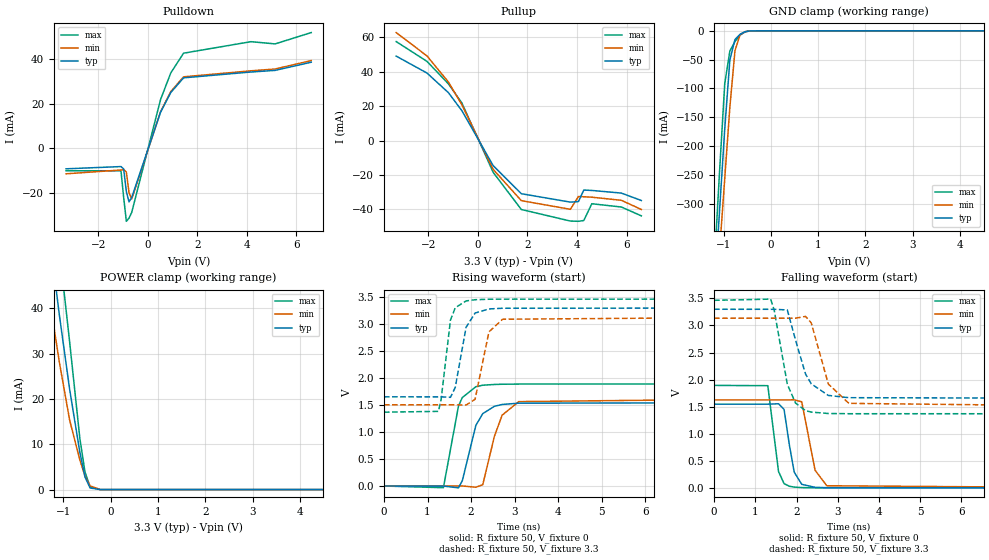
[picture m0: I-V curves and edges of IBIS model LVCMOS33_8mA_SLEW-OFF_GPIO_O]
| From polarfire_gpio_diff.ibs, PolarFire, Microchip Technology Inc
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|   Model LVCMOS33_8mA_SLEW-OFF_GPIO_O
[Model]   LVCMOS33_8mA_SLEW-OFF_GPIO_O
Model_type   Output
Polarity   Non-Inverting
Enable   Active-High
Vmeas =   1.65
Cref =   5p
Rref =   1M
|   typ   min   max
C_comp_pullup   2.605e-12   2.605e-12   2.76e-12
C_comp_pulldown  2.605e-12   2.605e-12   2.76e-12
[Temperature Range]  25C   100C   -40C
[Voltage Range]  3.3   3.135   3.465
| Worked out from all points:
|   slope of the pulldown table from 0 to 0.495 V, typ, clamps not added: 31.7 ohm
|   slope of the pullup table from 0 to 0.495 V, typ, clamps not added: 41.2 ohm
|   GND clamp passes 1 mA (typ) near -0.51 V on its own axis
|   POWER clamp passes 1 mA (typ) near -0.46 V on its own axis
|   rising waveform, R_fixture 50, V_fixture 0: 20-80 % time 318ps typ, 336ps min, 264ps max; typ from 0 V to 1.55 V
|   rising waveform, R_fixture 50, V_fixture 3.3: 20-80 % time 225ps typ, 241ps min, 178ps max; typ from 1.65 V to 3.3 V
|   falling waveform, R_fixture 50, V_fixture 0: 20-80 % time 188ps typ, 224ps min, 151ps max; typ from 1.55 V to 0 V
|   falling waveform, R_fixture 50, V_fixture 3.3: 20-80 % time 392ps typ, 398ps min, 326ps max; typ from 3.3 V to 1.65 V
[GND Clamp]
| Voltage   I(typ)   I(min)   I(max)
-3.3V     -3.213A    -2.957A    -3.541A
-1.191V   -450mA     -505.3mA   -401.1mA
-1.083V   -310.2mA   -380.8mA   -242.7mA
-974.5mV  -170.4mA   -256.4mA   -91.54mA
-866.2mV  -50.48mA   -132.2mA   -34.88mA
-758mV    -15.08mA   -34.24mA   -18.56mA
-649.7mV  -5.883mA   -6.714mA   -7.365mA
-541.4mV  -1.389mA   -1.466mA   -1.709mA
-433.1mV  -123uA     -170uA     -145.5uA
-108.3mV  -6.015nA   -17.98nA   -17.62nA
6.6V      0A         0A         0A
[POWER Clamp]
| Voltage   I(typ)   I(min)   I(max)
-3.3V     320.3mA    266.4mA    379mA
-1.624V   89.11mA    69.3mA     113.8mA
-1.408V   67.23mA    51.37mA    87.82mA
-1.299V   57.08mA    43.14mA    75.67mA
-1.191V   47.51mA    35.38mA    63.94mA
-1.083V   38.51mA    28.09mA    52.96mA
-866.2mV  22.14mA    15.36mA    32.61mA
-649.7mV  8.213mA    6.528mA    11.28mA
-541.4mV  2.791mA    3.019mA    3.88mA
-433.1mV  359.8uA    815.7uA    615.5uA
-216.6mV  159.8nA    4.578uA    2.748uA
6.6V      0A         0A         0A
[Pullup]
| Voltage   I(typ)   I(min)   I(max)
-3.3V     49.01mA    62.7mA     57.45mA
-2.057V   39.19mA    49.12mA    45.97mA
-1.191V   27.78mA    33.97mA    32.88mA
-649.7mV  17.35mA    20.76mA    21.84mA
618.8mV   -14.64mA   -16.83mA   -18.56mA
1.753V    -30.9mA    -34.93mA   -40.07mA
3.733V    -35.78mA   -39.96mA   -46.78mA
4.058V    -35.49mA   -32.52mA   -46.92mA
4.275V    -28.78mA   -32.67mA   -46.46mA
4.599V    -29mA      -32.92mA   -36.72mA
5.79V     -30.53mA   -34.72mA   -38.62mA
6.6V      -34.85mA   -40.05mA   -43.75mA
[Pulldown]
| Voltage   I(typ)   I(min)   I(max)
-3.3V     -9.313mA   -11.56mA   -10.19mA
-1.083V   -8.301mA   -9.851mA   -10.22mA
-974.5mV  -9.371mA   -9.648mA   -22.21mA
-866.2mV  -19.57mA   -10.76mA   -32.96mA
-758mV    -24.21mA   -20.14mA   -31.53mA
-649.7mV  -22.21mA   -22.9mA    -28.95mA
515.6mV   16.17mA    16.44mA    21.91mA
928.1mV   25.06mA    25.48mA    33.89mA
1.444V    31.67mA    32.13mA    42.78mA
4.166V    34.3mA     34.84mA    47.97mA
5.141V    35.03mA    35.65mA    46.96mA
6.6V      38.71mA    39.46mA    52.07mA
[Ramp]
dV/dt_r   0.927342/0.318482n  0.974961/0.335979n  1.13571/0.263616n
dV/dt_f   0.987634/0.391609n  0.977512/0.39781n  1.25749/0.32575n
R_load = 50
[Rising Waveform]
R_fixture = 50
V_fixture = 0
V_fixture_min = 0
V_fixture_max = 0
| Time   V(typ)   V(min)   V(max)
0s        62.35nV    45.17nV    177.2nV
1.365ns   -738.3uV   514.1uV    -30.87mV
1.71ns    -34.06mV   644.1uV    1.48V
1.799ns   99.14mV    677.6uV    1.641V
2.109ns   1.123V     -22.12mV   1.841V
2.268ns   1.342V     23.47mV    1.869V
2.535ns   1.478V     920.8mV    1.883V
2.713ns   1.512V     1.314V     1.887V
3.095ns   1.536V     1.565V     1.89V
10ns      1.546V     1.625V     1.893V
[Rising Waveform]
R_fixture = 50
V_fixture = 3.3
V_fixture_min = 3.135
V_fixture_max = 3.465
| Time   V(typ)   V(min)   V(max)
0s        1.654V     1.506V     1.369V
1.251ns   1.653V     1.505V     1.384V
1.313ns   1.653V     1.505V     1.609V
1.527ns   1.644V     1.505V     3.079V
1.637ns   1.829V     1.505V     3.305V
1.885ns   2.943V     1.501V     3.432V
2.092ns   3.207V     1.608V     3.454V
2.409ns   3.283V     2.857V     3.463V
2.723ns   3.296V     3.092V     3.465V
10ns      3.3V       3.135V     3.465V
[Falling Waveform]
R_fixture = 50
V_fixture = 0
V_fixture_min = 0
V_fixture_max = 0
| Time   V(typ)   V(min)   V(max)
0s        1.546V     1.625V     1.893V
1.304ns   1.546V     1.625V     1.888V
1.563ns   1.554V     1.625V     303.2mV
1.698ns   1.449V     1.625V     78.18mV
1.828ns   786.8mV    1.625V     29.12mV
1.944ns   290.4mV    1.627V     14.71mV
2.127ns   65.05mV    1.59V      5.222mV
2.45ns    10.28mV    325.8mV    1.131mV
2.733ns   2.955mV    38.94mV    638.9uV
10ns      656.8nV    2.264uV    590nV
[Falling Waveform]
R_fixture = 50
V_fixture = 3.3
V_fixture_min = 3.135
V_fixture_max = 3.465
| Time   V(typ)   V(min)   V(max)
0s        3.3V       3.135V     3.465V
1.373ns   3.299V     3.135V     3.487V
1.459ns   3.299V     3.135V     3.281V
1.777ns   3.287V     3.134V     1.914V
1.976ns   2.73V      3.134V     1.567V
2.218ns   2.105V     3.168V     1.427V
2.357ns   1.922V     3.049V     1.4V
2.772ns   1.708V     1.918V     1.374V
3.271ns   1.666V     1.561V     1.37V
10ns      1.654V     1.506V     1.369V
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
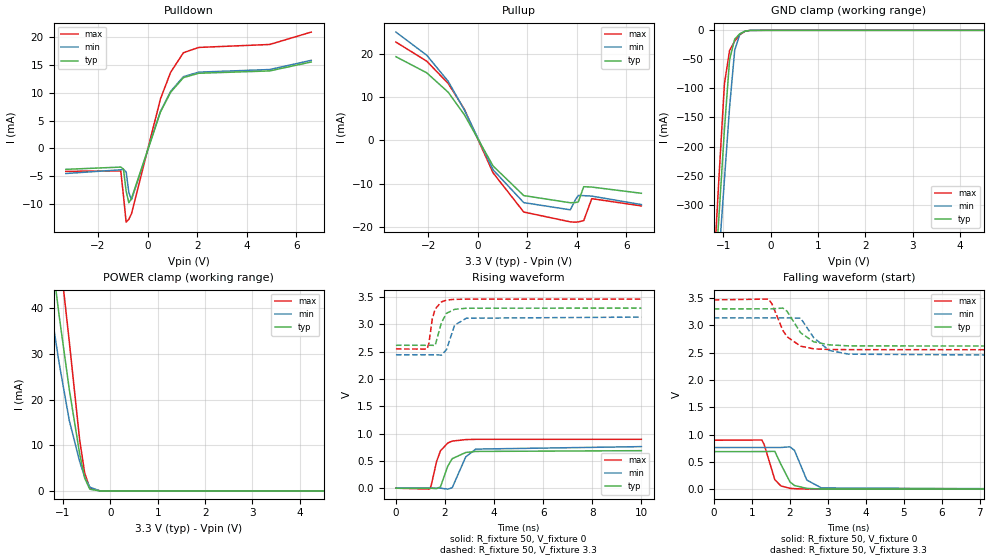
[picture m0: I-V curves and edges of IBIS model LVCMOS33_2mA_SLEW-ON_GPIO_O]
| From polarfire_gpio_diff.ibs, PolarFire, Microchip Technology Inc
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|   Model LVCMOS33_2mA_SLEW-ON_GPIO_O
[Model]   LVCMOS33_2mA_SLEW-ON_GPIO_O
Model_type   Output
Polarity   Non-Inverting
Enable   Active-High
Vmeas =   1.65
Cref =   5p
Rref =   1M
|   typ   min   max
C_comp_pullup   2.605e-12   2.605e-12   2.76e-12
C_comp_pulldown  2.605e-12   2.605e-12   2.76e-12
[Temperature Range]  25C   100C   -40C
[Voltage Range]  3.3   3.135   3.465
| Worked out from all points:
|   slope of the pulldown table from 0 to 0.495 V, typ, clamps not added: 78.7 ohm
|   slope of the pullup table from 0 to 0.495 V, typ, clamps not added: 102 ohm
|   GND clamp passes 1 mA (typ) near -0.51 V on its own axis
|   POWER clamp passes 1 mA (typ) near -0.46 V on its own axis
|   rising waveform, R_fixture 50, V_fixture 0: 20-80 % time 399ps typ, 473ps min, 360ps max; typ from 0 V to 0.688 V
|   rising waveform, R_fixture 50, V_fixture 3.3: 20-80 % time 273ps typ, 326ps min, 232ps max; typ from 2.62 V to 3.3 V
|   falling waveform, R_fixture 50, V_fixture 0: 20-80 % time 283ps typ, 280ps min, 236ps max; typ from 0.688 V to 0 V
|   falling waveform, R_fixture 50, V_fixture 3.3: 20-80 % time 463ps typ, 500ps min, 410ps max; typ from 3.3 V to 2.62 V
[GND Clamp]
| Voltage   I(typ)   I(min)   I(max)
-3.3V     -3.213A    -2.957A    -3.542A
-1.191V   -450mA     -505.3mA   -401.1mA
-1.083V   -310.2mA   -380.8mA   -242.7mA
-974.5mV  -170.4mA   -256.4mA   -91.54mA
-866.2mV  -50.48mA   -132.2mA   -34.88mA
-758mV    -15.08mA   -34.24mA   -18.56mA
-649.7mV  -5.883mA   -6.714mA   -7.365mA
-541.4mV  -1.389mA   -1.466mA   -1.709mA
-433.1mV  -123uA     -170uA     -145.5uA
-108.3mV  -6.015nA   -17.98nA   -17.62nA
6.6V      0A         0A         0A
[POWER Clamp]
| Voltage   I(typ)   I(min)   I(max)
-3.3V     320.3mA    266.4mA    379mA
-1.624V   89.11mA    69.3mA     113.8mA
-1.408V   67.23mA    51.37mA    87.82mA
-1.299V   57.08mA    43.14mA    75.67mA
-1.191V   47.51mA    35.38mA    63.94mA
-1.083V   38.51mA    28.09mA    52.96mA
-866.2mV  22.14mA    15.36mA    32.61mA
-649.7mV  8.213mA    6.528mA    11.28mA
-541.4mV  2.791mA    3.019mA    3.88mA
-433.1mV  359.8uA    815.7uA    615.5uA
-216.6mV  159.8nA    4.578uA    2.748uA
6.6V      0A         0A         0A
[Pullup]
| Voltage   I(typ)   I(min)   I(max)
-3.3V     19.29mA    24.96mA    22.66mA
-2.057V   15.58mA    19.63mA    18.26mA
-1.191V   11.1mA     13.61mA    13.12mA
-541.4mV  5.944mA    7.057mA    7.214mA
618.8mV   -5.885mA   -6.76mA    -7.46mA
1.856V    -12.7mA    -14.32mA   -16.49mA
3.733V    -14.35mA   -15.98mA   -18.75mA
3.95V     -14.29mA   -13.56mA   -18.83mA
4.058V    -14.15mA   -12.66mA   -18.76mA
4.275V    -10.66mA   -12.72mA   -18.48mA
4.599V    -10.74mA   -12.82mA   -13.41mA
6.6V      -12.17mA   -14.77mA   -15.08mA
[Pulldown]
| Voltage   I(typ)   I(min)   I(max)
-3.3V     -3.739mA   -4.486mA   -4.094mA
-1.083V   -3.336mA   -3.821mA   -4.025mA
-974.5mV  -3.682mA   -3.744mA   -8.434mA
-866.2mV  -7.63mA    -4.182mA   -13.21mA
-758mV    -9.724mA   -7.867mA   -12.69mA
-649.7mV  -8.948mA   -9.182mA   -11.69mA
515.6mV   6.515mA    6.609mA    8.847mA
928.1mV   10.07mA    10.23mA    13.65mA
1.444V    12.7mA     12.87mA    17.16mA
2.062V    13.48mA    13.68mA    18.11mA
4.924V    13.9mA     14.15mA    18.64mA
6.6V      15.5mA     15.8mA     20.86mA
[Ramp]
dV/dt_r   0.412647/0.399265n  0.457276/0.472954n  0.537476/0.359539n
dV/dt_f   0.408761/0.462875n  0.413817/0.500078n  0.548246/0.410181n
R_load = 50
[Rising Waveform]
R_fixture = 50
V_fixture = 0
V_fixture_min = 0
V_fixture_max = 0
| Time   V(typ)   V(min)   V(max)
0s        102.4nV    74.63nV    311nV
1.371ns   -716.5uV   730.6uV    -15.41mV
1.436ns   -750.4uV   765.2uV    49.03mV
1.657ns   -7.52mV    883uV      490.1mV
1.816ns   26.15mV    967.7uV    685mV
2.111ns   403.4mV    -17.5mV    827.4mV
2.293ns   541.3mV    8.39mV     863.3mV
2.844ns   654.5mV    573.6mV    890.4mV
3.25ns    673.6mV    716.4mV    895.2mV
10ns      687.7mV    762.1mV    895.8mV
[Rising Waveform]
R_fixture = 50
V_fixture = 3.3
V_fixture_min = 3.135
V_fixture_max = 3.465
| Time   V(typ)   V(min)   V(max)
0s        2.619V     2.445V     2.551V
1.271ns   2.618V     2.445V     2.549V
1.342ns   2.618V     2.445V     2.654V
1.484ns   2.618V     2.445V     3.106V
1.598ns   2.614V     2.445V     3.282V
1.853ns   3.032V     2.438V     3.413V
2.059ns   3.204V     2.537V     3.447V
2.391ns   3.277V     2.987V     3.46V
2.869ns   3.297V     3.114V     3.463V
10ns      3.3V       3.135V     3.465V
[Falling Waveform]
R_fixture = 50
V_fixture = 0
V_fixture_min = 0
V_fixture_max = 0
| Time   V(typ)   V(min)   V(max)
0s        687.8mV    762.1mV    895.8mV
1.265ns   688.1mV    762.7mV    900.6mV
1.326ns   688.1mV    762.7mV    820mV
1.607ns   692.3mV    762.9mV    174.7mV
1.767ns   456mV      762.9mV    59.67mV
2.007ns   133mV      775.3mV    15.15mV
2.126ns   66.81mV    708.9mV    9.027mV
2.45ns    13.8mV     166.7mV    2.02mV
2.835ns   2.742mV    22.68mV    640.7uV
10ns      1.07uV     1.767uV    371nV
[Falling Waveform]
R_fixture = 50
V_fixture = 3.3
V_fixture_min = 3.135
V_fixture_max = 3.465
| Time   V(typ)   V(min)   V(max)
0s        3.3V       3.135V     3.465V
1.446ns   3.301V     3.134V     3.48V
1.537ns   3.301V     3.134V     3.385V
1.819ns   3.315V     3.134V     2.907V
1.929ns   3.258V     3.134V     2.79V
2.287ns   2.863V     3.131V     2.618V
2.629ns   2.698V     2.776V     2.569V
3.034ns   2.642V     2.541V     2.557V
3.555ns   2.623V     2.471V     2.554V
10ns      2.619V     2.445V     2.551V
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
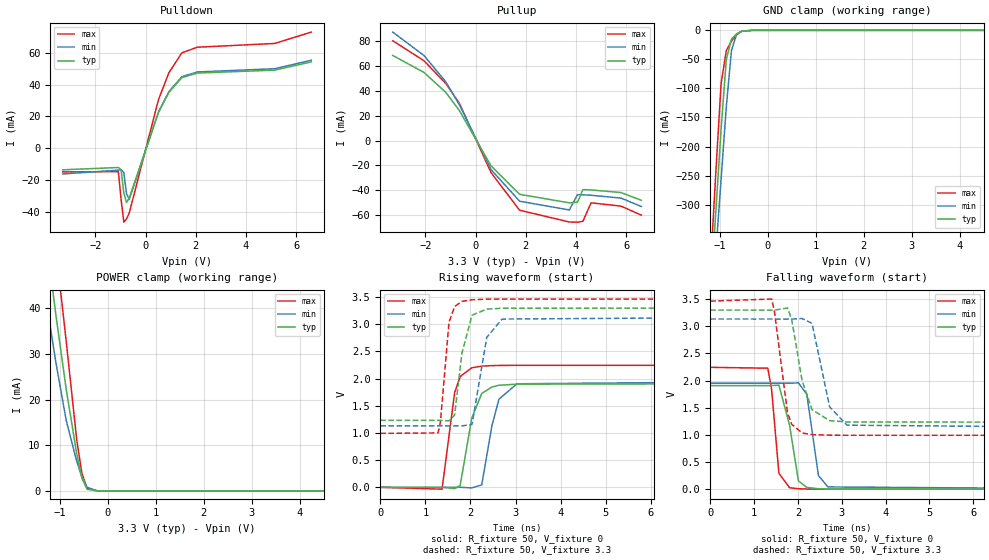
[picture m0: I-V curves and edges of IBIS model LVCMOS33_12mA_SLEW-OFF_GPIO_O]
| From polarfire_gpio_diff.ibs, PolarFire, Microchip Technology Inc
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|   Model LVCMOS33_12mA_SLEW-OFF_GPIO_O
[Model]   LVCMOS33_12mA_SLEW-OFF_GPIO_O
Model_type   Output
Polarity   Non-Inverting
Enable   Active-High
Vmeas =   1.65
Cref =   5p
Rref =   1M
|   typ   min   max
C_comp_pullup   2.605e-12   2.605e-12   2.76e-12
C_comp_pulldown  2.605e-12   2.605e-12   2.76e-12
[Temperature Range]  25C   100C   -40C
[Voltage Range]  3.3   3.135   3.465
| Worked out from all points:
|   slope of the pulldown table from 0 to 0.495 V, typ, clamps not added: 22.7 ohm
|   slope of the pullup table from 0 to 0.495 V, typ, clamps not added: 29.5 ohm
|   GND clamp passes 1 mA (typ) near -0.51 V on its own axis
|   POWER clamp passes 1 mA (typ) near -0.46 V on its own axis
|   rising waveform, R_fixture 50, V_fixture 0: 20-80 % time 270ps typ, 276ps min, 209ps max; typ from 0 V to 1.91 V
|   rising waveform, R_fixture 50, V_fixture 3.3: 20-80 % time 189ps typ, 218ps min, 148ps max; typ from 1.23 V to 3.3 V
|   falling waveform, R_fixture 50, V_fixture 0: 20-80 % time 173ps typ, 186ps min, 132ps max; typ from 1.91 V to 0 V
|   falling waveform, R_fixture 50, V_fixture 3.3: 20-80 % time 308ps typ, 314ps min, 235ps max; typ from 3.3 V to 1.23 V
[GND Clamp]
| Voltage   I(typ)   I(min)   I(max)
-3.3V     -3.213A    -2.957A    -3.541A
-1.191V   -450mA     -505.3mA   -401.1mA
-1.083V   -310.2mA   -380.8mA   -242.7mA
-974.5mV  -170.4mA   -256.4mA   -91.54mA
-866.2mV  -50.48mA   -132.2mA   -34.88mA
-758mV    -15.08mA   -34.24mA   -18.56mA
-649.7mV  -5.883mA   -6.714mA   -7.365mA
-541.4mV  -1.389mA   -1.466mA   -1.709mA
-324.8mV  -3.553uA   -9.504uA   -2.339uA
6.6V      0A         0A         0A
[POWER Clamp]
| Voltage   I(typ)   I(min)   I(max)
-3.3V     320.3mA    266.4mA    379mA
-1.624V   89.11mA    69.3mA     113.8mA
-1.408V   67.23mA    51.37mA    87.82mA
-1.299V   57.08mA    43.14mA    75.67mA
-1.191V   47.51mA    35.38mA    63.94mA
-1.083V   38.51mA    28.09mA    52.96mA
-866.2mV  22.14mA    15.36mA    32.61mA
-649.7mV  8.213mA    6.528mA    11.28mA
-541.4mV  2.791mA    3.019mA    3.88mA
-433.1mV  359.8uA    815.7uA    615.5uA
-216.6mV  159.8nA    4.578uA    2.748uA
6.6V      0A         0A         0A
[Pullup]
| Voltage   I(typ)   I(min)   I(max)
-3.3V     68.42mA    87.18mA    80.23mA
-2.057V   54.76mA    68.39mA    64.18mA
-1.191V   38.81mA    47.31mA    45.9mA
-649.7mV  24.23mA    28.92mA    30.11mA
618.8mV   -20.47mA   -23.48mA   -25.92mA
1.753V    -43.26mA   -48.82mA   -56.06mA
3.733V    -50.12mA   -55.85mA   -65.53mA
4.058V    -49.66mA   -43.55mA   -65.69mA
4.275V    -39.44mA   -43.7mA    -64.96mA
4.599V    -39.74mA   -44.03mA   -50.13mA
5.79V     -41.86mA   -46.3mA    -52.75mA
6.6V      -48.08mA   -53.08mA   -60.03mA
[Pulldown]
| Voltage   I(typ)   I(min)   I(max)
-3.3V     -13.44mA   -16.05mA   -14.79mA
-1.083V   -11.99mA   -13.66mA   -14.59mA
-974.5mV  -13.34mA   -13.38mA   -32.1mA
-866.2mV  -27.94mA   -15.21mA   -46.26mA
-758mV    -33.94mA   -28.44mA   -44.16mA
-649.7mV  -31.06mA   -31.93mA   -40.49mA
515.6mV   22.6mA     22.9mA     30.59mA
928.1mV   35.04mA    35.56mA    47.37mA
1.444V    44.32mA    44.91mA    59.85mA
2.062V    47.18mA    47.87mA    63.37mA
5.141V    49.02mA    49.9mA     65.72mA
6.6V      54.17mA    55.21mA    72.85mA
[Ramp]
dV/dt_r   1.14514/0.269635n  1.17099/0.275885n  1.34717/0.208871n
dV/dt_f   1.2401/0.307596n  1.20209/0.314226n  1.4832/0.235259n
R_load = 50
[Rising Waveform]
R_fixture = 50
V_fixture = 0
V_fixture_min = 0
V_fixture_max = 0
| Time   V(typ)   V(min)   V(max)
0s        49.37nV    35.83nV    137.3nV
1.37ns    745.1uV    596.8uV    -34.01mV
1.65ns    -24.49mV   718.8uV    1.745V
1.772ns   33.39mV    771.9uV    2.037V
2.028ns   1.269V     -10.58mV   2.2V
2.25ns    1.727V     44.1mV     2.231V
2.476ns   1.847V     1.132V     2.24V
2.633ns   1.878V     1.623V     2.243V
3.033ns   1.899V     1.906V     2.245V
10ns      1.909V     1.952V     2.245V
[Rising Waveform]
R_fixture = 50
V_fixture = 3.3
V_fixture_min = 3.135
V_fixture_max = 3.465
| Time   V(typ)   V(min)   V(max)
0s        1.233V     1.132V     993mV
1.281ns   1.233V     1.131V     1.001V
1.334ns   1.233V     1.131V     1.202V
1.524ns   1.223V     1.131V     3.036V
1.649ns   1.33V      1.131V     3.328V
1.811ns   2.47V      1.131V     3.422V
2.035ns   3.168V     1.157V     3.453V
2.363ns   3.28V      2.762V     3.463V
2.703ns   3.296V     3.097V     3.465V
10ns      3.3V       3.135V     3.465V
[Falling Waveform]
R_fixture = 50
V_fixture = 0
V_fixture_min = 0
V_fixture_max = 0
| Time   V(typ)   V(min)   V(max)
0s        1.909V     1.952V     2.245V
1.312ns   1.909V     1.952V     2.229V
1.399ns   1.909V     1.952V     1.841V
1.566ns   1.916V     1.952V     292.3mV
1.809ns   1.18V      1.952V     26.61mV
2.011ns   153.1mV    1.959V     8.174mV
2.202ns   32.84mV    1.749V     2.932mV
2.469ns   7.596mV    249.5mV    774.9uV
2.684ns   2.543mV    41.37mV    448.3uV
10ns      103.8nV    2.746uV    311.7nV
[Falling Waveform]
R_fixture = 50
V_fixture = 3.3
V_fixture_min = 3.135
V_fixture_max = 3.465
| Time   V(typ)   V(min)   V(max)
0s        3.3V       3.135V     3.465V
1.399ns   3.299V     3.135V     3.503V
1.462ns   3.299V     3.135V     3.286V
1.762ns   3.339V     3.134V     1.407V
1.857ns   3.13V      3.134V     1.197V
2.095ns   2V         3.144V     1.035V
2.321ns   1.465V     3.056V     1.005V
2.724ns   1.263V     1.517V     994.6mV
3.12ns    1.238V     1.179V     993.4mV
10ns      1.233V     1.132V     993mV
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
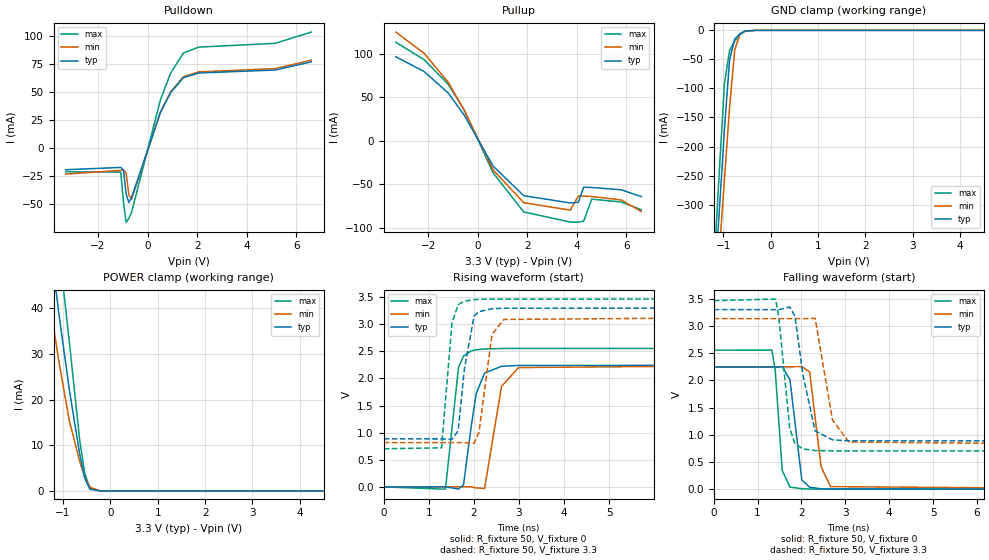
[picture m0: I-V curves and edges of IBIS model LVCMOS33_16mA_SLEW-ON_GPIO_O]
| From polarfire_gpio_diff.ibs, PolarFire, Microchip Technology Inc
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|   Model LVCMOS33_16mA_SLEW-ON_GPIO_O
[Model]   LVCMOS33_16mA_SLEW-ON_GPIO_O
Model_type   Output
Polarity   Non-Inverting
Enable   Active-High
Vmeas =   1.65
Cref =   5p
Rref =   1M
|   typ   min   max
C_comp_pullup   2.605e-12   2.605e-12   2.76e-12
C_comp_pulldown  2.605e-12   2.605e-12   2.76e-12
[Temperature Range]  25C   100C   -40C
[Voltage Range]  3.3   3.135   3.465
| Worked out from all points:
|   slope of the pulldown table from 0 to 0.495 V, typ, clamps not added: 16 ohm
|   slope of the pullup table from 0 to 0.495 V, typ, clamps not added: 20.7 ohm
|   GND clamp passes 1 mA (typ) near -0.51 V on its own axis
|   POWER clamp passes 1 mA (typ) near -0.46 V on its own axis
|   rising waveform, R_fixture 50, V_fixture 0: 20-80 % time 230ps typ, 244ps min, 173ps max; typ from 0 V to 2.25 V
|   rising waveform, R_fixture 50, V_fixture 3.3: 20-80 % time 178ps typ, 209ps min, 135ps max; typ from 0.886 V to 3.3 V
|   falling waveform, R_fixture 50, V_fixture 0: 20-80 % time 161ps typ, 179ps min, 123ps max; typ from 2.25 V to 0 V
|   falling waveform, R_fixture 50, V_fixture 3.3: 20-80 % time 266ps typ, 274ps min, 196ps max; typ from 3.3 V to 0.886 V
[GND Clamp]
| Voltage   I(typ)   I(min)   I(max)
-3.3V     -3.213A    -2.957A    -3.541A
-1.191V   -450mA     -505.3mA   -401.1mA
-1.083V   -310.2mA   -380.8mA   -242.7mA
-974.5mV  -170.4mA   -256.4mA   -91.54mA
-866.2mV  -50.48mA   -132.2mA   -34.88mA
-758mV    -15.08mA   -34.24mA   -18.56mA
-649.7mV  -5.883mA   -6.714mA   -7.365mA
-541.4mV  -1.389mA   -1.466mA   -1.709mA
-324.8mV  -3.553uA   -9.504uA   -2.339uA
6.6V      0A         0A         0A
[POWER Clamp]
| Voltage   I(typ)   I(min)   I(max)
-3.3V     320.3mA    266.4mA    379mA
-1.624V   89.11mA    69.3mA     113.8mA
-1.408V   67.23mA    51.37mA    87.82mA
-1.299V   57.08mA    43.14mA    75.67mA
-1.191V   47.51mA    35.38mA    63.94mA
-1.083V   38.51mA    28.09mA    52.96mA
-866.2mV  22.14mA    15.36mA    32.61mA
-649.7mV  8.213mA    6.528mA    11.28mA
-541.4mV  2.791mA    3.019mA    3.88mA
-433.1mV  359.8uA    815.7uA    615.5uA
-216.6mV  159.8nA    4.578uA    2.748uA
6.6V      0A         0A         0A
[Pullup]
| Voltage   I(typ)   I(min)   I(max)
-3.3V     96.7mA     125.2mA    113.4mA
-2.166V   79.86mA    100.8mA    93.52mA
-1.191V   55.09mA    67.49mA    65.08mA
-541.4mV  29.35mA    34.82mA    35.58mA
618.8mV   -29.1mA    -33.44mA   -36.81mA
1.856V    -63.18mA   -71.27mA   -81.97mA
3.733V    -71.56mA   -79.83mA   -93.56mA
4.058V    -70.72mA   -63.48mA   -93.7mA
4.275V    -53.34mA   -63.65mA   -92.41mA
4.599V    -53.73mA   -64.14mA   -67.18mA
5.79V     -56.41mA   -68.09mA   -70.43mA
6.6V      -64.26mA   -81.41mA   -79.35mA
[Pulldown]
| Voltage   I(typ)   I(min)   I(max)
-3.3V     -18.99mA   -22.92mA   -20.85mA
-1.083V   -16.93mA   -19.5mA    -21.14mA
-974.5mV  -19.39mA   -19.1mA    -48.03mA
-866.2mV  -40.74mA   -22.19mA   -65.83mA
-758mV    -48.24mA   -41.22mA   -62.64mA
-649.7mV  -44.03mA   -45.38mA   -57.29mA
515.6mV   32.05mA    32.51mA    43.27mA
928.1mV   49.81mA    50.58mA    67.21mA
1.444V    63.16mA    64.03mA    85.24mA
2.062V    67.38mA    68.37mA    90.49mA
5.141V    70mA       71.26mA    93.83mA
6.6V      77.31mA    78.8mA     103.9mA
[Ramp]
dV/dt_r   1.34716/0.230165n  1.34924/0.244377n  1.53255/0.172818n
dV/dt_f   1.44849/0.266104n  1.39083/0.274235n  1.6572/0.196047n
R_load = 50
[Rising Waveform]
R_fixture = 50
V_fixture = 0
V_fixture_min = 0
V_fixture_max = 0
| Time   V(typ)   V(min)   V(max)
0s        37.81nV    27.39nV    103.5nV
1.37ns    944.4uV    579.7uV    -42.35mV
1.66ns    -40.3mV    702.3uV    2.201V
1.771ns   37.72mV    749.3uV    2.412V
1.94ns    1.105V     461.7uV    2.508V
2.053ns   1.722V     -18.75mV   2.53V
2.238ns   2.099V     -30.37mV   2.545V
2.615ns   2.224V     1.857V     2.553V
2.994ns   2.24V      2.201V     2.554V
10ns      2.245V     2.249V     2.554V
[Rising Waveform]
R_fixture = 50
V_fixture = 3.3
V_fixture_min = 3.135
V_fixture_max = 3.465
| Time   V(typ)   V(min)   V(max)
0s        885.8mV    817mV      703mV
1.284ns   885.1mV    816.7mV    719.8mV
1.516ns   876.8mV    816.7mV    3.028V
1.653ns   1.035V     816.6mV    3.361V
1.79ns    2.172V     816.6mV    3.427V
2.006ns   3.155V     805.9mV    3.454V
2.113ns   3.232V     1.002V     3.459V
2.403ns   3.287V     2.811V     3.464V
2.666ns   3.296V     3.089V     3.464V
10ns      3.3V       3.135V     3.465V
[Falling Waveform]
R_fixture = 50
V_fixture = 0
V_fixture_min = 0
V_fixture_max = 0
| Time   V(typ)   V(min)   V(max)
0s        2.245V     2.249V     2.554V
1.325ns   2.246V     2.249V     2.556V
1.4ns     2.246V     2.249V     2.196V
1.561ns   2.249V     2.249V     341.9mV
1.737ns   2.011V     2.249V     39.05mV
2.007ns   170.1mV    2.254V     7.105mV
2.186ns   34.86mV    2.154V     2.705mV
2.447ns   7.891mV    411.7mV    568.6uV
2.663ns   2.915mV    47.49mV    552.4uV
10ns      495.6nV    3.025uV    478.9nV
[Falling Waveform]
R_fixture = 50
V_fixture = 3.3
V_fixture_min = 3.135
V_fixture_max = 3.465
| Time   V(typ)   V(min)   V(max)
0s        3.3V       3.135V     3.465V
1.408ns   3.299V     3.134V     3.494V
1.484ns   3.299V     3.134V     3.149V
1.731ns   3.349V     3.134V     1.124V
1.849ns   3.182V     3.134V     836.7mV
2.036ns   2.087V     3.133V     737.9mV
2.311ns   1.072V     3.141V     710.6mV
2.707ns   906.1mV    1.272V     703.9mV
3.078ns   889.6mV    866.7mV    703.1mV
10ns      885.8mV    817mV      703mV
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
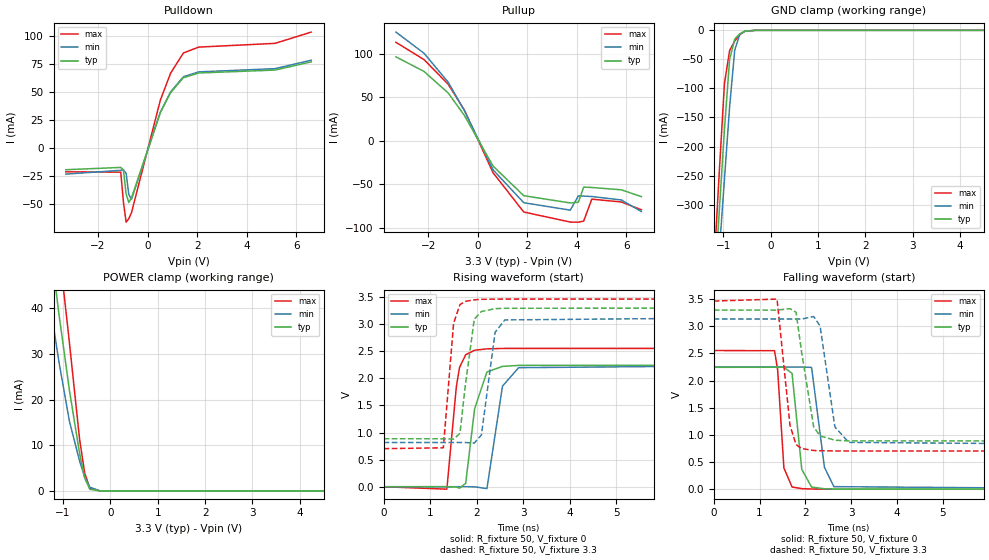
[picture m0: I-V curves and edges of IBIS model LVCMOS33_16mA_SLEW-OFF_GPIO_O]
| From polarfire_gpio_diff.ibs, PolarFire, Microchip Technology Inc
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|   Model LVCMOS33_16mA_SLEW-OFF_GPIO_O
[Model]   LVCMOS33_16mA_SLEW-OFF_GPIO_O
Model_type   Output
Polarity   Non-Inverting
Enable   Active-High
Vmeas =   1.65
Cref =   5p
Rref =   1M
|   typ   min   max
C_comp_pullup   2.605e-12   2.605e-12   2.76e-12
C_comp_pulldown  2.605e-12   2.605e-12   2.76e-12
[Temperature Range]  25C   100C   -40C
[Voltage Range]  3.3   3.135   3.465
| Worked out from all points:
|   slope of the pulldown table from 0 to 0.495 V, typ, clamps not added: 16 ohm
|   slope of the pullup table from 0 to 0.495 V, typ, clamps not added: 20.7 ohm
|   GND clamp passes 1 mA (typ) near -0.51 V on its own axis
|   POWER clamp passes 1 mA (typ) near -0.46 V on its own axis
|   rising waveform, R_fixture 50, V_fixture 0: 20-80 % time 208ps typ, 216ps min, 158ps max; typ from 0 V to 2.25 V
|   rising waveform, R_fixture 50, V_fixture 3.3: 20-80 % time 164ps typ, 192ps min, 123ps max; typ from 0.886 V to 3.3 V
|   falling waveform, R_fixture 50, V_fixture 0: 20-80 % time 144ps typ, 154ps min, 109ps max; typ from 2.25 V to 0 V
|   falling waveform, R_fixture 50, V_fixture 3.3: 20-80 % time 230ps typ, 225ps min, 171ps max; typ from 3.3 V to 0.886 V
[GND Clamp]
| Voltage   I(typ)   I(min)   I(max)
-3.3V     -3.213A    -2.957A    -3.541A
-1.191V   -450mA     -505.3mA   -401.1mA
-1.083V   -310.2mA   -380.8mA   -242.7mA
-974.5mV  -170.4mA   -256.4mA   -91.54mA
-866.2mV  -50.48mA   -132.2mA   -34.88mA
-758mV    -15.08mA   -34.24mA   -18.56mA
-649.7mV  -5.883mA   -6.714mA   -7.365mA
-541.4mV  -1.389mA   -1.466mA   -1.709mA
-324.8mV  -3.553uA   -9.504uA   -2.339uA
6.6V      0A         0A         0A
[POWER Clamp]
| Voltage   I(typ)   I(min)   I(max)
-3.3V     320.3mA    266.4mA    379mA
-1.624V   89.11mA    69.3mA     113.8mA
-1.408V   67.23mA    51.37mA    87.82mA
-1.299V   57.08mA    43.14mA    75.67mA
-1.191V   47.51mA    35.38mA    63.94mA
-1.083V   38.51mA    28.09mA    52.96mA
-866.2mV  22.14mA    15.36mA    32.61mA
-649.7mV  8.213mA    6.528mA    11.28mA
-541.4mV  2.791mA    3.019mA    3.88mA
-433.1mV  359.8uA    815.7uA    615.5uA
-216.6mV  159.8nA    4.578uA    2.748uA
6.6V      0A         0A         0A
[Pullup]
| Voltage   I(typ)   I(min)   I(max)
-3.3V     96.7mA     125.2mA    113.4mA
-2.166V   79.86mA    100.8mA    93.52mA
-1.191V   55.09mA    67.49mA    65.08mA
-541.4mV  29.35mA    34.82mA    35.58mA
618.8mV   -29.1mA    -33.44mA   -36.81mA
1.856V    -63.18mA   -71.27mA   -81.97mA
3.733V    -71.56mA   -79.83mA   -93.56mA
4.058V    -70.72mA   -63.48mA   -93.7mA
4.275V    -53.34mA   -63.65mA   -92.41mA
4.599V    -53.73mA   -64.14mA   -67.18mA
5.79V     -56.41mA   -68.09mA   -70.43mA
6.6V      -64.26mA   -81.41mA   -79.35mA
[Pulldown]
| Voltage   I(typ)   I(min)   I(max)
-3.3V     -18.99mA   -22.92mA   -20.85mA
-1.083V   -16.93mA   -19.5mA    -21.14mA
-974.5mV  -19.39mA   -19.1mA    -48.03mA
-866.2mV  -40.74mA   -22.19mA   -65.83mA
-758mV    -48.24mA   -41.22mA   -62.64mA
-649.7mV  -44.03mA   -45.38mA   -57.29mA
515.6mV   32.05mA    32.51mA    43.27mA
928.1mV   49.81mA    50.58mA    67.21mA
1.444V    63.16mA    64.03mA    85.24mA
2.062V    67.38mA    68.37mA    90.49mA
5.141V    70mA       71.26mA    93.83mA
6.6V      77.31mA    78.8mA     103.9mA
[Ramp]
dV/dt_r   1.34716/0.207758n  1.34924/0.216075n  1.53255/0.157665n
dV/dt_f   1.44849/0.23043n  1.39083/0.225333n  1.6572/0.171415n
R_load = 50
[Rising Waveform]
R_fixture = 50
V_fixture = 0
V_fixture_min = 0
V_fixture_max = 0
| Time   V(typ)   V(min)   V(max)
0s        37.81nV    27.38nV    103.5nV
1.357ns   856uV      527.6uV    -45.04mV
1.561ns   -5.681mV   606.9uV    1.845V
1.629ns   -26.34mV   633.4uV    2.201V
1.762ns   64.19mV    685.1uV    2.437V
1.954ns   1.44V      -1.376mV   2.52V
2.218ns   2.119V     -35.53mV   2.546V
2.552ns   2.222V     1.858V     2.553V
2.899ns   2.24V      2.198V     2.554V
10ns      2.245V     2.249V     2.554V
[Rising Waveform]
R_fixture = 50
V_fixture = 3.3
V_fixture_min = 3.135
V_fixture_max = 3.465
| Time   V(typ)   V(min)   V(max)
0s        885.8mV    817mV      703mV
1.282ns   885.2mV    816.8mV    718.4mV
1.502ns   879.6mV    816.7mV    3.019V
1.639ns   985.8mV    816.7mV    3.363V
1.75ns    1.846V     816.7mV    3.421V
1.947ns   3.094V     806.1mV    3.451V
2.099ns   3.235V     955.3mV    3.46V
2.394ns   3.288V     2.853V     3.464V
2.603ns   3.295V     3.08V      3.465V
10ns      3.3V       3.135V     3.465V
[Falling Waveform]
R_fixture = 50
V_fixture = 0
V_fixture_min = 0
V_fixture_max = 0
| Time   V(typ)   V(min)   V(max)
0s        2.245V     2.249V     2.554V
1.327ns   2.246V     2.249V     2.551V
1.395ns   2.246V     2.249V     2.199V
1.532ns   2.246V     2.249V     391.7mV
1.71ns    2.133V     2.249V     39.3mV
1.922ns   366.7mV    2.249V     9.76mV
2.137ns   38.29mV    2.243V     2.945mV
2.417ns   7.519mV    404mV      672.7uV
2.623ns   2.925mV    46.61mV    547uV
10ns      69.69nV    364nV      208.9nV
[Falling Waveform]
R_fixture = 50
V_fixture = 3.3
V_fixture_min = 3.135
V_fixture_max = 3.465
| Time   V(typ)   V(min)   V(max)
0s        3.3V       3.135V     3.465V
1.382ns   3.299V     3.134V     3.502V
1.666ns   3.325V     3.134V     1.17V
1.798ns   3.257V     3.134V     821.8mV
1.919ns   2.523V     3.134V     748.4mV
2.182ns   1.149V     3.18V      712.9mV
2.322ns   981.6mV    3.008V     707.3mV
2.646ns   901.7mV    1.146V     704.1mV
2.949ns   889.4mV    861.3mV    703.2mV
10ns      885.9mV    817mV      703mV
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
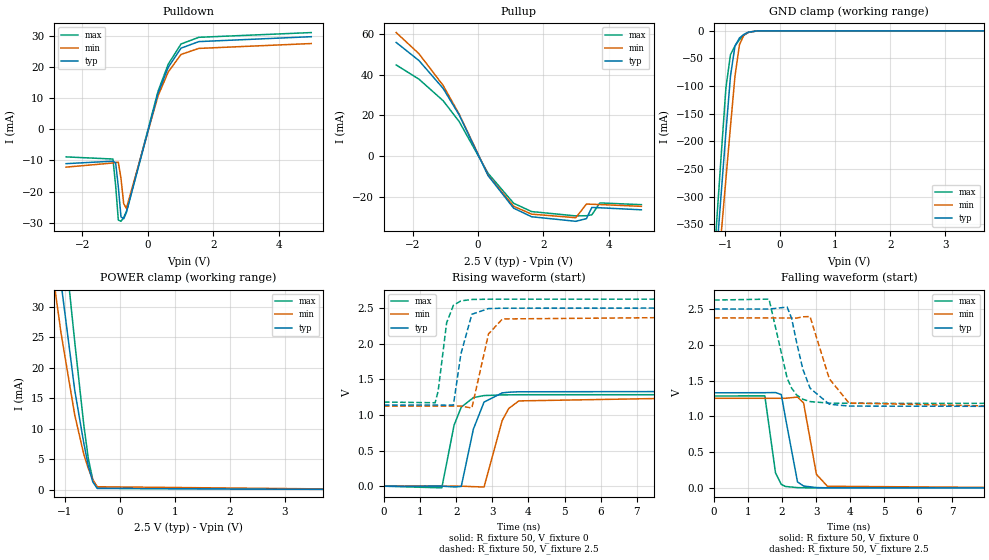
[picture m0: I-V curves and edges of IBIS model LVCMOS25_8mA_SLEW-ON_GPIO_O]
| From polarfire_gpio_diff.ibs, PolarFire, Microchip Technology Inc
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|   Model LVCMOS25_8mA_SLEW-ON_GPIO_O
[Model]   LVCMOS25_8mA_SLEW-ON_GPIO_O
Model_type   Output
Polarity   Non-Inverting
Enable   Active-High
Vmeas =   1.25
Cref =   5p
Rref =   1M
|   typ   min   max
C_comp_pullup   2.605e-12   2.605e-12   2.76e-12
C_comp_pulldown  2.605e-12   2.605e-12   2.76e-12
[Temperature Range]  25C   100C   -40C
[Voltage Range]  2.5   2.375   2.625
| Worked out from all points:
|   slope of the pulldown table from 0 to 0.375 V, typ, clamps not added: 27.6 ohm
|   slope of the pullup table from 0 to 0.375 V, typ, clamps not added: 33.1 ohm
|   GND clamp passes 1 mA (typ) near -0.51 V on its own axis
|   POWER clamp passes 1 mA (typ) near -0.47 V on its own axis
|   rising waveform, R_fixture 50, V_fixture 0: 20-80 % time 368ps typ, 418ps min, 339ps max; typ from 0 V to 1.33 V
|   rising waveform, R_fixture 50, V_fixture 2.5: 20-80 % time 252ps typ, 298ps min, 222ps max; typ from 1.14 V to 2.5 V
|   falling waveform, R_fixture 50, V_fixture 0: 20-80 % time 243ps typ, 266ps min, 193ps max; typ from 1.33 V to 0 V
|   falling waveform, R_fixture 50, V_fixture 2.5: 20-80 % time 455ps typ, 526ps min, 423ps max; typ from 2.5 V to 1.14 V
[GND Clamp]
| Voltage   I(typ)   I(min)   I(max)
-2.5V     -2.154A    -2.019A    -2.334A
-1.23V    -500.9mA   -550.5mA   -458.7mA
-1.148V   -394.9mA   -456.3mA   -338.7mA
-1.066V   -289mA     -362mA     -218.7mA
-984.4mV  -183.1mA   -267.7mA   -102.9mA
-902.3mV  -82.21mA   -173.6mA   -43.25mA
-820.3mV  -27.37mA   -82.26mA   -27.26mA
-738.3mV  -12.87mA   -24.95mA   -16.13mA
-656.2mV  -6.285mA   -7.324mA   -7.886mA
-574.2mV  -2.342mA   -2.429mA   -2.872mA
-410.2mV  -62.85uA   -96.5uA    -70.85uA
5V        0A         0A         0A
[POWER Clamp]
| Voltage   I(typ)   I(min)   I(max)
-2.5V     191.3mA    155.6mA    232.6mA
-1.559V   79.6mA     61.42mA    102.5mA
-1.395V   63.37mA    48.38mA    82.85mA
-1.23V    48.04mA    36.4mA     63.67mA
-1.148V   40.77mA    30.8mA     54.53mA
-1.066V   33.71mA    25.51mA    45.88mA
-820.3mV  16.31mA    12.25mA    24.25mA
-656.2mV  7.665mA    5.818mA    10.67mA
-574.2mV  3.929mA    3.48mA     5.131mA
-492.2mV  1.272mA    1.622mA    1.634mA
-410.2mV  189.8uA    467.6uA    244.4uA
5V        0A         0A         0A
[Pullup]
| Voltage   I(typ)   I(min)   I(max)
-2.5V     55.91mA    60.77mA    44.83mA
-1.805V   47.01mA    50.38mA    37.85mA
-1.066V   33.32mA    34.79mA    27.27mA
-574.2mV  20.24mA    20.66mA    17mA
312.5mV   -9.641mA   -9.429mA   -8.538mA
1.094V    -25.65mA   -24.7mA    -23.22mA
1.641V    -29.85mA   -28.56mA   -27.3mA
2.992V    -32.09mA   -30.33mA   -29.44mA
3.32V     -30.78mA   -23.62mA   -29.34mA
3.484V    -25.28mA   -23.71mA   -28.91mA
3.73V     -25.43mA   -23.85mA   -23.05mA
5V        -26.43mA   -24.73mA   -23.91mA
[Pulldown]
| Voltage   I(typ)   I(min)   I(max)
-2.5V     -11.02mA   -12.14mA   -8.839mA
-1.066V   -10.22mA   -10.81mA   -9.527mA
-984.4mV  -10.71mA   -10.64mA   -18.02mA
-902.3mV  -18.47mA   -10.56mA   -29.2mA
-820.3mV  -28.16mA   -15.77mA   -29.61mA
-738.3mV  -28.81mA   -23.87mA   -28.35mA
-656.2mV  -26.81mA   -25.47mA   -26.55mA
312.5mV   11.69mA    10.82mA    12.3mA
625mV     20.03mA    18.54mA    21.05mA
1.016V    26.23mA    24.21mA    27.58mA
1.562V    28.35mA    26.15mA    29.73mA
5V        29.93mA    27.72mA    31.26mA
[Ramp]
dV/dt_r   0.797444/0.367991n  0.751478/0.418358n  0.77066/0.33857n
dV/dt_f   0.81699/0.454794n  0.750748/0.525515n  0.8661/0.422935n
R_load = 50
[Rising Waveform]
R_fixture = 50
V_fixture = 0
V_fixture_min = 0
V_fixture_max = 0
| Time   V(typ)   V(min)   V(max)
0s        15.23nV    28.08nV    19.41nV
1.602ns   699.1uV    571.7uV    -23.07mV
1.942ns   -10.02mV   693.1uV    855.8mV
2.141ns   -3.195mV   764.1uV    1.11V
2.477ns   801.6mV    -6.38mV    1.243V
2.772ns   1.181V     -10.89mV   1.272V
3.273ns   1.309V     920.4mV    1.281V
3.457ns   1.319V     1.091V     1.282V
3.734ns   1.325V     1.197V     1.284V
10ns      1.329V     1.252V     1.284V
[Rising Waveform]
R_fixture = 50
V_fixture = 2.5
V_fixture_min = 2.375
V_fixture_max = 2.625
| Time   V(typ)   V(min)   V(max)
0s        1.138V     1.124V     1.181V
1.418ns   1.139V     1.124V     1.171V
1.501ns   1.139V     1.124V     1.336V
1.736ns   1.137V     1.125V     2.293V
1.923ns   1.138V     1.125V     2.538V
2.13ns    1.854V     1.125V     2.6V
2.434ns   2.413V     1.097V     2.62V
2.895ns   2.492V     2.136V     2.624V
3.281ns   2.498V     2.347V     2.624V
10ns      2.5V       2.375V     2.625V
[Falling Waveform]
R_fixture = 50
V_fixture = 0
V_fixture_min = 0
V_fixture_max = 0
| Time   V(typ)   V(min)   V(max)
0s        1.329V     1.252V     1.284V
1.493ns   1.33V      1.252V     1.286V
1.807ns   1.332V     1.252V     209.5mV
1.977ns   1.304V     1.252V     48.67mV
2.099ns   981.6mV    1.252V     19.43mV
2.454ns   82.84mV    1.269V     3.208mV
2.633ns   25.59mV    1.186V     1.17mV
3.011ns   4.101mV    189.1mV    455.1uV
3.334ns   995uV      22.19mV    434.1uV
10ns      1.624uV    3.15uV     481.8nV
[Falling Waveform]
R_fixture = 50
V_fixture = 2.5
V_fixture_min = 2.375
V_fixture_max = 2.625
| Time   V(typ)   V(min)   V(max)
0s        2.5V       2.375V     2.625V
1.617ns   2.499V     2.375V     2.638V
2.149ns   2.527V     2.374V     1.533V
2.281ns   2.37V      2.374V     1.394V
2.429ns   2.031V     2.373V     1.298V
2.611ns   1.659V     2.391V     1.239V
2.823ns   1.393V     2.394V     1.206V
3.39ns    1.169V     1.525V     1.184V
3.966ns   1.143V     1.186V     1.182V
10ns      1.138V     1.124V     1.181V
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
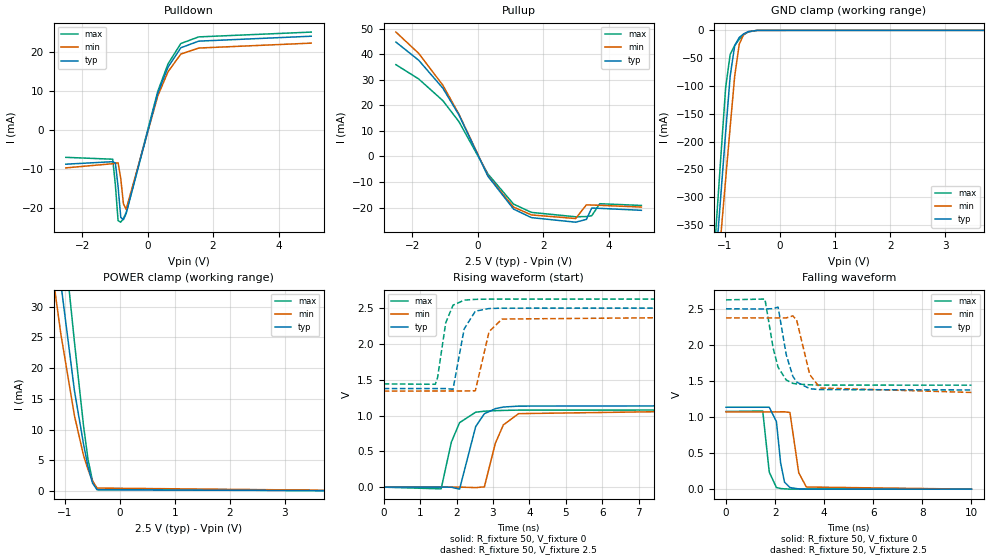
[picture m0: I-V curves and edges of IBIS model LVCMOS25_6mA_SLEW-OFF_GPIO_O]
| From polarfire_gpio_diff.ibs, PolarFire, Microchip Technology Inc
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|   Model LVCMOS25_6mA_SLEW-OFF_GPIO_O
[Model]   LVCMOS25_6mA_SLEW-OFF_GPIO_O
Model_type   Output
Polarity   Non-Inverting
Enable   Active-High
Vmeas =   1.25
Cref =   5p
Rref =   1M
|   typ   min   max
C_comp_pullup   2.605e-12   2.605e-12   2.76e-12
C_comp_pulldown  2.605e-12   2.605e-12   2.76e-12
[Temperature Range]  25C   100C   -40C
[Voltage Range]  2.5   2.375   2.625
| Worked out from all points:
|   slope of the pulldown table from 0 to 0.375 V, typ, clamps not added: 34.4 ohm
|   slope of the pullup table from 0 to 0.375 V, typ, clamps not added: 41.3 ohm
|   GND clamp passes 1 mA (typ) near -0.51 V on its own axis
|   POWER clamp passes 1 mA (typ) near -0.47 V on its own axis
|   rising waveform, R_fixture 50, V_fixture 0: 20-80 % time 362ps typ, 393ps min, 336ps max; typ from 0 V to 1.14 V
|   rising waveform, R_fixture 50, V_fixture 2.5: 20-80 % time 246ps typ, 271ps min, 224ps max; typ from 1.38 V to 2.5 V
|   falling waveform, R_fixture 50, V_fixture 0: 20-80 % time 219ps typ, 261ps min, 181ps max; typ from 1.14 V to 0 V
|   falling waveform, R_fixture 50, V_fixture 2.5: 20-80 % time 404ps typ, 479ps min, 402ps max; typ from 2.5 V to 1.38 V
[GND Clamp]
| Voltage   I(typ)   I(min)   I(max)
-2.5V     -2.154A    -2.019A    -2.334A
-1.23V    -500.9mA   -550.5mA   -458.7mA
-1.148V   -394.9mA   -456.3mA   -338.7mA
-1.066V   -289mA     -362mA     -218.7mA
-984.4mV  -183.1mA   -267.7mA   -102.9mA
-902.3mV  -82.21mA   -173.6mA   -43.25mA
-820.3mV  -27.37mA   -82.26mA   -27.26mA
-738.3mV  -12.87mA   -24.95mA   -16.13mA
-656.2mV  -6.285mA   -7.324mA   -7.886mA
-574.2mV  -2.342mA   -2.429mA   -2.872mA
-410.2mV  -62.85uA   -96.5uA    -70.85uA
5V        0A         0A         0A
[POWER Clamp]
| Voltage   I(typ)   I(min)   I(max)
-2.5V     191.3mA    155.6mA    232.6mA
-1.559V   79.6mA     61.42mA    102.5mA
-1.395V   63.37mA    48.38mA    82.85mA
-1.23V    48.04mA    36.4mA     63.67mA
-1.148V   40.77mA    30.8mA     54.53mA
-1.066V   33.71mA    25.51mA    45.88mA
-820.3mV  16.31mA    12.25mA    24.25mA
-656.2mV  7.665mA    5.818mA    10.67mA
-574.2mV  3.929mA    3.48mA     5.131mA
-492.2mV  1.272mA    1.622mA    1.634mA
-410.2mV  189.8uA    467.6uA    244.4uA
5V        0A         0A         0A
[Pullup]
| Voltage   I(typ)   I(min)   I(max)
-2.5V     44.71mA    48.61mA    35.88mA
-1.805V   37.62mA    40.31mA    30.3mA
-1.066V   26.69mA    27.85mA    21.83mA
-574.2mV  16.22mA    16.54mA    13.61mA
312.5mV   -7.724mA   -7.548mA   -6.839mA
1.094V    -20.54mA   -19.76mA   -18.59mA
1.641V    -23.89mA   -22.83mA   -21.84mA
2.992V    -25.67mA   -24.24mA   -23.56mA
3.32V     -24.58mA   -18.89mA   -23.47mA
3.484V    -20.14mA   -18.97mA   -23.13mA
3.73V     -20.26mA   -19.08mA   -18.45mA
5V        -21.03mA   -19.76mA   -19.13mA
[Pulldown]
| Voltage   I(typ)   I(min)   I(max)
-2.5V     -8.854mA   -9.8mA     -7.096mA
-1.066V   -8.214mA   -8.724mA   -7.575mA
-984.4mV  -8.557mA   -8.59mA    -14.19mA
-902.3mV  -14.63mA   -8.492mA   -23.32mA
-820.3mV  -22.48mA   -12.54mA   -23.72mA
-738.3mV  -23.09mA   -19.05mA   -22.73mA
-656.2mV  -21.5mA    -20.42mA   -21.3mA
312.5mV   9.376mA    8.676mA    9.873mA
625mV     16.05mA    14.86mA    16.88mA
1.016V    21mA       19.38mA    22.09mA
1.562V    22.69mA    20.92mA    23.78mA
5V        23.95mA    22.18mA    25.01mA
[Ramp]
dV/dt_r   0.681422/0.361505n  0.642461/0.392885n  0.646411/0.336262n
dV/dt_f   0.674512/0.404351n  0.620322/0.478582n  0.7101/0.40195n
R_load = 50
[Rising Waveform]
R_fixture = 50
V_fixture = 0
V_fixture_min = 0
V_fixture_max = 0
| Time   V(typ)   V(min)   V(max)
0s        17.65nV    32.42nV    22.54nV
1.577ns   643uV      671uV      -23.86mV
1.858ns   -816.5uV   790.5uV    628.9mV
2.083ns   -28.03mV   886.3uV    900.2mV
2.525ns   845.1mV    -6.49mV    1.046V
2.763ns   1.025V     3.848mV    1.06V
3.065ns   1.096V     612.7mV    1.067V
3.285ns   1.118V     869.5mV    1.071V
3.704ns   1.131V     1.026V     1.075V
10ns      1.136V     1.071V     1.077V
[Rising Waveform]
R_fixture = 50
V_fixture = 2.5
V_fixture_min = 2.375
V_fixture_max = 2.625
| Time   V(typ)   V(min)   V(max)
0s        1.376V     1.341V     1.441V
1.419ns   1.376V     1.342V     1.436V
1.481ns   1.376V     1.342V     1.532V
1.703ns   1.376V     1.342V     2.294V
1.903ns   1.366V     1.342V     2.539V
2.21ns    2.209V     1.342V     2.61V
2.516ns   2.456V     1.345V     2.621V
2.892ns   2.493V     2.17V      2.624V
3.248ns   2.498V     2.346V     2.625V
10ns      2.5V       2.375V     2.625V
[Falling Waveform]
R_fixture = 50
V_fixture = 0
V_fixture_min = 0
V_fixture_max = 0
| Time   V(typ)   V(min)   V(max)
0s        1.136V     1.071V     1.077V
1.495ns   1.136V     1.071V     1.084V
1.761ns   1.136V     1.071V     235.5mV
2.052ns   937.7mV    1.072V     23.51mV
2.225ns   361mV      1.072V     8.759mV
2.382ns   97.14mV    1.073V     4.163mV
2.603ns   22.65mV    1.063V     1.16mV
2.962ns   3.713mV    226.6mV    246.2uV
3.272ns   1.001mV    29.81mV    -27.73uV
10ns      -1.222uV   1.541uV    -154.1nV
[Falling Waveform]
R_fixture = 50
V_fixture = 2.5
V_fixture_min = 2.375
V_fixture_max = 2.625
| Time   V(typ)   V(min)   V(max)
0s        2.5V       2.375V     2.625V
1.584ns   2.499V     2.375V     2.636V
1.92ns    2.503V     2.375V     1.955V
2.12ns    2.524V     2.375V     1.691V
2.453ns   1.864V     2.374V     1.513V
2.722ns   1.565V     2.403V     1.467V
2.877ns   1.485V     2.344V     1.459V
3.411ns   1.393V     1.589V     1.447V
3.831ns   1.38V      1.403V     1.443V
10ns      1.376V     1.341V     1.442V
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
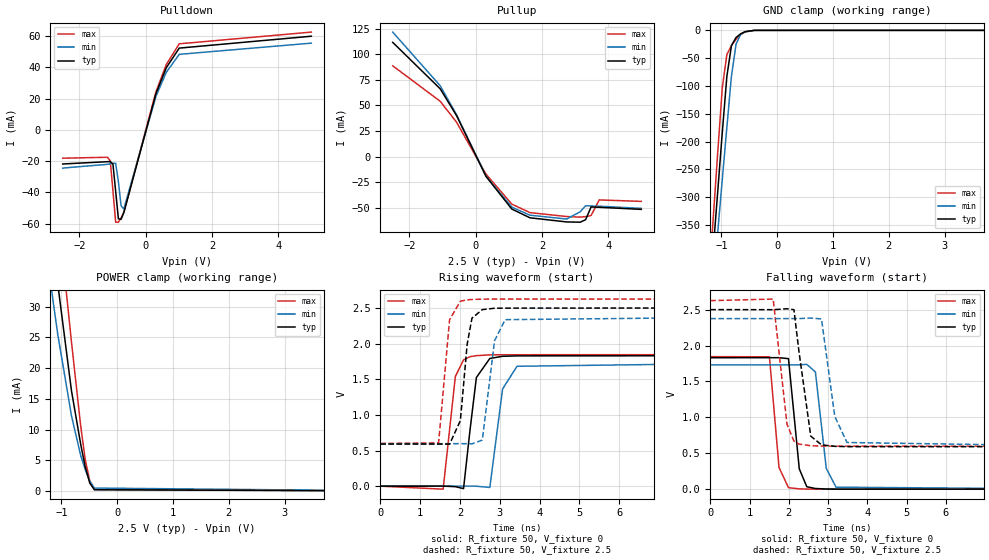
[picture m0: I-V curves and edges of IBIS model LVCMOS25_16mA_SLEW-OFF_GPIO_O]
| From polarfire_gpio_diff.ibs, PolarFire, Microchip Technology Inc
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|   Model LVCMOS25_16mA_SLEW-OFF_GPIO_O
[Model]   LVCMOS25_16mA_SLEW-OFF_GPIO_O
Model_type   Output
Polarity   Non-Inverting
Enable   Active-High
Vmeas =   1.25
Cref =   5p
Rref =   1M
|   typ   min   max
C_comp_pullup   2.605e-12   2.605e-12   2.76e-12
C_comp_pulldown  2.605e-12   2.605e-12   2.76e-12
[Temperature Range]  25C   100C   -40C
[Voltage Range]  2.5   2.375   2.625
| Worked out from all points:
|   slope of the pulldown table from 0 to 0.375 V, typ, clamps not added: 14 ohm
|   slope of the pullup table from 0 to 0.375 V, typ, clamps not added: 16.7 ohm
|   GND clamp passes 1 mA (typ) near -0.51 V on its own axis
|   POWER clamp passes 1 mA (typ) near -0.47 V on its own axis
|   rising waveform, R_fixture 50, V_fixture 0: 20-80 % time 208ps typ, 231ps min, 195ps max; typ from 0 V to 1.83 V
|   rising waveform, R_fixture 50, V_fixture 2.5: 20-80 % time 189ps typ, 222ps min, 152ps max; typ from 0.591 V to 2.5 V
|   falling waveform, R_fixture 50, V_fixture 0: 20-80 % time 151ps typ, 191ps min, 134ps max; typ from 1.83 V to 0 V
|   falling waveform, R_fixture 50, V_fixture 2.5: 20-80 % time 222ps typ, 264ps min, 216ps max; typ from 2.5 V to 0.591 V
[GND Clamp]
| Voltage   I(typ)   I(min)   I(max)
-2.5V     -2.154A    -2.019A    -2.334A
-1.23V    -500.9mA   -550.5mA   -458.7mA
-1.148V   -394.9mA   -456.3mA   -338.7mA
-1.066V   -289mA     -362mA     -218.7mA
-984.4mV  -183.1mA   -267.7mA   -102.9mA
-902.3mV  -82.21mA   -173.6mA   -43.25mA
-820.3mV  -27.37mA   -82.26mA   -27.26mA
-738.3mV  -12.87mA   -24.95mA   -16.13mA
-656.2mV  -6.285mA   -7.324mA   -7.886mA
-574.2mV  -2.342mA   -2.429mA   -2.872mA
-410.2mV  -62.85uA   -96.5uA    -70.85uA
5V        0A         0A         0A
[POWER Clamp]
| Voltage   I(typ)   I(min)   I(max)
-2.5V     191.3mA    155.6mA    232.6mA
-1.559V   79.6mA     61.42mA    102.5mA
-1.395V   63.37mA    48.38mA    82.85mA
-1.23V    48.04mA    36.4mA     63.67mA
-1.148V   40.77mA    30.8mA     54.53mA
-1.066V   33.71mA    25.51mA    45.88mA
-820.3mV  16.31mA    12.25mA    24.25mA
-656.2mV  7.665mA    5.818mA    10.67mA
-574.2mV  3.929mA    3.48mA     5.131mA
-492.2mV  1.272mA    1.622mA    1.634mA
-410.2mV  189.8uA    467.6uA    244.4uA
5V        0A         0A         0A
[Pullup]
| Voltage   I(typ)   I(min)   I(max)
-2.5V     111.6mA    121.6mA    88.7mA
-1.066V   66.19mA    69.19mA    54.05mA
-574.2mV  40.12mA    40.97mA    33.68mA
312.5mV   -19.13mA   -18.73mA   -16.95mA
1.094V    -51.1mA    -49.25mA   -46.28mA
1.641V    -59.61mA   -57.05mA   -54.54mA
2.746V    -63.65mA   -60.83mA   -58.39mA
3.156V    -63.9mA    -53.75mA   -58.96mA
3.32V     -61.47mA   -47.84mA   -58.47mA
3.484V    -49.07mA   -48.02mA   -57.43mA
3.73V     -49.35mA   -48.31mA   -42.17mA
5V        -51.4mA    -50.43mA   -43.6mA
[Pulldown]
| Voltage   I(typ)   I(min)   I(max)
-2.5V     -21.8mA    -24.42mA   -18.1mA
-1.148V   -20.34mA   -22.02mA   -17.51mA
-1.066V   -20.22mA   -21.71mA   -19.77mA
-984.4mV  -21.89mA   -21.38mA   -38.99mA
-902.3mV  -39.28mA   -21.4mA    -58.99mA
-820.3mV  -56.85mA   -33.15mA   -58.99mA
-738.3mV  -57.05mA   -48.61mA   -56.33mA
-656.2mV  -52.91mA   -50.5mA    -52.6mA
312.5mV   23.07mA    21.38mA    24.31mA
625mV     39.7mA     36.79mA    41.76mA
1.016V    52.23mA    48.24mA    54.96mA
5V        59.82mA    55.4mA     62.46mA
[Ramp]
dV/dt_r   1.09823/0.20766n  1.03823/0.23134n  1.10671/0.195016n
dV/dt_f   1.1454/0.222407n  1.06754/0.263716n  1.21584/0.215663n
R_load = 50
[Rising Waveform]
R_fixture = 50
V_fixture = 0
V_fixture_min = 0
V_fixture_max = 0
| Time   V(typ)   V(min)   V(max)
0s        9.068nV    16.86nV    11.45nV
1.578ns   895.9uV    579.7uV    -42.15mV
1.884ns   -7.039mV   692.1uV    1.538V
2.09ns    -34.53mV   767.8uV    1.772V
2.249ns   772.2mV    941.2uV    1.816V
2.412ns   1.524V     -479.7uV   1.831V
2.75ns    1.792V     -17.79mV   1.842V
3.07ns    1.822V     1.364V     1.844V
3.432ns   1.828V     1.682V     1.844V
10ns      1.83V      1.73V      1.845V
[Rising Waveform]
R_fixture = 50
V_fixture = 2.5
V_fixture_min = 2.375
V_fixture_max = 2.625
| Time   V(typ)   V(min)   V(max)
0s        591mV      595.8mV    598.6mV
1.464ns   590.4mV    596.3mV    607.8mV
1.739ns   589.3mV    596.4mV    2.334V
2.01ns    919.2mV    596.5mV    2.595V
2.181ns   1.992V     596.5mV    2.614V
2.301ns   2.357V     593mV      2.619V
2.561ns   2.477V     647.4mV    2.624V
2.869ns   2.496V     2.042V     2.625V
3.135ns   2.498V     2.336V     2.625V
10ns      2.5V       2.375V     2.625V
[Falling Waveform]
R_fixture = 50
V_fixture = 0
V_fixture_min = 0
V_fixture_max = 0
| Time   V(typ)   V(min)   V(max)
0s        1.83V      1.73V      1.845V
1.507ns   1.831V     1.731V     1.843V
1.751ns   1.831V     1.731V     302.8mV
1.992ns   1.817V     1.731V     20.74mV
2.267ns   283.7mV    1.731V     4.118mV
2.459ns   33.44mV    1.738V     1.422mV
2.678ns   9.249mV    1.632V     602.4uV
2.954ns   2.254mV    291.2mV    109.7uV
3.203ns   732.9uV    27.56mV    105.9uV
10ns      1.331uV    4.898uV    640.4nV
[Falling Waveform]
R_fixture = 50
V_fixture = 2.5
V_fixture_min = 2.375
V_fixture_max = 2.625
| Time   V(typ)   V(min)   V(max)
0s        2.5V       2.375V     2.625V
1.602ns   2.499V     2.375V     2.647V
1.954ns   2.512V     2.375V     903.9mV
2.131ns   2.499V     2.375V     669.2mV
2.258ns   1.92V      2.375V     627.9mV
2.56ns    737.9mV    2.383V     604.8mV
2.833ns   617.5mV    2.37V      600.3mV
3.171ns   596mV      1.013V     598.7mV
3.483ns   592.4mV    649.7mV    598.7mV
10ns      591mV      595.8mV    598.6mV
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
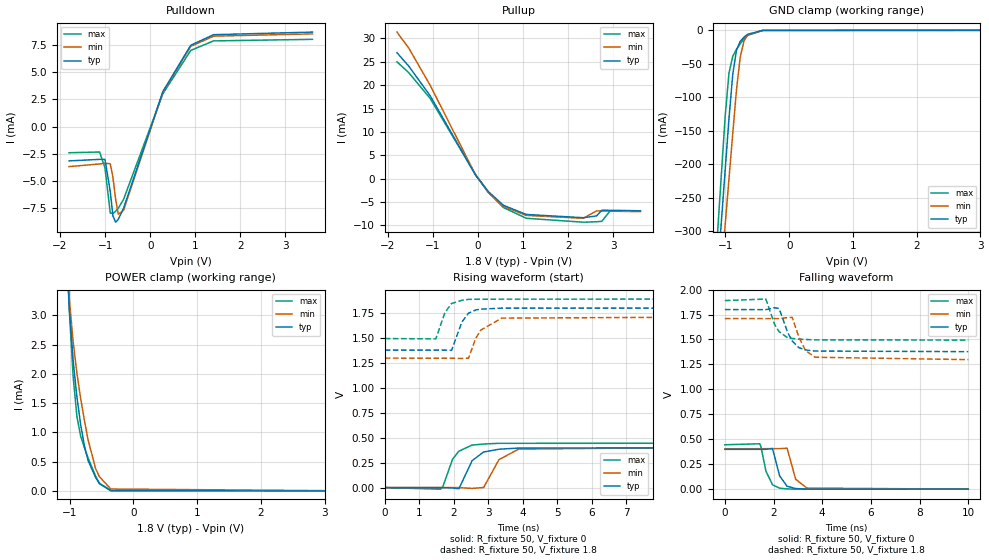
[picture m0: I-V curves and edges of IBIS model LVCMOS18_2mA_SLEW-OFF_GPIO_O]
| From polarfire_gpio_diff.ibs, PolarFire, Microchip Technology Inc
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|   Model LVCMOS18_2mA_SLEW-OFF_GPIO_O
[Model]   LVCMOS18_2mA_SLEW-OFF_GPIO_O
Model_type   Output
Polarity   Non-Inverting
Enable   Active-High
Vmeas =   0.9
Cref =   5p
Rref =   1M
|   typ   min   max
C_comp_pullup   2.605e-12   2.605e-12   2.76e-12
C_comp_pulldown  2.605e-12   2.605e-12   2.76e-12
[Temperature Range]  25C   100C   -40C
[Voltage Range]  1.8   1.71   1.89
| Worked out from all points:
|   slope of the pulldown table from 0 to 0.27 V, typ, clamps not added: 86.6 ohm
|   slope of the pullup table from 0 to 0.27 V, typ, clamps not added: 84.3 ohm
|   GND clamp passes 1 mA (typ) near -0.52 V on its own axis
|   POWER clamp passes 1 mA (typ) near -0.81 V on its own axis
|   rising waveform, R_fixture 50, V_fixture 0: 20-80 % time 398ps typ, 459ps min, 354ps max; typ from 0 V to 0.399 V
|   rising waveform, R_fixture 50, V_fixture 1.8: 20-80 % time 285ps typ, 386ps min, 256ps max; typ from 1.38 V to 1.8 V
|   falling waveform, R_fixture 50, V_fixture 0: 20-80 % time 308ps typ, 289ps min, 293ps max; typ from 0.399 V to 0 V
|   falling waveform, R_fixture 50, V_fixture 1.8: 20-80 % time 445ps typ, 447ps min, 414ps max; typ from 1.8 V to 1.38 V
[GND Clamp]
| Voltage   I(typ)   I(min)   I(max)
-1.8V     -1.238A    -1.206A    -1.294A
-1.122V   -361mA     -426.1mA   -300.3mA
-1.063V   -284.7mA   -358.2mA   -213.9mA
-1.004V   -208.5mA   -290.3mA   -128.4mA
-945mV    -132.4mA   -222.5mA   -64.19mA
-885.9mV  -66.33mA   -154.7mA   -38.94mA
-826.9mV  -29.63mA   -88.81mA   -28.27mA
-767.8mV  -16.36mA   -39.95mA   -19.83mA
-708.7mV  -10.12mA   -15.57mA   -12.8mA
-649.7mV  -5.882mA   -6.713mA   -7.364mA
-413.4mV  -69.42uA   -104.8uA   -78.93uA
3.6V      0A         0A         0A
[POWER Clamp]
| Voltage   I(typ)   I(min)   I(max)
-1.8V     45.61mA    35.66mA    60.31mA
-1.063V   4.301mA    4.234mA    4.672mA
-1.004V   3.099mA    3.258mA    3.078mA
-945mV    2.226mA    2.547mA    1.95mA
-885.9mV  1.604mA    2.011mA    1.273mA
-826.9mV  1.131mA    1.577mA    934uA
-767.8mV  765.5uA    1.2mA      735.6uA
-708.7mV  512.4uA    863.2uA    558uA
-590.6mV  225.1uA    373.6uA    248.4uA
-531.6mV  123.5uA    241.6uA    129.3uA
-354.4mV  2.157uA    32.55uA    10.61uA
3.6V      0A         0A         0A
[Pullup]
| Voltage   I(typ)   I(min)   I(max)
-1.8V     26.94mA    31.34mA    24.99mA
-1.536V   24.03mA    27.88mA    22.64mA
-1.063V   17.72mA    19.96mA    17.15mA
-59.06mV  811.8uA    870.2uA    898.3uA
225mV     -2.733mA   -2.87mA    -2.915mA
562.5mV   -5.692mA   -5.919mA   -6.171mA
1.069V    -7.641mA   -7.848mA   -8.457mA
2.332V    -8.336mA   -8.464mA   -9.295mA
2.627V    -7.955mA   -6.878mA   -9.207mA
2.745V    -6.743mA   -6.899mA   -9.11mA
2.922V    -6.745mA   -6.932mA   -6.955mA
3.6V      -6.855mA   -7.044mA   -6.93mA
[Pulldown]
| Voltage   I(typ)   I(min)   I(max)
-1.8V     -3.136mA   -3.659mA   -2.386mA
-1.122V   -2.994mA   -3.416mA   -2.32mA
-1.004V   -2.993mA   -3.345mA   -3.773mA
-885.9mV  -5.948mA   -3.405mA   -7.916mA
-826.9mV  -8.174mA   -4.653mA   -7.96mA
-767.8mV  -8.76mA    -6.629mA   -7.757mA
-708.7mV  -8.503mA   -8.033mA   -7.473mA
-590.6mV  -7.483mA   -7.679mA   -6.66mA
281.2mV   3.23mA     3.185mA    3.035mA
900mV     7.483mA    7.374mA    7.005mA
1.406V    8.448mA    8.311mA    7.878mA
3.6V      8.686mA    8.523mA    8.021mA
[Ramp]
dV/dt_r   0.239231/0.397911n  0.243089/0.458526n  0.26686/0.35441n
dV/dt_f   0.252982/0.445005n  0.247277/0.446546n  0.237303/0.41355n
R_load = 50
[Rising Waveform]
R_fixture = 50
V_fixture = 0
V_fixture_min = 0
V_fixture_max = 0
| Time   V(typ)   V(min)   V(max)
0s        25.24nV    34.73nV    34.35nV
1.622ns   -350.8uV   -88.94uV   -15.87mV
1.688ns   -365uV     -92.56uV   13.18mV
1.966ns   -3.836mV   -107.8uV   284.7mV
2.149ns   -11.92mV   -117.8uV   365mV
2.533ns   270mV      -8.234mV   426.4mV
2.867ns   356.9mV    879.9uV    436.6mV
3.311ns   384.8mV    280mV      443.9mV
3.883ns   396.1mV    385.9mV    443.9mV
10ns      398.7mV    405.1mV    444.8mV
[Rising Waveform]
R_fixture = 50
V_fixture = 1.8
V_fixture_min = 1.71
V_fixture_max = 1.89
| Time   V(typ)   V(min)   V(max)
0s        1.378V     1.298V     1.494V
1.48ns    1.378V     1.297V     1.491V
1.745ns   1.378V     1.297V     1.756V
1.936ns   1.376V     1.297V     1.845V
2.236ns   1.66V      1.294V     1.878V
2.429ns   1.749V     1.297V     1.887V
2.638ns   1.781V     1.496V     1.888V
2.783ns   1.789V     1.579V     1.888V
3.391ns   1.799V     1.699V     1.889V
10ns      1.8V       1.71V      1.89V
[Falling Waveform]
R_fixture = 50
V_fixture = 0
V_fixture_min = 0
V_fixture_max = 0
| Time   V(typ)   V(min)   V(max)
0s        398.7mV    405.1mV    444.8mV
1.43ns    399mV      405.6mV    454.9mV
1.481ns   399.1mV    405.6mV    426.6mV
1.688ns   399.1mV    405.6mV    180.2mV
1.958ns   407.7mV    405.7mV    43.6mV
2.25ns    132.8mV    405.8mV    9.79mV
2.556ns   29.02mV    410.5mV    2.135mV
2.909ns   5.96mV     98.94mV    742.4uV
3.37ns    987uV      10.82mV    -134.8uV
10ns      1.026uV    3.958uV    788.4nV
[Falling Waveform]
R_fixture = 50
V_fixture = 1.8
V_fixture_min = 1.71
V_fixture_max = 1.89
| Time   V(typ)   V(min)   V(max)
0s        1.8V       1.71V      1.89V
1.683ns   1.799V     1.709V     1.905V
2.05ns    1.818V     1.709V     1.647V
2.229ns   1.81V      1.709V     1.578V
2.589ns   1.566V     1.72V      1.515V
2.768ns   1.484V     1.721V     1.51V
3.044ns   1.418V     1.522V     1.503V
3.314ns   1.395V     1.389V     1.5V
3.708ns   1.384V     1.322V     1.496V
10ns      1.378V     1.298V     1.494V
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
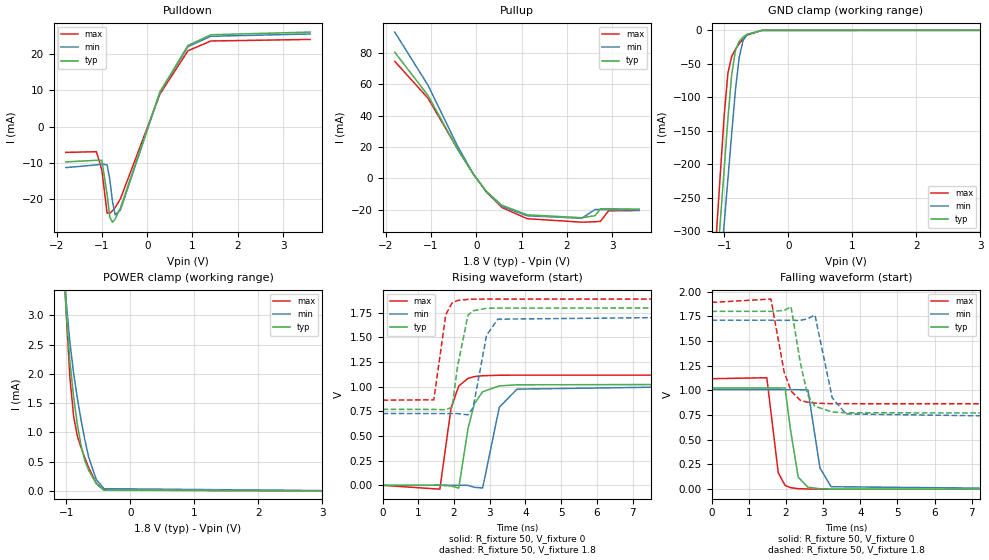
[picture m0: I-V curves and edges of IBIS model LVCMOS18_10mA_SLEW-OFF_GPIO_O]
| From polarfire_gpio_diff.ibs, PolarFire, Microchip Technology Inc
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|   Model LVCMOS18_10mA_SLEW-OFF_GPIO_O
[Model]   LVCMOS18_10mA_SLEW-OFF_GPIO_O
Model_type   Output
Polarity   Non-Inverting
Enable   Active-High
Vmeas =   0.9
Cref =   5p
Rref =   1M
|   typ   min   max
C_comp_pullup   2.605e-12   2.605e-12   2.76e-12
C_comp_pulldown  2.605e-12   2.605e-12   2.76e-12
[Temperature Range]  25C   100C   -40C
[Voltage Range]  1.8   1.71   1.89
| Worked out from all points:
|   slope of the pulldown table from 0 to 0.27 V, typ, clamps not added: 29.1 ohm
|   slope of the pullup table from 0 to 0.27 V, typ, clamps not added: 28.3 ohm
|   GND clamp passes 1 mA (typ) near -0.52 V on its own axis
|   POWER clamp passes 1 mA (typ) near -0.81 V on its own axis
|   rising waveform, R_fixture 50, V_fixture 0: 20-80 % time 323ps typ, 360ps min, 278ps max; typ from 0 V to 1.02 V
|   rising waveform, R_fixture 50, V_fixture 1.8: 20-80 % time 238ps typ, 303ps min, 207ps max; typ from 0.77 V to 1.8 V
|   falling waveform, R_fixture 50, V_fixture 0: 20-80 % time 217ps typ, 242ps min, 189ps max; typ from 1.02 V to 0 V
|   falling waveform, R_fixture 50, V_fixture 1.8: 20-80 % time 304ps typ, 318ps min, 317ps max; typ from 1.8 V to 0.77 V
[GND Clamp]
| Voltage   I(typ)   I(min)   I(max)
-1.8V     -1.238A    -1.206A    -1.294A
-1.122V   -361mA     -426.1mA   -300.3mA
-1.063V   -284.7mA   -358.2mA   -213.9mA
-1.004V   -208.5mA   -290.3mA   -128.4mA
-945mV    -132.4mA   -222.5mA   -64.19mA
-885.9mV  -66.33mA   -154.7mA   -38.94mA
-826.9mV  -29.63mA   -88.81mA   -28.27mA
-767.8mV  -16.36mA   -39.95mA   -19.83mA
-708.7mV  -10.12mA   -15.57mA   -12.8mA
-649.7mV  -5.882mA   -6.713mA   -7.364mA
-413.4mV  -69.42uA   -104.8uA   -78.93uA
3.6V      0A         0A         0A
[POWER Clamp]
| Voltage   I(typ)   I(min)   I(max)
-1.8V     45.61mA    35.66mA    60.31mA
-1.063V   4.301mA    4.234mA    4.672mA
-1.004V   3.099mA    3.258mA    3.078mA
-945mV    2.226mA    2.547mA    1.95mA
-885.9mV  1.604mA    2.011mA    1.273mA
-826.9mV  1.131mA    1.577mA    934uA
-767.8mV  765.5uA    1.2mA      735.6uA
-708.7mV  512.4uA    863.2uA    558uA
-649.7mV  349.8uA    570.8uA    394.2uA
-531.6mV  123.5uA    194.8uA    129.3uA
-413.4mV  12.94uA    38.41uA    15.1uA
3.6V      0A         0A         0A
[Pullup]
| Voltage   I(typ)   I(min)   I(max)
-1.8V     80.37mA    93.19mA    74.58mA
-1.063V   52.72mA    59.19mA    51.01mA
-413.4mV  18.71mA    20.66mA    18.8mA
-59.06mV  2.417mA    2.58mA     2.632mA
225mV     -8.15mA    -8.548mA   -8.672mA
562.5mV   -17.01mA   -17.67mA   -18.4mA
1.125V    -23.14mA   -23.74mA   -25.6mA
2.332V    -24.99mA   -25.33mA   -27.83mA
2.627V    -23.66mA   -19.71mA   -27.55mA
2.745V    -19.31mA   -19.76mA   -27.26mA
2.922V    -19.24mA   -19.86mA   -20.56mA
3.6V      -19.54mA   -20.17mA   -20.4mA
[Pulldown]
| Voltage   I(typ)   I(min)   I(max)
-1.8V     -9.669mA   -11.24mA   -7.052mA
-1.122V   -9.224mA   -10.49mA   -6.857mA
-1.004V   -9.213mA   -10.27mA   -11.82mA
-885.9mV  -18.63mA   -10.47mA   -23.78mA
-826.9mV  -24.92mA   -14.49mA   -23.78mA
-767.8mV  -26.27mA   -20.48mA   -23.14mA
-708.7mV  -25.4mA    -24.27mA   -22.27mA
-590.6mV  -22.29mA   -22.87mA   -19.8mA
281.2mV   9.622mA    9.483mA    9.022mA
900mV     22.39mA    22.06mA    20.94mA
1.406V    25.34mA    24.92mA    23.63mA
3.6V      26.08mA    25.57mA    24.06mA
[Ramp]
dV/dt_r   0.614657/0.323286n  0.604784/0.359864n  0.670884/0.278093n
dV/dt_f   0.617746/0.30398n  0.589098/0.318321n  0.615505/0.316641n
R_load = 50
[Rising Waveform]
R_fixture = 50
V_fixture = 0
V_fixture_min = 0
V_fixture_max = 0
| Time   V(typ)   V(min)   V(max)
0s        14.06nV    19.43nV    19.49nV
1.604ns   784.4uV    680.8uV    -39.18mV
1.92ns    -6.863mV   814.9uV    788.9mV
2.133ns   -28.21mV   905.3uV    1.007V
2.394ns   578.9mV    -684.1uV   1.086V
2.571ns   828.2mV    -20.2mV    1.103V
2.802ns   949.5mV    -27.43mV   1.112V
3.268ns   1.009V     791.8mV    1.117V
3.763ns   1.02V      975.9mV    1.118V
10ns      1.024V     1.008V     1.118V
[Rising Waveform]
R_fixture = 50
V_fixture = 1.8
V_fixture_min = 1.71
V_fixture_max = 1.89
| Time   V(typ)   V(min)   V(max)
0s        770.4mV    728.2mV    864.2mV
1.435ns   770mV      727.7mV    867.3mV
1.771ns   766.8mV    727.6mV    1.733V
1.947ns   793.4mV    727.6mV    1.851V
2.099ns   1.206V     727.5mV    1.876V
2.392ns   1.728V     715.2mV    1.887V
2.537ns   1.771V     788.6mV    1.889V
2.911ns   1.796V     1.523V     1.89V
3.226ns   1.798V     1.686V     1.89V
10ns      1.8V       1.71V      1.89V
[Falling Waveform]
R_fixture = 50
V_fixture = 0
V_fixture_min = 0
V_fixture_max = 0
| Time   V(typ)   V(min)   V(max)
0s        1.024V     1.008V     1.118V
1.486ns   1.024V     1.007V     1.128V
1.793ns   1.024V     1.007V     167.6mV
1.976ns   1.025V     1.007V     38.66mV
2.123ns   601.2mV    1.007V     15.27mV
2.33ns    122mV      1.007V     5.089mV
2.592ns   19.3mV     1.005V     1.676mV
2.916ns   4.136mV    213.9mV    647uV
3.216ns   1.354mV    25.07mV    619.7uV
10ns      755.1nV    2.321uV    642.4nV
[Falling Waveform]
R_fixture = 50
V_fixture = 1.8
V_fixture_min = 1.71
V_fixture_max = 1.89
| Time   V(typ)   V(min)   V(max)
0s        1.8V       1.71V      1.89V
1.596ns   1.8V       1.71V      1.924V
1.954ns   1.809V     1.709V     1.183V
2.138ns   1.847V     1.709V     993.8mV
2.386ns   1.281V     1.708V     899.5mV
2.579ns   959.8mV    1.724V     879.9mV
2.78ns    839.2mV    1.763V     870.7mV
3.245ns   780.4mV    925.3mV    864.9mV
3.616ns   773.2mV    761.3mV    864.8mV
10ns      770.4mV    728.2mV    864.2mV
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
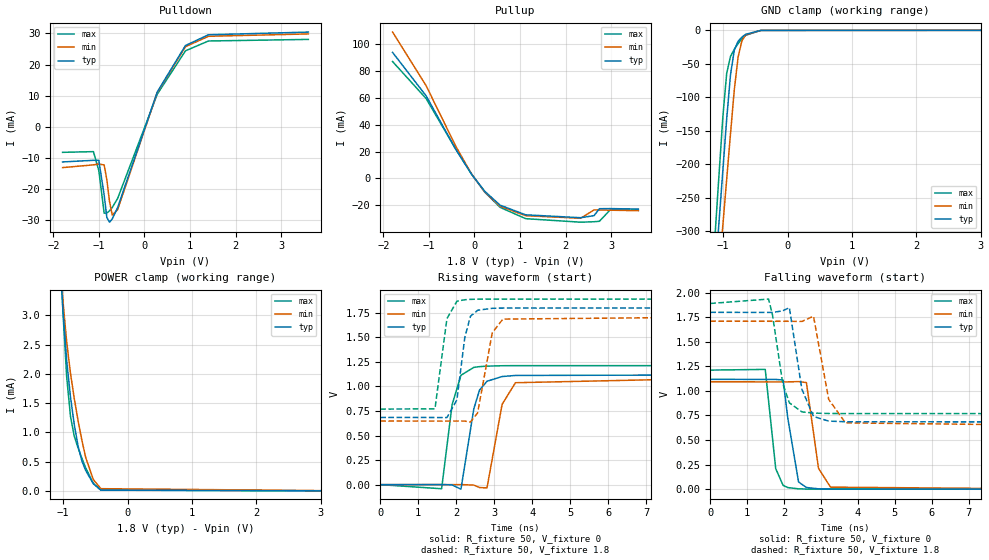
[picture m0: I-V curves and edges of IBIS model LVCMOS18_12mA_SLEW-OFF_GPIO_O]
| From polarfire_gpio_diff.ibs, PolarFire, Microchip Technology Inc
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|   Model LVCMOS18_12mA_SLEW-OFF_GPIO_O
[Model]   LVCMOS18_12mA_SLEW-OFF_GPIO_O
Model_type   Output
Polarity   Non-Inverting
Enable   Active-High
Vmeas =   0.9
Cref =   5p
Rref =   1M
|   typ   min   max
C_comp_pullup   2.605e-12   2.605e-12   2.76e-12
C_comp_pulldown  2.605e-12   2.605e-12   2.76e-12
[Temperature Range]  25C   100C   -40C
[Voltage Range]  1.8   1.71   1.89
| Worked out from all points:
|   slope of the pulldown table from 0 to 0.27 V, typ, clamps not added: 25 ohm
|   slope of the pullup table from 0 to 0.27 V, typ, clamps not added: 24.2 ohm
|   GND clamp passes 1 mA (typ) near -0.52 V on its own axis
|   POWER clamp passes 1 mA (typ) near -0.81 V on its own axis
|   rising waveform, R_fixture 50, V_fixture 0: 20-80 % time 301ps typ, 324ps min, 256ps max; typ from 0 V to 1.12 V
|   rising waveform, R_fixture 50, V_fixture 1.8: 20-80 % time 230ps typ, 292ps min, 197ps max; typ from 0.684 V to 1.8 V
|   falling waveform, R_fixture 50, V_fixture 0: 20-80 % time 217ps typ, 237ps min, 184ps max; typ from 1.12 V to 0 V
|   falling waveform, R_fixture 50, V_fixture 1.8: 20-80 % time 283ps typ, 317ps min, 292ps max; typ from 1.8 V to 0.684 V
[GND Clamp]
| Voltage   I(typ)   I(min)   I(max)
-1.8V     -1.238A    -1.206A    -1.294A
-1.122V   -361mA     -426.1mA   -300.3mA
-1.063V   -284.7mA   -358.2mA   -213.9mA
-1.004V   -208.5mA   -290.3mA   -128.4mA
-945mV    -132.4mA   -222.5mA   -64.19mA
-885.9mV  -66.33mA   -154.7mA   -38.94mA
-826.9mV  -29.63mA   -88.81mA   -28.27mA
-767.8mV  -16.36mA   -39.95mA   -19.83mA
-708.7mV  -10.12mA   -15.57mA   -12.8mA
-649.7mV  -5.882mA   -6.713mA   -7.364mA
-413.4mV  -69.42uA   -104.8uA   -78.93uA
3.6V      0A         0A         0A
[POWER Clamp]
| Voltage   I(typ)   I(min)   I(max)
-1.8V     45.61mA    35.66mA    60.31mA
-1.063V   4.301mA    4.234mA    4.672mA
-1.004V   3.099mA    3.258mA    3.078mA
-945mV    2.226mA    2.547mA    1.95mA
-885.9mV  1.604mA    2.011mA    1.273mA
-826.9mV  1.131mA    1.577mA    934uA
-767.8mV  765.5uA    1.2mA      735.6uA
-708.7mV  512.4uA    863.2uA    558uA
-649.7mV  349.8uA    570.8uA    394.2uA
-531.6mV  123.5uA    194.8uA    129.3uA
-413.4mV  12.94uA    38.41uA    15.1uA
3.6V      0A         0A         0A
[Pullup]
| Voltage   I(typ)   I(min)   I(max)
-1.8V     93.7mA     108.8mA    86.91mA
-1.063V   61.42mA    68.99mA    59.41mA
-413.4mV  21.79mA    24.07mA    21.89mA
-59.06mV  2.816mA    3.011mA    3.066mA
225mV     -9.5mA     -9.956mA   -10.11mA
562.5mV   -19.84mA   -20.6mA    -21.46mA
1.125V    -27.01mA   -27.68mA   -29.88mA
2.332V    -29.17mA   -29.56mA   -32.49mA
2.627V    -27.62mA   -23.36mA   -32.15mA
2.745V    -22.47mA   -23.43mA   -31.81mA
2.981V    -22.39mA   -23.58mA   -23.36mA
3.6V      -22.71mA   -23.92mA   -23.66mA
[Pulldown]
| Voltage   I(typ)   I(min)   I(max)
-1.8V     -11.28mA   -13.1mA    -8.197mA
-1.122V   -10.76mA   -12.22mA   -7.971mA
-1.004V   -10.76mA   -11.96mA   -14mA
-885.9mV  -21.9mA    -12.25mA   -27.74mA
-826.9mV  -29.15mA   -17.03mA   -27.7mA
-767.8mV  -30.63mA   -24.02mA   -26.95mA
-708.7mV  -29.59mA   -28.34mA   -25.92mA
-590.6mV  -25.96mA   -26.62mA   -23.03mA
281.2mV   11.21mA    11.05mA    10.49mA
900mV     26.1mA     25.72mA    24.4mA
1.406V    29.56mA    29.07mA    27.56mA
3.6V      30.42mA    29.83mA    28.07mA
[Ramp]
dV/dt_r   0.670621/0.301311n  0.655496/0.324349n  0.72747/0.256402n
dV/dt_f   0.669523/0.283156n  0.637305/0.317407n  0.67245/0.292142n
R_load = 50
[Rising Waveform]
R_fixture = 50
V_fixture = 0
V_fixture_min = 0
V_fixture_max = 0
| Time   V(typ)   V(min)   V(max)
0s        12.66nV    17.51nV    17.62nV
1.614ns   886.7uV    523.4uV    -41.74mV
1.89ns    -2.642mV   612.9uV    814.6mV
2.123ns   -46.08mV   688.5uV    1.114V
2.461ns   772.1mV    -4.615mV   1.194V
2.611ns   962.9mV    -29.09mV   1.202V
2.808ns   1.053V     -33.73mV   1.207V
3.206ns   1.101V     818mV      1.211V
3.557ns   1.112V     1.038V     1.212V
10ns      1.118V     1.092V     1.212V
[Rising Waveform]
R_fixture = 50
V_fixture = 1.8
V_fixture_min = 1.71
V_fixture_max = 1.89
| Time   V(typ)   V(min)   V(max)
0s        684.1mV    647.8mV    769.2mV
1.439ns   683.9mV    647.6mV    772.4mV
1.754ns   682.8mV    647.6mV    1.691V
2.017ns   864.2mV    647.6mV    1.868V
2.224ns   1.499V     647.5mV    1.883V
2.373ns   1.715V     637.5mV    1.887V
2.563ns   1.776V     732.5mV    1.889V
2.946ns   1.796V     1.546V     1.89V
3.226ns   1.798V     1.686V     1.89V
10ns      1.8V       1.71V      1.89V
[Falling Waveform]
R_fixture = 50
V_fixture = 0
V_fixture_min = 0
V_fixture_max = 0
| Time   V(typ)   V(min)   V(max)
0s        1.118V     1.093V     1.212V
1.49ns    1.117V     1.092V     1.219V
1.774ns   1.117V     1.092V     208.8mV
1.974ns   1.111V     1.092V     38.44mV
2.102ns   721.8mV    1.092V     16.08mV
2.393ns   73.27mV    1.095V     3.302mV
2.606ns   17.11mV    1.085V     1.319mV
2.934ns   3.268mV    211.4mV    758.8uV
3.26ns    935.9uV    20.53mV    723.8uV
10ns      899.5nV    3.405uV    203.5nV
[Falling Waveform]
R_fixture = 50
V_fixture = 1.8
V_fixture_min = 1.71
V_fixture_max = 1.89
| Time   V(typ)   V(min)   V(max)
0s        1.8V       1.71V      1.89V
1.581ns   1.799V     1.709V     1.935V
1.688ns   1.799V     1.709V     1.77V
1.963ns   1.815V     1.709V     1.077V
2.144ns   1.848V     1.709V     878.7mV
2.482ns   1.018V     1.707V     786.7mV
2.798ns   740mV      1.76V      774.4mV
3.21ns    692.8mV    913.5mV    770.4mV
3.664ns   686.1mV    674.7mV    769.3mV
10ns      684.1mV    647.8mV    769.2mV
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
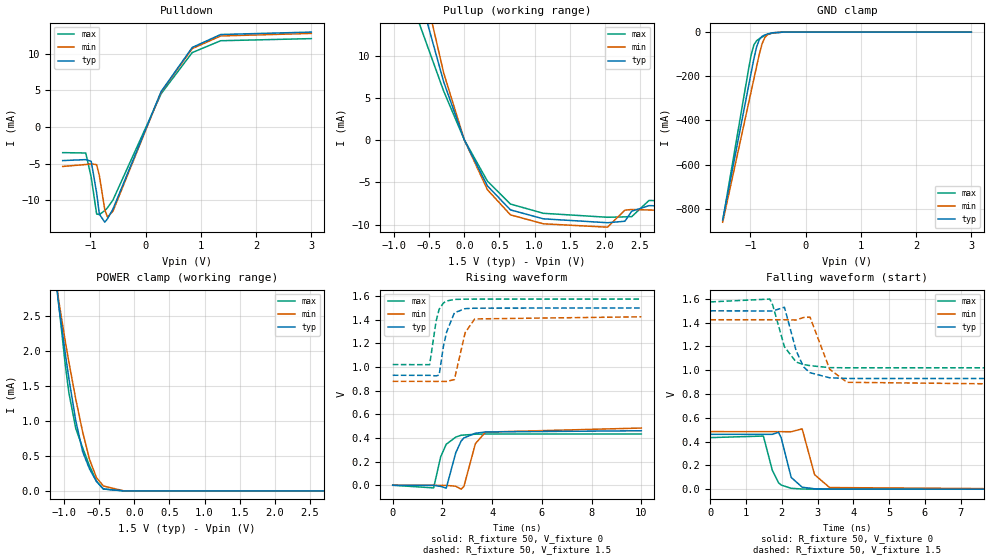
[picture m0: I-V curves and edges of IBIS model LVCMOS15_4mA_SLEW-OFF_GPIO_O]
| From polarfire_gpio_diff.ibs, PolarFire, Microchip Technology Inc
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|   Model LVCMOS15_4mA_SLEW-OFF_GPIO_O
[Model]   LVCMOS15_4mA_SLEW-OFF_GPIO_O
Model_type   Output
Polarity   Non-Inverting
Enable   Active-High
Vmeas =   0.75
Cref =   5p
Rref =   1M
|   typ   min   max
C_comp_pullup   2.605e-12   2.605e-12   2.76e-12
C_comp_pulldown  2.605e-12   2.605e-12   2.76e-12
[Temperature Range]  25C   100C   -40C
[Voltage Range]  1.5   1.425   1.575
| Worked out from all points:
|   slope of the pulldown table from 0 to 0.225 V, typ, clamps not added: 56.6 ohm
|   slope of the pullup table from 0 to 0.225 V, typ, clamps not added: 56.5 ohm
|   GND clamp passes 1 mA (typ) near -0.52 V on its own axis
|   POWER clamp passes 1 mA (typ) near -0.84 V on its own axis
|   rising waveform, R_fixture 50, V_fixture 0: 20-80 % time 409ps typ, 439ps min, 380ps max; typ from 0 V to 0.461 V
|   rising waveform, R_fixture 50, V_fixture 1.5: 20-80 % time 336ps typ, 373ps min, 249ps max; typ from 0.93 V to 1.5 V
|   falling waveform, R_fixture 50, V_fixture 0: 20-80 % time 246ps typ, 293ps min, 262ps max; typ from 0.461 V to 0 V
|   falling waveform, R_fixture 50, V_fixture 1.5: 20-80 % time 356ps typ, 435ps min, 369ps max; typ from 1.5 V to 0.93 V
[GND Clamp]
| Voltage   I(typ)   I(min)   I(max)
-1.5V     -849.7mA   -860.2mA   -853.5mA
-1.034V   -246.6mA   -324.3mA   -170.7mA
-984.4mV  -183.1mA   -267.7mA   -102.9mA
-935.2mV  -119.9mA   -211.2mA   -57.59mA
-885.9mV  -66.33mA   -154.7mA   -38.94mA
-836.7mV  -33.59mA   -99.09mA   -29.82mA
-787.5mV  -19.44mA   -53.53mA   -22.49mA
-738.3mV  -12.87mA   -24.95mA   -16.13mA
-689.1mV  -8.545mA   -11.57mA   -10.81mA
-590.6mV  -2.947mA   -3.067mA   -3.621mA
-393.7mV  -37.64uA   -63.17uA   -40.12uA
3V        0A         0A         0A
[POWER Clamp]
| Voltage   I(typ)   I(min)   I(max)
-1.5V     10.9mA     9.757mA    12.4mA
-1.181V   3.55mA     3.502mA    3.75mA
-1.083V   2.694mA    2.748mA    2.703mA
-984.4mV  1.956mA    2.133mA    1.792mA
-935.2mV  1.615mA    1.848mA    1.408mA
-836.7mV  1.007mA    1.316mA    894.8uA
-738.3mV  562.1uA    843.7uA    616.9uA
-639.8mV  314.2uA    451.1uA    357.6uA
-541.4mV  134.7uA    190.1uA    142.2uA
-443mV    26.83uA    70.8uA     28.29uA
-147.7mV  138.9nA    173.9nA    970.8pA
3V        0A         0A         0A
[Pullup]
| Voltage   I(typ)   I(min)   I(max)
-1.5V     42.22mA    51.21mA    32.39mA
-1.181V   33.46mA    39.82mA    26.19mA
-295.3mV  6.892mA    7.949mA    5.801mA
0V        -138.7nA   7.485uA    12.52uA
328.1mV   -5.411mA   -5.868mA   -4.85mA
656.2mV   -8.252mA   -8.841mA   -7.561mA
1.125V    -9.311mA   -9.9mA     -8.657mA
2.041V    -9.772mA   -10.3mA    -9.128mA
2.288V    -9.598mA   -8.284mA   -9.079mA
2.386V    -8.408mA   -8.207mA   -9.049mA
2.632V    -7.749mA   -8.264mA   -7.141mA
3V        -7.819mA   -8.339mA   -7.203mA
[Pulldown]
| Voltage   I(typ)   I(min)   I(max)
-1.5V     -4.58mA    -5.381mA   -3.494mA
-1.083V   -4.447mA   -5.116mA   -3.544mA
-984.4mV  -4.677mA   -5.024mA   -6.85mA
-885.9mV  -8.978mA   -5.141mA   -11.87mA
-836.7mV  -11.89mA   -6.614mA   -11.95mA
-738.3mV  -12.99mA   -11.3mA    -11.41mA
-689.1mV  -12.52mA   -12.29mA   -11.02mA
-590.6mV  -11.2mA    -11.49mA   -9.963mA
281.2mV   4.836mA    4.767mA    4.54mA
843.8mV   10.86mA    10.7mA     10.16mA
1.359V    12.63mA    12.43mA    11.78mA
3V        12.96mA    12.78mA    12.07mA
[Ramp]
dV/dt_r   0.276675/0.408785n  0.29041/0.439479n  0.260191/0.379542n
dV/dt_f   0.341778/0.356073n  0.327653/0.435111n  0.332561/0.368687n
R_load = 50
[Rising Waveform]
R_fixture = 50
V_fixture = 0
V_fixture_min = 0
V_fixture_max = 0
| Time   V(typ)   V(min)   V(max)
0s        19.64nV    27.39nV    27.05nV
1.646ns   -776.9uV   -507.6uV   -22.29mV
1.93ns    -9.736mV   -595.2uV   240.7mV
2.153ns   -24.43mV   -664uV     346.9mV
2.537ns   275.3mV    -8.392mV   407.4mV
2.752ns   373.7mV    -33.03mV   423.1mV
2.863ns   400.2mV    -10.54mV   424.8mV
3.325ns   440mV      351.7mV    431.9mV
3.733ns   451.1mV    449.7mV    433.4mV
10ns      461.1mV    484mV      433.7mV
[Rising Waveform]
R_fixture = 50
V_fixture = 1.5
V_fixture_min = 1.425
V_fixture_max = 1.575
| Time   V(typ)   V(min)   V(max)
0s        930.4mV    878.9mV    1.021V
1.486ns   929.7mV    878.6mV    1.02V
1.744ns   925.1mV    878.5mV    1.387V
1.868ns   932.1mV    878.5mV    1.489V
2.041ns   1.177V     878.4mV    1.542V
2.17ns    1.297V     878.4mV    1.559V
2.481ns   1.459V     893.8mV    1.572V
2.914ns   1.494V     1.291V     1.574V
3.299ns   1.498V     1.407V     1.575V
10ns      1.5V       1.425V     1.575V
[Falling Waveform]
R_fixture = 50
V_fixture = 0
V_fixture_min = 0
V_fixture_max = 0
| Time   V(typ)   V(min)   V(max)
0s        461.1mV    484.1mV    433.6mV
1.485ns   461.2mV    483.7mV    446.7mV
1.733ns   461.2mV    483.6mV    160.1mV
1.908ns   478.5mV    483.5mV    53.57mV
1.981ns   434mV      483.5mV    34.59mV
2.262ns   98.67mV    483.1mV    7.214mV
2.569ns   16.53mV    507mV      1.349mV
2.916ns   3.159mV    122.1mV    513.9uV
3.336ns   371.2uV    13.53mV    -48.05uV
10ns      219.7nV    3.755uV    773.8nV
[Falling Waveform]
R_fixture = 50
V_fixture = 1.5
V_fixture_min = 1.425
V_fixture_max = 1.575
| Time   V(typ)   V(min)   V(max)
0s        1.5V       1.425V     1.575V
1.663ns   1.499V     1.425V     1.599V
1.745ns   1.499V     1.425V     1.55V
2.074ns   1.53V      1.425V     1.197V
2.402ns   1.163V     1.423V     1.069V
2.609ns   1.028V     1.444V     1.048V
2.789ns   979.6mV    1.447V     1.039V
3.339ns   936.6mV    1.008V     1.022V
3.823ns   931.1mV    898.8mV    1.021V
10ns      930.4mV    878.9mV    1.021V
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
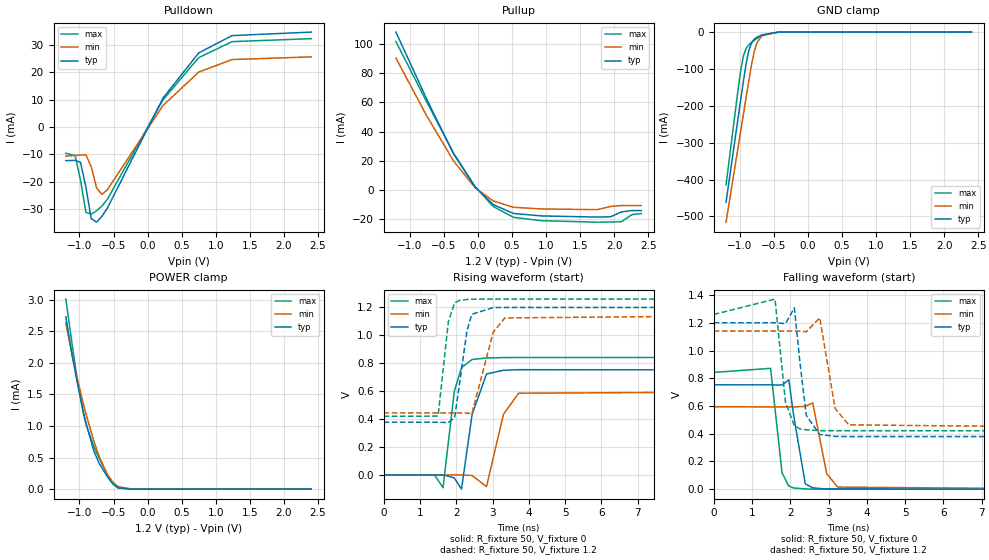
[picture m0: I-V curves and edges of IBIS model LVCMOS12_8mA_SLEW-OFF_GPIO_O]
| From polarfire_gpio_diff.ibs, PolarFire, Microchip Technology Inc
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|   Model LVCMOS12_8mA_SLEW-OFF_GPIO_O
[Model]   LVCMOS12_8mA_SLEW-OFF_GPIO_O
Model_type   Output
Polarity   Non-Inverting
Enable   Active-High
Vmeas =   0.6
Cref =   5p
Rref =   1M
|   typ   min   max
C_comp_pullup   2.605e-12   2.605e-12   2.76e-12
C_comp_pulldown  2.605e-12   2.605e-12   2.76e-12
[Temperature Range]  25C   100C   -40C
[Voltage Range]  1.2   1.14   1.26
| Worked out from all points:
|   slope of the pulldown table from 0 to 0.18 V, typ, clamps not added: 21 ohm
|   slope of the pullup table from 0 to 0.18 V, typ, clamps not added: 21.8 ohm
|   GND clamp passes 1 mA (typ) near -0.52 V on its own axis
|   POWER clamp passes 1 mA (typ) near -0.89 V on its own axis
|   rising waveform, R_fixture 50, V_fixture 0: 20-80 % time 274ps typ, 339ps min, 245ps max; typ from 0 V to 0.753 V
|   rising waveform, R_fixture 50, V_fixture 1.2: 20-80 % time 267ps typ, 366ps min, 190ps max; typ from 0.379 V to 1.2 V
|   falling waveform, R_fixture 50, V_fixture 0: 20-80 % time 198ps typ, 264ps min, 180ps max; typ from 0.753 V to 0 V
|   falling waveform, R_fixture 50, V_fixture 1.2: 20-80 % time 193ps typ, 251ps min, 186ps max; typ from 1.2 V to 0.379 V
[GND Clamp]
| Voltage   I(typ)   I(min)   I(max)
-1.2V     -461.6mA   -515.5mA   -414.1mA
-1.024V   -233.9mA   -313mA     -156.3mA
-984.4mV  -183.1mA   -267.7mA   -102.9mA
-945mV    -132.4mA   -222.5mA   -64.19mA
-905.6mV  -85.65mA   -177.3mA   -44.28mA
-866.2mV  -50.48mA   -132.2mA   -34.88mA
-826.9mV  -29.63mA   -88.81mA   -28.27mA
-787.5mV  -19.44mA   -53.53mA   -22.49mA
-748.1mV  -13.93mA   -29.25mA   -17.33mA
-669.4mV  -7.138mA   -8.749mA   -8.991mA
-433.1mV  -123uA     -169.9uA   -145.4uA
2.4V      0A         0A         0A
[POWER Clamp]
| Voltage   I(typ)   I(min)   I(max)
-1.2V     2.73mA     2.632mA    3.012mA
-1.103V   2.096mA    2.102mA    2.264mA
-1.024V   1.644mA    1.716mA    1.68mA
-945mV    1.238mA    1.362mA    1.214mA
-905.6mV  1.055mA    1.197mA    1.032mA
-787.5mV  602.8uA    757.6uA    672.6uA
-708.7mV  403.3uA    513.5uA    485.6uA
-590.6mV  198.3uA    234.5uA    226.1uA
-511.9mV  86.82uA    113.1uA    88.71uA
-433.1mV  20.57uA    39.13uA    19.31uA
-236.2mV  31.12nA    3.332uA    713.5nA
2.4V      0A         0A         0A
[Pullup]
| Voltage   I(typ)   I(min)   I(max)
-1.2V     108.1mA    90.31mA    101.6mA
-748.1mV  62.2mA     50.8mA     60.3mA
-354.4mV  24.78mA    19.93mA    25.32mA
-39.38mV  2.212mA    1.697mA    2.43mA
225mV     -9.85mA    -7.349mA   -11.11mA
525mV     -15.97mA   -11.75mA   -18.61mA
937.5mV   -17.64mA   -12.88mA   -20.9mA
1.751V    -18.42mA   -13.35mA   -21.93mA
1.948V    -18.26mA   -11.21mA   -21.79mA
2.106V    -14.9mA    -10.52mA   -21.59mA
2.263V    -13.97mA   -10.56mA   -16.74mA
2.4V      -14.02mA   -10.61mA   -16.03mA
[Pulldown]
| Voltage   I(typ)   I(min)   I(max)
-1.2V     -12.28mA   -10.61mA   -9.558mA
-1.063V   -12.15mA   -10.38mA   -10.43mA
-984.4mV  -12.87mA   -10.23mA   -19.4mA
-905.6mV  -21.86mA   -10.11mA   -31.12mA
-826.9mV  -33.38mA   -14.49mA   -31.77mA
-748.1mV  -34.68mA   -22.2mA    -30.53mA
-669.4mV  -32.52mA   -24.6mA    -28.75mA
-590.6mV  -29.58mA   -22.87mA   -26.38mA
225mV     10.49mA    7.79mA     9.87mA
750mV     26.97mA    19.99mA    25.26mA
1.239V    33.27mA    24.55mA    31.07mA
2.4V      34.55mA    25.52mA    32.16mA
[Ramp]
dV/dt_r   0.451605/0.273754n  0.356672/0.3393n  0.505323/0.245337n
dV/dt_f   0.492719/0.192735n  0.416689/0.25098n  0.503492/0.186441n
R_load = 50
[Rising Waveform]
R_fixture = 50
V_fixture = 0
V_fixture_min = 0
V_fixture_max = 0
| Time   V(typ)   V(min)   V(max)
0s        9.965nV    17.25nV    13.86nV
1.406ns   810.7uV    607.9uV    122.7uV
1.636ns   943.3uV    707.4uV    -91.21mV
1.947ns   -19.89mV   841.8uV    599.8mV
2.145ns   -100.9mV   927.4uV    768.9mV
2.437ns   433.1mV    -3.123mV   827.3mV
2.834ns   723.6mV    -82.39mV   838.2mV
3.302ns   750.4mV    435.1mV    841mV
3.72ns    754.5mV    586.1mV    841.6mV
10ns      752.7mV    594.5mV    842.2mV
[Rising Waveform]
R_fixture = 50
V_fixture = 1.2
V_fixture_min = 1.14
V_fixture_max = 1.26
| Time   V(typ)   V(min)   V(max)
0s        378.8mV    445.5mV    420.8mV
1.5ns     378.5mV    445.1mV    422mV
1.784ns   375.4mV    445.1mV    1.1V
1.956ns   412mV      445mV      1.232V
2.088ns   649mV      445mV      1.251V
2.295ns   1.032V     443.4mV    1.257V
2.431ns   1.151V     439.4mV    1.259V
3.018ns   1.199V     1.022V     1.26V
3.338ns   1.2V       1.125V     1.26V
10ns      1.2V       1.14V      1.26V
[Falling Waveform]
R_fixture = 50
V_fixture = 0
V_fixture_min = 0
V_fixture_max = 0
| Time   V(typ)   V(min)   V(max)
0s        752.7mV    594mV      842.2mV
1.484ns   752mV      593.4mV    871.4mV
1.783ns   751.6mV    593.2mV    118mV
1.96ns    788.3mV    593.2mV    22.71mV
2.089ns   527.5mV    593.1mV    8.498mV
2.39ns    38.54mV    597.2mV    1.72mV
2.584ns   9.643mV    622.4mV    611.6uV
2.949ns   781.8uV    112.4mV    581.5uV
3.238ns   749.7uV    14.9mV     557.6uV
10ns      -1.393uV   -24.42uV   16.38nV
[Falling Waveform]
R_fixture = 50
V_fixture = 1.2
V_fixture_min = 1.14
V_fixture_max = 1.26
| Time   V(typ)   V(min)   V(max)
0s        1.2V       1.14V      1.26V
1.599ns   1.2V       1.14V      1.371V
1.873ns   1.194V     1.14V      628.5mV
2.105ns   1.307V     1.14V      456.9mV
2.254ns   906.1mV    1.14V      434.1mV
2.417ns   531.4mV    1.135V     427.9mV
2.768ns   393.8mV    1.236V     421.8mV
3.17ns    380.7mV    582mV      421.7mV
3.526ns   379.5mV    464.1mV    421.7mV
10ns      378.8mV    445.5mV    420.8mV
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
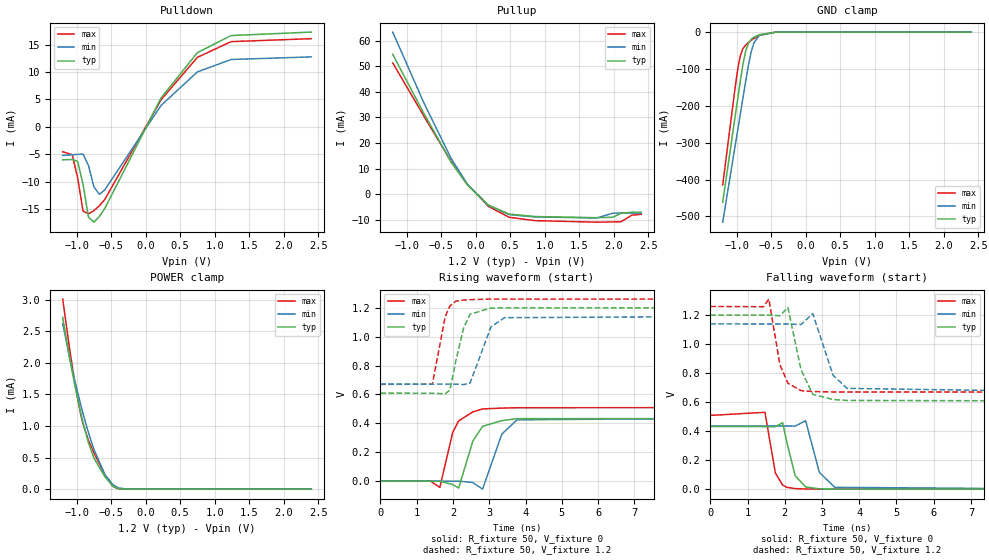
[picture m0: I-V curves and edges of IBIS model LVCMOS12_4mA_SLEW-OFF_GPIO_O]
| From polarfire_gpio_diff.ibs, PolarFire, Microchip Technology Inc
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|   Model LVCMOS12_4mA_SLEW-OFF_GPIO_O
[Model]   LVCMOS12_4mA_SLEW-OFF_GPIO_O
Model_type   Output
Polarity   Non-Inverting
Enable   Active-High
Vmeas =   0.6
Cref =   5p
Rref =   1M
|   typ   min   max
C_comp_pullup   2.605e-12   2.605e-12   2.76e-12
C_comp_pulldown  2.605e-12   2.605e-12   2.76e-12
[Temperature Range]  25C   100C   -40C
[Voltage Range]  1.2   1.14   1.26
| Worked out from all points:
|   slope of the pulldown table from 0 to 0.18 V, typ, clamps not added: 41.7 ohm
|   slope of the pullup table from 0 to 0.18 V, typ, clamps not added: 43.4 ohm
|   GND clamp passes 1 mA (typ) near -0.52 V on its own axis
|   POWER clamp passes 1 mA (typ) near -0.89 V on its own axis
|   rising waveform, R_fixture 50, V_fixture 0: 20-80 % time 364ps typ, 390ps min, 344ps max; typ from 0 V to 0.432 V
|   rising waveform, R_fixture 50, V_fixture 1.2: 20-80 % time 323ps typ, 412ps min, 271ps max; typ from 0.609 V to 1.2 V
|   falling waveform, R_fixture 50, V_fixture 0: 20-80 % time 255ps typ, 314ps min, 204ps max; typ from 0.432 V to 0 V
|   falling waveform, R_fixture 50, V_fixture 1.2: 20-80 % time 311ps typ, 384ps min, 266ps max; typ from 1.2 V to 0.608 V
[GND Clamp]
| Voltage   I(typ)   I(min)   I(max)
-1.2V     -461.6mA   -515.5mA   -414.1mA
-1.024V   -233.9mA   -313mA     -156.3mA
-984.4mV  -183.1mA   -267.7mA   -102.9mA
-945mV    -132.4mA   -222.5mA   -64.19mA
-905.6mV  -85.65mA   -177.3mA   -44.28mA
-866.2mV  -50.48mA   -132.2mA   -34.88mA
-826.9mV  -29.63mA   -88.81mA   -28.27mA
-787.5mV  -19.44mA   -53.53mA   -22.49mA
-748.1mV  -13.93mA   -29.25mA   -17.33mA
-669.4mV  -7.138mA   -8.749mA   -8.991mA
-433.1mV  -123uA     -169.9uA   -145.4uA
2.4V      0A         0A         0A
[POWER Clamp]
| Voltage   I(typ)   I(min)   I(max)
-1.2V     2.722mA    2.621mA    3.012mA
-1.103V   2.096mA    2.102mA    2.245mA
-1.024V   1.644mA    1.716mA    1.68mA
-945mV    1.238mA    1.362mA    1.214mA
-905.6mV  1.055mA    1.197mA    1.032mA
-826.9mV  734.5uA    894.9uA    775uA
-748.1mV  493.1uA    630.3uA    576.4uA
-590.6mV  198.3uA    234.5uA    226.1uA
-472.5mV  46.9uA     69.92uA    43.42uA
-393.7mV  7.199uA    19.02uA    5.897uA
-275.6mV  135.1nA    3.464uA    713.5nA
2.4V      0A         0A         0A
[Pullup]
| Voltage   I(typ)   I(min)   I(max)
-1.2V     54.7mA     63.4mA     51.36mA
-748.1mV  31.55mA    35.69mA    30.51mA
-354.4mV  12.54mA    14mA       12.79mA
-118.1mV  3.568mA    3.867mA    3.838mA
187.5mV   -4.291mA   -4.466mA   -4.821mA
487.5mV   -7.803mA   -8.02mA    -9.064mA
862.5mV   -8.754mA   -8.929mA   -10.36mA
1.751V    -9.215mA   -9.325mA   -10.97mA
1.988V    -9.031mA   -7.462mA   -10.86mA
2.106V    -7.499mA   -7.349mA   -10.78mA
2.263V    -7.07mA    -7.382mA   -8.224mA
2.4V      -7.096mA   -7.411mA   -7.879mA
[Pulldown]
| Voltage   I(typ)   I(min)   I(max)
-1.2V     -6.012mA   -5.211mA   -4.554mA
-1.063V   -5.953mA   -5.099mA   -5.064mA
-984.4mV  -6.289mA   -5.024mA   -9.229mA
-905.6mV  -10.49mA   -4.968mA   -15.37mA
-826.9mV  -16.46mA   -7.052mA   -15.87mA
-748.1mV  -17.39mA   -10.93mA   -15.28mA
-669.4mV  -16.35mA   -12.31mA   -14.41mA
-590.6mV  -14.89mA   -11.49mA   -13.25mA
225mV     5.282mA    3.915mA    4.964mA
750mV     13.53mA    10.02mA    12.67mA
1.239V    16.65mA    12.28mA    15.54mA
2.4V      17.28mA    12.76mA    16.08mA
[Ramp]
dV/dt_r   0.259234/0.364259n  0.262031/0.390294n  0.305105/0.343964n
dV/dt_f   0.354905/0.310705n  0.280895/0.383872n  0.35419/0.266375n
R_load = 50
[Rising Waveform]
R_fixture = 50
V_fixture = 0
V_fixture_min = 0
V_fixture_max = 0
| Time   V(typ)   V(min)   V(max)
0s        15.63nV    25.77nV    21.55nV
1.386ns   -727.4uV   -316.1uV   -865.9uV
1.641ns   -861.2uV   -374.3uV   -43.49mV
1.993ns   -23.38mV   -454.6uV   334.7mV
2.159ns   -48.23mV   -492.5uV   416.7mV
2.548ns   276.5mV    -9.33mV    479mV
2.817ns   378.9mV    -55.87mV   499.5mV
3.348ns   418.5mV    325.6mV    505.3mV
3.766ns   432.3mV    423.7mV    507.9mV
10ns      432.1mV    436.7mV    508.5mV
[Rising Waveform]
R_fixture = 50
V_fixture = 1.2
V_fixture_min = 1.14
V_fixture_max = 1.26
| Time   V(typ)   V(min)   V(max)
0s        608.5mV    671.8mV    669.7mV
1.434ns   607.9mV    671.3mV    670.9mV
1.789ns   604mV      671.2mV    1.139V
1.917ns   629.5mV    671.1mV    1.212V
2.085ns   837mV      671mV      1.246V
2.296ns   1.061V     668.2mV    1.253V
2.472ns   1.155V     677.9mV    1.256V
3.048ns   1.198V     1.067V     1.26V
3.419ns   1.199V     1.131V     1.26V
10ns      1.2V       1.14V      1.26V
[Falling Waveform]
R_fixture = 50
V_fixture = 0
V_fixture_min = 0
V_fixture_max = 0
| Time   V(typ)   V(min)   V(max)
0s        432mV      436.3mV    508.5mV
1.468ns   431.4mV    435.6mV    530mV
1.748ns   431.1mV    435.5mV    111mV
1.942ns   458.4mV    435.4mV    28.51mV
2.058ns   320.5mV    435.4mV    12.75mV
2.281ns   92.29mV    435mV      3.792mV
2.56ns    15.18mV    471.8mV    1.114mV
2.929ns   2.071mV    116.3mV    -139.1uV
3.339ns   11.71uV    12.73mV    -131uV
10ns      -2.69uV    -4.18uV    535.4nV
[Falling Waveform]
R_fixture = 50
V_fixture = 1.2
V_fixture_min = 1.14
V_fixture_max = 1.26
| Time   V(typ)   V(min)   V(max)
0s        1.2V       1.14V      1.26V
1.43ns    1.2V       1.139V     1.258V
1.573ns   1.2V       1.139V     1.311V
1.871ns   1.196V     1.139V     857mV
2.084ns   1.253V     1.139V     730.7mV
2.437ns   823.3mV    1.135V     679.3mV
2.752ns   654mV      1.211V     673mV
3.298ns   618.2mV    785.2mV    670.1mV
3.672ns   611.7mV    694.9mV    670.1mV
10ns      608.5mV    671.8mV    669.7mV
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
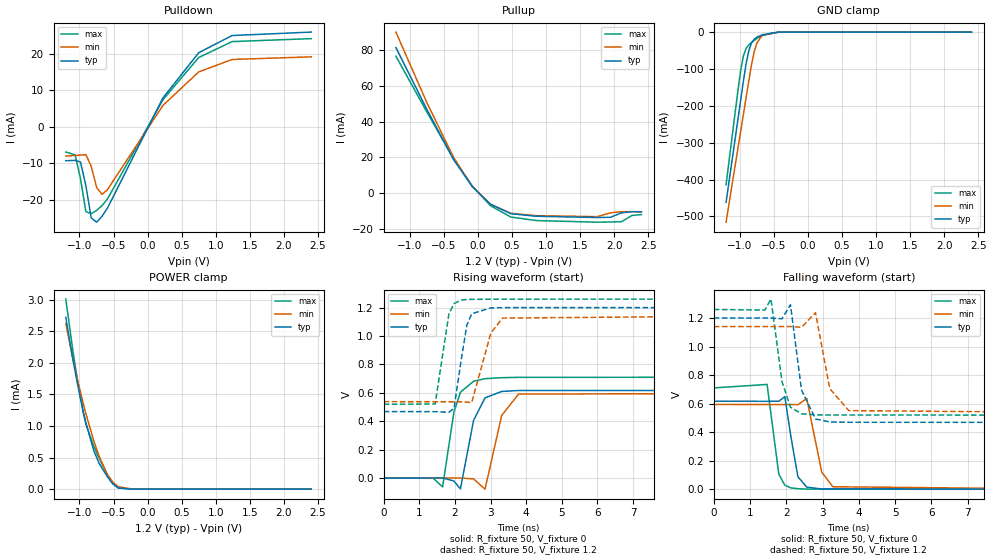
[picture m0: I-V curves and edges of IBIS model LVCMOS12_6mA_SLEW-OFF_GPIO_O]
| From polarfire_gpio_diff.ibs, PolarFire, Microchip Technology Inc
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|   Model LVCMOS12_6mA_SLEW-OFF_GPIO_O
[Model]   LVCMOS12_6mA_SLEW-OFF_GPIO_O
Model_type   Output
Polarity   Non-Inverting
Enable   Active-High
Vmeas =   0.6
Cref =   5p
Rref =   1M
|   typ   min   max
C_comp_pullup   2.605e-12   2.605e-12   2.76e-12
C_comp_pulldown  2.605e-12   2.605e-12   2.76e-12
[Temperature Range]  25C   100C   -40C
[Voltage Range]  1.2   1.14   1.26
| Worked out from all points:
|   slope of the pulldown table from 0 to 0.18 V, typ, clamps not added: 27.9 ohm
|   slope of the pullup table from 0 to 0.18 V, typ, clamps not added: 29 ohm
|   GND clamp passes 1 mA (typ) near -0.52 V on its own axis
|   POWER clamp passes 1 mA (typ) near -0.89 V on its own axis
|   rising waveform, R_fixture 50, V_fixture 0: 20-80 % time 325ps typ, 342ps min, 306ps max; typ from 0 V to 0.617 V
|   rising waveform, R_fixture 50, V_fixture 1.2: 20-80 % time 268ps typ, 354ps min, 235ps max; typ from 0.468 V to 1.2 V
|   falling waveform, R_fixture 50, V_fixture 0: 20-80 % time 234ps typ, 297ps min, 198ps max; typ from 0.617 V to 0 V
|   falling waveform, R_fixture 50, V_fixture 1.2: 20-80 % time 239ps typ, 301ps min, 242ps max; typ from 1.2 V to 0.468 V
[GND Clamp]
| Voltage   I(typ)   I(min)   I(max)
-1.2V     -461.6mA   -515.5mA   -414.1mA
-1.024V   -233.9mA   -313mA     -156.3mA
-984.4mV  -183.1mA   -267.7mA   -102.9mA
-945mV    -132.4mA   -222.5mA   -64.19mA
-905.6mV  -85.65mA   -177.3mA   -44.28mA
-866.2mV  -50.48mA   -132.2mA   -34.88mA
-826.9mV  -29.63mA   -88.81mA   -28.27mA
-787.5mV  -19.44mA   -53.53mA   -22.49mA
-748.1mV  -13.93mA   -29.25mA   -17.33mA
-669.4mV  -7.138mA   -8.749mA   -8.991mA
-433.1mV  -123uA     -169.9uA   -145.4uA
2.4V      0A         0A         0A
[POWER Clamp]
| Voltage   I(typ)   I(min)   I(max)
-1.2V     2.722mA    2.621mA    3.012mA
-1.103V   2.096mA    2.102mA    2.245mA
-1.024V   1.644mA    1.716mA    1.68mA
-945mV    1.238mA    1.362mA    1.214mA
-905.6mV  1.055mA    1.197mA    1.032mA
-787.5mV  602.8uA    757.6uA    672.6uA
-708.7mV  403.3uA    513.5uA    485.6uA
-590.6mV  198.3uA    234.5uA    226.1uA
-511.9mV  86.82uA    113.1uA    88.71uA
-433.1mV  20.57uA    39.13uA    19.31uA
-236.2mV  31.12nA    3.332uA    713.5nA
2.4V      0A         0A         0A
[Pullup]
| Voltage   I(typ)   I(min)   I(max)
-1.2V     81.54mA    90.27mA    76.72mA
-748.1mV  46.99mA    50.8mA     45.55mA
-354.4mV  18.7mA     19.93mA    19.11mA
-78.75mV  3.443mA    3.523mA    3.755mA
187.5mV   -6.419mA   -6.379mA   -7.214mA
487.5mV   -11.69mA   -11.47mA   -13.58mA
862.5mV   -13.13mA   -12.78mA   -15.53mA
1.751V    -13.82mA   -13.35mA   -16.45mA
1.948V    -13.7mA    -11.21mA   -16.35mA
2.106V    -11.22mA   -10.52mA   -16.21mA
2.263V    -10.55mA   -10.56mA   -12.67mA
2.4V      -10.59mA   -10.61mA   -12.18mA
[Pulldown]
| Voltage   I(typ)   I(min)   I(max)
-1.2V     -9.275mA   -8.007mA   -6.881mA
-1.063V   -9.183mA   -7.837mA   -7.688mA
-984.4mV  -9.613mA   -7.721mA   -14.19mA
-905.6mV  -16.11mA   -7.615mA   -23.18mA
-826.9mV  -24.92mA   -10.77mA   -23.78mA
-748.1mV  -26.09mA   -16.57mA   -22.87mA
-669.4mV  -24.49mA   -18.49mA   -21.56mA
-590.6mV  -22.29mA   -17.22mA   -19.8mA
225mV     7.904mA    5.862mA    7.414mA
750mV     20.27mA    15.02mA    18.96mA
1.239V    24.97mA    18.42mA    23.31mA
2.4V      25.91mA    19.14mA    24.12mA
[Ramp]
dV/dt_r   0.370082/0.324914n  0.356597/0.341859n  0.425937/0.306171n
dV/dt_f   0.439032/0.238746n  0.361265/0.300944n  0.444266/0.241538n
R_load = 50
[Rising Waveform]
R_fixture = 50
V_fixture = 0
V_fixture_min = 0
V_fixture_max = 0
| Time   V(typ)   V(min)   V(max)
0s        12.16nV    20.64nV    16.89nV
1.392ns   753.4uV    596.2uV    -929.7uV
1.654ns   895.2uV    708.4uV    -61.81mV
1.971ns   -20.08mV   844.2uV    463.9mV
2.154ns   -75.73mV   922.6uV    604.4mV
2.524ns   406.7mV    -5.528mV   681.6mV
2.845ns   564.7mV    -77.65mV   699.9mV
3.313ns   609.8mV    441.3mV    706.8mV
3.788ns   616.6mV    591.7mV    709.1mV
10ns      616.8mV    594.3mV    709.9mV
[Rising Waveform]
R_fixture = 50
V_fixture = 1.2
V_fixture_min = 1.14
V_fixture_max = 1.26
| Time   V(typ)   V(min)   V(max)
0s        468.3mV    537.9mV    519.6mV
1.445ns   467.9mV    537.7mV    521.6mV
1.83ns    462.9mV    537.7mV    1.154V
1.975ns   490.9mV    537.7mV    1.228V
2.173ns   827.2mV    537.6mV    1.253V
2.332ns   1.074V     535.3mV    1.257V
2.471ns   1.157V     531.5mV    1.258V
3.009ns   1.198V     1.022V     1.259V
3.337ns   1.2V       1.126V     1.259V
10ns      1.2V       1.14V      1.26V
[Falling Waveform]
R_fixture = 50
V_fixture = 0
V_fixture_min = 0
V_fixture_max = 0
| Time   V(typ)   V(min)   V(max)
0s        616.8mV    594mV      709.9mV
1.47ns    616.1mV    593.5mV    734.3mV
1.793ns   616.7mV    593.3mV    104.5mV
1.958ns   648.9mV    593.3mV    27.94mV
2.126ns   368.2mV    593.2mV    8.881mV
2.319ns   86.93mV    592.3mV    3.07mV
2.563ns   14.04mV    635.3mV    717.9uV
2.977ns   1.116mV    118.8mV    677.9uV
3.281ns   180.3uV    17.11mV    648.6uV
10ns      88.96nV    -30.66uV   472.5nV
[Falling Waveform]
R_fixture = 50
V_fixture = 1.2
V_fixture_min = 1.14
V_fixture_max = 1.26
| Time   V(typ)   V(min)   V(max)
0s        1.2V       1.14V      1.26V
1.409ns   1.2V       1.14V      1.256V
1.576ns   1.2V       1.14V      1.333V
1.88ns    1.195V     1.14V      755.3mV
2.114ns   1.293V     1.14V      574.7mV
2.418ns   695.9mV    1.135V     528.6mV
2.804ns   492.1mV    1.238V     520.7mV
3.196ns   471.4mV    705.2mV    520mV
3.721ns   469mV      550.8mV    519.7mV
10ns      468.3mV    537.9mV    519.6mV
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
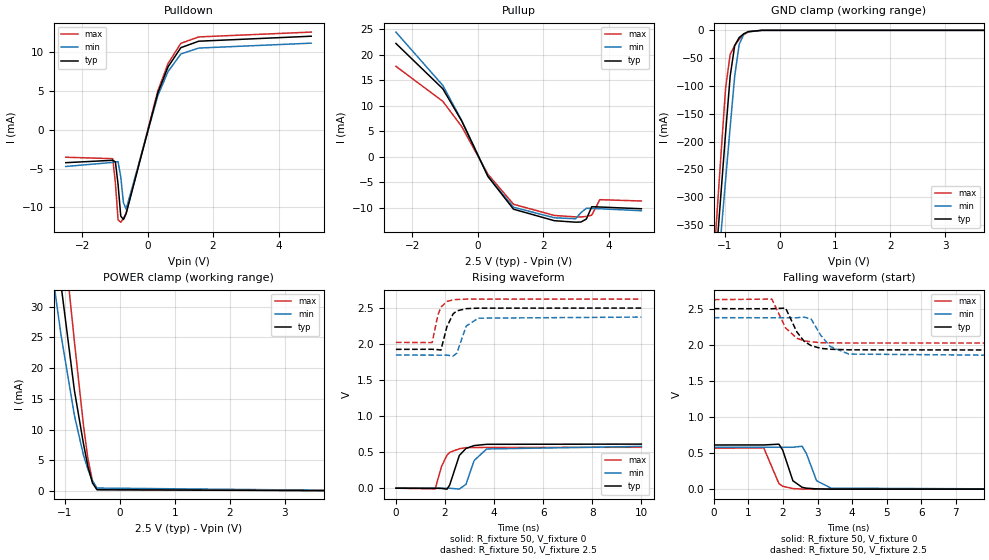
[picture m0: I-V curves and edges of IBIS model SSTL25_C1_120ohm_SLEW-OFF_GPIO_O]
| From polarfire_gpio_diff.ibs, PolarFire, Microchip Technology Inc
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|   Model SSTL25_C1_120ohm_SLEW-OFF_GPIO_O
[Model]   SSTL25_C1_120ohm_SLEW-OFF_GPIO_O
Model_type   Output
Polarity   Non-Inverting
Enable   Active-High
Vmeas =   1.25
Cref =   5p
Rref =   50
Vref =   1.25
|   typ   min   max
C_comp_pullup   2.605e-12   2.605e-12   2.76e-12
C_comp_pulldown  2.605e-12   2.605e-12   2.76e-12
[Temperature Range]  25C   100C   -40C
[Voltage Range]  2.5   2.375   2.625
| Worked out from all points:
|   slope of the pulldown table from 0 to 0.375 V, typ, clamps not added: 68.5 ohm
|   slope of the pullup table from 0 to 0.375 V, typ, clamps not added: 82.3 ohm
|   GND clamp passes 1 mA (typ) near -0.51 V on its own axis
|   POWER clamp passes 1 mA (typ) near -0.47 V on its own axis
|   rising waveform, R_fixture 50, V_fixture 0: 20-80 % time 401ps typ, 433ps min, 353ps max; typ from 0 V to 0.612 V
|   rising waveform, R_fixture 50, V_fixture 2.5: 20-80 % time 314ps typ, 353ps min, 249ps max; typ from 1.93 V to 2.5 V
|   falling waveform, R_fixture 50, V_fixture 0: 20-80 % time 250ps typ, 272ps min, 265ps max; typ from 0.612 V to 0 V
|   falling waveform, R_fixture 50, V_fixture 2.5: 20-80 % time 413ps typ, 505ps min, 413ps max; typ from 2.5 V to 1.93 V
[GND Clamp]
| Voltage   I(typ)   I(min)   I(max)
-2.5V     -2.154A    -2.019A    -2.334A
-1.23V    -500.9mA   -550.5mA   -458.7mA
-1.148V   -394.9mA   -456.3mA   -338.7mA
-1.066V   -289mA     -362mA     -218.7mA
-984.4mV  -183.1mA   -267.7mA   -102.9mA
-902.3mV  -82.21mA   -173.6mA   -43.25mA
-820.3mV  -27.37mA   -82.26mA   -27.26mA
-738.3mV  -12.87mA   -24.95mA   -16.13mA
-656.2mV  -6.285mA   -7.324mA   -7.886mA
-574.2mV  -2.342mA   -2.429mA   -2.872mA
-328.1mV  -3.985uA   -10.42uA   -2.675uA
5V        0A         0A         0A
[POWER Clamp]
| Voltage   I(typ)   I(min)   I(max)
-2.5V     191.3mA    155.6mA    232.6mA
-1.559V   79.6mA     61.42mA    102.5mA
-1.395V   63.37mA    48.38mA    82.85mA
-1.23V    48.04mA    36.4mA     63.67mA
-1.148V   40.77mA    30.8mA     54.53mA
-1.066V   33.71mA    25.51mA    45.88mA
-820.3mV  16.31mA    12.25mA    24.25mA
-656.2mV  7.665mA    5.818mA    10.67mA
-574.2mV  3.929mA    3.48mA     5.131mA
-492.2mV  1.272mA    1.622mA    1.634mA
-410.2mV  189.8uA    467.6uA    244.4uA
5V        0A         0A         0A
[Pullup]
| Voltage   I(typ)   I(min)   I(max)
-2.5V     22.26mA    24.49mA    17.77mA
-1.066V   13.35mA    14.01mA    10.89mA
-492.2mV  7.057mA    7.171mA    5.969mA
312.5mV   -3.874mA   -3.789mA   -3.432mA
1.094V    -10.29mA   -9.9mA     -9.323mA
2.344V    -12.55mA   -11.98mA   -11.52mA
2.992V    -12.84mA   -12.16mA   -11.8mA
3.156V    -12.8mA    -10.96mA   -11.81mA
3.32V     -12.22mA   -10.1mA    -11.71mA
3.484V    -9.804mA   -10.14mA   -11.46mA
3.73V     -9.86mA    -10.2mA    -8.423mA
5V        -10.2mA    -10.59mA   -8.676mA
[Pulldown]
| Voltage   I(typ)   I(min)   I(max)
-2.5V     -4.252mA   -4.738mA   -3.553mA
-1.066V   -3.946mA   -4.218mA   -3.737mA
-984.4mV  -4.157mA   -4.155mA   -6.85mA
-902.3mV  -7.055mA   -4.125mA   -11.6mA
-820.3mV  -11.11mA   -6.095mA   -11.89mA
-738.3mV  -11.55mA   -9.39mA    -11.41mA
-656.2mV  -10.78mA   -10.21mA   -10.71mA
312.5mV   4.706mA    4.352mA    4.968mA
625mV     8.048mA    7.446mA    8.475mA
1.016V    10.51mA    9.701mA    11.07mA
1.562V    11.34mA    10.46mA    11.89mA
5V        11.98mA    11.09mA    12.51mA
[Ramp]
dV/dt_r   0.367183/0.40108n  0.348103/0.432947n  0.340476/0.35283n
dV/dt_f   0.343509/0.412673n  0.316352/0.505492n  0.360571/0.413383n
R_load = 50
[Rising Waveform]
R_fixture = 50
V_fixture = 0
V_fixture_min = 0
V_fixture_max = 0
| Time   V(typ)   V(min)   V(max)
0s        25.93nV    47.05nV    33.34nV
1.599ns   -583.2uV   -477.2uV   -9.837mV
1.857ns   -2.984mV   -554.2uV   301.3mV
2.082ns   -13.39mV   -621.4uV   458.8mV
2.191ns   44.79mV    -653.9uV   497.5mV
2.583ns   454mV      -12.29mV   547.3mV
2.853ns   551.7mV    53.31mV    563.3mV
3.186ns   591.8mV    383.1mV    564.5mV
3.696ns   609.2mV    544.6mV    566.3mV
10ns      612mV      580.2mV    567.5mV
[Rising Waveform]
R_fixture = 50
V_fixture = 2.5
V_fixture_min = 2.375
V_fixture_max = 2.625
| Time   V(typ)   V(min)   V(max)
0s        1.927V     1.848V     2.024V
1.476ns   1.928V     1.847V     2.021V
1.707ns   1.923V     1.847V     2.399V
1.833ns   1.917V     1.847V     2.513V
2.078ns   2.242V     1.847V     2.591V
2.33ns    2.419V     1.834V     2.615V
2.481ns   2.461V     1.874V     2.619V
2.864ns   2.492V     2.25V      2.624V
3.355ns   2.499V     2.36V      2.624V
10ns      2.5V       2.375V     2.625V
[Falling Waveform]
R_fixture = 50
V_fixture = 0
V_fixture_min = 0
V_fixture_max = 0
| Time   V(typ)   V(min)   V(max)
0s        611.9mV    580.2mV    567.5mV
1.445ns   612.1mV    580.1mV    572.1mV
1.884ns   622.8mV    580.1mV    76.98mV
1.994ns   540.5mV    580.1mV    39.46mV
2.288ns   116.3mV    580.1mV    8.28mV
2.554ns   25.82mV    594.4mV    1.795mV
2.683ns   13.36mV    489.4mV    1.333mV
2.972ns   4.09mV     116.9mV    297.1uV
3.396ns   771.6uV    13.71mV    -120.2uV
10ns      78.72nV    3.254uV    -218.6nV
[Falling Waveform]
R_fixture = 50
V_fixture = 2.5
V_fixture_min = 2.375
V_fixture_max = 2.625
| Time   V(typ)   V(min)   V(max)
0s        2.5V       2.375V     2.625V
1.679ns   2.499V     2.374V     2.633V
2.077ns   2.508V     2.374V     2.233V
2.402ns   2.178V     2.374V     2.091V
2.616ns   2.046V     2.383V     2.053V
2.819ns   1.987V     2.354V     2.041V
3.097ns   1.95V      2.129V     2.029V
3.365ns   1.938V     1.977V     2.027V
3.904ns   1.93V      1.871V     2.024V
10ns      1.927V     1.848V     2.024V
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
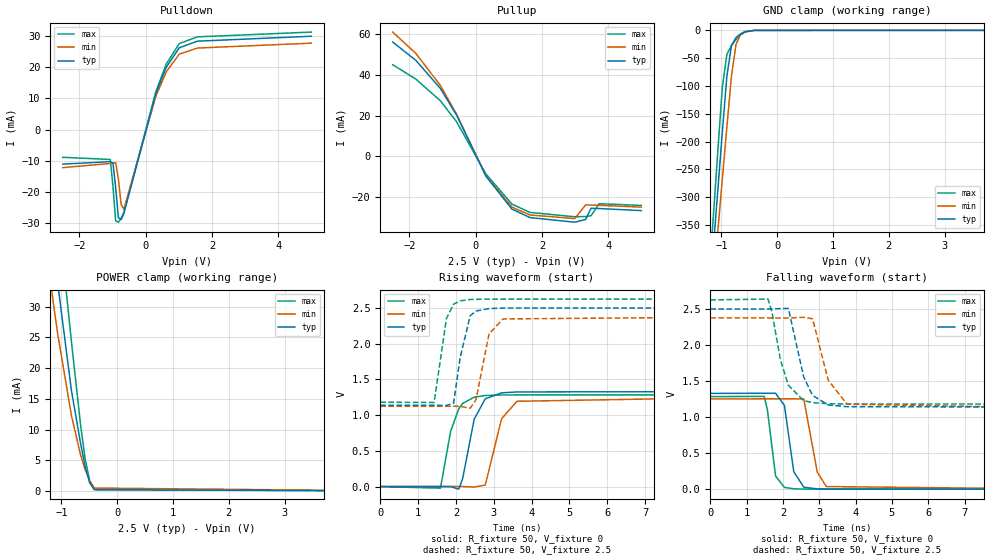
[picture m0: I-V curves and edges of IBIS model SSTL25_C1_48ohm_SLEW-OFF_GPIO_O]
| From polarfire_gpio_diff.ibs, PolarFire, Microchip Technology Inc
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|   Model SSTL25_C1_48ohm_SLEW-OFF_GPIO_O
[Model]   SSTL25_C1_48ohm_SLEW-OFF_GPIO_O
Model_type   Output
Polarity   Non-Inverting
Enable   Active-High
Vmeas =   1.25
Cref =   5p
Rref =   50
Vref =   1.25
|   typ   min   max
C_comp_pullup   2.605e-12   2.605e-12   2.76e-12
C_comp_pulldown  2.605e-12   2.605e-12   2.76e-12
[Temperature Range]  25C   100C   -40C
[Voltage Range]  2.5   2.375   2.625
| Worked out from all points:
|   slope of the pulldown table from 0 to 0.375 V, typ, clamps not added: 27.6 ohm
|   slope of the pullup table from 0 to 0.375 V, typ, clamps not added: 33.1 ohm
|   GND clamp passes 1 mA (typ) near -0.51 V on its own axis
|   POWER clamp passes 1 mA (typ) near -0.47 V on its own axis
|   rising waveform, R_fixture 50, V_fixture 0: 20-80 % time 334ps typ, 374ps min, 311ps max; typ from 0 V to 1.33 V
|   rising waveform, R_fixture 50, V_fixture 2.5: 20-80 % time 235ps typ, 282ps min, 209ps max; typ from 1.14 V to 2.5 V
|   falling waveform, R_fixture 50, V_fixture 0: 20-80 % time 217ps typ, 235ps min, 176ps max; typ from 1.33 V to 0 V
|   falling waveform, R_fixture 50, V_fixture 2.5: 20-80 % time 398ps typ, 430ps min, 387ps max; typ from 2.5 V to 1.14 V
[GND Clamp]
| Voltage   I(typ)   I(min)   I(max)
-2.5V     -2.154A    -2.019A    -2.334A
-1.23V    -500.9mA   -550.5mA   -458.7mA
-1.148V   -394.9mA   -456.3mA   -338.7mA
-1.066V   -289mA     -362mA     -218.7mA
-984.4mV  -183.1mA   -267.7mA   -102.9mA
-902.3mV  -82.21mA   -173.6mA   -43.25mA
-820.3mV  -27.37mA   -82.26mA   -27.26mA
-738.3mV  -12.87mA   -24.95mA   -16.13mA
-656.2mV  -6.285mA   -7.324mA   -7.886mA
-574.2mV  -2.342mA   -2.429mA   -2.872mA
-410.2mV  -62.85uA   -96.5uA    -70.85uA
5V        0A         0A         0A
[POWER Clamp]
| Voltage   I(typ)   I(min)   I(max)
-2.5V     191.3mA    155.6mA    232.6mA
-1.559V   79.6mA     61.42mA    102.5mA
-1.395V   63.37mA    48.38mA    82.85mA
-1.23V    48.04mA    36.4mA     63.67mA
-1.148V   40.77mA    30.8mA     54.53mA
-1.066V   33.71mA    25.51mA    45.88mA
-820.3mV  16.31mA    12.25mA    24.25mA
-656.2mV  7.665mA    5.818mA    10.67mA
-574.2mV  3.929mA    3.48mA     5.131mA
-492.2mV  1.272mA    1.622mA    1.634mA
-410.2mV  189.8uA    467.6uA    244.4uA
5V        0A         0A         0A
[Pullup]
| Voltage   I(typ)   I(min)   I(max)
-2.5V     55.91mA    60.77mA    44.83mA
-1.805V   47.01mA    50.38mA    37.85mA
-1.066V   33.32mA    34.79mA    27.27mA
-574.2mV  20.24mA    20.66mA    17mA
312.5mV   -9.641mA   -9.429mA   -8.538mA
1.094V    -25.65mA   -24.7mA    -23.22mA
1.641V    -29.85mA   -28.56mA   -27.3mA
2.992V    -32.09mA   -30.33mA   -29.44mA
3.32V     -30.78mA   -23.62mA   -29.34mA
3.484V    -25.28mA   -23.71mA   -28.91mA
3.73V     -25.43mA   -23.85mA   -23.05mA
5V        -26.43mA   -24.73mA   -23.91mA
[Pulldown]
| Voltage   I(typ)   I(min)   I(max)
-2.5V     -11.02mA   -12.14mA   -8.839mA
-1.066V   -10.22mA   -10.81mA   -9.527mA
-984.4mV  -10.71mA   -10.64mA   -18.02mA
-902.3mV  -18.47mA   -10.56mA   -29.2mA
-820.3mV  -28.16mA   -15.77mA   -29.61mA
-738.3mV  -28.81mA   -23.87mA   -28.35mA
-656.2mV  -26.81mA   -25.47mA   -26.55mA
312.5mV   11.69mA    10.82mA    12.3mA
625mV     20.03mA    18.54mA    21.05mA
1.016V    26.23mA    24.21mA    27.58mA
1.562V    28.35mA    26.15mA    29.73mA
5V        29.93mA    27.72mA    31.26mA
[Ramp]
dV/dt_r   0.797442/0.33366n  0.751453/0.374095n  0.770655/0.310867n
dV/dt_f   0.816986/0.397806n  0.75075/0.429938n  0.866099/0.386811n
R_load = 50
[Rising Waveform]
R_fixture = 50
V_fixture = 0
V_fixture_min = 0
V_fixture_max = 0
| Time   V(typ)   V(min)   V(max)
0s        15.23nV    28.08nV    19.41nV
1.591ns   843uV      568.1uV    -22.05mV
1.859ns   -798.2uV   663.8uV    770.8mV
2.076ns   -36.27mV   741.3uV    1.091V
2.18ns    116.3mV    778.4uV    1.164V
2.483ns   944.5mV    -6.98mV    1.252V
2.776ns   1.229V     21.26mV    1.275V
3.207ns   1.312V     950.3mV    1.282V
3.615ns   1.325V     1.194V     1.283V
10ns      1.329V     1.252V     1.284V
[Rising Waveform]
R_fixture = 50
V_fixture = 2.5
V_fixture_min = 2.375
V_fixture_max = 2.625
| Time   V(typ)   V(min)   V(max)
0s        1.138V     1.124V     1.181V
1.423ns   1.139V     1.124V     1.177V
1.749ns   1.135V     1.124V     2.353V
1.938ns   1.167V     1.124V     2.553V
2.112ns   1.807V     1.124V     2.6V
2.378ns   2.394V     1.097V     2.619V
2.529ns   2.457V     1.215V     2.621V
2.875ns   2.492V     2.137V     2.624V
3.246ns   2.499V     2.347V     2.624V
10ns      2.5V       2.375V     2.625V
[Falling Waveform]
R_fixture = 50
V_fixture = 0
V_fixture_min = 0
V_fixture_max = 0
| Time   V(typ)   V(min)   V(max)
0s        1.329V     1.252V     1.284V
1.485ns   1.33V      1.253V     1.287V
1.572ns   1.33V      1.253V     1.104V
1.798ns   1.331V     1.253V     183mV
2.041ns   1.161V     1.253V     23.76mV
2.299ns   242.9mV    1.253V     5.108mV
2.574ns   27.27mV    1.252V     1.494mV
2.946ns   4.303mV    235.7mV    621.1uV
3.196ns   1.421mV    36.33mV    599.1uV
10ns      1.654uV    6.44uV     442.9nV
[Falling Waveform]
R_fixture = 50
V_fixture = 2.5
V_fixture_min = 2.375
V_fixture_max = 2.625
| Time   V(typ)   V(min)   V(max)
0s        2.5V       2.375V     2.625V
1.59ns    2.499V     2.375V     2.637V
1.696ns   2.499V     2.374V     2.461V
1.933ns   2.505V     2.374V     1.79V
2.15ns    2.508V     2.374V     1.442V
2.571ns   1.558V     2.384V     1.228V
2.817ns   1.3V       2.363V     1.201V
3.246ns   1.169V     1.513V     1.185V
3.765ns   1.144V     1.179V     1.181V
10ns      1.138V     1.124V     1.181V
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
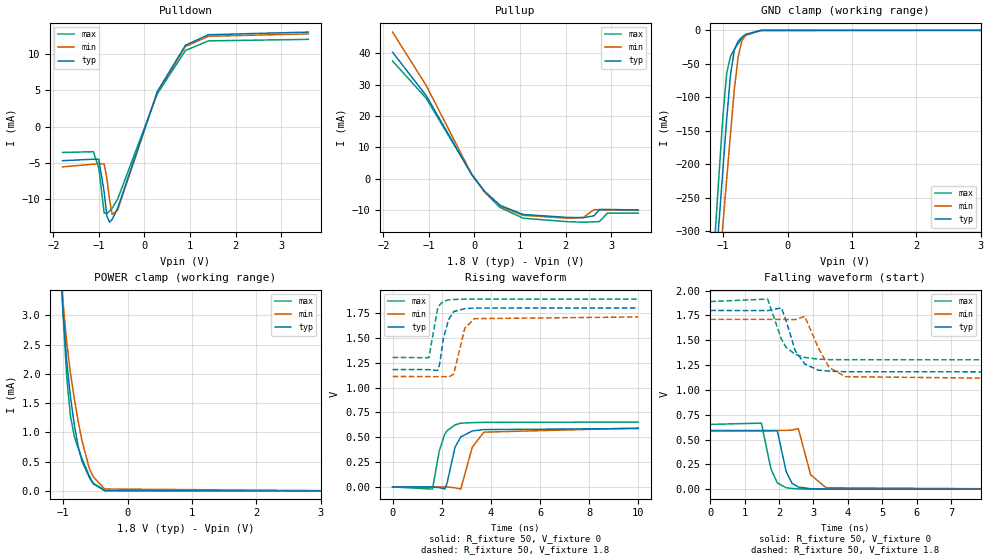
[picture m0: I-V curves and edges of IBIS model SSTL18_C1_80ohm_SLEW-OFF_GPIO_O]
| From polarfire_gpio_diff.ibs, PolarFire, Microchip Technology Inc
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|   Model SSTL18_C1_80ohm_SLEW-OFF_GPIO_O
[Model]   SSTL18_C1_80ohm_SLEW-OFF_GPIO_O
Model_type   Output
Polarity   Non-Inverting
Enable   Active-High
Vmeas =   0.9
Cref =   5p
Rref =   50
Vref =   0.9
|   typ   min   max
C_comp_pullup   2.605e-12   2.605e-12   2.76e-12
C_comp_pulldown  2.605e-12   2.605e-12   2.76e-12
[Temperature Range]  25C   100C   -40C
[Voltage Range]  1.8   1.71   1.89
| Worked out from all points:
|   slope of the pulldown table from 0 to 0.27 V, typ, clamps not added: 57.9 ohm
|   slope of the pullup table from 0 to 0.27 V, typ, clamps not added: 56.2 ohm
|   GND clamp passes 1 mA (typ) near -0.52 V on its own axis
|   POWER clamp passes 1 mA (typ) near -0.81 V on its own axis
|   rising waveform, R_fixture 50, V_fixture 0: 20-80 % time 391ps typ, 451ps min, 356ps max; typ from 0 V to 0.587 V
|   rising waveform, R_fixture 50, V_fixture 1.8: 20-80 % time 314ps typ, 356ps min, 230ps max; typ from 1.18 V to 1.8 V
|   falling waveform, R_fixture 50, V_fixture 0: 20-80 % time 237ps typ, 282ps min, 259ps max; typ from 0.587 V to 0 V
|   falling waveform, R_fixture 50, V_fixture 1.8: 20-80 % time 400ps typ, 485ps min, 397ps max; typ from 1.8 V to 1.18 V
[GND Clamp]
| Voltage   I(typ)   I(min)   I(max)
-1.8V     -1.238A    -1.206A    -1.294A
-1.122V   -361mA     -426.1mA   -300.3mA
-1.063V   -284.7mA   -358.2mA   -213.9mA
-1.004V   -208.5mA   -290.3mA   -128.4mA
-945mV    -132.4mA   -222.5mA   -64.19mA
-885.9mV  -66.33mA   -154.7mA   -38.94mA
-826.9mV  -29.63mA   -88.81mA   -28.27mA
-767.8mV  -16.36mA   -39.95mA   -19.83mA
-708.7mV  -10.12mA   -15.57mA   -12.8mA
-649.7mV  -5.882mA   -6.713mA   -7.364mA
-413.4mV  -69.42uA   -104.8uA   -78.93uA
3.6V      0A         0A         0A
[POWER Clamp]
| Voltage   I(typ)   I(min)   I(max)
-1.8V     45.61mA    35.65mA    60.31mA
-1.063V   4.301mA    4.234mA    4.672mA
-1.004V   3.099mA    3.258mA    3.078mA
-945mV    2.226mA    2.547mA    1.95mA
-885.9mV  1.604mA    2.011mA    1.273mA
-826.9mV  1.131mA    1.577mA    934uA
-767.8mV  765.5uA    1.2mA      735.6uA
-708.7mV  512.4uA    863.2uA    558uA
-590.6mV  225.1uA    373.6uA    248.4uA
-531.6mV  123.5uA    241.6uA    129.3uA
-354.4mV  2.157uA    32.9uA     10.61uA
3.6V      0A         0A         0A
[Pullup]
| Voltage   I(typ)   I(min)   I(max)
-1.8V     40.36mA    46.8mA     37.56mA
-1.063V   26.55mA    29.8mA     25.7mA
-59.06mV  1.217mA    1.299mA    1.345mA
225mV     -4.098mA   -4.29mA    -4.362mA
562.5mV   -8.54mA    -8.853mA   -9.24mA
1.069V    -11.47mA   -11.75mA   -12.67mA
2.036V    -12.41mA   -12.66mA   -13.77mA
2.391V    -12.5mA    -12.42mA   -13.94mA
2.627V    -11.88mA   -9.931mA   -13.84mA
2.745V    -9.879mA   -9.96mA    -13.73mA
2.922V    -9.869mA   -10.01mA   -11.04mA
3.6V      -10.03mA   -10.16mA   -11.05mA
[Pulldown]
| Voltage   I(typ)   I(min)   I(max)
-1.8V     -4.669mA   -5.518mA   -3.532mA
-1.122V   -4.459mA   -5.15mA    -3.434mA
-1.004V   -4.469mA   -5.044mA   -5.71mA
-885.9mV  -8.978mA   -5.141mA   -11.87mA
-826.9mV  -12.29mA   -7.052mA   -11.92mA
-767.8mV  -13.13mA   -10.02mA   -11.61mA
-708.7mV  -12.73mA   -12.07mA   -11.18mA
-590.6mV  -11.2mA    -11.49mA   -9.963mA
281.2mV   4.836mA    4.766mA    4.54mA
900mV     11.22mA    11.05mA    10.5mA
1.406V    12.67mA    12.46mA    11.82mA
3.6V      13.03mA    12.78mA    12.03mA
[Ramp]
dV/dt_r   0.352358/0.39114n  0.35551/0.45111n  0.391339/0.356384n
dV/dt_f   0.371254/0.399559n  0.359538/0.48506n  0.352052/0.397279n
R_load = 50
[Rising Waveform]
R_fixture = 50
V_fixture = 0
V_fixture_min = 0
V_fixture_max = 0
| Time   V(typ)   V(min)   V(max)
0s        21.05nV    29.03nV    28.84nV
1.622ns   -527.3uV   -496.9uV   -22.11mV
1.9ns     -6.75mV    -582.1uV   361.1mV
2.121ns   -21.4mV    -649.8uV   529mV
2.213ns   33.63mV    -677.9uV   564.8mV
2.541ns   398.4mV    -8.874mV   623.9mV
2.774ns   502.5mV    -22.74mV   641.4mV
3.244ns   563.1mV    399.7mV    646.7mV
3.713ns   576.8mV    550.9mV    649.3mV
10ns      587.3mV    592.5mV    652.2mV
[Rising Waveform]
R_fixture = 50
V_fixture = 1.8
V_fixture_min = 1.71
V_fixture_max = 1.89
| Time   V(typ)   V(min)   V(max)
0s        1.181V     1.111V     1.303V
1.476ns   1.18V      1.11V      1.3V
1.83ns    1.171V     1.11V      1.79V
1.912ns   1.231V     1.11V      1.831V
2.067ns   1.49V      1.11V      1.866V
2.276ns   1.682V     1.105V     1.882V
2.487ns   1.764V     1.135V     1.886V
2.938ns   1.794V     1.596V     1.889V
3.323ns   1.799V     1.693V     1.89V
10ns      1.8V       1.71V      1.89V
[Falling Waveform]
R_fixture = 50
V_fixture = 0
V_fixture_min = 0
V_fixture_max = 0
| Time   V(typ)   V(min)   V(max)
0s        587.2mV    592.6mV    652.3mV
1.486ns   587.3mV    592.1mV    665.4mV
1.763ns   587.4mV    592mV      202.8mV
1.948ns   588.6mV    591.9mV    63.61mV
2.204ns   179.5mV    591.8mV    14.49mV
2.373ns   60.5mV     595.2mV    7.262mV
2.559ns   21.46mV    610.5mV    2.844mV
2.918ns   4.665mV    144.1mV    316.5uV
3.366ns   870.6uV    14.3mV     -60.11uV
10ns      1.496uV    1.98uV     669.7nV
[Falling Waveform]
R_fixture = 50
V_fixture = 1.8
V_fixture_min = 1.71
V_fixture_max = 1.89
| Time   V(typ)   V(min)   V(max)
0s        1.8V       1.71V      1.89V
1.667ns   1.799V     1.71V      1.915V
2.067ns   1.826V     1.71V      1.511V
2.21ns    1.691V     1.709V     1.425V
2.47ns    1.394V     1.708V     1.358V
2.745ns   1.262V     1.741V     1.327V
3.134ns   1.199V     1.428V     1.31V
3.46ns    1.189V     1.223V     1.305V
3.929ns   1.183V     1.133V     1.304V
10ns      1.181V     1.111V     1.303V
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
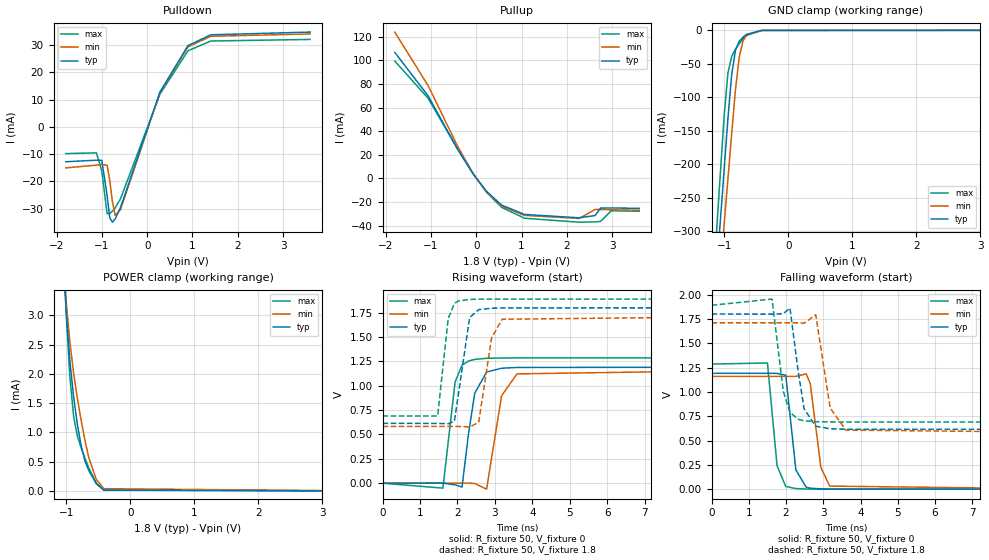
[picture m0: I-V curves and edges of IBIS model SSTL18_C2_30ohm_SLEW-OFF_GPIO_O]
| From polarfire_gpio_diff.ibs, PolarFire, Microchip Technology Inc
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|   Model SSTL18_C2_30ohm_SLEW-OFF_GPIO_O
[Model]   SSTL18_C2_30ohm_SLEW-OFF_GPIO_O
Model_type   Output
Polarity   Non-Inverting
Enable   Active-High
Vmeas =   0.9
Cref =   5p
Rref =   50
Vref =   0.9
|   typ   min   max
C_comp_pullup   2.605e-12   2.605e-12   2.76e-12
C_comp_pulldown  2.605e-12   2.605e-12   2.76e-12
[Temperature Range]  25C   100C   -40C
[Voltage Range]  1.8   1.71   1.89
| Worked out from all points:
|   slope of the pulldown table from 0 to 0.27 V, typ, clamps not added: 21.9 ohm
|   slope of the pullup table from 0 to 0.27 V, typ, clamps not added: 21.3 ohm
|   GND clamp passes 1 mA (typ) near -0.52 V on its own axis
|   POWER clamp passes 1 mA (typ) near -0.81 V on its own axis
|   rising waveform, R_fixture 50, V_fixture 0: 20-80 % time 265ps typ, 290ps min, 225ps max; typ from 0 V to 1.19 V
|   rising waveform, R_fixture 50, V_fixture 1.8: 20-80 % time 228ps typ, 266ps min, 175ps max; typ from 0.614 V to 1.8 V
|   falling waveform, R_fixture 50, V_fixture 0: 20-80 % time 189ps typ, 231ps min, 171ps max; typ from 1.19 V to 0 V
|   falling waveform, R_fixture 50, V_fixture 1.8: 20-80 % time 246ps typ, 269ps min, 246ps max; typ from 1.8 V to 0.614 V
[GND Clamp]
| Voltage   I(typ)   I(min)   I(max)
-1.8V     -1.238A    -1.206A    -1.294A
-1.122V   -361mA     -426.1mA   -300.3mA
-1.063V   -284.7mA   -358.2mA   -213.9mA
-1.004V   -208.5mA   -290.3mA   -128.4mA
-945mV    -132.4mA   -222.5mA   -64.19mA
-885.9mV  -66.33mA   -154.7mA   -38.94mA
-826.9mV  -29.63mA   -88.81mA   -28.27mA
-767.8mV  -16.36mA   -39.95mA   -19.83mA
-708.7mV  -10.12mA   -15.57mA   -12.8mA
-649.7mV  -5.882mA   -6.713mA   -7.364mA
-413.4mV  -69.42uA   -104.8uA   -78.93uA
3.6V      0A         0A         0A
[POWER Clamp]
| Voltage   I(typ)   I(min)   I(max)
-1.8V     45.61mA    35.66mA    60.31mA
-1.063V   4.301mA    4.234mA    4.672mA
-1.004V   3.099mA    3.258mA    3.078mA
-945mV    2.226mA    2.547mA    1.95mA
-885.9mV  1.604mA    2.011mA    1.273mA
-826.9mV  1.131mA    1.577mA    934uA
-767.8mV  765.5uA    1.2mA      735.6uA
-708.7mV  512.4uA    863.2uA    558uA
-649.7mV  349.8uA    570.8uA    394.2uA
-531.6mV  123.5uA    194.8uA    129.3uA
-413.4mV  12.94uA    38.41uA    15.1uA
3.6V      0A         0A         0A
[Pullup]
| Voltage   I(typ)   I(min)   I(max)
-1.8V     106.7mA    123.9mA    99.4mA
-1.063V   69.91mA    78.55mA    67.86mA
-413.4mV  24.8mA     27.4mA     24.98mA
-59.06mV  3.208mA    3.431mA    3.499mA
225mV     -10.83mA   -11.35mA   -11.54mA
562.5mV   -22.63mA   -23.5mA    -24.5mA
1.069V    -30.52mA   -31.3mA    -33.72mA
2.272V    -33.32mA   -33.91mA   -37.05mA
2.627V    -31.44mA   -26.27mA   -36.77mA
2.745V    -25.12mA   -26.35mA   -36.43mA
2.981V    -24.99mA   -26.52mA   -27.42mA
3.6V      -25.33mA   -26.89mA   -27.79mA
[Pulldown]
| Voltage   I(typ)   I(min)   I(max)
-1.8V     -12.79mA   -15.04mA   -9.8mA
-1.122V   -12.21mA   -14.03mA   -9.523mA
-1.004V   -12.25mA   -13.74mA   -16.14mA
-885.9mV  -25.24mA   -14.07mA   -31.84mA
-826.9mV  -33.38mA   -19.64mA   -31.77mA
-767.8mV  -34.95mA   -27.64mA   -30.89mA
-708.7mV  -33.74mA   -32.43mA   -29.71mA
-590.6mV  -29.58mA   -30.37mA   -26.38mA
281.2mV   12.77mA    12.6mA     12.01mA
900mV     29.8mA     29.37mA    27.91mA
1.406V    33.78mA    33.23mA    31.5mA
3.6V      34.77mA    34.09mA    32.08mA
[Ramp]
dV/dt_r   0.714761/0.265307n  0.695664/0.289945n  0.771789/0.224927n
dV/dt_f   0.711324/0.246135n  0.676507/0.268584n  0.719836/0.245677n
R_load = 50
[Rising Waveform]
R_fixture = 50
V_fixture = 0
V_fixture_min = 0
V_fixture_max = 0
| Time   V(typ)   V(min)   V(max)
0s        11.53nV    15.94nV    15.99nV
1.613ns   679.9uV    438.2uV    -50.39mV
1.938ns   -17.02mV   526.5uV    1.038V
2.124ns   -38.77mV   577uV      1.211V
2.296ns   504.9mV    1.069mV    1.254V
2.464ns   924.5mV    -2.947mV   1.271V
2.78ns    1.141V     -61.19mV   1.282V
3.18ns    1.18V      897mV      1.285V
3.592ns   1.188V     1.122V     1.286V
10ns      1.191V     1.159V     1.286V
[Rising Waveform]
R_fixture = 50
V_fixture = 1.8
V_fixture_min = 1.71
V_fixture_max = 1.89
| Time   V(typ)   V(min)   V(max)
0s        614.5mV    582.5mV    690.3mV
1.471ns   613.7mV    582.7mV    689.7mV
1.756ns   610.4mV    582.7mV    1.693V
1.92ns    636.7mV    582.7mV    1.845V
2.017ns   887.9mV    582.7mV    1.869V
2.327ns   1.701V     578.2mV    1.886V
2.568ns   1.782V     623.1mV    1.889V
2.912ns   1.796V     1.49V      1.89V
3.194ns   1.799V     1.683V     1.89V
10ns      1.8V       1.71V      1.89V
[Falling Waveform]
R_fixture = 50
V_fixture = 0
V_fixture_min = 0
V_fixture_max = 0
| Time   V(typ)   V(min)   V(max)
0s        1.191V     1.159V     1.286V
1.501ns   1.191V     1.159V     1.297V
1.759ns   1.19V      1.159V     239.8mV
1.993ns   1.171V     1.159V     28.15mV
2.263ns   198.8mV    1.159V     5.912mV
2.541ns   18.93mV    1.185V     1.724mV
2.65ns    10.88mV    1.085V     1.107mV
2.935ns   2.653mV    223.5mV    203.6uV
3.173ns   1.06mV     31.48mV    196.8uV
10ns      1.149uV    1.845uV    690.2nV
[Falling Waveform]
R_fixture = 50
V_fixture = 1.8
V_fixture_min = 1.71
V_fixture_max = 1.89
| Time   V(typ)   V(min)   V(max)
0s        1.8V       1.71V      1.89V
1.623ns   1.799V     1.71V      1.954V
1.926ns   1.803V     1.71V      1.006V
2.105ns   1.861V     1.71V      790.1mV
2.327ns   1.208V     1.71V      717.8mV
2.486ns   825.9mV    1.706V     702.8mV
2.797ns   647.5mV    1.792V     694mV
3.185ns   620.7mV    834.3mV    691mV
3.61ns    615.9mV    607.1mV    690.4mV
10ns      614.5mV    582.5mV    690.3mV
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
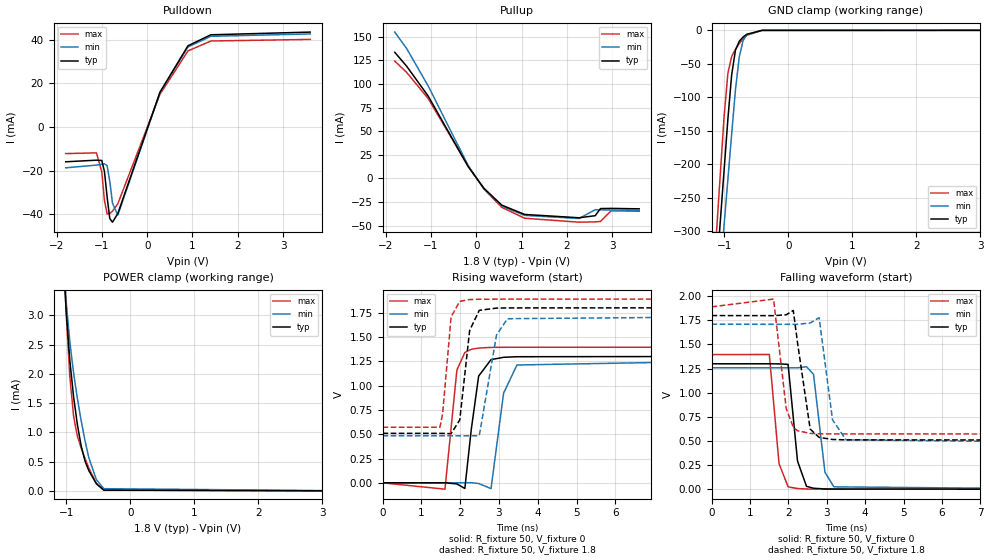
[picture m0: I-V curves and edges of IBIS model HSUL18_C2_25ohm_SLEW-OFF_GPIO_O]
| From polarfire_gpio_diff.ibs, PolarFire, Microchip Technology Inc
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|   Model HSUL18_C2_25ohm_SLEW-OFF_GPIO_O
[Model]   HSUL18_C2_25ohm_SLEW-OFF_GPIO_O
Model_type   Output
Polarity   Non-Inverting
Enable   Active-High
Vmeas =   0.9
Cref =   5p
Rref =   50
Vref =   0.9
|   typ   min   max
C_comp_pullup   2.605e-12   2.605e-12   2.76e-12
C_comp_pulldown  2.605e-12   2.605e-12   2.76e-12
[Temperature Range]  25C   100C   -40C
[Voltage Range]  1.8   1.71   1.89
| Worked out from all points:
|   slope of the pulldown table from 0 to 0.27 V, typ, clamps not added: 17.6 ohm
|   slope of the pullup table from 0 to 0.27 V, typ, clamps not added: 17 ohm
|   GND clamp passes 1 mA (typ) near -0.52 V on its own axis
|   POWER clamp passes 1 mA (typ) near -0.81 V on its own axis
|   rising waveform, R_fixture 50, V_fixture 0: 20-80 % time 225ps typ, 249ps min, 191ps max; typ from 0 V to 1.3 V
|   rising waveform, R_fixture 50, V_fixture 1.8: 20-80 % time 211ps typ, 272ps min, 162ps max; typ from 0.509 V to 1.8 V
|   falling waveform, R_fixture 50, V_fixture 0: 20-80 % time 184ps typ, 207ps min, 168ps max; typ from 1.3 V to 0 V
|   falling waveform, R_fixture 50, V_fixture 1.8: 20-80 % time 229ps typ, 231ps min, 214ps max; typ from 1.8 V to 0.509 V
[GND Clamp]
| Voltage   I(typ)   I(min)   I(max)
-1.8V     -1.238A    -1.206A    -1.294A
-1.122V   -361mA     -426.1mA   -300.3mA
-1.063V   -284.7mA   -358.2mA   -213.9mA
-1.004V   -208.5mA   -290.3mA   -128.4mA
-945mV    -132.4mA   -222.5mA   -64.19mA
-885.9mV  -66.33mA   -154.7mA   -38.94mA
-826.9mV  -29.63mA   -88.81mA   -28.27mA
-767.8mV  -16.36mA   -39.95mA   -19.83mA
-708.7mV  -10.12mA   -15.57mA   -12.8mA
-649.7mV  -5.882mA   -6.713mA   -7.364mA
-413.4mV  -69.42uA   -104.8uA   -78.93uA
3.6V      0A         0A         0A
[POWER Clamp]
| Voltage   I(typ)   I(min)   I(max)
-1.8V     45.61mA    35.66mA    60.31mA
-1.063V   4.301mA    4.234mA    4.672mA
-1.004V   3.099mA    3.258mA    3.078mA
-945mV    2.226mA    2.547mA    1.95mA
-885.9mV  1.604mA    2.011mA    1.273mA
-826.9mV  1.131mA    1.577mA    934uA
-767.8mV  765.5uA    1.2mA      735.6uA
-708.7mV  512.4uA    863.2uA    558uA
-649.7mV  349.8uA    570.8uA    394.2uA
-531.6mV  123.5uA    194.8uA    129.3uA
-413.4mV  12.94uA    38.41uA    15.1uA
3.6V      0A         0A         0A
[Pullup]
| Voltage   I(typ)   I(min)   I(max)
-1.8V     133.4mA    154.8mA    124.1mA
-1.536V   118.6mA    137.3mA    112.1mA
-1.063V   87.19mA    97.9mA     84.56mA
-177.2mV  12.42mA    13.46mA    12.86mA
168.8mV   -10.4mA    -10.92mA   -11.06mA
562.5mV   -28.25mA   -29.34mA   -30.58mA
1.069V    -38.14mA   -39.13mA   -42.14mA
2.272V    -41.65mA   -42.4mA    -46.33mA
2.627V    -39.47mA   -33.15mA   -45.98mA
2.745V    -31.93mA   -33.25mA   -45.56mA
2.981V    -31.74mA   -33.46mA   -34.25mA
3.6V      -32.19mA   -33.94mA   -34.72mA
[Pulldown]
| Voltage   I(typ)   I(min)   I(max)
-1.8V     -15.93mA   -18.7mA    -12.19mA
-1.122V   -15.2mA    -17.44mA   -11.84mA
-1.004V   -15.33mA   -17.07mA   -20.51mA
-945mV    -20.38mA   -16.86mA   -33.69mA
-885.9mV  -32.1mA    -17.67mA   -39.81mA
-826.9mV  -41.9mA    -24.89mA   -39.64mA
-767.8mV  -43.59mA   -34.88mA   -38.53mA
-649.7mV  -39.63mA   -40.33mA   -35.16mA
281.2mV   15.9mA     15.69mA    14.96mA
900mV     37.18mA    36.65mA    34.83mA
1.406V    42.21mA    41.52mA    39.37mA
3.6V      43.45mA    42.61mA    40.1mA
[Ramp]
dV/dt_r   0.780228/0.225338n  0.755215/0.249491n  0.83695/0.191149n
dV/dt_f   0.774419/0.228918n  0.735602/0.231387n  0.790844/0.214246n
R_load = 50
[Rising Waveform]
R_fixture = 50
V_fixture = 0
V_fixture_min = 0
V_fixture_max = 0
| Time   V(typ)   V(min)   V(max)
0s        9.772nV    13.52nV    13.59nV
1.609ns   826.8uV    649.8uV    -65.1mV
1.916ns   -11.23mV   773.8uV    1.159V
2.121ns   -57.87mV   856.6uV    1.341V
2.288ns   551.9mV    1.372mV    1.373V
2.477ns   1.098V     -6.98mV    1.386V
2.796ns   1.267V     -59.84mV   1.393V
3.12ns    1.291V     922.4mV    1.394V
3.465ns   1.297V     1.212V     1.395V
10ns      1.3V       1.259V     1.395V
[Rising Waveform]
R_fixture = 50
V_fixture = 1.8
V_fixture_min = 1.71
V_fixture_max = 1.89
| Time   V(typ)   V(min)   V(max)
0s        509.3mV    484mV      571.9mV
1.479ns   508.8mV    483.7mV    571.7mV
1.548ns   508.8mV    483.7mV    707.9mV
1.767ns   505.7mV    483.7mV    1.706V
1.99ns    646.7mV    483.7mV    1.867V
2.245ns   1.567V     483.6mV    1.885V
2.493ns   1.774V     485.4mV    1.888V
2.938ns   1.797V     1.521V     1.889V
3.219ns   1.799V     1.688V     1.889V
10ns      1.8V       1.71V      1.89V
[Falling Waveform]
R_fixture = 50
V_fixture = 0
V_fixture_min = 0
V_fixture_max = 0
| Time   V(typ)   V(min)   V(max)
0s        1.3V       1.259V     1.395V
1.505ns   1.3V       1.258V     1.396V
1.757ns   1.299V     1.258V     264.7mV
1.993ns   1.294V     1.258V     24.48mV
2.238ns   291.8mV    1.258V     6.17mV
2.472ns   29.36mV    1.27V      2.066mV
2.655ns   9.553mV    1.191V     650.4uV
2.953ns   2.268mV    174.7mV    262.7uV
3.186ns   933.5uV    24.06mV    -11.83uV
10ns      87.07nV    651.1nV    1.004uV
[Falling Waveform]
R_fixture = 50
V_fixture = 1.8
V_fixture_min = 1.71
V_fixture_max = 1.89
| Time   V(typ)   V(min)   V(max)
0s        1.8V       1.71V      1.89V
1.614ns   1.799V     1.709V     1.971V
1.944ns   1.808V     1.709V     837.1mV
2.128ns   1.853V     1.709V     642.5mV
2.241ns   1.511V     1.709V     605.4mV
2.568ns   622.5mV    1.723V     578.4mV
2.801ns   536.9mV    1.778V     574.1mV
3.15ns    515.2mV    719.5mV    572.3mV
3.501ns   511mV      511.5mV    572.1mV
10ns      509.3mV    484mV      571.9mV
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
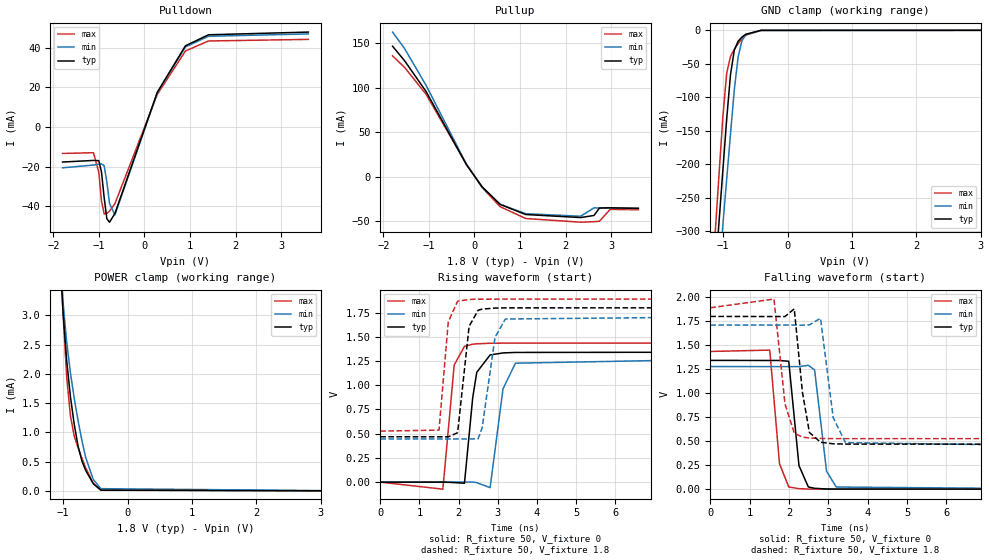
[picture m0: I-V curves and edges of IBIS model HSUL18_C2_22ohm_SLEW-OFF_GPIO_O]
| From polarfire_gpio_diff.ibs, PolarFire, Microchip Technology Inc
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|   Model HSUL18_C2_22ohm_SLEW-OFF_GPIO_O
[Model]   HSUL18_C2_22ohm_SLEW-OFF_GPIO_O
Model_type   Output
Polarity   Non-Inverting
Enable   Active-High
Vmeas =   0.9
Cref =   5p
Rref =   50
Vref =   0.9
|   typ   min   max
C_comp_pullup   2.605e-12   2.605e-12   2.76e-12
C_comp_pulldown  2.605e-12   2.605e-12   2.76e-12
[Temperature Range]  25C   100C   -40C
[Voltage Range]  1.8   1.71   1.89
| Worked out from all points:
|   slope of the pulldown table from 0 to 0.27 V, typ, clamps not added: 16 ohm
|   slope of the pullup table from 0 to 0.27 V, typ, clamps not added: 15.5 ohm
|   GND clamp passes 1 mA (typ) near -0.52 V on its own axis
|   POWER clamp passes 1 mA (typ) near -0.81 V on its own axis
|   rising waveform, R_fixture 50, V_fixture 0: 20-80 % time 211ps typ, 248ps min, 175ps max; typ from 0 V to 1.34 V
|   rising waveform, R_fixture 50, V_fixture 1.8: 20-80 % time 201ps typ, 266ps min, 147ps max; typ from 0.469 V to 1.8 V
|   falling waveform, R_fixture 50, V_fixture 0: 20-80 % time 178ps typ, 202ps min, 161ps max; typ from 1.34 V to 0 V
|   falling waveform, R_fixture 50, V_fixture 1.8: 20-80 % time 199ps typ, 232ps min, 206ps max; typ from 1.8 V to 0.469 V
[GND Clamp]
| Voltage   I(typ)   I(min)   I(max)
-1.8V     -1.238A    -1.206A    -1.294A
-1.122V   -361mA     -426.1mA   -300.3mA
-1.063V   -284.7mA   -358.2mA   -213.9mA
-1.004V   -208.5mA   -290.3mA   -128.4mA
-945mV    -132.4mA   -222.5mA   -64.19mA
-885.9mV  -66.33mA   -154.7mA   -38.94mA
-826.9mV  -29.63mA   -88.81mA   -28.27mA
-767.8mV  -16.36mA   -39.95mA   -19.83mA
-708.7mV  -10.12mA   -15.57mA   -12.8mA
-649.7mV  -5.882mA   -6.713mA   -7.364mA
-413.4mV  -69.42uA   -104.8uA   -78.93uA
3.6V      0A         0A         0A
[POWER Clamp]
| Voltage   I(typ)   I(min)   I(max)
-1.8V     45.61mA    35.66mA    60.31mA
-1.063V   4.301mA    4.234mA    4.672mA
-1.004V   3.099mA    3.258mA    3.078mA
-945mV    2.226mA    2.547mA    1.95mA
-885.9mV  1.604mA    2.011mA    1.273mA
-826.9mV  1.131mA    1.577mA    934uA
-767.8mV  765.5uA    1.2mA      735.6uA
-708.7mV  512.4uA    863.2uA    558uA
-649.7mV  349.8uA    570.8uA    394.2uA
-531.6mV  123.5uA    194.8uA    129.3uA
-413.4mV  12.94uA    38.41uA    15.1uA
3.6V      0A         0A         0A
[Pullup]
| Voltage   I(typ)   I(min)   I(max)
-1.8V     146.7mA    162.6mA    135.9mA
-1.536V   130.4mA    144.1mA    122.9mA
-1.063V   95.74mA    102.7mA    92.62mA
-177.2mV  13.64mA    14.12mA    14.09mA
168.8mV   -11.43mA   -11.45mA   -12.11mA
562.5mV   -31.06mA   -30.8mA    -33.57mA
1.125V    -42.41mA   -41.5mA    -46.89mA
2.332V    -45.83mA   -44.35mA   -51.03mA
2.627V    -43.45mA   -34.9mA    -50.5mA
2.745V    -35.11mA   -35mA      -50mA
2.981V    -34.87mA   -35.22mA   -36.59mA
3.6V      -35.36mA   -35.73mA   -37.07mA
[Pulldown]
| Voltage   I(typ)   I(min)   I(max)
-1.8V     -17.65mA   -20.56mA   -13.33mA
-1.122V   -16.84mA   -19.17mA   -12.96mA
-1.004V   -16.96mA   -18.76mA   -22.77mA
-945mV    -22.61mA   -18.54mA   -37.26mA
-885.9mV  -35.62mA   -19.51mA   -43.78mA
-826.9mV  -46.22mA   -27.6mA    -43.56mA
-767.8mV  -47.94mA   -38.57mA   -42.33mA
-649.7mV  -43.55mA   -44.29mA   -38.61mA
281.2mV   17.46mA    17.22mA    16.42mA
900mV     40.88mA    40.28mA    38.28mA
1.406V    46.43mA    45.67mA    43.3mA
3.6V      47.78mA    46.86mA    44.11mA
[Ramp]
dV/dt_r   0.804991/0.210602n  0.766878/0.247762n  0.861155/0.17514n
dV/dt_f   0.798846/0.199102n  0.758309/0.231748n  0.818102/0.205848n
R_load = 50
[Rising Waveform]
R_fixture = 50
V_fixture = 0
V_fixture_min = 0
V_fixture_max = 0
| Time   V(typ)   V(min)   V(max)
0s        9.077nV    12.57nV    12.65nV
1.598ns   767.8uV    502.5uV    -72.42mV
1.888ns   -4.335mV   593.6uV    1.209V
2.15ns    -11.21mV   676uV      1.402V
2.361ns   873.1mV    927.7uV    1.424V
2.464ns   1.134V     -5.287mV   1.428V
2.805ns   1.313V     -56.25mV   1.434V
3.135ns   1.334V     964.6mV    1.435V
3.452ns   1.339V     1.228V     1.435V
10ns      1.342V     1.278V     1.435V
[Rising Waveform]
R_fixture = 50
V_fixture = 1.8
V_fixture_min = 1.71
V_fixture_max = 1.89
| Time   V(typ)   V(min)   V(max)
0s        468.6mV    446.1mV    526.5mV
1.5ns     467.9mV    445.8mV    537.4mV
1.737ns   467.8mV    445.7mV    1.656V
1.975ns   510.6mV    445.7mV    1.868V
2.269ns   1.609V     445.6mV    1.886V
2.5ns     1.775V     448.1mV    1.889V
2.601ns   1.786V     559.9mV    1.889V
2.93ns    1.797V     1.495V     1.889V
3.195ns   1.799V     1.684V     1.89V
10ns      1.8V       1.71V      1.89V
[Falling Waveform]
R_fixture = 50
V_fixture = 0
V_fixture_min = 0
V_fixture_max = 0
| Time   V(typ)   V(min)   V(max)
0s        1.342V     1.278V     1.435V
1.512ns   1.341V     1.277V     1.449V
1.759ns   1.341V     1.277V     265.7mV
1.994ns   1.333V     1.277V     22.75mV
2.254ns   244.9mV    1.277V     5.028mV
2.492ns   22.9mV     1.291V     1.508mV
2.651ns   8.897mV    1.242V     878.1uV
2.955ns   2.033mV    186.3mV    181.5uV
3.202ns   798.8uV    22.26mV    175.1uV
10ns      115.1nV    3.352uV    74.15nV
[Falling Waveform]
R_fixture = 50
V_fixture = 1.8
V_fixture_min = 1.71
V_fixture_max = 1.89
| Time   V(typ)   V(min)   V(max)
0s        1.8V       1.71V      1.89V
1.619ns   1.799V     1.71V      1.981V
1.899ns   1.799V     1.71V      887.3mV
2.134ns   1.879V     1.71V      584.3mV
2.342ns   1.009V     1.709V     542mV
2.519ns   591.1mV    1.712V     533.4mV
2.801ns   488.9mV    1.781V     528.5mV
3.123ns   472.8mV    746.5mV    526.6mV
3.435ns   469.8mV    484.9mV    526.6mV
10ns      468.6mV    446.2mV    526.5mV
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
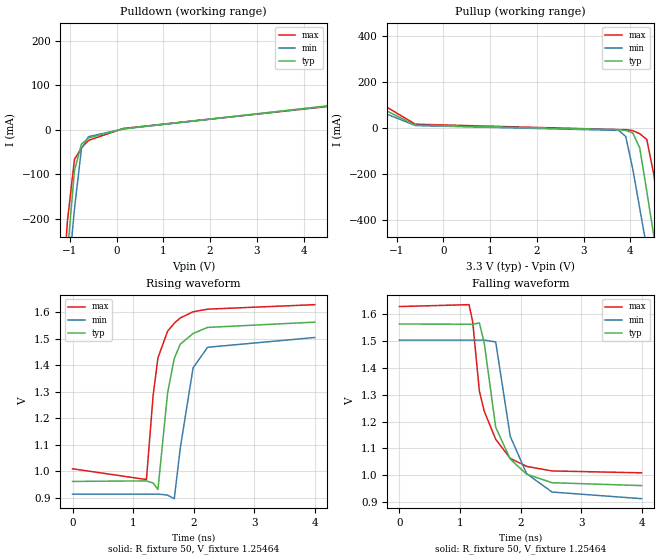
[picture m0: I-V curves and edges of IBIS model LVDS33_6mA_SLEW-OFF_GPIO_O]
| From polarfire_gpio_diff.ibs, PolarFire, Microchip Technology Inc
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|   Model LVDS33_6mA_SLEW-OFF_GPIO_O
[Model]   LVDS33_6mA_SLEW-OFF_GPIO_O
Model_type   Output
Polarity   Non-Inverting
Enable   Active-High
Vmeas =   1.2
Cref =   5p
Rref =   100
|   typ   min   max
C_comp_pullup   2.605e-12   2.605e-12   2.76e-12
C_comp_pulldown  2.605e-12   2.605e-12   2.76e-12
[Temperature Range]  25C   100C   -40C
[Voltage Range]  3.3   3.15   3.45
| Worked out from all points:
|   slope of the pulldown table from 0 to 0.495 V, typ, clamps not added: 91 ohm
|   slope of the pullup table from 0 to 0.495 V, typ, clamps not added: 102 ohm
|   rising waveform, R_fixture 50, V_fixture 1.25464: 20-80 % time 217ps typ, 231ps min, 228ps max; typ from 0.961 V to 1.56 V
|   falling waveform, R_fixture 50, V_fixture 1.25464: 20-80 % time 343ps typ, 340ps min, 357ps max; typ from 1.56 V to 0.961 V
[Pulldown]
|Voltage   I(typ)   I(min)   I(max)
-3.3V     -3.224A    -2.967A    -3.554A
-1.2V     -469.5mA   -522.1mA   -423.7mA
-1.05V    -275.6mA   -349.5mA   -204mA
-900mV    -91.45mA   -177.1mA   -66.2mA
-750mV    -31.79mA   -41.78mA   -40.32mA
-600mV    -18.41mA   -15.35mA   -23.65mA
150mV     2.545mA    2.056mA    3.214mA
4.5V      53.6mA     53.17mA    52.09mA
5.1V      120.5mA    114mA      125mA
5.7V      204.2mA    187.4mA    220.7mA
6V        250.4mA    229.5mA    272.3mA
6.6V      354.3mA    321.2mA    384.9mA
[Pullup]
|Voltage   I(typ)   I(min)   I(max)
-3.3V     376.5mA    318mA      438.5mA
-1.8V     133.6mA    108.6mA    162.5mA
-600mV    13.4mA     11.37mA    17.26mA
3.75V     -6.487mA   -9.789mA   -6.346mA
3.9V      -9.671mA   -36.15mA   -6.599mA
4.05V     -20.47mA   -176.3mA   -10.51mA
4.2V      -85.38mA   -348.5mA   -23.97mA
4.35V     -273.1mA   -520.9mA   -48.78mA
4.5V      -466.9mA   -693.2mA   -199.9mA
4.65V     -660.8mA   -865.6mA   -419.3mA
4.8V      -855mA     -1.038A    -638.8mA
6.6V      -3.219A    -3.139A    -3.32A
[Ramp]
| variable   typ   min   max
dV/dt_r 0.3794/0.2186e-9   0.3687/0.2334e-9   0.3981/0.2254e-9
dV/dt_f 0.3644/0.3414e-9   0.3574/0.3394e-9   0.3767/0.3544e-9
R_load = 50
[Rising waveform]
R_fixture= 50
V_fixture= 1.25464
V_fixture_min= 1.19616
V_fixture_max= 1.31676
|Time   V(typ)   V(min)   V(max)
0s        961.2mV    912.9mV    1.009V
1.22ns    963.2mV    912.9mV    968.3mV
1.33ns    955.4mV    912.8mV    1.285V
1.41ns    930.7mV    913.5mV    1.428V
1.57ns    1.296V     909.4mV    1.529V
1.68ns    1.426V     896mV      1.559V
1.78ns    1.48V      1.089V     1.579V
1.99ns    1.52V      1.39V      1.602V
2.23ns    1.543V     1.468V     1.612V
4ns       1.563V     1.505V     1.629V
[Falling waveform]
R_fixture= 50
V_fixture= 1.25464
V_fixture_min= 1.19616
V_fixture_max= 1.31676
|Time   V(typ)   V(min)   V(max)
0s        1.564V     1.504V     1.629V
1.15ns    1.563V     1.504V     1.636V
1.21ns    1.563V     1.504V     1.572V
1.32ns    1.568V     1.504V     1.314V
1.4ns     1.494V     1.504V     1.239V
1.59ns    1.179V     1.497V     1.134V
1.83ns    1.06V      1.145V     1.063V
2.1ns     1.004V     1.006V     1.033V
2.52ns    972.1mV    937.4mV    1.016V
4ns       961.4mV    912.6mV    1.009V
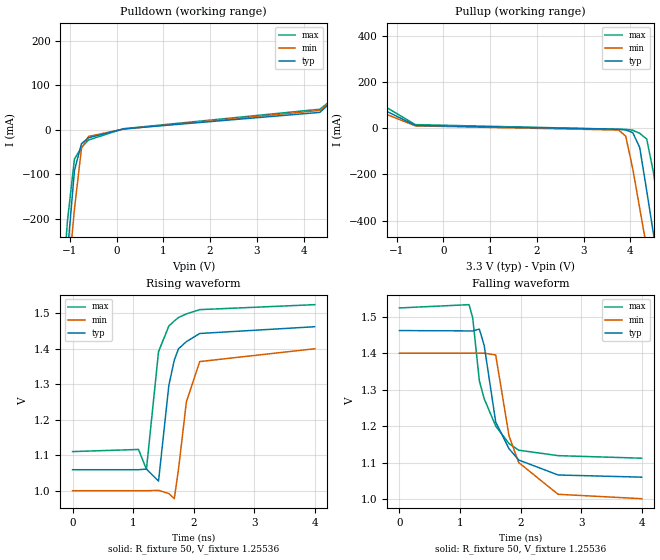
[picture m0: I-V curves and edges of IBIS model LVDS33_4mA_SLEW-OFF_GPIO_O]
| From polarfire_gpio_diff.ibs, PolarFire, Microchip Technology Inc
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|   Model LVDS33_4mA_SLEW-OFF_GPIO_O
[Model]   LVDS33_4mA_SLEW-OFF_GPIO_O
Model_type   Output
Polarity   Non-Inverting
Enable   Active-High
Vmeas =   1.2
Cref =   5p
Rref =   100
|   typ   min   max
C_comp_pullup   2.605e-12   2.605e-12   2.76e-12
C_comp_pulldown  2.605e-12   2.605e-12   2.76e-12
[Temperature Range]  25C   100C   -40C
[Voltage Range]  3.3   3.15   3.45
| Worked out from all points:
|   slope of the pulldown table from 0 to 0.495 V, typ, clamps not added: 137 ohm
|   slope of the pullup table from 0 to 0.495 V, typ, clamps not added: 138 ohm
|   rising waveform, R_fixture 50, V_fixture 1.25536: 20-80 % time 214ps typ, 210ps min, 224ps max; typ from 1.06 V to 1.46 V
|   falling waveform, R_fixture 50, V_fixture 1.25536: 20-80 % time 367ps typ, 351ps min, 375ps max; typ from 1.46 V to 1.06 V
[Pulldown]
|Voltage   I(typ)   I(min)   I(max)
-3.3V     -3.224A    -2.966A    -3.554A
-1.2V     -469.2mA   -521.8mA   -423.3mA
-1.05V    -275.2mA   -349.2mA   -203.6mA
-900mV    -90.84mA   -176.8mA   -65.16mA
-750mV    -30.98mA   -41.22mA   -39.32mA
-600mV    -17.67mA   -14.79mA   -22.72mA
150mV     2.057mA    1.715mA    2.543mA
4.35V     39.09mA    43.53mA    46.18mA
4.8V      82.17mA    80.68mA    82.99mA
5.7V      202mA      185.5mA    218.5mA
6V        248.2mA    227.4mA    270mA
6.6V      351.9mA    318.9mA    382.4mA
[Pullup]
|Voltage   I(typ)   I(min)   I(max)
-3.3V     375.9mA    317.7mA    437.2mA
-1.8V     131.5mA    107.2mA    159.9mA
-600mV    12.28mA    10.48mA    15.87mA
3.75V     -4.424mA   -7.758mA   -4.26mA
3.9V      -7.63mA    -34.22mA   -4.517mA
4.05V     -18.46mA   -174.5mA   -8.457mA
4.2V      -83.59mA   -346.8mA   -21.94mA
4.35V     -271.4mA   -519.1mA   -46.79mA
4.5V      -465.1mA   -691.4mA   -198.2mA
4.65V     -659.1mA   -863.8mA   -417.6mA
4.8V      -853.2mA   -1.036A    -637.1mA
6.6V      -3.217A    -3.137A    -3.318A
[Ramp]
| variable   typ   min   max
dV/dt_r 0.2623/0.2137e-9   0.2555/0.2127e-9   0.2779/0.2117e-9
dV/dt_f 0.2437/0.3650e-9   0.2419/0.3501e-9   0.2528/0.3709e-9
R_load = 50
[Rising waveform]
R_fixture= 50
V_fixture= 1.25536
V_fixture_min= 1.19490
V_fixture_max= 1.31638
|Time   V(typ)   V(min)   V(max)
0s        1.06V      1.001V     1.111V
1.09ns    1.06V      1.001V     1.117V
1.22ns    1.062V     1.001V     1.061V
1.42ns    1.028V     1.002V     1.392V
1.59ns    1.297V     993.1mV    1.464V
1.68ns    1.368V     978.6mV    1.478V
1.75ns    1.4V       1.062V     1.488V
1.88ns    1.42V      1.251V     1.498V
2.1ns     1.443V     1.364V     1.51V
4ns       1.462V     1.4V       1.524V
[Falling waveform]
R_fixture= 50
V_fixture= 1.25536
V_fixture_min= 1.19490
V_fixture_max= 1.31638
|Time   V(typ)   V(min)   V(max)
0s        1.462V     1.4V       1.524V
1.15ns    1.461V     1.4V       1.533V
1.21ns    1.461V     1.4V       1.497V
1.32ns    1.466V     1.4V       1.324V
1.4ns     1.421V     1.4V       1.275V
1.59ns    1.211V     1.395V     1.2V
1.81ns    1.138V     1.173V     1.152V
1.97ns    1.107V     1.1V       1.134V
2.62ns    1.066V     1.013V     1.119V
4ns       1.06V      1.001V     1.112V
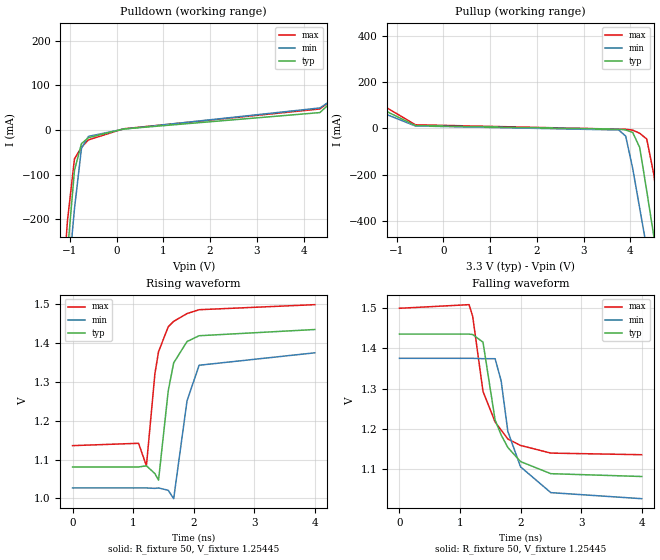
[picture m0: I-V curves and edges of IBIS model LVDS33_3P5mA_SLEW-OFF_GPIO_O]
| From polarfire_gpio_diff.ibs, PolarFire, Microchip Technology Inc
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|   Model LVDS33_3P5mA_SLEW-OFF_GPIO_O
[Model]   LVDS33_3P5mA_SLEW-OFF_GPIO_O
Model_type   Output
Polarity   Non-Inverting
Enable   Active-High
Vmeas =   1.2
Cref =   5p
Rref =   100
|   typ   min   max
C_comp_pullup   2.605e-12   2.605e-12   2.76e-12
C_comp_pulldown  2.605e-12   2.605e-12   2.76e-12
[Temperature Range]  25C   100C   -40C
[Voltage Range]  3.3   3.15   3.45
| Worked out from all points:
|   slope of the pulldown table from 0 to 0.495 V, typ, clamps not added: 154 ohm
|   slope of the pullup table from 0 to 0.495 V, typ, clamps not added: 154 ohm
|   rising waveform, R_fixture 50, V_fixture 1.25445: 20-80 % time 210ps typ, 207ps min, 227ps max; typ from 1.08 V to 1.44 V
|   falling waveform, R_fixture 50, V_fixture 1.25445: 20-80 % time 366ps typ, 358ps min, 381ps max; typ from 1.44 V to 1.08 V
[Pulldown]
|Voltage   I(typ)   I(min)   I(max)
-3.3V     -3.224A    -2.966A    -3.554A
-1.2V     -469.1mA   -521.8mA   -423.2mA
-1.05V    -275.1mA   -349.1mA   -203.5mA
-900mV    -90.69mA   -176.7mA   -64.87mA
-750mV    -30.77mA   -41.04mA   -39.04mA
-600mV    -17.48mA   -14.6mA    -22.46mA
150mV     1.916mA    1.585mA    2.335mA
4.35V     38.64mA    48.99mA    46.67mA
4.8V      81.73mA    80.14mA    82.48mA
5.7V      201.6mA    184.9mA    218mA
6V        247.7mA    226.8mA    269.4mA
6.6V      351.3mA    318.3mA    381.8mA
[Pullup]
|Voltage   I(typ)   I(min)   I(max)
-3.3V     375.8mA    317.6mA    437mA
-1.8V     130.9mA    106.9mA    159.2mA
-600mV    11.9mA     10.17mA    15.4mA
3.75V     -3.915mA   -7.256mA   -3.747mA
3.9V      -7.126mA   -33.75mA   -4.005mA
4.05V     -17.97mA   -174.1mA   -7.952mA
4.2V      -83.15mA   -346.3mA   -21.45mA
4.35V     -271mA     -518.7mA   -46.31mA
4.5V      -464.7mA   -691mA     -197.8mA
4.65V     -658.6mA   -863.4mA   -417.2mA
4.8V      -852.8mA   -1.036A    -636.7mA
6.6V      -3.216A    -3.137A    -3.318A
[Ramp]
| variable   typ   min   max
dV/dt_r 0.2351/0.2070e-9   0.2255/0.2106e-9   0.2486/0.2191e-9
dV/dt_f 0.2152/0.3633e-9   0.2110/0.3565e-9   0.2236/0.3776e-9
R_load = 50
[Rising waveform]
R_fixture= 50
V_fixture= 1.25445
V_fixture_min= 1.19435
V_fixture_max= 1.31632
|Time   V(typ)   V(min)   V(max)
0s        1.081V     1.027V     1.136V
1.09ns    1.081V     1.027V     1.142V
1.22ns    1.084V     1.027V     1.084V
1.36ns    1.064V     1.026V     1.321V
1.42ns    1.047V     1.027V     1.378V
1.58ns    1.277V     1.021V     1.442V
1.67ns    1.349V     999.4mV    1.456V
1.89ns    1.404V     1.251V     1.476V
2.09ns    1.419V     1.343V     1.486V
4ns       1.435V     1.375V     1.499V
[Falling waveform]
R_fixture= 50
V_fixture= 1.25445
V_fixture_min= 1.19435
V_fixture_max= 1.31632
|Time   V(typ)   V(min)   V(max)
0s        1.435V     1.375V     1.499V
1.15ns    1.435V     1.375V     1.508V
1.21ns    1.434V     1.375V     1.479V
1.38ns    1.415V     1.374V     1.293V
1.58ns    1.222V     1.374V     1.217V
1.68ns    1.185V     1.319V     1.197V
1.79ns    1.154V     1.194V     1.175V
2ns       1.119V     1.106V     1.159V
2.5ns     1.089V     1.042V     1.14V
4ns       1.082V     1.027V     1.136V
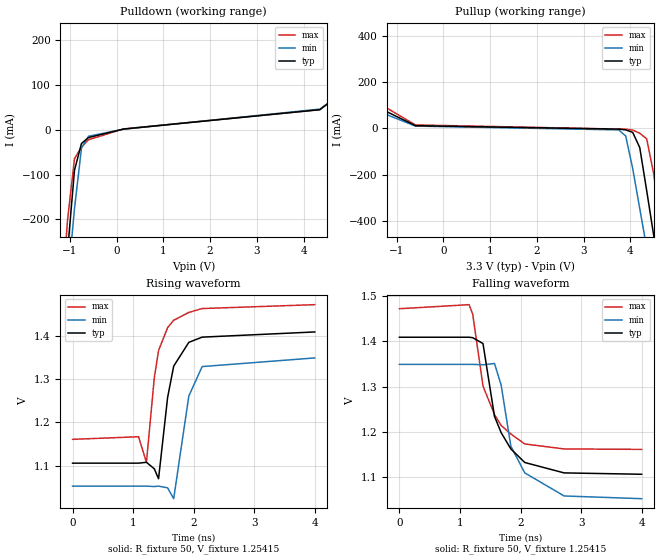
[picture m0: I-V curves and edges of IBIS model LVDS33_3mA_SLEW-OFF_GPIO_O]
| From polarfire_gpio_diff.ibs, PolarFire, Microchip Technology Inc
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|   Model LVDS33_3mA_SLEW-OFF_GPIO_O
[Model]   LVDS33_3mA_SLEW-OFF_GPIO_O
Model_type   Output
Polarity   Non-Inverting
Enable   Active-High
Vmeas =   1.2
Cref =   5p
Rref =   100
|   typ   min   max
C_comp_pullup   2.605e-12   2.605e-12   2.76e-12
C_comp_pulldown  2.605e-12   2.605e-12   2.76e-12
[Temperature Range]  25C   100C   -40C
[Voltage Range]  3.3   3.15   3.45
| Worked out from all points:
|   slope of the pulldown table from 0 to 0.495 V, typ, clamps not added: 181 ohm
|   slope of the pullup table from 0 to 0.495 V, typ, clamps not added: 176 ohm
|   rising waveform, R_fixture 50, V_fixture 1.25415: 20-80 % time 203ps typ, 208ps min, 225ps max; typ from 1.11 V to 1.41 V
|   falling waveform, R_fixture 50, V_fixture 1.25415: 20-80 % time 376ps typ, 359ps min, 393ps max; typ from 1.41 V to 1.11 V
[Pulldown]
|Voltage   I(typ)   I(min)   I(max)
-3.3V     -3.224A    -2.966A    -3.554A
-1.2V     -469mA     -521.6mA   -423.1mA
-1.05V    -275mA     -349mA     -203.4mA
-900mV    -90.51mA   -176.6mA   -64.54mA
-750mV    -30.52mA   -40.85mA   -38.71mA
-600mV    -17.24mA   -14.4mA    -22.16mA
150mV     1.734mA    1.436mA    2.085mA
4.35V     45.13mA    46.45mA    45.13mA
4.8V      81.22mA    79.61mA    81.95mA
5.7V      201mA      184.3mA    217.4mA
6V        247.1mA    226.2mA    268.8mA
6.6V      350.7mA    317.6mA    381.1mA
[Pullup]
|Voltage   I(typ)   I(min)   I(max)
-3.3V     375.6mA    317.5mA    436.8mA
-1.8V     130.3mA    106.7mA    158.5mA
-600mV    11.44mA    9.794mA    14.82mA
3.75V     -3.395mA   -6.745mA   -3.22mA
3.9V      -6.611mA   -33.27mA   -3.479mA
4.05V     -17.46mA   -173.7mA   -7.432mA
4.2V      -82.7mA    -345.9mA   -20.94mA
4.35V     -270.5mA   -518.2mA   -45.81mA
4.5V      -464.3mA   -690.5mA   -197.4mA
4.65V     -658.2mA   -862.9mA   -416.8mA
4.8V      -852.4mA   -1.036A    -636.3mA
6.6V      -3.216A    -3.136A    -3.317A
[Ramp]
| variable   typ   min   max
dV/dt_r 0.2049/0.2069e-9   0.1949/0.2141e-9   0.2188/0.2106e-9
dV/dt_f 0.1847/0.3732e-9   0.1803/0.3589e-9   0.1924/0.3911e-9
R_load = 50
[Rising waveform]
R_fixture= 50
V_fixture= 1.25415
V_fixture_min= 1.19418
V_fixture_max= 1.31585
|Time   V(typ)   V(min)   V(max)
0s        1.106V     1.053V     1.161V
1.09ns    1.106V     1.053V     1.167V
1.22ns    1.108V     1.053V     1.108V
1.35ns    1.093V     1.052V     1.303V
1.42ns    1.07V      1.053V     1.366V
1.57ns    1.258V     1.049V     1.419V
1.67ns    1.33V      1.024V     1.436V
1.92ns    1.385V     1.261V     1.454V
2.14ns    1.397V     1.329V     1.463V
4ns       1.409V     1.349V     1.472V
[Falling waveform]
R_fixture= 50
V_fixture= 1.25415
V_fixture_min= 1.19418
V_fixture_max= 1.31585
|Time   V(typ)   V(min)   V(max)
0s        1.409V     1.349V     1.472V
1.15ns    1.409V     1.349V     1.481V
1.21ns    1.408V     1.349V     1.46V
1.38ns    1.395V     1.348V     1.301V
1.57ns    1.234V     1.351V     1.238V
1.68ns    1.198V     1.303V     1.214V
1.84ns    1.162V     1.168V     1.195V
2.07ns    1.132V     1.109V     1.173V
2.72ns    1.109V     1.058V     1.162V
4ns       1.106V     1.052V     1.161V
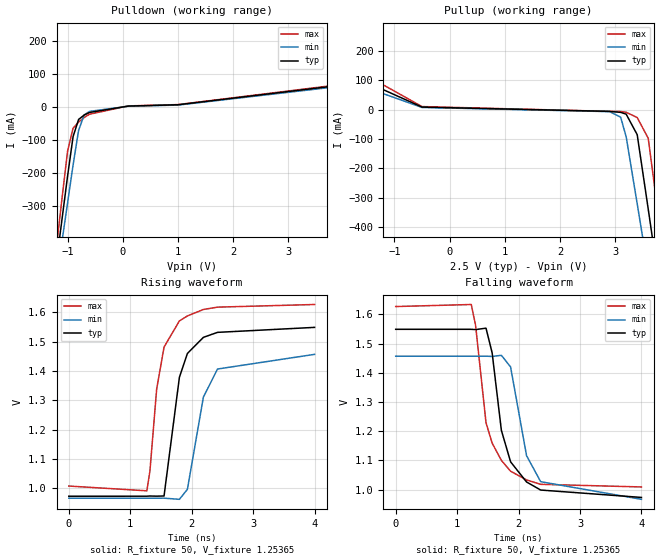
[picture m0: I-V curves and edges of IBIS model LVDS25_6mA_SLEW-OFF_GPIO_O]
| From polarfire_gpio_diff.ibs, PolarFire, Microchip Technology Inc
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|   Model LVDS25_6mA_SLEW-OFF_GPIO_O
[Model]   LVDS25_6mA_SLEW-OFF_GPIO_O
Model_type   Output
Polarity   Non-Inverting
Enable   Active-High
Vmeas =   1.2
Cref =   5p
Rref =   100
|   typ   min   max
C_comp_pullup   2.605e-12   2.605e-12   2.76e-12
C_comp_pulldown  2.605e-12   2.605e-12   2.76e-12
[Temperature Range]  25C   100C   -40C
[Voltage Range]  2.5   2.375   2.625
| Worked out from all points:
|   slope of the pulldown table from 0 to 0.375 V, typ, clamps not added: 79.8 ohm
|   slope of the pullup table from 0 to 0.375 V, typ, clamps not added: 103 ohm
|   rising waveform, R_fixture 50, V_fixture 1.25365: 20-80 % time 246ps typ, 283ps min, 234ps max; typ from 0.973 V to 1.55 V
|   falling waveform, R_fixture 50, V_fixture 1.25365: 20-80 % time 293ps typ, 292ps min, 300ps max; typ from 1.55 V to 0.973 V
[Pulldown]
|Voltage   I(typ)   I(min)   I(max)
-2.5V     -2.164A    -2.027A    -2.345A
-1.2V     -469.1mA   -521.6mA   -423.3mA
-1.1V     -339.8mA   -406.6mA   -276.8mA
-1V       -210.6mA   -291.5mA   -134.8mA
-900mV    -90.76mA   -176.6mA   -65.28mA
-800mV    -38.77mA   -71.91mA   -46.79mA
-700mV    -25.53mA   -25.3mA    -33.01mA
-600mV    -17.63mA   -14.4mA    -22.93mA
100mV     1.625mA    1.197mA    2.165mA
1V        5.624mA    4.616mA    6.177mA
3.8V      61.7mA     58.7mA     63.76mA
5V        215.8mA    192.9mA    239.1mA
[Pullup]
|Voltage   I(typ)   I(min)   I(max)
-2.5V     231mA      189.7mA    278.3mA
-1.5V     92.37mA    73.59mA    114.8mA
-500mV    8.223mA    6.996mA    9.978mA
2.9V      -6.309mA   -7.178mA   -6.34mA
3.1V      -9.649mA   -26.05mA   -6.809mA
3.2V      -15.72mA   -92.26mA   -9.299mA
3.4V      -85.36mA   -319.6mA   -27.17mA
3.6V      -337.7mA   -549.4mA   -97.56mA
3.8V      -596.1mA   -779.2mA   -382.7mA
3.9V      -725.5mA   -894.2mA   -529.1mA
4V        -855mA     -1.009A    -675.4mA
5V        -2.159A    -2.17A     -2.151A
[Ramp]
| variable   typ   min   max
dV/dt_r 0.3510/0.2469e-9   0.2975/0.2823e-9   0.3813/0.2321e-9
dV/dt_f 0.3489/0.2929e-9   0.2970/0.2934e-9   0.3760/0.2986e-9
R_load = 50
[Rising waveform]
R_fixture= 50
V_fixture= 1.25365
V_fixture_min= 1.19649
V_fixture_max= 1.31735
|Time   V(typ)   V(min)   V(max)
0s        973.3mV    966.6mV    1.008V
1.27ns    973.4mV    966.6mV    991.7mV
1.32ns    974mV      966.6mV    1.059V
1.43ns    973.5mV    966.6mV    1.339V
1.55ns    974.1mV    966.7mV    1.482V
1.8ns     1.379V     962.7mV    1.571V
1.93ns    1.46V      996.8mV    1.588V
2.19ns    1.515V     1.311V     1.61V
2.42ns    1.532V     1.407V     1.618V
4ns       1.549V     1.457V     1.627V
[Falling waveform]
R_fixture= 50
V_fixture= 1.25365
V_fixture_min= 1.19649
V_fixture_max= 1.31735
|Time   V(typ)   V(min)   V(max)
0s        1.549V     1.457V     1.627V
1.23ns    1.549V     1.457V     1.634V
1.3ns     1.548V     1.457V     1.563V
1.47ns    1.553V     1.457V     1.229V
1.57ns    1.468V     1.456V     1.159V
1.72ns    1.203V     1.46V      1.1V
1.87ns    1.095V     1.42V      1.063V
2.13ns    1.026V     1.116V     1.033V
2.36ns    998.4mV    1.027V     1.018V
4ns       973.1mV    966.6mV    1.009V
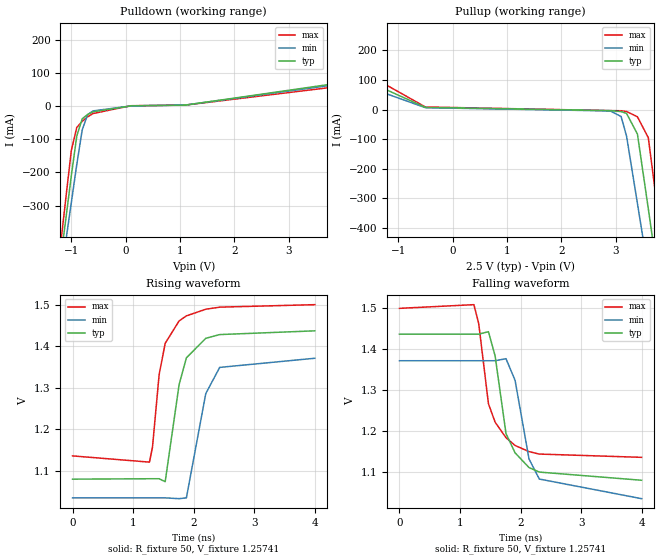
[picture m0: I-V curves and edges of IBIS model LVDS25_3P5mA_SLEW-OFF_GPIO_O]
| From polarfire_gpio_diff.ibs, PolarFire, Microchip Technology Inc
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|   Model LVDS25_3P5mA_SLEW-OFF_GPIO_O
[Model]   LVDS25_3P5mA_SLEW-OFF_GPIO_O
Model_type   Output
Polarity   Non-Inverting
Enable   Active-High
Vmeas =   1.2
Cref =   5p
Rref =   100
|   typ   min   max
C_comp_pullup   2.605e-12   2.605e-12   2.76e-12
C_comp_pulldown  2.605e-12   2.605e-12   2.76e-12
[Temperature Range]  25C   100C   -40C
[Voltage Range]  2.5   2.375   2.625
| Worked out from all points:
|   slope of the pulldown table from 0 to 0.375 V, typ, clamps not added: 119 ohm
|   slope of the pullup table from 0 to 0.375 V, typ, clamps not added: 142 ohm
|   rising waveform, R_fixture 50, V_fixture 1.25741: 20-80 % time 230ps typ, 256ps min, 224ps max; typ from 1.08 V to 1.44 V
|   falling waveform, R_fixture 50, V_fixture 1.25741: 20-80 % time 293ps typ, 286ps min, 292ps max; typ from 1.44 V to 1.08 V
[Pulldown]
|Voltage   I(typ)   I(min)   I(max)
-2.5V     -2.163A    -2.027A    -2.344A
-1.2V     -468.8mA   -521.4mA   -422.8mA
-1.1V     -339.4mA   -406.3mA   -276.4mA
-1V       -210.2mA   -291.3mA   -134mA
-900mV    -90.15mA   -176.4mA   -64.04mA
-800mV    -37.94mA   -71.58mA   -45.57mA
-700mV    -24.73mA   -24.86mA   -31.84mA
-600mV    -16.88mA   -13.98mA   -21.82mA
100mV     1.315mA    1.026mA    1.662mA
1.1V      3.55mA     3.791mA    3.61mA
3.9V      69.59mA    66.12mA    59.49mA
5V        213.5mA    191.4mA    236.2mA
[Pullup]
|Voltage   I(typ)   I(min)   I(max)
-2.5V     229.1mA    189.1mA    275.4mA
-1.5V     90.1mA     71.86mA    112mA
-500mV    7.112mA    6.145mA    8.577mA
2.9V      -3.752mA   -4.836mA   -3.744mA
3.1V      -7.121mA   -23.79mA   -4.222mA
3.2V      -13.22mA   -90.21mA   -6.735mA
3.4V      -83.14mA   -317.6mA   -24.66mA
3.6V      -335.5mA   -547.4mA   -95.33mA
3.8V      -594mA     -777.1mA   -380.6mA
3.9V      -723.3mA   -892.1mA   -526.9mA
4V        -852.8mA   -1.007A    -673.3mA
5V        -2.157A    -2.168A    -2.149A
[Ramp]
| variable   typ   min   max
dV/dt_r 0.2195/0.2297e-9   0.2056/0.2577e-9   0.2280/0.2191e-9
dV/dt_f 0.2180/0.2930e-9   0.2051/0.2880e-9   0.2244/0.2893e-9
R_load = 50
[Rising waveform]
R_fixture= 50
V_fixture= 1.25741
V_fixture_min= 1.19791
V_fixture_max= 1.31823
|Time   V(typ)   V(min)   V(max)
0s        1.08V      1.035V     1.136V
1.27ns    1.081V     1.035V     1.121V
1.32ns    1.081V     1.035V     1.157V
1.43ns    1.081V     1.035V     1.332V
1.53ns    1.074V     1.035V     1.407V
1.76ns    1.308V     1.033V     1.461V
1.88ns    1.372V     1.035V     1.473V
2.2ns     1.419V     1.286V     1.489V
2.43ns    1.428V     1.349V     1.494V
4ns       1.437V     1.371V     1.5V
[Falling waveform]
R_fixture= 50
V_fixture= 1.25741
V_fixture_min= 1.19791
V_fixture_max= 1.31823
|Time   V(typ)   V(min)   V(max)
0s        1.437V     1.372V     1.5V
1.23ns    1.437V     1.372V     1.509V
1.31ns    1.437V     1.372V     1.462V
1.47ns    1.443V     1.372V     1.267V
1.58ns    1.384V     1.372V     1.222V
1.76ns    1.194V     1.377V     1.184V
1.91ns    1.147V     1.324V     1.165V
2.14ns    1.111V     1.132V     1.15V
2.31ns    1.1V       1.083V     1.144V
4ns       1.08V      1.035V     1.136V
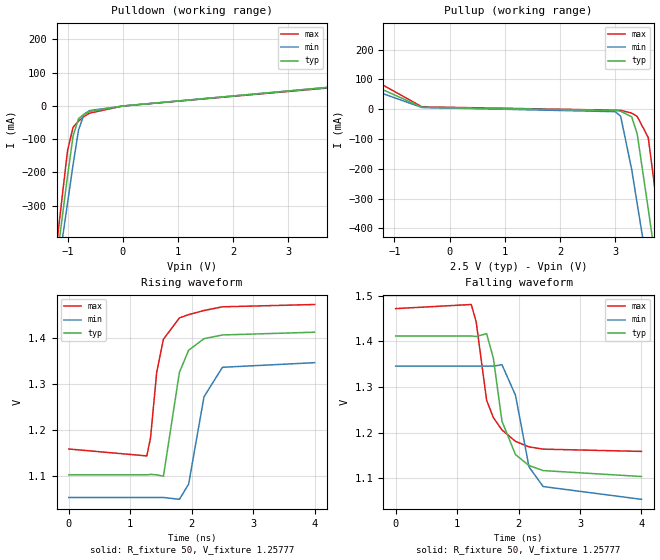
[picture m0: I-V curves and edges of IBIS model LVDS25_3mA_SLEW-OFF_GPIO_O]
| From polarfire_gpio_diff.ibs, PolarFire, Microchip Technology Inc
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|   Model LVDS25_3mA_SLEW-OFF_GPIO_O
[Model]   LVDS25_3mA_SLEW-OFF_GPIO_O
Model_type   Output
Polarity   Non-Inverting
Enable   Active-High
Vmeas =   1.2
Cref =   5p
Rref =   100
|   typ   min   max
C_comp_pullup   2.605e-12   2.605e-12   2.76e-12
C_comp_pulldown  2.605e-12   2.605e-12   2.76e-12
[Temperature Range]  25C   100C   -40C
[Voltage Range]  2.5   2.375   2.625
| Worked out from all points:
|   slope of the pulldown table from 0 to 0.375 V, typ, clamps not added: 136 ohm
|   slope of the pullup table from 0 to 0.375 V, typ, clamps not added: 159 ohm
|   rising waveform, R_fixture 50, V_fixture 1.25777: 20-80 % time 221ps typ, 252ps min, 229ps max; typ from 1.1 V to 1.41 V
|   falling waveform, R_fixture 50, V_fixture 1.25777: 20-80 % time 278ps typ, 272ps min, 297ps max; typ from 1.41 V to 1.1 V
[Pulldown]
|Voltage   I(typ)   I(min)   I(max)
-2.5V     -2.163A    -2.027A    -2.344A
-1.2V     -468.7mA   -521.3mA   -422.7mA
-1.1V     -339.3mA   -406.3mA   -276.2mA
-1V       -210.1mA   -291.2mA   -133.8mA
-900mV    -90mA      -176.3mA   -63.74mA
-800mV    -37.73mA   -71.46mA   -45.27mA
-700mV    -24.52mA   -24.7mA    -31.55mA
-600mV    -16.69mA   -13.83mA   -21.55mA
0V        -62.81uA   -53.56uA   -77.28uA
3.7V      55.7mA     55.68mA    53.84mA
4.3V      115.4mA    105.7mA    123.7mA
5V        213mA      190.9mA    235.7mA
[Pullup]
|Voltage   I(typ)   I(min)   I(max)
-2.5V     228.9mA    189.1mA    274.7mA
-1.5V     89.55mA    71.48mA    111.3mA
-500mV    6.764mA    5.877mA    8.138mA
3V        -3.849mA   -8.116mA   -3.244mA
3.1V      -6.607mA   -23.31mA   -3.697mA
3.3V      -25.21mA   -202.3mA   -12.85mA
3.4V      -82.69mA   -317.2mA   -24.15mA
3.6V      -335.1mA   -546.9mA   -94.88mA
3.8V      -593.5mA   -776.7mA   -380.2mA
3.9V      -722.9mA   -891.7mA   -526.5mA
4V        -852.4mA   -1.007A    -672.9mA
5V        -2.157A    -2.168A    -2.149A
[Ramp]
| variable   typ   min   max
dV/dt_r 0.1904/0.2241e-9   0.1788/0.2545e-9   0.1974/0.2259e-9
dV/dt_f 0.1888/0.2766e-9   0.1782/0.2745e-9   0.1940/0.2925e-9
R_load = 50
[Rising waveform]
R_fixture= 50
V_fixture= 1.25777
V_fixture_min= 1.19496
V_fixture_max= 1.31587
|Time   V(typ)   V(min)   V(max)
0s        1.103V     1.054V     1.159V
1.27ns    1.103V     1.054V     1.144V
1.33ns    1.104V     1.054V     1.183V
1.43ns    1.103V     1.054V     1.325V
1.54ns    1.1V       1.054V     1.397V
1.8ns     1.325V     1.05V      1.443V
1.95ns    1.373V     1.083V     1.45V
2.2ns     1.398V     1.272V     1.459V
2.5ns     1.406V     1.336V     1.467V
4ns       1.412V     1.346V     1.472V
[Falling waveform]
R_fixture= 50
V_fixture= 1.25777
V_fixture_min= 1.19496
V_fixture_max= 1.31587
|Time   V(typ)   V(min)   V(max)
0s        1.412V     1.346V     1.472V
1.23ns    1.412V     1.346V     1.481V
1.31ns    1.411V     1.346V     1.443V
1.48ns    1.417V     1.346V     1.271V
1.59ns    1.363V     1.346V     1.233V
1.73ns    1.225V     1.349V     1.206V
1.95ns    1.152V     1.282V     1.181V
2.17ns    1.128V     1.125V     1.169V
2.4ns     1.117V     1.082V     1.164V
4ns       1.104V     1.054V     1.159V
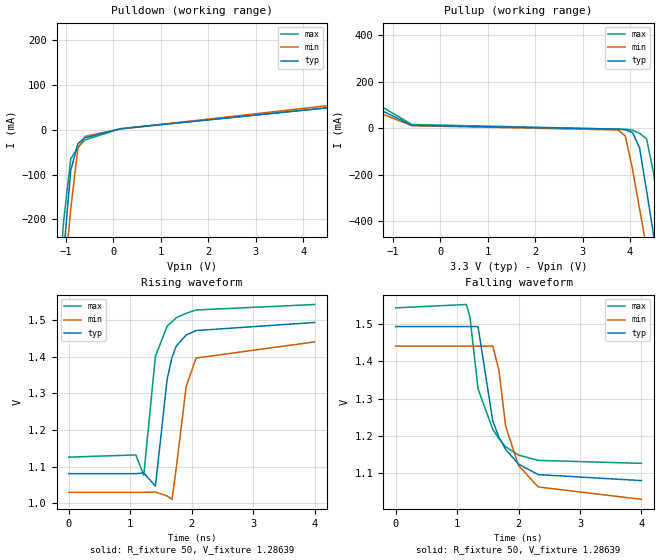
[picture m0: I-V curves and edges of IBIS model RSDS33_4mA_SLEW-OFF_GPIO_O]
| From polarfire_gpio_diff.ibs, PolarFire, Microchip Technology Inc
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|   Model RSDS33_4mA_SLEW-OFF_GPIO_O
[Model]   RSDS33_4mA_SLEW-OFF_GPIO_O
Model_type   Output
Polarity   Non-Inverting
Enable   Active-High
Vmeas =   1.2
Cref =   5p
Rref =   100
|   typ   min   max
C_comp_pullup   2.605e-12   2.605e-12   2.76e-12
C_comp_pulldown  2.605e-12   2.605e-12   2.76e-12
[Temperature Range]  25C   100C   -40C
[Voltage Range]  3.3   3.15   3.45
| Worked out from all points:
|   slope of the pulldown table from 0 to 0.495 V, typ, clamps not added: 131 ohm
|   slope of the pullup table from 0 to 0.495 V, typ, clamps not added: 138 ohm
|   rising waveform, R_fixture 50, V_fixture 1.28639: 20-80 % time 217ps typ, 213ps min, 225ps max; typ from 1.08 V to 1.49 V
|   falling waveform, R_fixture 50, V_fixture 1.28639: 20-80 % time 361ps typ, 345ps min, 363ps max; typ from 1.49 V to 1.08 V
[Pulldown]
|Voltage   I(typ)   I(min)   I(max)
-3.3V     -3.224A    -2.966A    -3.554A
-1.2V     -469.2mA   -521.9mA   -423.3mA
-1.05V    -275.2mA   -349.3mA   -203.6mA
-900mV    -90.9mA    -176.8mA   -65.17mA
-750mV    -31.06mA   -41.29mA   -39.33mA
-600mV    -17.74mA   -14.85mA   -22.73mA
150mV     2.109mA    1.753mA    2.55mA
4.5V      48.75mA    53.5mA     49mA
5.1V      118.6mA    112.3mA    122.9mA
5.7V      202.2mA    185.6mA    218.5mA
6V        248.4mA    227.6mA    270mA
6.6V      352.1mA    319.1mA    382.4mA
[Pullup]
|Voltage   I(typ)   I(min)   I(max)
-3.3V     375.8mA    317.6mA    437.1mA
-1.8V     131.4mA    107.2mA    159.8mA
-600mV    12.28mA    10.47mA    15.87mA
3.75V     -4.425mA   -7.762mA   -4.261mA
3.9V      -7.632mA   -34.23mA   -4.518mA
4.05V     -18.47mA   -174.5mA   -8.46mA
4.2V      -83.6mA    -346.8mA   -21.95mA
4.35V     -271.4mA   -519.1mA   -46.8mA
4.5V      -465.1mA   -691.4mA   -198.2mA
4.65V     -659.1mA   -863.8mA   -417.6mA
4.8V      -853.2mA   -1.036A    -637.1mA
6.6V      -3.217A    -3.137A    -3.318A
[Ramp]
| variable   typ   min   max
dV/dt_r 0.2683/0.2154e-9   0.2608/0.2144e-9   0.2791/0.2129e-9
dV/dt_f 0.2502/0.3593e-9   0.2483/0.3433e-9   0.2545/0.3609e-9
R_load = 50
[Rising waveform]
R_fixture= 50
V_fixture= 1.28639
V_fixture_min= 1.23495
V_fixture_max= 1.33430
|Time   V(typ)   V(min)   V(max)
0s        1.081V     1.03V      1.126V
1.09ns    1.081V     1.03V      1.132V
1.22ns    1.083V     1.03V      1.077V
1.41ns    1.047V     1.031V     1.401V
1.6ns     1.338V     1.02V      1.483V
1.68ns    1.398V     1.011V     1.495V
1.75ns    1.429V     1.098V     1.506V
1.91ns    1.459V     1.318V     1.518V
2.07ns    1.471V     1.396V     1.527V
4ns       1.493V     1.44V      1.542V
[Falling waveform]
R_fixture= 50
V_fixture= 1.28639
V_fixture_min= 1.23495
V_fixture_max= 1.33430
|Time   V(typ)   V(min)   V(max)
0s        1.492V     1.44V      1.542V
1.15ns    1.492V     1.44V      1.551V
1.21ns    1.492V     1.44V      1.516V
1.34ns    1.492V     1.44V      1.326V
1.58ns    1.24V      1.44V      1.218V
1.68ns    1.197V     1.376V     1.193V
1.79ns    1.164V     1.226V     1.171V
2ns       1.125V     1.121V     1.149V
2.32ns    1.097V     1.064V     1.135V
4ns       1.081V     1.031V     1.127V
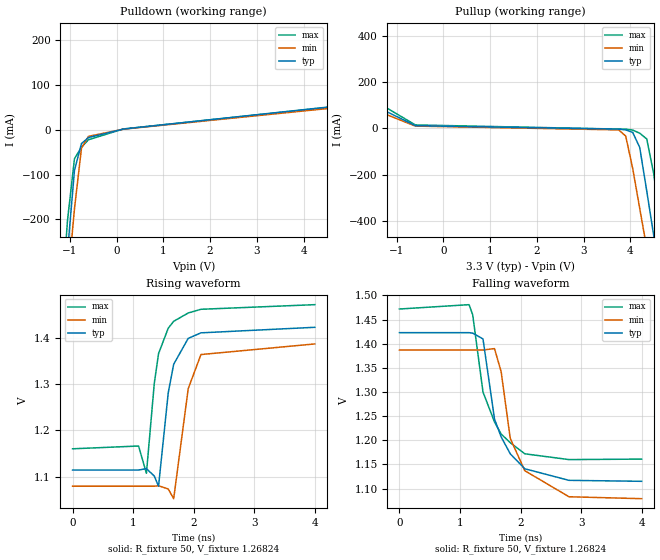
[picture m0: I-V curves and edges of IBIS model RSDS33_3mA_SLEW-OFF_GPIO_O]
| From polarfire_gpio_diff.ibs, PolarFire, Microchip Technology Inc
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|   Model RSDS33_3mA_SLEW-OFF_GPIO_O
[Model]   RSDS33_3mA_SLEW-OFF_GPIO_O
Model_type   Output
Polarity   Non-Inverting
Enable   Active-High
Vmeas =   1.2
Cref =   5p
Rref =   100
|   typ   min   max
C_comp_pullup   2.605e-12   2.605e-12   2.76e-12
C_comp_pulldown  2.605e-12   2.605e-12   2.76e-12
[Temperature Range]  25C   100C   -40C
[Voltage Range]  3.3   3.15   3.45
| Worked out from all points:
|   slope of the pulldown table from 0 to 0.495 V, typ, clamps not added: 175 ohm
|   slope of the pullup table from 0 to 0.495 V, typ, clamps not added: 176 ohm
|   rising waveform, R_fixture 50, V_fixture 1.26824: 20-80 % time 211ps typ, 208ps min, 225ps max; typ from 1.11 V to 1.42 V
|   falling waveform, R_fixture 50, V_fixture 1.26824: 20-80 % time 372ps typ, 355ps min, 393ps max; typ from 1.42 V to 1.11 V
[Pulldown]
|Voltage   I(typ)   I(min)   I(max)
-3.3V     -3.224A    -2.966A    -3.554A
-1.2V     -469mA     -521.7mA   -423.1mA
-1.05V    -275mA     -349.1mA   -203.4mA
-900mV    -90.55mA   -176.6mA   -64.55mA
-750mV    -30.57mA   -40.94mA   -38.72mA
-600mV    -17.3mA    -14.49mA   -22.17mA
150mV     1.774mA    1.499mA    2.091mA
4.5V      50.71mA    47.47mA    49.95mA
5.1V      117.6mA    111.2mA    121.9mA
5.7V      201.1mA    184.5mA    217.4mA
6V        247.2mA    226.4mA    268.8mA
6.6V      350.8mA    317.8mA    381.1mA
[Pullup]
|Voltage   I(typ)   I(min)   I(max)
-3.3V     375.6mA    317.5mA    436.8mA
-1.8V     130.3mA    106.6mA    158.5mA
-600mV    11.44mA    9.793mA    14.82mA
3.75V     -3.395mA   -6.748mA   -3.22mA
3.9V      -6.612mA   -33.27mA   -3.479mA
4.05V     -17.46mA   -173.7mA   -7.432mA
4.2V      -82.7mA    -345.9mA   -20.94mA
4.35V     -270.5mA   -518.2mA   -45.81mA
4.5V      -464.3mA   -690.5mA   -197.4mA
4.65V     -658.2mA   -862.9mA   -416.8mA
4.8V      -852.4mA   -1.036A    -636.3mA
6.6V      -3.216A    -3.136A    -3.317A
[Ramp]
| variable   typ   min   max
dV/dt_r 0.2082/0.2132e-9   0.2015/0.2154e-9   0.2191/0.2107e-9
dV/dt_f 0.1885/0.3697e-9   0.1878/0.3541e-9   0.1928/0.3910e-9
R_load = 50
[Rising waveform]
R_fixture= 50
V_fixture= 1.26824
V_fixture_min= 1.23302
V_fixture_max= 1.31582
|Time   V(typ)   V(min)   V(max)
0s        1.114V     1.079V     1.16V
1.09ns    1.114V     1.079V     1.166V
1.22ns    1.117V     1.079V     1.107V
1.35ns    1.101V     1.079V     1.302V
1.42ns    1.079V     1.08V      1.366V
1.58ns    1.281V     1.073V     1.421V
1.67ns    1.343V     1.052V     1.436V
1.91ns    1.399V     1.29V      1.454V
2.12ns    1.411V     1.364V     1.462V
4ns       1.423V     1.387V     1.472V
[Falling waveform]
R_fixture= 50
V_fixture= 1.26824
V_fixture_min= 1.23302
V_fixture_max= 1.31582
|Time   V(typ)   V(min)   V(max)
0s        1.423V     1.387V     1.472V
1.15ns    1.423V     1.387V     1.481V
1.21ns    1.422V     1.387V     1.46V
1.38ns    1.41V      1.387V     1.3V
1.57ns    1.244V     1.39V      1.238V
1.68ns    1.207V     1.342V     1.213V
1.83ns    1.172V     1.204V     1.195V
2.07ns    1.141V     1.137V     1.172V
2.8ns     1.117V     1.083V     1.16V
4ns       1.115V     1.079V     1.161V
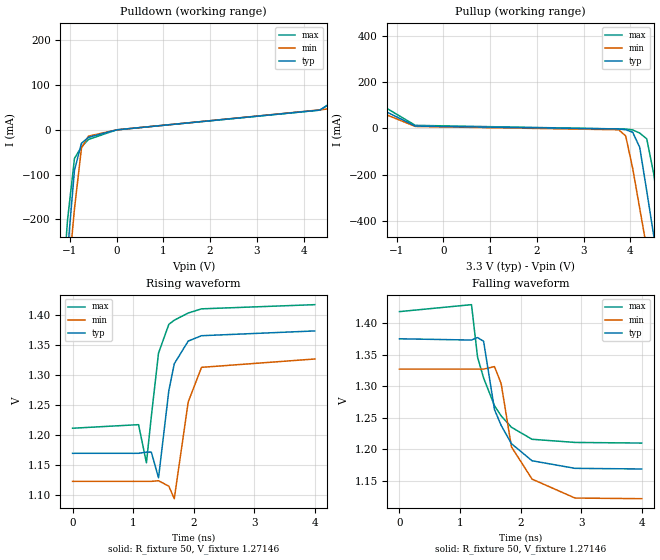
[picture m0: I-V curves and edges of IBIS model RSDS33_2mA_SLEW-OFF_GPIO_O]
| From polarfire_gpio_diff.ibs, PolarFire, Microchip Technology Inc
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|   Model RSDS33_2mA_SLEW-OFF_GPIO_O
[Model]   RSDS33_2mA_SLEW-OFF_GPIO_O
Model_type   Output
Polarity   Non-Inverting
Enable   Active-High
Vmeas =   1.2
Cref =   5p
Rref =   100
|   typ   min   max
C_comp_pullup   2.605e-12   2.605e-12   2.76e-12
C_comp_pulldown  2.605e-12   2.605e-12   2.76e-12
[Temperature Range]  25C   100C   -40C
[Voltage Range]  3.3   3.15   3.45
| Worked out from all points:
|   slope of the pulldown table from 0 to 0.495 V, typ, clamps not added: 267 ohm
|   slope of the pullup table from 0 to 0.495 V, typ, clamps not added: 256 ohm
|   rising waveform, R_fixture 50, V_fixture 1.27146: 20-80 % time 212ps typ, 202ps min, 232ps max; typ from 1.17 V to 1.37 V
|   falling waveform, R_fixture 50, V_fixture 1.27146: 20-80 % time 395ps typ, 378ps min, 430ps max; typ from 1.37 V to 1.17 V
[Pulldown]
|Voltage   I(typ)   I(min)   I(max)
-3.3V     -3.224A    -2.966A    -3.553A
-1.2V     -468.8mA   -521.5mA   -422.8mA
-1.05V    -274.8mA   -348.9mA   -203.1mA
-900mV    -90.14mA   -176.4mA   -63.81mA
-750mV    -30.01mA   -40.53mA   -38mA
-600mV    -16.77mA   -14.07mA   -21.49mA
0V        -62.59uA   -54.79uA   -75.54uA
4.35V     44.18mA    44.63mA    44.07mA
4.65V     64.29mA    48.48mA    64.42mA
5.85V     222.6mA    204mA      241.6mA
6V        246mA      225.2mA    267.6mA
6.6V      349.5mA    316.6mA    379.8mA
[Pullup]
|Voltage   I(typ)   I(min)   I(max)
-3.3V     375.4mA    317.4mA    436.5mA
-1.8V     129.3mA    106.3mA    157.2mA
-600mV    10.23mA    8.544mA    13.33mA
3.75V     -2.36mA    -5.728mA   -2.172mA
3.9V      -5.587mA   -32.3mA    -2.433mA
4.05V     -16.46mA   -172.8mA   -6.399mA
4.2V      -81.81mA   -345mA     -19.92mA
4.35V     -269.7mA   -517.4mA   -44.83mA
4.5V      -463.4mA   -689.6mA   -196.5mA
4.65V     -657.3mA   -862.1mA   -415.9mA
4.8V      -851.5mA   -1.035A    -635.4mA
6.6V      -3.215A    -3.135A    -3.316A
[Ramp]
| variable   typ   min   max
dV/dt_r 0.1484/0.2067e-9   0.1414/0.2136e-9   0.1587/0.2133e-9
dV/dt_f 0.1273/0.3909e-9   0.1264/0.3765e-9   0.1318/0.4234e-9
R_load = 50
[Rising waveform]
R_fixture= 50
V_fixture= 1.27146
V_fixture_min= 1.22475
V_fixture_max= 1.31409
|Time   V(typ)   V(min)   V(max)
0s        1.169V     1.122V     1.211V
1.09ns    1.169V     1.122V     1.217V
1.22ns    1.171V     1.122V     1.153V
1.3ns     1.171V     1.122V     1.23V
1.42ns    1.128V     1.123V     1.337V
1.59ns    1.274V     1.114V     1.385V
1.68ns    1.319V     1.093V     1.392V
1.91ns    1.357V     1.255V     1.404V
2.13ns    1.366V     1.313V     1.411V
4ns       1.374V     1.327V     1.418V
[Falling waveform]
R_fixture= 50
V_fixture= 1.27146
V_fixture_min= 1.22475
V_fixture_max= 1.31409
|Time   V(typ)   V(min)   V(max)
0s        1.375V     1.327V     1.418V
1.19ns    1.373V     1.327V     1.429V
1.29ns    1.377V     1.327V     1.346V
1.39ns    1.371V     1.327V     1.313V
1.57ns    1.263V     1.331V     1.269V
1.68ns    1.238V     1.304V     1.253V
1.85ns    1.209V     1.204V     1.235V
2.19ns    1.182V     1.153V     1.216V
2.9ns     1.17V      1.123V     1.211V
4ns       1.169V     1.122V     1.21V
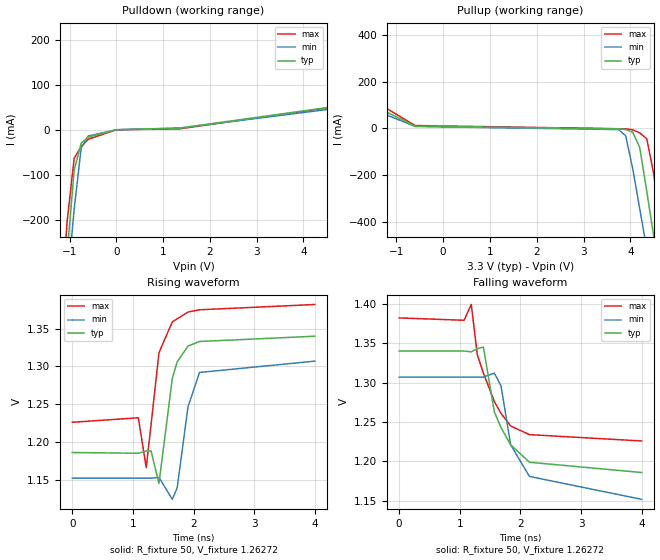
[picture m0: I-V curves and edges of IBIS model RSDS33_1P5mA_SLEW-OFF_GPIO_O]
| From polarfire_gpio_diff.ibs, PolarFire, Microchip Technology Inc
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|   Model RSDS33_1P5mA_SLEW-OFF_GPIO_O
[Model]   RSDS33_1P5mA_SLEW-OFF_GPIO_O
Model_type   Output
Polarity   Non-Inverting
Enable   Active-High
Vmeas =   1.2
Cref =   5p
Rref =   100
|   typ   min   max
C_comp_pullup   2.605e-12   2.605e-12   2.76e-12
C_comp_pulldown  2.605e-12   2.605e-12   2.76e-12
[Temperature Range]  25C   100C   -40C
[Voltage Range]  3.3   3.15   3.45
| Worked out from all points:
|   slope of the pulldown table from 0 to 0.495 V, typ, clamps not added: 360 ohm
|   slope of the pullup table from 0 to 0.495 V, typ, clamps not added: 335 ohm
|   rising waveform, R_fixture 50, V_fixture 1.26272: 20-80 % time 213ps typ, 212ps min, 245ps max; typ from 1.19 V to 1.34 V
|   falling waveform, R_fixture 50, V_fixture 1.26272: 20-80 % time 424ps typ, 401ps min, 460ps max; typ from 1.34 V to 1.19 V
[Pulldown]
|Voltage   I(typ)   I(min)   I(max)
-3.3V     -3.224A    -2.966A    -3.553A
-1.2V     -468.7mA   -521.4mA   -422.6mA
-1.05V    -274.7mA   -348.8mA   -202.9mA
-900mV    -89.9mA    -176.3mA   -63.38mA
-750mV    -29.68mA   -40.3mA    -37.59mA
-600mV    -16.47mA   -13.82mA   -21.1mA
0V        -61.09uA   -54.01uA   -73.68uA
1.35V     3.622mA    3.634mA    2.018mA
4.5V      49.13mA    44.9mA     48.35mA
5.85V     222mA      203.4mA    241mA
6V        245.4mA    224.6mA    267mA
6.6V      348.9mA    315.9mA    379.1mA
[Pullup]
|Voltage   I(typ)   I(min)   I(max)
-3.3V     375.3mA    317.3mA    436.4mA
-1.8V     128.9mA    106.2mA    156.6mA
-600mV    9.431mA    8.212mA    12.32mA
3.75V     -1.849mA   -5.224mA   -1.656mA
3.9V      -5.081mA   -31.83mA   -1.918mA
4.05V     -15.96mA   -172.3mA   -5.89mA
4.2V      -81.37mA   -344.6mA   -19.42mA
4.35V     -269.2mA   -516.9mA   -44.34mA
4.5V      -463mA     -689.2mA   -196.1mA
4.65V     -656.9mA   -861.6mA   -415.5mA
4.8V      -851.1mA   -1.034A    -635mA
6.6V      -3.215A    -3.135A    -3.316A
[Ramp]
| variable   typ   min   max
dV/dt_r 0.1188/0.2116e-9   0.1118/0.2160e-9   0.1294/0.2143e-9
dV/dt_f 97.1275e-3/0.4202e-9   96.1620e-3/0.3977e-9   0.1039/0.4443e-9
R_load = 50
[Rising waveform]
R_fixture= 50
V_fixture= 1.26272
V_fixture_min= 1.23014
V_fixture_max= 1.30355
|Time   V(typ)   V(min)   V(max)
0s        1.186V     1.152V     1.226V
1.09ns    1.185V     1.152V     1.232V
1.22ns    1.188V     1.152V     1.166V
1.3ns     1.188V     1.152V     1.223V
1.43ns    1.145V     1.153V     1.318V
1.65ns    1.284V     1.124V     1.359V
1.73ns    1.306V     1.139V     1.363V
1.91ns    1.327V     1.247V     1.372V
2.1ns     1.333V     1.292V     1.375V
4ns       1.34V      1.307V     1.382V
[Falling waveform]
R_fixture= 50
V_fixture= 1.26272
V_fixture_min= 1.23014
V_fixture_max= 1.30355
|Time   V(typ)   V(min)   V(max)
0s        1.34V      1.307V     1.382V
1.07ns    1.34V      1.307V     1.379V
1.19ns    1.339V     1.307V     1.399V
1.29ns    1.343V     1.307V     1.335V
1.39ns    1.345V     1.307V     1.312V
1.57ns    1.263V     1.312V     1.276V
1.68ns    1.243V     1.296V     1.261V
1.84ns    1.221V     1.221V     1.245V
2.15ns    1.199V     1.181V     1.234V
4ns       1.186V     1.152V     1.226V
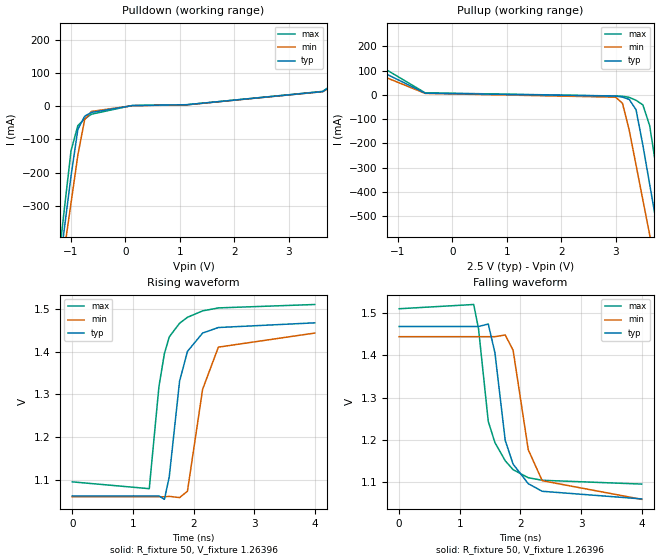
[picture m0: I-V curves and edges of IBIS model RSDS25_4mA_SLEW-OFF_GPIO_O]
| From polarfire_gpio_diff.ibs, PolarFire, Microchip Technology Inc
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|   Model RSDS25_4mA_SLEW-OFF_GPIO_O
[Model]   RSDS25_4mA_SLEW-OFF_GPIO_O
Model_type   Output
Polarity   Non-Inverting
Enable   Active-High
Vmeas =   1.2
Cref =   5p
Rref =   100
|   typ   min   max
C_comp_pullup   2.605e-12   2.605e-12   2.76e-12
C_comp_pulldown  2.605e-12   2.605e-12   2.76e-12
[Temperature Range]  25C   100C   -40C
[Voltage Range]  2.5   2.375   2.625
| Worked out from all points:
|   slope of the pulldown table from 0 to 0.375 V, typ, clamps not added: 104 ohm
|   slope of the pullup table from 0 to 0.375 V, typ, clamps not added: 129 ohm
|   rising waveform, R_fixture 50, V_fixture 1.26396: 20-80 % time 237ps typ, 267ps min, 224ps max; typ from 1.06 V to 1.47 V
|   falling waveform, R_fixture 50, V_fixture 1.26396: 20-80 % time 285ps typ, 277ps min, 301ps max; typ from 1.47 V to 1.06 V
[Pulldown]
|Voltage   I(typ)   I(min)   I(max)
-2.5V     -2.163A    -2.027A    -2.344A
-1.25V    -533.5mA   -579mA     -496.2mA
-1.125V   -371.8mA   -435.2mA   -313.1mA
-1V       -210.3mA   -291.4mA   -134.2mA
-875mV    -69.78mA   -147.7mA   -58.61mA
-750mV    -30.28mA   -40.57mA   -38.56mA
-625mV    -18.76mA   -15.87mA   -24.22mA
125mV     1.72mA     1.354mA    2.168mA
1.125V    4.483mA    4.05mA     4.173mA
3.625V    43.99mA    43.83mA    44.66mA
4.25V     110.1mA    101.4mA    117.8mA
5V        214mA      191.9mA    236.8mA
[Pullup]
|Voltage   I(typ)   I(min)   I(max)
-2.5V     229.4mA    189.2mA    276mA
-500mV    7.398mA    6.363mA    8.937mA
3V        -4.875mA   -9.107mA   -4.283mA
3.125V    -8.809mA   -34.2mA    -5.077mA
3.25V     -18.45mA   -145.9mA   -9.951mA
3.375V    -60.99mA   -289.3mA   -21.93mA
3.5V      -206.9mA   -433mA     -40.86mA
3.625V    -368.2mA   -576.5mA   -126.5mA
3.75V     -529.7mA   -720.1mA   -307.9mA
3.875V    -691.4mA   -863.8mA   -490.8mA
4V        -853.2mA   -1.008A    -673.7mA
5V        -2.158A    -2.169A    -2.15A
[Ramp]
| variable   typ   min   max
dV/dt_r 0.2489/0.2374e-9   0.2334/0.2687e-9   0.2590/0.2213e-9
dV/dt_f 0.2480/0.2848e-9   0.2334/0.2783e-9   0.2544/0.2983e-9
R_load = 50
[Rising waveform]
R_fixture= 50
V_fixture= 1.26396
V_fixture_min= 1.25128
V_fixture_max= 1.30289
|Time   V(typ)   V(min)   V(max)
0s        1.062V     1.06V      1.095V
1.27ns    1.062V     1.06V      1.079V
1.43ns    1.062V     1.06V      1.319V
1.52ns    1.054V     1.06V      1.396V
1.6ns     1.107V     1.061V     1.435V
1.77ns    1.331V     1.058V     1.467V
1.9ns     1.401V     1.073V     1.481V
2.15ns    1.444V     1.312V     1.496V
2.41ns    1.457V     1.411V     1.503V
4ns       1.468V     1.444V     1.511V
[Falling waveform]
R_fixture= 50
V_fixture= 1.26396
V_fixture_min= 1.25128
V_fixture_max= 1.30289
|Time   V(typ)   V(min)   V(max)
0s        1.468V     1.444V     1.51V
1.23ns    1.468V     1.444V     1.52V
1.31ns    1.468V     1.444V     1.462V
1.47ns    1.474V     1.444V     1.244V
1.58ns    1.406V     1.444V     1.194V
1.75ns    1.199V     1.448V     1.151V
1.88ns    1.143V     1.412V     1.13V
2.13ns    1.097V     1.177V     1.111V
2.36ns    1.079V     1.104V     1.105V
4ns       1.061V     1.06V      1.096V
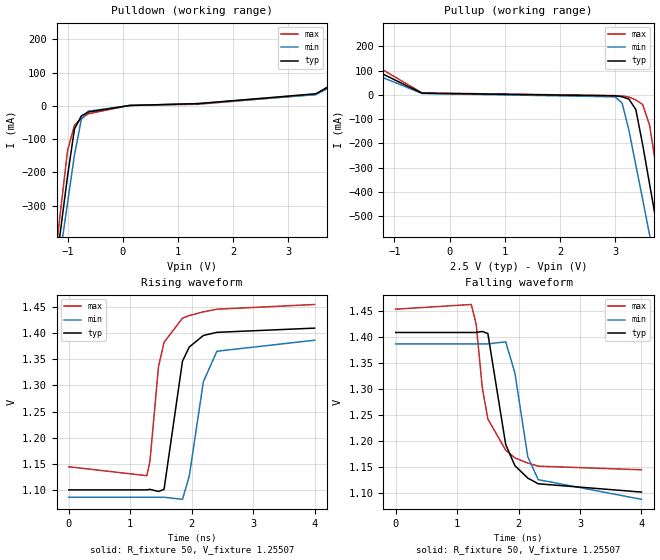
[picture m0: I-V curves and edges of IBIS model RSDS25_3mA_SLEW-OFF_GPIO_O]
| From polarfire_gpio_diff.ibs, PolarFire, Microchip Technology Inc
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|   Model RSDS25_3mA_SLEW-OFF_GPIO_O
[Model]   RSDS25_3mA_SLEW-OFF_GPIO_O
Model_type   Output
Polarity   Non-Inverting
Enable   Active-High
Vmeas =   1.2
Cref =   5p
Rref =   100
|   typ   min   max
C_comp_pullup   2.605e-12   2.605e-12   2.76e-12
C_comp_pulldown  2.605e-12   2.605e-12   2.76e-12
[Temperature Range]  25C   100C   -40C
[Voltage Range]  2.5   2.375   2.625
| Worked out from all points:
|   slope of the pulldown table from 0 to 0.375 V, typ, clamps not added: 136 ohm
|   slope of the pullup table from 0 to 0.375 V, typ, clamps not added: 158 ohm
|   rising waveform, R_fixture 50, V_fixture 1.25507: 20-80 % time 221ps typ, 255ps min, 227ps max; typ from 1.1 V to 1.41 V
|   falling waveform, R_fixture 50, V_fixture 1.25507: 20-80 % time 281ps typ, 264ps min, 298ps max; typ from 1.41 V to 1.1 V
[Pulldown]
|Voltage   I(typ)   I(min)   I(max)
-2.5V     -2.163A    -2.027A    -2.344A
-1.25V    -533.4mA   -578.8mA   -496mA
-1.125V   -371.6mA   -435.1mA   -312.8mA
-1V       -210.1mA   -291.2mA   -133.8mA
-875mV    -69.41mA   -147.6mA   -57.99mA
-750mV    -29.85mA   -40.31mA   -37.97mA
-625mV    -18.35mA   -15.59mA   -23.65mA
125mV     1.485mA    1.198mA    1.806mA
1.375V    7.22mA     7.089mA    5.249mA
3.5V      36.69mA    34mA       35.02mA
4.125V    93.92mA    87.54mA    99.73mA
5V        213mA      191mA      235.6mA
[Pullup]
|Voltage   I(typ)   I(min)   I(max)
-2.5V     228.9mA    189.1mA    274.8mA
-500mV    6.765mA    5.876mA    8.139mA
3V        -3.849mA   -8.119mA   -3.244mA
3.125V    -7.793mA   -33.26mA   -4.043mA
3.25V     -17.45mA   -145mA     -8.93mA
3.375V    -60.07mA   -288.4mA   -20.92mA
3.5V      -206mA     -432.1mA   -39.87mA
3.625V    -367.4mA   -575.7mA   -125.6mA
3.75V     -528.9mA   -719.2mA   -307mA
3.875V    -690.6mA   -862.9mA   -489.9mA
4V        -852.4mA   -1.007A    -672.9mA
5V        -2.157A    -2.168A    -2.149A
[Ramp]
| variable   typ   min   max
dV/dt_r 0.1901/0.2238e-9   0.1829/0.2572e-9   0.1958/0.2237e-9
dV/dt_f 0.1889/0.2803e-9   0.1825/0.2670e-9   0.1922/0.2935e-9
R_load = 50
[Rising waveform]
R_fixture= 50
V_fixture= 1.25507
V_fixture_min= 1.23614
V_fixture_max= 1.29855
|Time   V(typ)   V(min)   V(max)
0s        1.101V     1.087V     1.145V
1.27ns    1.101V     1.087V     1.128V
1.32ns    1.102V     1.087V     1.155V
1.46ns    1.098V     1.087V     1.336V
1.55ns    1.102V     1.087V     1.382V
1.85ns    1.346V     1.083V     1.428V
1.96ns    1.373V     1.127V     1.433V
2.19ns    1.395V     1.307V     1.44V
2.41ns    1.401V     1.365V     1.445V
4ns       1.409V     1.386V     1.454V
[Falling waveform]
R_fixture= 50
V_fixture= 1.25507
V_fixture_min= 1.23614
V_fixture_max= 1.29855
|Time   V(typ)   V(min)   V(max)
0s        1.409V     1.387V     1.454V
1.23ns    1.409V     1.387V     1.463V
1.31ns    1.409V     1.387V     1.425V
1.41ns    1.411V     1.387V     1.302V
1.5ns     1.407V     1.387V     1.242V
1.79ns    1.193V     1.391V     1.182V
1.94ns    1.152V     1.331V     1.167V
2.15ns    1.128V     1.169V     1.157V
2.32ns    1.117V     1.125V     1.151V
4ns       1.101V     1.087V     1.144V
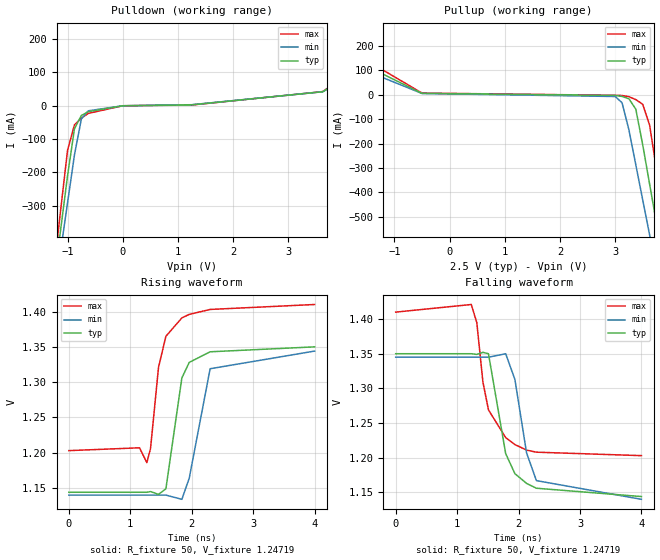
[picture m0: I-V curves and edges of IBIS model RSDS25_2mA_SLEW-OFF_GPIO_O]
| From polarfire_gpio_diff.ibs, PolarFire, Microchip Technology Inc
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|   Model RSDS25_2mA_SLEW-OFF_GPIO_O
[Model]   RSDS25_2mA_SLEW-OFF_GPIO_O
Model_type   Output
Polarity   Non-Inverting
Enable   Active-High
Vmeas =   1.2
Cref =   5p
Rref =   100
|   typ   min   max
C_comp_pullup   2.605e-12   2.605e-12   2.76e-12
C_comp_pulldown  2.605e-12   2.605e-12   2.76e-12
[Temperature Range]  25C   100C   -40C
[Voltage Range]  2.5   2.375   2.625
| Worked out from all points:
|   slope of the pulldown table from 0 to 0.375 V, typ, clamps not added: 205 ohm
|   slope of the pullup table from 0 to 0.375 V, typ, clamps not added: 218 ohm
|   rising waveform, R_fixture 50, V_fixture 1.24719: 20-80 % time 208ps typ, 244ps min, 227ps max; typ from 1.14 V to 1.35 V
|   falling waveform, R_fixture 50, V_fixture 1.24719: 20-80 % time 260ps typ, 253ps min, 298ps max; typ from 1.35 V to 1.14 V
[Pulldown]
|Voltage   I(typ)   I(min)   I(max)
-2.5V     -2.163A    -2.026A    -2.344A
-1.25V    -533.2mA   -578.7mA   -495.7mA
-1.125V   -371.4mA   -434.9mA   -312.6mA
-1V       -209.9mA   -291.1mA   -133.4mA
-875mV    -68.97mA   -147.4mA   -57.3mA
-750mV    -29.33mA   -39.96mA   -37.29mA
-625mV    -17.87mA   -15.22mA   -23.02mA
0V        -60.23uA   -53.52uA   -74.2uA
1.25V     2.709mA    3.086mA    2.084mA
3.625V    41.99mA    42.04mA    42.52mA
4.25V     108mA      99.53mA    115.6mA
5V        211.8mA    189.9mA    234.4mA
[Pullup]
|Voltage   I(typ)   I(min)   I(max)
-2.5V     228.6mA    188.9mA    273.7mA
-500mV    5.853mA    5.168mA    6.994mA
3V        -2.816mA   -7.109mA   -2.197mA
3.125V    -6.77mA    -32.3mA    -3.002mA
3.25V     -16.44mA   -144.1mA   -7.902mA
3.375V    -59.15mA   -287.6mA   -19.91mA
3.5V      -205.2mA   -431.2mA   -38.88mA
3.625V    -366.5mA   -574.8mA   -124.7mA
3.75V     -528mA     -718.4mA   -306.2mA
3.875V    -689.7mA   -862.1mA   -489mA
4V        -851.5mA   -1.006A    -672mA
5V        -2.156A    -2.167A    -2.148A
[Ramp]
| variable   typ   min   max
dV/dt_r 0.1293/0.2102e-9   0.1263/0.2482e-9   0.1350/0.2262e-9
dV/dt_f 0.1277/0.2585e-9   0.1261/0.2574e-9   0.1309/0.2881e-9
R_load = 50
[Rising waveform]
R_fixture= 50
V_fixture= 1.24719
V_fixture_min= 1.24240
V_fixture_max= 1.30595
|Time   V(typ)   V(min)   V(max)
0s        1.144V     1.14V      1.203V
1.15ns    1.144V     1.14V      1.207V
1.27ns    1.144V     1.14V      1.186V
1.33ns    1.145V     1.14V      1.206V
1.46ns    1.141V     1.14V      1.321V
1.58ns    1.149V     1.14V      1.365V
1.84ns    1.306V     1.134V     1.391V
1.96ns    1.328V     1.164V     1.396V
2.3ns     1.343V     1.319V     1.403V
4ns       1.35V      1.344V     1.41V
[Falling waveform]
R_fixture= 50
V_fixture= 1.24719
V_fixture_min= 1.24240
V_fixture_max= 1.30595
|Time   V(typ)   V(min)   V(max)
0s        1.35V      1.345V     1.41V
1.23ns    1.35V      1.345V     1.421V
1.32ns    1.349V     1.345V     1.395V
1.42ns    1.352V     1.345V     1.309V
1.51ns    1.35V      1.345V     1.269V
1.79ns    1.206V     1.35V      1.229V
1.94ns    1.177V     1.313V     1.219V
2.13ns    1.163V     1.207V     1.211V
2.29ns    1.156V     1.167V     1.208V
4ns       1.144V     1.14V      1.203V
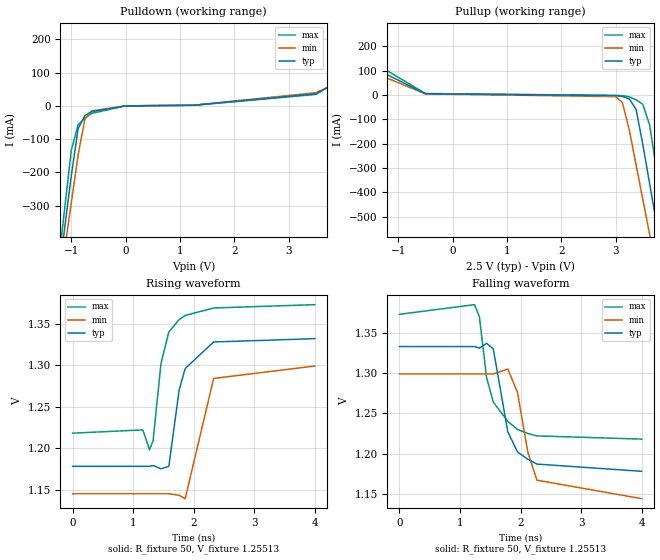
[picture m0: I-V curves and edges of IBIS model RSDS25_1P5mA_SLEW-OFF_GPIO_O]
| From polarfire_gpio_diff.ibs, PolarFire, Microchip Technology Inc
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|   Model RSDS25_1P5mA_SLEW-OFF_GPIO_O
[Model]   RSDS25_1P5mA_SLEW-OFF_GPIO_O
Model_type   Output
Polarity   Non-Inverting
Enable   Active-High
Vmeas =   1.2
Cref =   5p
Rref =   100
|   typ   min   max
C_comp_pullup   2.605e-12   2.605e-12   2.76e-12
C_comp_pulldown  2.605e-12   2.605e-12   2.76e-12
[Temperature Range]  25C   100C   -40C
[Voltage Range]  2.5   2.375   2.625
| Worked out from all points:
|   slope of the pulldown table from 0 to 0.375 V, typ, clamps not added: 278 ohm
|   slope of the pullup table from 0 to 0.375 V, typ, clamps not added: 279 ohm
|   rising waveform, R_fixture 50, V_fixture 1.25513: 20-80 % time 238ps typ, 234ps min, 222ps max; typ from 1.18 V to 1.33 V
|   falling waveform, R_fixture 50, V_fixture 1.25513: 20-80 % time 252ps typ, 247ps min, 308ps max; typ from 1.33 V to 1.18 V
[Pulldown]
|Voltage   I(typ)   I(min)   I(max)
-2.5V     -2.163A    -2.026A    -2.344A
-1.25V    -533mA     -578.6mA   -495.6mA
-1.125V   -371.3mA   -434.8mA   -312.5mA
-1V       -209.8mA   -291mA     -133.2mA
-875mV    -68.71mA   -147.3mA   -56.89mA
-750mV    -29.02mA   -39.75mA   -36.9mA
-625mV    -17.57mA   -15mA      -22.64mA
0V        -59.52uA   -51.88uA   -72.38uA
1.25V     1.721mA    2.083mA    1.547mA
3.5V      36.12mA    39.55mA    34.44mA
4.125V    92.35mA    86.07mA    98.16mA
5V        211.2mA    189.4mA    233.8mA
[Pullup]
|Voltage   I(typ)   I(min)   I(max)
-2.5V     228.5mA    188.9mA    273.4mA
-500mV    5.224mA    4.681mA    6.208mA
3V        -2.308mA   -6.605mA   -1.681mA
3.125V    -6.267mA   -31.82mA   -2.488mA
3.25V     -15.95mA   -143.7mA   -7.394mA
3.375V    -58.69mA   -287.1mA   -19.41mA
3.5V      -204.7mA   -430.8mA   -38.39mA
3.625V    -366.1mA   -574.3mA   -124.3mA
3.75V     -527.6mA   -717.9mA   -305.8mA
3.875V    -689.3mA   -861.6mA   -488.6mA
4V        -851.1mA   -1.005A    -671.6mA
5V        -2.156A    -2.167A    -2.147A
[Ramp]
| variable   typ   min   max
dV/dt_r 98.8284e-3/0.2384e-9   96.7079e-3/0.2408e-9   0.1049/0.2186e-9
dV/dt_f 97.7235e-3/0.2493e-9   96.3260e-3/0.2535e-9   0.1006/0.3004e-9
R_load = 50
[Rising waveform]
R_fixture= 50
V_fixture= 1.25513
V_fixture_min= 1.22206
V_fixture_max= 1.29493
|Time   V(typ)   V(min)   V(max)
0s        1.178V     1.145V     1.218V
1.16ns    1.178V     1.145V     1.222V
1.27ns    1.178V     1.145V     1.198V
1.33ns    1.179V     1.145V     1.209V
1.46ns    1.175V     1.145V     1.302V
1.59ns    1.178V     1.145V     1.34V
1.76ns    1.27V      1.143V     1.355V
1.86ns    1.296V     1.139V     1.36V
2.33ns    1.328V     1.284V     1.369V
4ns       1.332V     1.299V     1.373V
[Falling waveform]
R_fixture= 50
V_fixture= 1.25513
V_fixture_min= 1.22206
V_fixture_max= 1.29493
|Time   V(typ)   V(min)   V(max)
0s        1.333V     1.299V     1.373V
1.24ns    1.333V     1.299V     1.385V
1.32ns    1.331V     1.299V     1.37V
1.44ns    1.337V     1.299V     1.294V
1.55ns    1.33V      1.299V     1.264V
1.79ns    1.227V     1.305V     1.24V
1.95ns    1.202V     1.276V     1.23V
2.12ns    1.193V     1.202V     1.225V
2.27ns    1.187V     1.167V     1.222V
4ns       1.178V     1.144V     1.218V
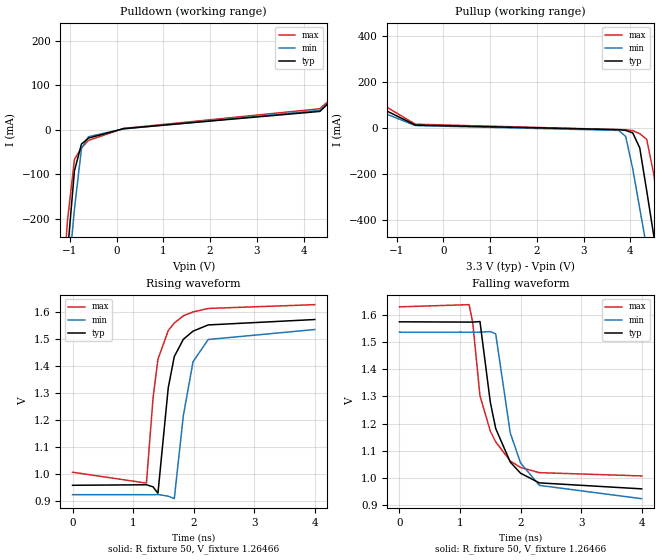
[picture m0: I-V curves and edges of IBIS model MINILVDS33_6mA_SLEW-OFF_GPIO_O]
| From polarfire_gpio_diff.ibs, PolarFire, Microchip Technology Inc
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|   Model MINILVDS33_6mA_SLEW-OFF_GPIO_O
[Model]   MINILVDS33_6mA_SLEW-OFF_GPIO_O
Model_type   Output
Polarity   Non-Inverting
Enable   Active-High
Vmeas =   1.2
Cref =   5p
Rref =   100
|   typ   min   max
C_comp_pullup   2.605e-12   2.605e-12   2.76e-12
C_comp_pulldown  2.605e-12   2.605e-12   2.76e-12
[Temperature Range]  25C   100C   -40C
[Voltage Range]  3.3   3.15   3.45
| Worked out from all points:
|   slope of the pulldown table from 0 to 0.495 V, typ, clamps not added: 87.8 ohm
|   slope of the pullup table from 0 to 0.495 V, typ, clamps not added: 102 ohm
|   rising waveform, R_fixture 50, V_fixture 1.26466: 20-80 % time 221ps typ, 233ps min, 231ps max; typ from 0.96 V to 1.57 V
|   falling waveform, R_fixture 50, V_fixture 1.26466: 20-80 % time 340ps typ, 336ps min, 356ps max; typ from 1.57 V to 0.961 V
[Pulldown]
|Voltage   I(typ)   I(min)   I(max)
-3.3V     -3.224A    -2.967A    -3.554A
-1.2V     -469.6mA   -522.2mA   -423.7mA
-1.05V    -275.6mA   -349.6mA   -204mA
-900mV    -91.51mA   -177.1mA   -66.21mA
-750mV    -31.88mA   -41.88mA   -40.33mA
-600mV    -18.49mA   -15.46mA   -23.65mA
150mV     2.591mA    2.112mA    3.219mA
4.35V     41.37mA    43.76mA    47.32mA
4.95V     101.9mA    98.26mA    104.3mA
5.7V      204.4mA    187.8mA    220.7mA
6V        250.7mA    229.9mA    272.3mA
6.6V      354.6mA    321.6mA    384.9mA
[Pullup]
|Voltage   I(typ)   I(min)   I(max)
-3.3V     376.5mA    318mA      438.5mA
-1.8V     133.6mA    108.6mA    162.5mA
-600mV    13.4mA     11.37mA    17.26mA
3.75V     -6.487mA   -9.79mA    -6.346mA
3.9V      -9.67mA    -36.15mA   -6.599mA
4.05V     -20.47mA   -176.3mA   -10.51mA
4.2V      -85.38mA   -348.5mA   -23.96mA
4.35V     -273.1mA   -520.9mA   -48.78mA
4.5V      -466.9mA   -693.2mA   -199.9mA
4.65V     -660.8mA   -865.6mA   -419.3mA
4.8V      -855mA     -1.038A    -638.8mA
6.6V      -3.219A    -3.139A    -3.32A
[Ramp]
| variable   typ   min   max
dV/dt_r 0.3863/0.2177e-9   0.3800/0.2344e-9   0.3978/0.2264e-9
dV/dt_f 0.3709/0.3390e-9   0.3692/0.3353e-9   0.3772/0.3544e-9
R_load = 50
[Rising waveform]
R_fixture= 50
V_fixture= 1.26466
V_fixture_min= 1.22785
V_fixture_max= 1.31682
|Time   V(typ)   V(min)   V(max)
0s        959.6mV    924.8mV    1.008V
1.22ns    961.5mV    924.8mV    967.6mV
1.33ns    953.7mV    924.7mV    1.284V
1.41ns    930.2mV    925.3mV    1.426V
1.58ns    1.32V      919.3mV    1.532V
1.68ns    1.436V     910mV      1.56V
1.83ns    1.5V       1.218V     1.587V
1.99ns    1.53V      1.417V     1.601V
2.24ns    1.553V     1.499V     1.614V
4ns       1.573V     1.536V     1.628V
[Falling waveform]
R_fixture= 50
V_fixture= 1.26466
V_fixture_min= 1.22785
V_fixture_max= 1.31682
|Time   V(typ)   V(min)   V(max)
0s        1.574V     1.536V     1.629V
1.15ns    1.573V     1.536V     1.637V
1.21ns    1.573V     1.536V     1.572V
1.33ns    1.575V     1.536V     1.302V
1.5ns     1.28V      1.538V     1.173V
1.59ns    1.182V     1.53V      1.133V
1.83ns    1.059V     1.166V     1.063V
2ns       1.018V     1.056V     1.039V
2.31ns    982.5mV    973.3mV    1.02V
4ns       960.5mV    924.4mV    1.008V
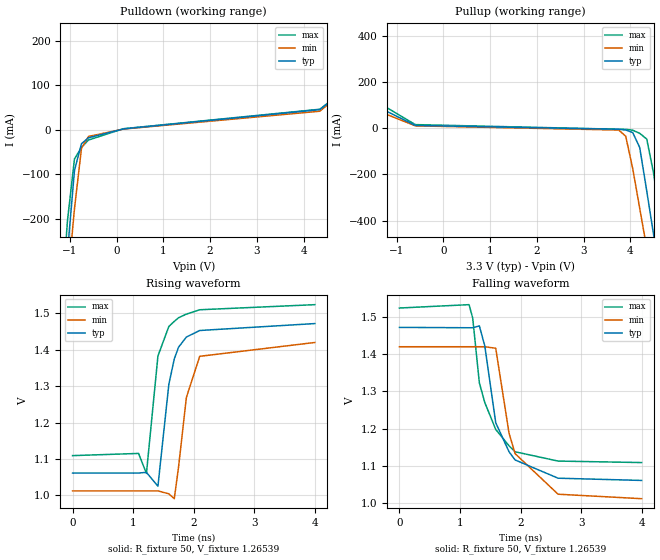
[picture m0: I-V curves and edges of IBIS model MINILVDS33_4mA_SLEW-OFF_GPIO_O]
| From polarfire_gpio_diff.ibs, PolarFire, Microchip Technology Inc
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|   Model MINILVDS33_4mA_SLEW-OFF_GPIO_O
[Model]   MINILVDS33_4mA_SLEW-OFF_GPIO_O
Model_type   Output
Polarity   Non-Inverting
Enable   Active-High
Vmeas =   1.2
Cref =   5p
Rref =   100
|   typ   min   max
C_comp_pullup   2.605e-12   2.605e-12   2.76e-12
C_comp_pulldown  2.605e-12   2.605e-12   2.76e-12
[Temperature Range]  25C   100C   -40C
[Voltage Range]  3.3   3.15   3.45
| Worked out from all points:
|   slope of the pulldown table from 0 to 0.495 V, typ, clamps not added: 131 ohm
|   slope of the pullup table from 0 to 0.495 V, typ, clamps not added: 138 ohm
|   rising waveform, R_fixture 50, V_fixture 1.26539: 20-80 % time 215ps typ, 212ps min, 224ps max; typ from 1.06 V to 1.47 V
|   falling waveform, R_fixture 50, V_fixture 1.26539: 20-80 % time 354ps typ, 348ps min, 370ps max; typ from 1.47 V to 1.06 V
[Pulldown]
|Voltage   I(typ)   I(min)   I(max)
-3.3V     -3.224A    -2.966A    -3.554A
-1.2V     -469.2mA   -521.9mA   -423.3mA
-1.05V    -275.2mA   -349.3mA   -203.6mA
-900mV    -90.9mA    -176.8mA   -65.17mA
-750mV    -31.06mA   -41.28mA   -39.33mA
-600mV    -17.74mA   -14.85mA   -22.73mA
150mV     2.11mA     1.754mA    2.552mA
4.35V     45.28mA    41.71mA    46.2mA
4.8V      82.36mA    80.86mA    83.01mA
5.7V      202.2mA    185.6mA    218.5mA
6V        248.4mA    227.6mA    270mA
6.6V      352.1mA    319.1mA    382.4mA
[Pullup]
|Voltage   I(typ)   I(min)   I(max)
-3.3V     375.9mA    317.7mA    437.2mA
-1.8V     131.5mA    107.2mA    159.9mA
-600mV    12.28mA    10.48mA    15.87mA
3.75V     -4.424mA   -7.759mA   -4.26mA
3.9V      -7.63mA    -34.23mA   -4.517mA
4.05V     -18.46mA   -174.5mA   -8.457mA
4.2V      -83.59mA   -346.8mA   -21.94mA
4.35V     -271.4mA   -519.1mA   -46.79mA
4.5V      -465.1mA   -691.4mA   -198.2mA
4.65V     -659.1mA   -863.8mA   -417.6mA
4.8V      -853.2mA   -1.036A    -637.1mA
6.6V      -3.217A    -3.137A    -3.318A
[Ramp]
| variable   typ   min   max
dV/dt_r 0.2678/0.2157e-9   0.2606/0.2144e-9   0.2785/0.2118e-9
dV/dt_f 0.2493/0.3518e-9   0.2477/0.3464e-9   0.2543/0.3677e-9
R_load = 50
[Rising waveform]
R_fixture= 50
V_fixture= 1.26539
V_fixture_min= 1.21493
V_fixture_max= 1.31643
|Time   V(typ)   V(min)   V(max)
0s        1.061V     1.012V     1.109V
1.09ns    1.061V     1.012V     1.115V
1.22ns    1.063V     1.012V     1.06V
1.41ns    1.025V     1.012V     1.383V
1.59ns    1.305V     1.004V     1.464V
1.68ns    1.375V     990.6mV    1.478V
1.75ns    1.407V     1.077V     1.488V
1.88ns    1.435V     1.269V     1.498V
2.1ns     1.453V     1.382V     1.51V
4ns       1.472V     1.42V      1.524V
[Falling waveform]
R_fixture= 50
V_fixture= 1.26539
V_fixture_min= 1.21493
V_fixture_max= 1.31643
|Time   V(typ)   V(min)   V(max)
0s        1.472V     1.42V      1.524V
1.15ns    1.471V     1.42V      1.533V
1.21ns    1.471V     1.42V      1.497V
1.32ns    1.476V     1.42V      1.323V
1.41ns    1.422V     1.42V      1.27V
1.59ns    1.216V     1.416V     1.198V
1.81ns    1.138V     1.188V     1.154V
1.91ns    1.116V     1.133V     1.138V
2.62ns    1.067V     1.024V     1.113V
4ns       1.061V     1.012V     1.109V
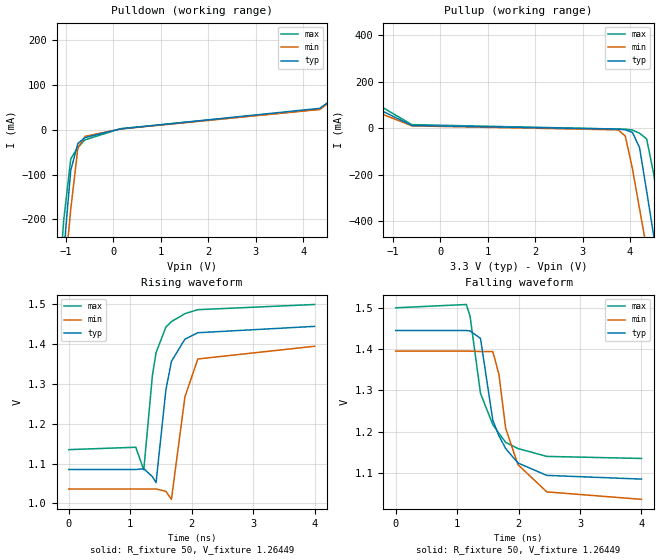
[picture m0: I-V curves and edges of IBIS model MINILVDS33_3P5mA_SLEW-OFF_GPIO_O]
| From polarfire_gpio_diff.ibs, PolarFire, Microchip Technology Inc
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|   Model MINILVDS33_3P5mA_SLEW-OFF_GPIO_O
[Model]   MINILVDS33_3P5mA_SLEW-OFF_GPIO_O
Model_type   Output
Polarity   Non-Inverting
Enable   Active-High
Vmeas =   1.2
Cref =   5p
Rref =   100
|   typ   min   max
C_comp_pullup   2.605e-12   2.605e-12   2.76e-12
C_comp_pulldown  2.605e-12   2.605e-12   2.76e-12
[Temperature Range]  25C   100C   -40C
[Voltage Range]  3.3   3.15   3.45
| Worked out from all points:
|   slope of the pulldown table from 0 to 0.495 V, typ, clamps not added: 149 ohm
|   slope of the pullup table from 0 to 0.495 V, typ, clamps not added: 154 ohm
|   rising waveform, R_fixture 50, V_fixture 1.26449: 20-80 % time 211ps typ, 210ps min, 227ps max; typ from 1.08 V to 1.45 V
|   falling waveform, R_fixture 50, V_fixture 1.26449: 20-80 % time 364ps typ, 352ps min, 380ps max; typ from 1.45 V to 1.08 V
[Pulldown]
|Voltage   I(typ)   I(min)   I(max)
-3.3V     -3.224A    -2.966A    -3.554A
-1.2V     -469.1mA   -521.8mA   -423.2mA
-1.05V    -275.2mA   -349.2mA   -203.5mA
-900mV    -90.73mA   -176.7mA   -64.89mA
-750mV    -30.83mA   -41.12mA   -39.06mA
-600mV    -17.53mA   -14.68mA   -22.48mA
150mV     1.956mA    1.638mA    2.351mA
4.35V     47.77mA    45.2mA     45.71mA
4.8V      81.85mA    80.36mA    82.52mA
5.7V      201.7mA    185.1mA    218mA
6V        247.8mA    227mA      269.5mA
6.6V      351.5mA    318.5mA    381.8mA
[Pullup]
|Voltage   I(typ)   I(min)   I(max)
-3.3V     375.7mA    317.6mA    437mA
-1.8V     130.9mA    106.9mA    159.2mA
-600mV    11.9mA     10.17mA    15.4mA
3.75V     -3.915mA   -7.257mA   -3.747mA
3.9V      -7.126mA   -33.75mA   -4.005mA
4.05V     -17.97mA   -174.1mA   -7.952mA
4.2V      -83.15mA   -346.3mA   -21.45mA
4.35V     -271mA     -518.7mA   -46.31mA
4.5V      -464.7mA   -691mA     -197.8mA
4.65V     -658.7mA   -863.4mA   -417.2mA
4.8V      -852.8mA   -1.036A    -636.7mA
6.6V      -3.216A    -3.137A    -3.318A
[Ramp]
| variable   typ   min   max
dV/dt_r 0.2385/0.2084e-9   0.2316/0.2129e-9   0.2496/0.2194e-9
dV/dt_f 0.2190/0.3612e-9   0.2177/0.3510e-9   0.2246/0.3767e-9
R_load = 50
[Rising waveform]
R_fixture= 50
V_fixture= 1.26449
V_fixture_min= 1.21440
V_fixture_max= 1.31725
|Time   V(typ)   V(min)   V(max)
0s        1.085V     1.036V     1.135V
1.09ns    1.085V     1.036V     1.141V
1.22ns    1.087V     1.036V     1.084V
1.36ns    1.067V     1.036V     1.321V
1.42ns    1.052V     1.036V     1.379V
1.58ns    1.285V     1.03V      1.443V
1.67ns    1.357V     1.01V      1.457V
1.89ns    1.413V     1.268V     1.477V
2.1ns     1.429V     1.363V     1.487V
4ns       1.445V     1.395V     1.5V
[Falling waveform]
R_fixture= 50
V_fixture= 1.26449
V_fixture_min= 1.21440
V_fixture_max= 1.31725
|Time   V(typ)   V(min)   V(max)
0s        1.445V     1.395V     1.5V
1.15ns    1.445V     1.395V     1.508V
1.21ns    1.444V     1.395V     1.48V
1.38ns    1.426V     1.394V     1.293V
1.58ns    1.228V     1.394V     1.217V
1.68ns    1.19V      1.339V     1.196V
1.79ns    1.159V     1.208V     1.174V
1.99ns    1.124V     1.12V      1.159V
2.46ns    1.094V     1.054V     1.14V
4ns       1.085V     1.036V     1.135V
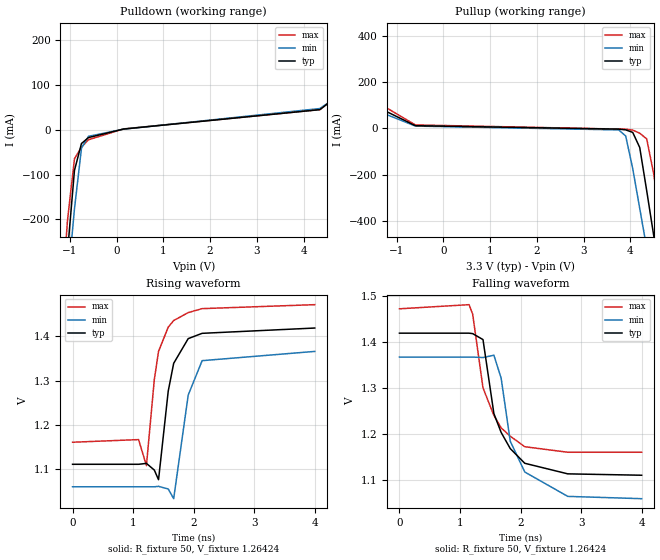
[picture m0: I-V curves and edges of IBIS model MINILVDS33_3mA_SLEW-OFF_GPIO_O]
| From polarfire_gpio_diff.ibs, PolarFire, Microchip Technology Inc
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|   Model MINILVDS33_3mA_SLEW-OFF_GPIO_O
[Model]   MINILVDS33_3mA_SLEW-OFF_GPIO_O
Model_type   Output
Polarity   Non-Inverting
Enable   Active-High
Vmeas =   1.2
Cref =   5p
Rref =   100
|   typ   min   max
C_comp_pullup   2.605e-12   2.605e-12   2.76e-12
C_comp_pulldown  2.605e-12   2.605e-12   2.76e-12
[Temperature Range]  25C   100C   -40C
[Voltage Range]  3.3   3.15   3.45
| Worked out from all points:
|   slope of the pulldown table from 0 to 0.495 V, typ, clamps not added: 175 ohm
|   slope of the pullup table from 0 to 0.495 V, typ, clamps not added: 176 ohm
|   rising waveform, R_fixture 50, V_fixture 1.26424: 20-80 % time 211ps typ, 211ps min, 225ps max; typ from 1.11 V to 1.42 V
|   falling waveform, R_fixture 50, V_fixture 1.26424: 20-80 % time 374ps typ, 357ps min, 393ps max; typ from 1.42 V to 1.11 V
[Pulldown]
|Voltage   I(typ)   I(min)   I(max)
-3.3V     -3.224A    -2.966A    -3.554A
-1.2V     -469mA     -521.7mA   -423.1mA
-1.05V    -275mA     -349.1mA   -203.4mA
-900mV    -90.55mA   -176.6mA   -64.55mA
-750mV    -30.58mA   -40.93mA   -38.72mA
-600mV    -17.3mA    -14.49mA   -22.17mA
150mV     1.777mA    1.5mA      2.093mA
4.35V     45.25mA    47.68mA    45.15mA
4.8V      81.33mA    79.83mA    81.96mA
5.7V      201.1mA    184.5mA    217.4mA
6V        247.2mA    226.5mA    268.8mA
6.6V      350.8mA    317.8mA    381.1mA
[Pullup]
|Voltage   I(typ)   I(min)   I(max)
-3.3V     375.6mA    317.5mA    436.8mA
-1.8V     130.3mA    106.7mA    158.5mA
-600mV    11.44mA    9.794mA    14.82mA
3.75V     -3.395mA   -6.745mA   -3.22mA
3.9V      -6.611mA   -33.27mA   -3.479mA
4.05V     -17.46mA   -173.7mA   -7.432mA
4.2V      -82.7mA    -345.9mA   -20.94mA
4.35V     -270.5mA   -518.2mA   -45.81mA
4.5V      -464.3mA   -690.5mA   -197.4mA
4.65V     -658.2mA   -862.9mA   -416.8mA
4.8V      -852.4mA   -1.036A    -636.3mA
6.6V      -3.216A    -3.136A    -3.317A
[Ramp]
| variable   typ   min   max
dV/dt_r 0.2082/0.2126e-9   0.2008/0.2184e-9   0.2193/0.2108e-9
dV/dt_f 0.1885/0.3706e-9   0.1872/0.3570e-9   0.1929/0.3909e-9
R_load = 50
[Rising waveform]
R_fixture= 50
V_fixture= 1.26424
V_fixture_min= 1.21235
V_fixture_max= 1.31585
|Time   V(typ)   V(min)   V(max)
0s        1.11V      1.059V     1.16V
1.09ns    1.11V      1.059V     1.166V
1.22ns    1.112V     1.059V     1.107V
1.35ns    1.097V     1.059V     1.302V
1.42ns    1.075V     1.06V      1.366V
1.58ns    1.276V     1.054V     1.421V
1.67ns    1.339V     1.032V     1.436V
1.91ns    1.395V     1.267V     1.454V
2.14ns    1.407V     1.345V     1.463V
4ns       1.419V     1.366V     1.472V
[Falling waveform]
R_fixture= 50
V_fixture= 1.26424
V_fixture_min= 1.21235
V_fixture_max= 1.31585
|Time   V(typ)   V(min)   V(max)
0s        1.419V     1.367V     1.472V
1.15ns    1.419V     1.367V     1.481V
1.21ns    1.418V     1.367V     1.46V
1.38ns    1.405V     1.366V     1.3V
1.56ns    1.244V     1.371V     1.24V
1.68ns    1.203V     1.321V     1.213V
1.83ns    1.168V     1.184V     1.195V
2.07ns    1.136V     1.117V     1.172V
2.78ns    1.113V     1.064V     1.16V
4ns       1.11V      1.059V     1.16V
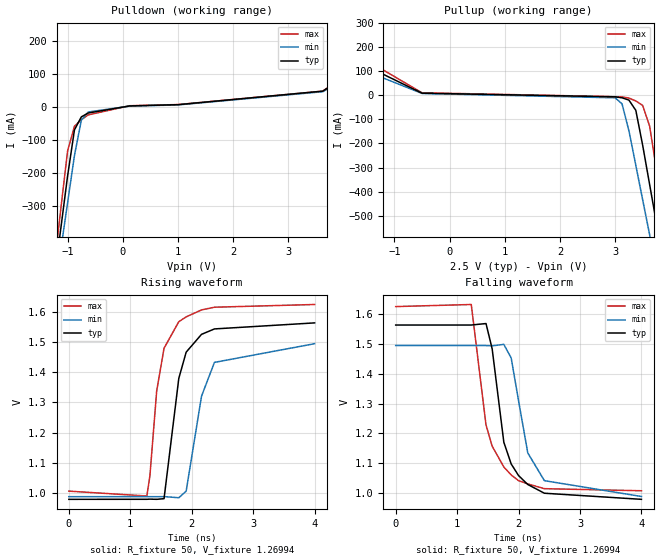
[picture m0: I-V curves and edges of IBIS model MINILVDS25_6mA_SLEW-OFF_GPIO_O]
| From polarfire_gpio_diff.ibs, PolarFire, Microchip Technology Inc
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|   Model MINILVDS25_6mA_SLEW-OFF_GPIO_O
[Model]   MINILVDS25_6mA_SLEW-OFF_GPIO_O
Model_type   Output
Polarity   Non-Inverting
Enable   Active-High
Vmeas =   1.2
Cref =   5p
Rref =   100
|   typ   min   max
C_comp_pullup   2.605e-12   2.605e-12   2.76e-12
C_comp_pulldown  2.605e-12   2.605e-12   2.76e-12
[Temperature Range]  25C   100C   -40C
[Voltage Range]  2.5   2.375   2.625
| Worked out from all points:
|   slope of the pulldown table from 0 to 0.375 V, typ, clamps not added: 77.2 ohm
|   slope of the pullup table from 0 to 0.375 V, typ, clamps not added: 103 ohm
|   rising waveform, R_fixture 50, V_fixture 1.26994: 20-80 % time 246ps typ, 294ps min, 234ps max; typ from 0.979 V to 1.56 V
|   falling waveform, R_fixture 50, V_fixture 1.26994: 20-80 % time 290ps typ, 297ps min, 300ps max; typ from 1.56 V to 0.978 V
[Pulldown]
|Voltage   I(typ)   I(min)   I(max)
-2.5V     -2.164A    -2.027A    -2.345A
-1.25V    -533.8mA   -579.2mA   -496.5mA
-1.125V   -372.1mA   -435.4mA   -313.4mA
-1V       -210.6mA   -291.6mA   -134.8mA
-875mV    -70.37mA   -147.9mA   -59.58mA
-750mV    -30.96mA   -40.93mA   -39.49mA
-625mV    -19.38mA   -16.24mA   -25.09mA
125mV     2.033mA    1.534mA    2.656mA
1V        5.835mA    5.045mA    6.195mA
3.625V    46.81mA    45.09mA    46.75mA
4.25V     111.9mA    102.7mA    119.9mA
5V        216mA      193.3mA    239.1mA
[Pullup]
|Voltage   I(typ)   I(min)   I(max)
-2.5V     231mA      189.7mA    278.3mA
-500mV    8.222mA    6.995mA    9.978mA
3V        -6.915mA   -10.94mA   -6.366mA
3.125V    -10.83mA   -35.95mA   -7.151mA
3.25V     -20.45mA   -147.4mA   -12mA
3.375V    -62.83mA   -290.9mA   -23.95mA
3.5V      -208.6mA   -434.5mA   -42.87mA
3.625V    -370mA     -578.1mA   -128.2mA
3.75V     -531.5mA   -721.7mA   -309.6mA
3.875V    -693.2mA   -865.4mA   -492.5mA
4V        -855mA     -1.009A    -675.4mA
5V        -2.159A    -2.17A     -2.151A
[Ramp]
| variable   typ   min   max
dV/dt_r 0.3562/0.2473e-9   0.3075/0.2941e-9   0.3819/0.2320e-9
dV/dt_f 0.3552/0.2901e-9   0.3071/0.2972e-9   0.3765/0.2987e-9
R_load = 50
[Rising waveform]
R_fixture= 50
V_fixture= 1.26994
V_fixture_min= 1.23959
V_fixture_max= 1.31635
|Time   V(typ)   V(min)   V(max)
0s        978.8mV    987.7mV    1.006V
1.27ns    978.9mV    987.7mV    989.8mV
1.32ns    979.5mV    987.7mV    1.057V
1.43ns    978.8mV    987.7mV    1.338V
1.55ns    981mV      987.8mV    1.48V
1.79ns    1.38V      984.1mV    1.568V
1.91ns    1.467V     1.006V     1.584V
2.16ns    1.526V     1.321V     1.607V
2.37ns    1.544V     1.433V     1.616V
4ns       1.564V     1.495V     1.625V
[Falling waveform]
R_fixture= 50
V_fixture= 1.26994
V_fixture_min= 1.23959
V_fixture_max= 1.31635
|Time   V(typ)   V(min)   V(max)
0s        1.564V     1.495V     1.626V
1.23ns    1.564V     1.495V     1.633V
1.47ns    1.569V     1.495V     1.228V
1.57ns    1.484V     1.494V     1.157V
1.76ns    1.17V      1.499V     1.087V
1.88ns    1.097V     1.453V     1.06V
2ns       1.058V     1.309V     1.041V
2.15ns    1.028V     1.134V     1.03V
2.42ns    998.7mV    1.041V     1.014V
4ns       978.2mV    987.7mV    1.007V
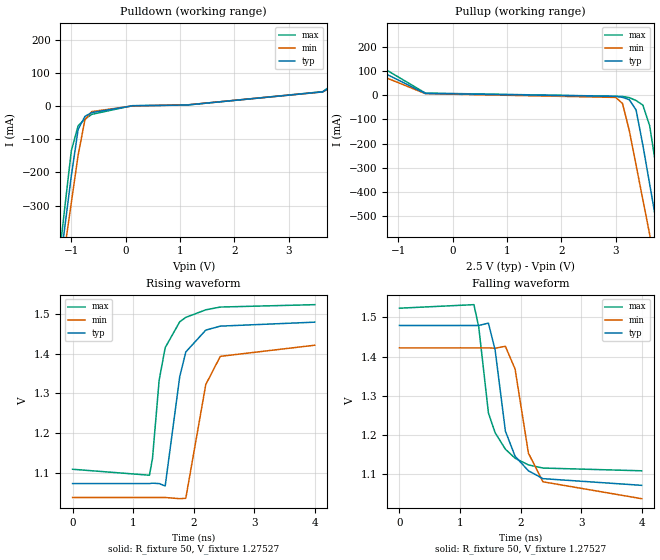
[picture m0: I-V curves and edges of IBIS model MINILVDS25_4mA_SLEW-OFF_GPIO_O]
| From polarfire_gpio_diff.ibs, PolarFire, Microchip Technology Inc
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|   Model MINILVDS25_4mA_SLEW-OFF_GPIO_O
[Model]   MINILVDS25_4mA_SLEW-OFF_GPIO_O
Model_type   Output
Polarity   Non-Inverting
Enable   Active-High
Vmeas =   1.2
Cref =   5p
Rref =   100
|   typ   min   max
C_comp_pullup   2.605e-12   2.605e-12   2.76e-12
C_comp_pulldown  2.605e-12   2.605e-12   2.76e-12
[Temperature Range]  25C   100C   -40C
[Voltage Range]  2.5   2.375   2.625
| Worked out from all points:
|   slope of the pulldown table from 0 to 0.375 V, typ, clamps not added: 104 ohm
|   slope of the pullup table from 0 to 0.375 V, typ, clamps not added: 129 ohm
|   rising waveform, R_fixture 50, V_fixture 1.27527: 20-80 % time 229ps typ, 266ps min, 224ps max; typ from 1.07 V to 1.48 V
|   falling waveform, R_fixture 50, V_fixture 1.27527: 20-80 % time 284ps typ, 278ps min, 298ps max; typ from 1.48 V to 1.07 V
[Pulldown]
|Voltage   I(typ)   I(min)   I(max)
-2.5V     -2.163A    -2.027A    -2.344A
-1.25V    -533.5mA   -579mA     -496.2mA
-1.125V   -371.8mA   -435.2mA   -313.1mA
-1V       -210.3mA   -291.4mA   -134.2mA
-875mV    -69.78mA   -147.7mA   -58.59mA
-750mV    -30.28mA   -40.57mA   -38.54mA
-625mV    -18.75mA   -15.87mA   -24.2mA
125mV     1.717mA    1.355mA    2.156mA
1.125V    4.077mA    4.441mA    4.143mA
3.625V    43.98mA    43.83mA    44.62mA
4.25V     110.1mA    101.4mA    117.7mA
5V        214mA      191.9mA    236.8mA
[Pullup]
|Voltage   I(typ)   I(min)   I(max)
-2.5V     229.4mA    189.2mA    276mA
-500mV    7.397mA    6.365mA    8.936mA
3V        -4.875mA   -9.104mA   -4.284mA
3.125V    -8.81mA    -34.2mA    -5.078mA
3.25V     -18.46mA   -145.9mA   -9.953mA
3.375V    -61mA      -289.3mA   -21.94mA
3.5V      -206.9mA   -432.9mA   -40.87mA
3.625V    -368.2mA   -576.5mA   -126.5mA
3.75V     -529.7mA   -720.1mA   -307.9mA
3.875V    -691.4mA   -863.8mA   -490.8mA
4V        -853.2mA   -1.008A    -673.7mA
5V        -2.158A    -2.169A    -2.15A
[Ramp]
| variable   typ   min   max
dV/dt_r 0.2483/0.2312e-9   0.2337/0.2674e-9   0.2581/0.2222e-9
dV/dt_f 0.2480/0.2833e-9   0.2333/0.2802e-9   0.2544/0.2952e-9
R_load = 50
[Rising waveform]
R_fixture= 50
V_fixture= 1.27527
V_fixture_min= 1.22745
V_fixture_max= 1.31572
|Time   V(typ)   V(min)   V(max)
0s        1.073V     1.038V     1.109V
1.27ns    1.073V     1.038V     1.094V
1.32ns    1.074V     1.038V     1.136V
1.43ns    1.073V     1.038V     1.333V
1.53ns    1.067V     1.038V     1.415V
1.77ns    1.342V     1.035V     1.48V
1.87ns    1.404V     1.036V     1.491V
2.2ns     1.459V     1.322V     1.51V
2.44ns    1.469V     1.393V     1.517V
4ns       1.479V     1.421V     1.523V
[Falling waveform]
R_fixture= 50
V_fixture= 1.27527
V_fixture_min= 1.22745
V_fixture_max= 1.31572
|Time   V(typ)   V(min)   V(max)
0s        1.479V     1.422V     1.523V
1.23ns    1.479V     1.422V     1.532V
1.31ns    1.479V     1.422V     1.475V
1.47ns    1.485V     1.422V     1.256V
1.58ns    1.417V     1.421V     1.206V
1.75ns    1.21V      1.426V     1.164V
1.91ns    1.146V     1.368V     1.141V
2.13ns    1.109V     1.154V     1.124V
2.37ns    1.089V     1.081V     1.116V
4ns       1.072V     1.038V     1.109V
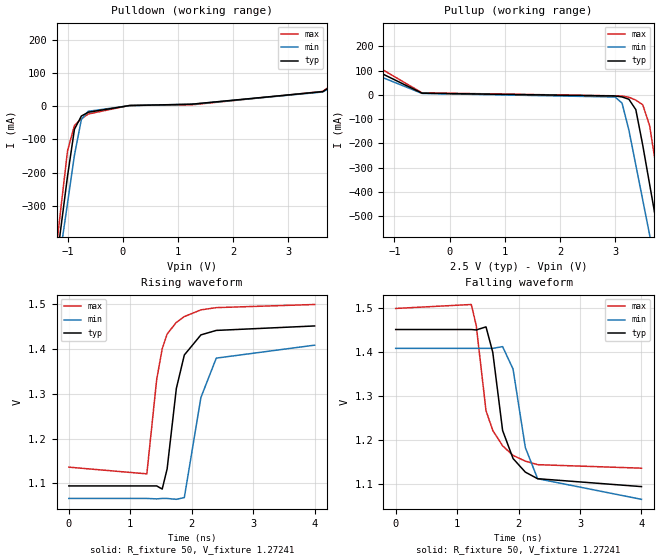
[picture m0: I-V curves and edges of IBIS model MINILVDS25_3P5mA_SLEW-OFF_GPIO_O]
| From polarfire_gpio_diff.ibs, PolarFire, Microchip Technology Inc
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|   Model MINILVDS25_3P5mA_SLEW-OFF_GPIO_O
[Model]   MINILVDS25_3P5mA_SLEW-OFF_GPIO_O
Model_type   Output
Polarity   Non-Inverting
Enable   Active-High
Vmeas =   1.2
Cref =   5p
Rref =   100
|   typ   min   max
C_comp_pullup   2.605e-12   2.605e-12   2.76e-12
C_comp_pulldown  2.605e-12   2.605e-12   2.76e-12
[Temperature Range]  25C   100C   -40C
[Voltage Range]  2.5   2.375   2.625
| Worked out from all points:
|   slope of the pulldown table from 0 to 0.375 V, typ, clamps not added: 117 ohm
|   slope of the pullup table from 0 to 0.375 V, typ, clamps not added: 141 ohm
|   rising waveform, R_fixture 50, V_fixture 1.27241: 20-80 % time 229ps typ, 259ps min, 224ps max; typ from 1.09 V to 1.45 V
|   falling waveform, R_fixture 50, V_fixture 1.27241: 20-80 % time 268ps typ, 270ps min, 292ps max; typ from 1.45 V to 1.09 V
[Pulldown]
|Voltage   I(typ)   I(min)   I(max)
-2.5V     -2.163A    -2.027A    -2.344A
-1.25V    -533.5mA   -578.9mA   -496.1mA
-1.125V   -371.7mA   -435.1mA   -313mA
-1V       -210.2mA   -291.3mA   -134mA
-875mV    -69.6mA    -147.7mA   -58.32mA
-750mV    -30.07mA   -40.45mA   -38.28mA
-625mV    -18.56mA   -15.74mA   -23.95mA
125mV     1.608mA    1.285mA    2.002mA
1.25V     5.661mA    5.496mA    3.741mA
3.625V    43.5mA     42.44mA    44.12mA
4.25V     109.6mA    101mA      117.2mA
5V        213.5mA    191.5mA    236.2mA
[Pullup]
|Voltage   I(typ)   I(min)   I(max)
-2.5V     229.1mA    189.1mA    275.4mA
-500mV    7.111mA    6.144mA    8.577mA
3V        -4.369mA   -8.62mA    -3.771mA
3.125V    -8.308mA   -33.74mA   -4.568mA
3.25V     -17.96mA   -145.4mA   -9.45mA
3.375V    -60.54mA   -288.9mA   -21.44mA
3.5V      -206.5mA   -432.5mA   -40.38mA
3.625V    -367.8mA   -576.1mA   -126mA
3.75V     -529.3mA   -719.7mA   -307.5mA
3.875V    -691mA     -863.4mA   -490.3mA
4V        -852.8mA   -1.007A    -673.3mA
5V        -2.157A    -2.168A    -2.149A
[Ramp]
| variable   typ   min   max
dV/dt_r 0.2200/0.2303e-9   0.2094/0.2605e-9   0.2280/0.2191e-9
dV/dt_f 0.2187/0.2674e-9   0.2092/0.2705e-9   0.2244/0.2893e-9
R_load = 50
[Rising waveform]
R_fixture= 50
V_fixture= 1.27241
V_fixture_min= 1.23619
V_fixture_max= 1.31823
|Time   V(typ)   V(min)   V(max)
0s        1.094V     1.066V     1.136V
1.27ns    1.094V     1.066V     1.121V
1.43ns    1.094V     1.065V     1.332V
1.52ns    1.087V     1.066V     1.401V
1.6ns     1.132V     1.066V     1.434V
1.75ns    1.312V     1.064V     1.46V
1.88ns    1.387V     1.068V     1.473V
2.15ns    1.432V     1.292V     1.488V
2.4ns     1.442V     1.38V      1.493V
4ns       1.452V     1.409V     1.5V
[Falling waveform]
R_fixture= 50
V_fixture= 1.27241
V_fixture_min= 1.23619
V_fixture_max= 1.31823
|Time   V(typ)   V(min)   V(max)
0s        1.452V     1.409V     1.5V
1.23ns    1.452V     1.409V     1.509V
1.31ns    1.451V     1.409V     1.462V
1.47ns    1.458V     1.409V     1.267V
1.58ns    1.4V       1.409V     1.222V
1.74ns    1.222V     1.413V     1.187V
1.91ns    1.158V     1.362V     1.165V
2.11ns    1.127V     1.183V     1.152V
2.31ns    1.112V     1.112V     1.144V
4ns       1.094V     1.065V     1.136V
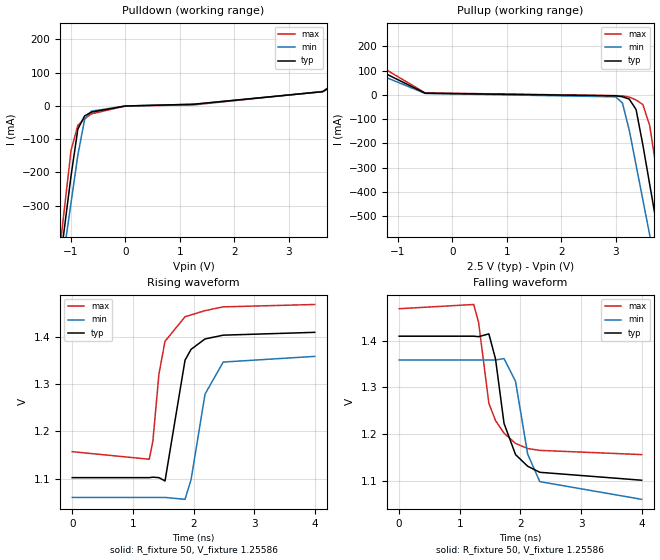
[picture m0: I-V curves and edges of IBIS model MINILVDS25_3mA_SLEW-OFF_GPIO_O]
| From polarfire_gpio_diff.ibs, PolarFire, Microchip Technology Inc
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|   Model MINILVDS25_3mA_SLEW-OFF_GPIO_O
[Model]   MINILVDS25_3mA_SLEW-OFF_GPIO_O
Model_type   Output
Polarity   Non-Inverting
Enable   Active-High
Vmeas =   1.2
Cref =   5p
Rref =   100
|   typ   min   max
C_comp_pullup   2.605e-12   2.605e-12   2.76e-12
C_comp_pulldown  2.605e-12   2.605e-12   2.76e-12
[Temperature Range]  25C   100C   -40C
[Voltage Range]  2.5   2.375   2.625
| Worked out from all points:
|   slope of the pulldown table from 0 to 0.375 V, typ, clamps not added: 135 ohm
|   slope of the pullup table from 0 to 0.375 V, typ, clamps not added: 158 ohm
|   rising waveform, R_fixture 50, V_fixture 1.25586: 20-80 % time 221ps typ, 254ps min, 229ps max; typ from 1.1 V to 1.41 V
|   falling waveform, R_fixture 50, V_fixture 1.25586: 20-80 % time 281ps typ, 266ps min, 296ps max; typ from 1.41 V to 1.1 V
[Pulldown]
|Voltage   I(typ)   I(min)   I(max)
-2.5V     -2.163A    -2.027A    -2.344A
-1.25V    -533.4mA   -578.8mA   -496mA
-1.125V   -371.6mA   -435.1mA   -312.9mA
-1V       -210.1mA   -291.2mA   -133.8mA
-875mV    -69.41mA   -147.6mA   -58.01mA
-750mV    -29.85mA   -40.3mA    -37.98mA
-625mV    -18.36mA   -15.58mA   -23.67mA
0V        -62.73uA   -54.03uA   -77.13uA
1.25V     5.161mA    5.045mA    3.19mA
3.625V    43.02mA    43mA       43.59mA
4.25V     109.1mA    100.5mA    116.7mA
5V        213mA      191mA      235.6mA
[Pullup]
|Voltage   I(typ)   I(min)   I(max)
-2.5V     228.9mA    189.1mA    274.8mA
-500mV    6.765mA    5.877mA    8.138mA
3V        -3.849mA   -8.116mA   -3.244mA
3.125V    -7.793mA   -33.26mA   -4.044mA
3.25V     -17.45mA   -145mA     -8.932mA
3.375V    -60.07mA   -288.4mA   -20.93mA
3.5V      -206mA     -432.1mA   -39.88mA
3.625V    -367.4mA   -575.6mA   -125.6mA
3.75V     -528.9mA   -719.2mA   -307mA
3.875V    -690.6mA   -862.9mA   -489.9mA
4V        -852.4mA   -1.007A    -672.9mA
5V        -2.157A    -2.168A    -2.149A
[Ramp]
| variable   typ   min   max
dV/dt_r 0.1902/0.2239e-9   0.1828/0.2567e-9   0.1970/0.2255e-9
dV/dt_f 0.1890/0.2802e-9   0.1824/0.2696e-9   0.1939/0.2908e-9
R_load = 50
[Rising waveform]
R_fixture= 50
V_fixture= 1.25586
V_fixture_min= 1.20819
V_fixture_max= 1.31287
|Time   V(typ)   V(min)   V(max)
0s        1.102V     1.06V      1.157V
1.27ns    1.102V     1.06V      1.141V
1.33ns    1.103V     1.06V      1.18V
1.43ns    1.102V     1.06V      1.322V
1.53ns    1.095V     1.06V      1.391V
1.86ns    1.351V     1.056V     1.443V
1.96ns    1.374V     1.098V     1.447V
2.19ns    1.396V     1.279V     1.456V
2.49ns    1.404V     1.347V     1.464V
4ns       1.41V      1.359V     1.469V
[Falling waveform]
R_fixture= 50
V_fixture= 1.25586
V_fixture_min= 1.20819
V_fixture_max= 1.31287
|Time   V(typ)   V(min)   V(max)
0s        1.41V      1.359V     1.469V
1.23ns    1.41V      1.359V     1.478V
1.31ns    1.409V     1.359V     1.44V
1.48ns    1.415V     1.359V     1.266V
1.59ns    1.361V     1.359V     1.229V
1.73ns    1.223V     1.362V     1.202V
1.92ns    1.156V     1.313V     1.18V
2.12ns    1.131V     1.157V     1.169V
2.32ns    1.118V     1.098V     1.165V
4ns       1.101V     1.06V      1.156V
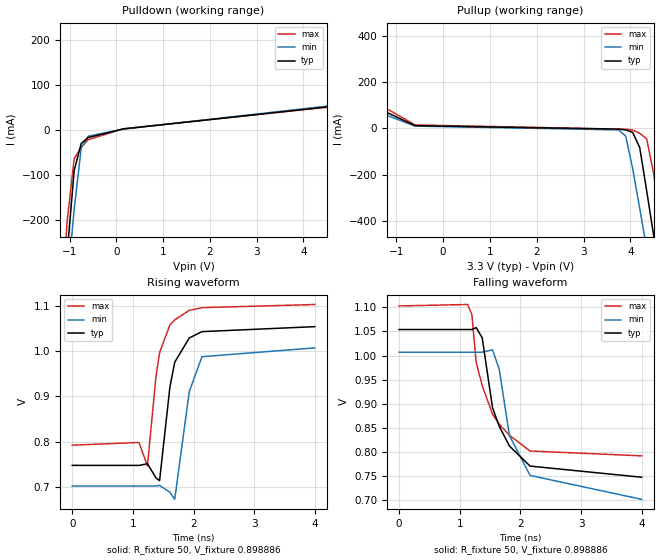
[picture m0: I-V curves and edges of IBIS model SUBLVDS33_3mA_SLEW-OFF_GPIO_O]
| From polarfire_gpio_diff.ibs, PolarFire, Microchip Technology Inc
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|   Model SUBLVDS33_3mA_SLEW-OFF_GPIO_O
[Model]   SUBLVDS33_3mA_SLEW-OFF_GPIO_O
Model_type   Output
Polarity   Non-Inverting
Enable   Active-High
Vmeas =   0.9
Cref =   5p
Rref =   100
|   typ   min   max
C_comp_pullup   2.605e-12   2.605e-12   2.76e-12
C_comp_pulldown  2.605e-12   2.605e-12   2.76e-12
[Temperature Range]  25C   100C   -40C
[Voltage Range]  3.3   3.15   3.45
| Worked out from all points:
|   slope of the pulldown table from 0 to 0.495 V, typ, clamps not added: 171 ohm
|   slope of the pullup table from 0 to 0.495 V, typ, clamps not added: 176 ohm
|   rising waveform, R_fixture 50, V_fixture 0.898886: 20-80 % time 213ps typ, 207ps min, 217ps max; typ from 0.747 V to 1.05 V
|   falling waveform, R_fixture 50, V_fixture 0.898886: 20-80 % time 418ps typ, 409ps min, 442ps max; typ from 1.05 V to 0.747 V
[Pulldown]
|Voltage   I(typ)   I(min)   I(max)
-3.3V     -3.224A    -2.966A    -3.553A
-1.2V     -469mA     -521.7mA   -423mA
-1.05V    -275mA     -349.1mA   -203.3mA
-900mV    -90.53mA   -176.6mA   -64.54mA
-750mV    -30.57mA   -40.94mA   -38.72mA
-600mV    -17.3mA    -14.49mA   -22.18mA
150mV     1.814mA    1.54mA     2.146mA
4.5V      50.8mA     52.59mA    50.08mA
5.1V      117.8mA    111.4mA    122.1mA
5.7V      201.3mA    184.7mA    217.6mA
6V        247.4mA    226.7mA    269mA
6.6V      351.1mA    318.2mA    381.4mA
[Pullup]
|Voltage   I(typ)   I(min)   I(max)
-3.3V     376.6mA    318.2mA    437.8mA
-1.65V    110.7mA    90.17mA    135.4mA
-600mV    11.45mA    9.806mA    14.86mA
3.75V     -3.373mA   -6.697mA   -3.2mA
3.9V      -6.563mA   -33.2mA    -3.454mA
4.05V     -17.37mA   -173.6mA   -7.379mA
4.2V      -82.62mA   -345.9mA   -20.83mA
4.35V     -270.5mA   -518.2mA   -45.68mA
4.5V      -464.2mA   -690.5mA   -197.3mA
4.65V     -658.2mA   -862.9mA   -416.7mA
4.8V      -852.3mA   -1.036A    -636.1mA
6.6V      -3.216A    -3.136A    -3.317A
[Ramp]
| variable   typ   min   max
dV/dt_r 0.2069/0.2152e-9   0.2017/0.2150e-9   0.2154/0.2043e-9
dV/dt_f 0.1869/0.4150e-9   0.1869/0.4076e-9   0.1896/0.4408e-9
R_load = 50
[Rising waveform]
R_fixture= 50
V_fixture= 0.898886
V_fixture_min= 0.853055
V_fixture_max= 0.946985
|Time   V(typ)   V(min)   V(max)
0s        747.2mV    701.5mV    791.9mV
1.1ns     747.1mV    701.5mV    797.8mV
1.24ns    750.8mV    701.5mV    746mV
1.38ns    719.7mV    701.5mV    942.8mV
1.44ns    713.3mV    703mV      996.4mV
1.61ns    919.9mV    687.8mV    1.058V
1.69ns    975.3mV    672.1mV    1.069V
1.93ns    1.029V     910.4mV    1.09V
2.14ns    1.043V     987.6mV    1.096V
4ns       1.054V     1.007V     1.103V
[Falling waveform]
R_fixture= 50
V_fixture= 0.898886
V_fixture_min= 0.853055
V_fixture_max= 0.946985
|Time   V(typ)   V(min)   V(max)
0s        1.054V     1.007V     1.103V
1.13ns    1.054V     1.007V     1.106V
1.2ns     1.054V     1.007V     1.085V
1.27ns    1.058V     1.007V     986.6mV
1.37ns    1.037V     1.007V     937.5mV
1.54ns    891.9mV    1.012V     878.5mV
1.65ns    853.3mV    972mV      857.7mV
1.82ns    812mV      833.5mV    834.2mV
2.16ns    770.4mV    751mV      801.8mV
4ns       747.3mV    701.4mV    791.7mV
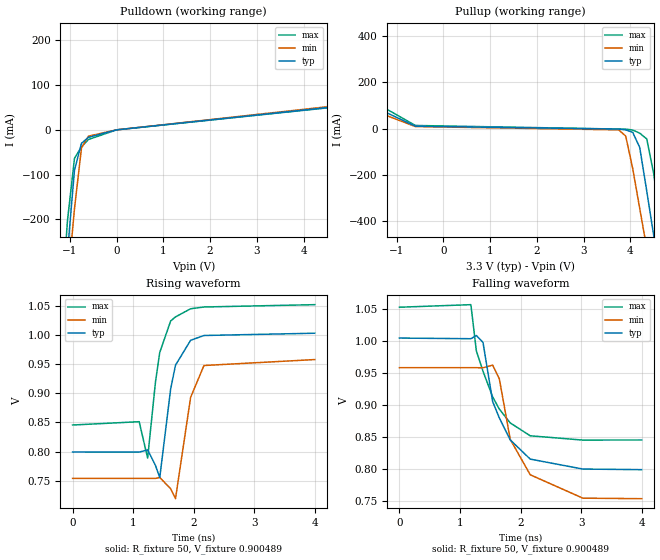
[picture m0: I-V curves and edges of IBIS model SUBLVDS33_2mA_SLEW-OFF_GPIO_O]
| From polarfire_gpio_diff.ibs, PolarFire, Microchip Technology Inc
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|   Model SUBLVDS33_2mA_SLEW-OFF_GPIO_O
[Model]   SUBLVDS33_2mA_SLEW-OFF_GPIO_O
Model_type   Output
Polarity   Non-Inverting
Enable   Active-High
Vmeas =   0.9
Cref =   5p
Rref =   100
|   typ   min   max
C_comp_pullup   2.605e-12   2.605e-12   2.76e-12
C_comp_pulldown  2.605e-12   2.605e-12   2.76e-12
[Temperature Range]  25C   100C   -40C
[Voltage Range]  3.3   3.15   3.45
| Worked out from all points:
|   slope of the pulldown table from 0 to 0.495 V, typ, clamps not added: 259 ohm
|   slope of the pullup table from 0 to 0.495 V, typ, clamps not added: 256 ohm
|   rising waveform, R_fixture 50, V_fixture 0.900489: 20-80 % time 201ps typ, 204ps min, 215ps max; typ from 0.799 V to 1 V
|   falling waveform, R_fixture 50, V_fixture 0.900489: 20-80 % time 442ps typ, 434ps min, 453ps max; typ from 1 V to 0.799 V
[Pulldown]
|Voltage   I(typ)   I(min)   I(max)
-3.3V     -3.224A    -2.966A    -3.553A
-1.2V     -468.8mA   -521.5mA   -422.7mA
-1.05V    -274.8mA   -348.9mA   -203.1mA
-900mV    -90.12mA   -176.4mA   -63.79mA
-750mV    -30mA      -40.53mA   -37.99mA
-600mV    -16.77mA   -14.07mA   -21.49mA
0V        -45.85uA   -39.75uA   -56.18uA
4.5V      49.74mA    51.52mA    48.98mA
5.1V      116.7mA    110.4mA    121mA
5.7V      200.2mA    183.6mA    216.5mA
6V        246.3mA    225.5mA    267.8mA
6.6V      349.8mA    316.9mA    380mA
[Pullup]
|Voltage   I(typ)   I(min)   I(max)
-3.3V     376.3mA    318mA      437.5mA
-1.65V    109.6mA    89.69mA    134mA
-600mV    10.25mA    8.672mA    13.36mA
3.75V     -2.338mA   -5.68mA    -2.152mA
3.9V      -5.54mA    -32.24mA   -2.409mA
4.05V     -16.37mA   -172.7mA   -6.348mA
4.2V      -81.72mA   -345mA     -19.82mA
4.35V     -269.6mA   -517.3mA   -44.67mA
4.5V      -463.3mA   -689.6mA   -196.4mA
4.65V     -657.3mA   -862mA     -415.8mA
4.8V      -851.4mA   -1.035A    -635.2mA
6.6V      -3.215A    -3.135A    -3.316A
[Ramp]
| variable   typ   min   max
dV/dt_r 0.1497/0.4588e-9   0.1444/0.2203e-9   0.1586/0.2138e-9
dV/dt_f 0.1254/0.4377e-9   0.1252/0.4333e-9   0.1268/0.4512e-9
R_load = 50
[Rising waveform]
R_fixture= 50
V_fixture= 0.900489
V_fixture_min= 0.855159
V_fixture_max= 0.948409
|Time   V(typ)   V(min)   V(max)
0s        799.1mV    753.9mV    845.5mV
1.1ns     799mV      753.9mV    851.2mV
1.24ns    802.9mV    753.9mV    788.7mV
1.37ns    775.9mV    753.9mV    920mV
1.44ns    755.2mV    755.5mV    970mV
1.62ns    907.3mV    736.1mV    1.024V
1.7ns     948.2mV    719.1mV    1.031V
1.95ns    990.9mV    893mV      1.045V
2.17ns    999.1mV    947.6mV    1.048V
4ns       1.003V     957.8mV    1.052V
[Falling waveform]
R_fixture= 50
V_fixture= 0.900489
V_fixture_min= 0.855159
V_fixture_max= 0.948409
|Time   V(typ)   V(min)   V(max)
0s        1.004V     957.9mV    1.052V
1.18ns    1.003V     957.9mV    1.056V
1.27ns    1.008V     957.9mV    984.2mV
1.38ns    997.3mV    957.7mV    952.4mV
1.54ns    905mV      961.9mV    912.4mV
1.65ns    879.7mV    940.4mV    893.4mV
1.83ns    845.4mV    846.3mV    871.9mV
2.16ns    815.6mV    791.2mV    851.9mV
3.03ns    800.1mV    754.8mV    845.2mV
4ns       799.2mV    754mV      845.4mV
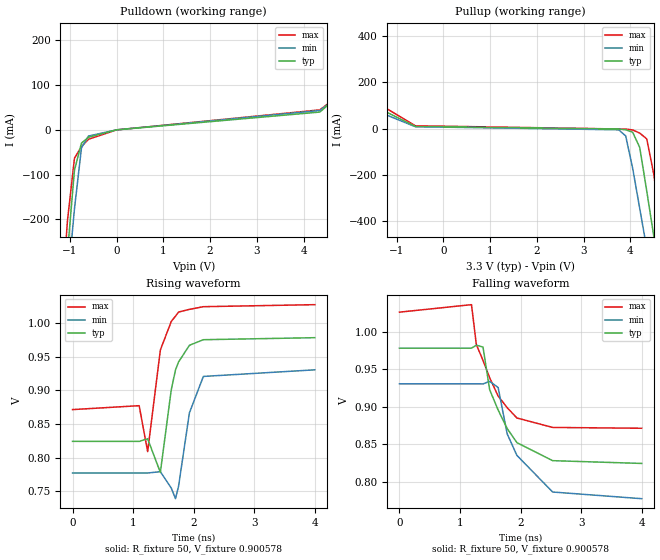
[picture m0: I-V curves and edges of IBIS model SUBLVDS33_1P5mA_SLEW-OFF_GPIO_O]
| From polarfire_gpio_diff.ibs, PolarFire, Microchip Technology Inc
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|   Model SUBLVDS33_1P5mA_SLEW-OFF_GPIO_O
[Model]   SUBLVDS33_1P5mA_SLEW-OFF_GPIO_O
Model_type   Output
Polarity   Non-Inverting
Enable   Active-High
Vmeas =   0.9
Cref =   5p
Rref =   100
|   typ   min   max
C_comp_pullup   2.605e-12   2.605e-12   2.76e-12
C_comp_pulldown  2.605e-12   2.605e-12   2.76e-12
[Temperature Range]  25C   100C   -40C
[Voltage Range]  3.3   3.15   3.45
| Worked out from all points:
|   slope of the pulldown table from 0 to 0.495 V, typ, clamps not added: 347 ohm
|   slope of the pullup table from 0 to 0.495 V, typ, clamps not added: 335 ohm
|   rising waveform, R_fixture 50, V_fixture 0.900578: 20-80 % time 213ps typ, 209ps min, 216ps max; typ from 0.824 V to 0.978 V
|   falling waveform, R_fixture 50, V_fixture 0.900578: 20-80 % time 470ps typ, 466ps min, 488ps max; typ from 0.978 V to 0.824 V
[Pulldown]
|Voltage   I(typ)   I(min)   I(max)
-3.3V     -3.224A    -2.966A    -3.553A
-1.2V     -468.6mA   -521.4mA   -422.6mA
-1.05V    -274.7mA   -348.8mA   -202.9mA
-900mV    -89.88mA   -176.3mA   -63.35mA
-750mV    -29.67mA   -40.29mA   -37.56mA
-600mV    -16.47mA   -13.82mA   -21.09mA
0V        -44.72uA   -38.64uA   -54.85uA
4.35V     39.73mA    43.18mA    44.6mA
4.8V      79.86mA    78.4mA     80.45mA
5.85V     222.2mA    203.6mA    241.2mA
6V        245.7mA    224.9mA    267.2mA
6.6V      349.1mA    316.2mA    379.3mA
[Pullup]
|Voltage   I(typ)   I(min)   I(max)
-3.3V     376.2mA    317.9mA    437.3mA
-1.8V     129.2mA    106.3mA    157mA
-600mV    9.446mA    8.226mA    12.35mA
3.75V     -1.827mA   -5.176mA   -1.637mA
3.9V      -5.035mA   -31.76mA   -1.895mA
4.05V     -15.87mA   -172.3mA   -5.84mA
4.2V      -81.27mA   -344.5mA   -19.32mA
4.35V     -269.2mA   -516.9mA   -44.17mA
4.5V      -462.9mA   -689.1mA   -196mA
4.65V     -656.9mA   -861.6mA   -415.3mA
4.8V      -851mA     -1.034A    -634.7mA
6.6V      -3.215A    -3.135A    -3.316A
[Ramp]
| variable   typ   min   max
dV/dt_r 0.1218/0.2205e-9   0.1162/0.6125e-9   0.1307/0.2161e-9
dV/dt_f 94.9196e-3/0.4670e-9   94.6276e-3/0.4642e-9   99.1896e-3/0.4744e-9
R_load = 50
[Rising waveform]
R_fixture= 50
V_fixture= 0.900578
V_fixture_min= 0.853258
V_fixture_max= 0.948392
|Time   V(typ)   V(min)   V(max)
0s        824.2mV    777.2mV    871.3mV
1.1ns     824.1mV    777.2mV    877.1mV
1.24ns    828mV      777.2mV    808.9mV
1.45ns    778.1mV    779.2mV    959.8mV
1.63ns    900.7mV    754.9mV    1.002V
1.7ns     930.1mV    739.1mV    1.01V
1.75ns    941.9mV    757.2mV    1.016V
1.93ns    966.7mV    866.5mV    1.02V
2.16ns    975mV      920.5mV    1.024V
4ns       978mV      930.3mV    1.027V
[Falling waveform]
R_fixture= 50
V_fixture= 0.900578
V_fixture_min= 0.853258
V_fixture_max= 0.948392
|Time   V(typ)   V(min)   V(max)
0s        978mV      930.5mV    1.026V
1.19ns    978mV      930.5mV    1.036V
1.27ns    981.9mV    930.5mV    982.9mV
1.38ns    979.5mV    930.3mV    961.7mV
1.49ns    922.6mV    933.7mV    938.6mV
1.63ns    895.5mV    925.6mV    914.1mV
1.78ns    870.8mV    863.6mV    898.6mV
1.94ns    852mV      835mV      884.9mV
2.53ns    828mV      786.2mV    872.3mV
4ns       824.3mV    777.3mV    871.2mV
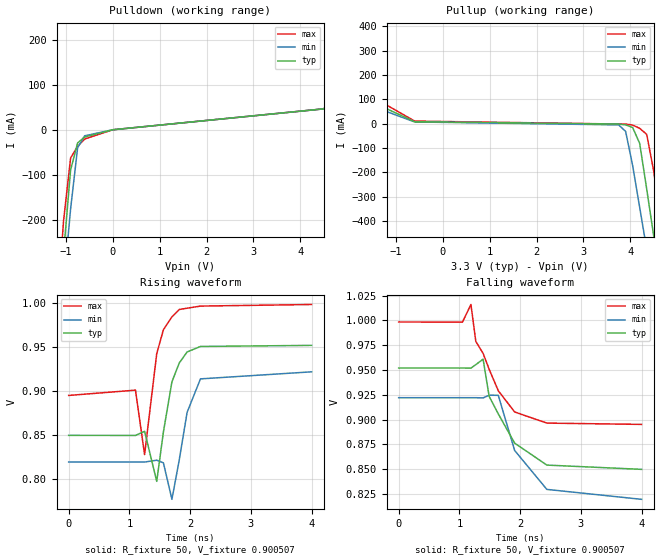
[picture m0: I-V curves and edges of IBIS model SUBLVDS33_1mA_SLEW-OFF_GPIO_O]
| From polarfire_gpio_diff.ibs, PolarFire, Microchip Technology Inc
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|   Model SUBLVDS33_1mA_SLEW-OFF_GPIO_O
[Model]   SUBLVDS33_1mA_SLEW-OFF_GPIO_O
Model_type   Output
Polarity   Non-Inverting
Enable   Active-High
Vmeas =   0.9
Cref =   5p
Rref =   100
|   typ   min   max
C_comp_pullup   2.605e-12   2.605e-12   2.76e-12
C_comp_pulldown  2.605e-12   2.605e-12   2.76e-12
[Temperature Range]  25C   100C   -40C
[Voltage Range]  3.3   3.15   3.45
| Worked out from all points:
|   slope of the pulldown table from 0 to 0.495 V, typ, clamps not added: 533 ohm
|   slope of the pullup table from 0 to 0.495 V, typ, clamps not added: 495 ohm
|   rising waveform, R_fixture 50, V_fixture 0.900507: 20-80 % time 226ps typ, 218ps min, 215ps max; typ from 0.85 V to 0.952 V
|   falling waveform, R_fixture 50, V_fixture 0.900507: 20-80 % time 519ps typ, 534ps min, 530ps max; typ from 0.952 V to 0.85 V
[Pulldown]
|Voltage   I(typ)   I(min)   I(max)
-3.3V     -3.223A    -2.966A    -3.553A
-1.2V     -468.5mA   -521.2mA   -422.4mA
-1.05V    -274.5mA   -348.6mA   -202.7mA
-900mV    -89.6mA    -176.2mA   -62.84mA
-750mV    -29.27mA   -40mA      -37.06mA
-600mV    -16.09mA   -13.52mA   -20.62mA
0V        -43.57uA   -38.31uA   -53.41uA
4.5V      46.42mA    46.42mA    46.51mA
5.1V      107.6mA    98.38mA    114mA
5.85V     201.7mA    177.5mA    224.4mA
6.3V      263.8mA    230mA      295mA
6.6V      307.6mA    265.9mA    344.2mA
[Pullup]
|Voltage   I(typ)   I(min)   I(max)
-3.3V     335.5mA    274mA      398.2mA
-1.65V    102.3mA    82.31mA    126.8mA
-600mV    8.394mA    7.417mA    11.02mA
3.75V     -1.307mA   -4.668mA   -1.11mA
3.9V      -4.521mA   -31.28mA   -1.369mA
4.05V     -15.36mA   -171.9mA   -5.321mA
4.2V      -80.82mA   -344.1mA   -18.81mA
4.35V     -268.7mA   -516.4mA   -43.67mA
4.5V      -462.5mA   -688.7mA   -195.6mA
4.65V     -656.4mA   -861.1mA   -414.9mA
4.8V      -850.6mA   -1.034A    -634.3mA
6.6V      -3.214A    -3.134A    -3.315A
[Ramp]
| variable   typ   min   max
dV/dt_r 93.3555e-3/0.2232e-9   88.2530e-3/0.2366e-9   0.1023/0.2229e-9
dV/dt_f 67.0868e-3/0.5121e-9   63.8189e-3/0.5277e-9   72.4023e-3/0.5166e-9
R_load = 50
[Rising waveform]
R_fixture= 50
V_fixture= 0.900507
V_fixture_min= 0.870719
V_fixture_max= 0.946468
|Time   V(typ)   V(min)   V(max)
0s        849.9mV    819.6mV    895.2mV
1.1ns     849.8mV    819.6mV    901.2mV
1.25ns    854.5mV    819.6mV    828.1mV
1.45ns    797.7mV    821.7mV    942.7mV
1.56ns    853.8mV    818.7mV    969.8mV
1.7ns     910.6mV    777.3mV    984.4mV
1.82ns    931.9mV    821.7mV    992.7mV
1.95ns    944.5mV    876mV      994.2mV
2.17ns    950.8mV    914mV      996.6mV
4ns       952mV      922mV      998.4mV
[Falling waveform]
R_fixture= 50
V_fixture= 0.900507
V_fixture_min= 0.870719
V_fixture_max= 0.946468
|Time   V(typ)   V(min)   V(max)
0s        952mV      922.1mV    998.4mV
1.05ns    952mV      922.1mV    998.2mV
1.19ns    951.9mV    922.1mV    1.016V
1.27ns    955.4mV    922.1mV    978.8mV
1.39ns    960.9mV    921.9mV    966.8mV
1.49ns    923.4mV    924.6mV    950.7mV
1.64ns    905.8mV    924.5mV    929.1mV
1.91ns    876.3mV    868.9mV    907.7mV
2.44ns    854.2mV    829.7mV    896.5mV
4ns       849.9mV    819.7mV    895.2mV
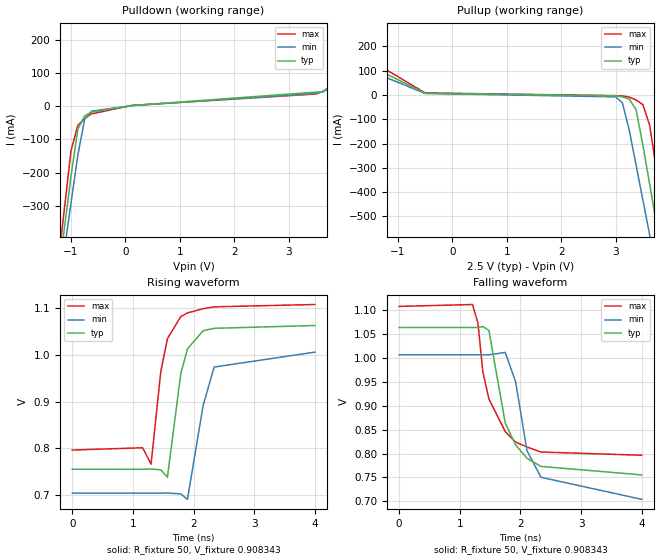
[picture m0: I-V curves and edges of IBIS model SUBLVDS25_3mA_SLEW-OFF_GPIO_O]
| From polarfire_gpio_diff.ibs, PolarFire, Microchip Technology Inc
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|   Model SUBLVDS25_3mA_SLEW-OFF_GPIO_O
[Model]   SUBLVDS25_3mA_SLEW-OFF_GPIO_O
Model_type   Output
Polarity   Non-Inverting
Enable   Active-High
Vmeas =   0.9
Cref =   5p
Rref =   100
|   typ   min   max
C_comp_pullup   2.605e-12   2.605e-12   2.76e-12
C_comp_pulldown  2.605e-12   2.605e-12   2.76e-12
[Temperature Range]  25C   100C   -40C
[Voltage Range]  2.5   2.375   2.625
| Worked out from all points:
|   slope of the pulldown table from 0 to 0.375 V, typ, clamps not added: 133 ohm
|   slope of the pullup table from 0 to 0.375 V, typ, clamps not added: 158 ohm
|   rising waveform, R_fixture 50, V_fixture 0.908343: 20-80 % time 207ps typ, 241ps min, 215ps max; typ from 0.755 V to 1.06 V
|   falling waveform, R_fixture 50, V_fixture 0.908343: 20-80 % time 339ps typ, 328ps min, 356ps max; typ from 1.06 V to 0.755 V
[Pulldown]
|Voltage   I(typ)   I(min)   I(max)
-2.5V     -2.163A    -2.027A    -2.344A
-1.25V    -533.4mA   -578.8mA   -495.9mA
-1.125V   -371.6mA   -435.1mA   -312.8mA
-1V       -210.1mA   -291.2mA   -133.8mA
-875mV    -69.39mA   -147.6mA   -57.98mA
-750mV    -29.84mA   -40.31mA   -37.96mA
-625mV    -18.35mA   -15.59mA   -23.66mA
125mV     1.516mA    1.235mA    1.849mA
3.5V      41.78mA    38.14mA    36.13mA
3.625V    43.11mA    43.14mA    43.68mA
4.125V    94.03mA    87.71mA    99.87mA
5V        213.1mA    191.2mA    235.8mA
[Pullup]
|Voltage   I(typ)   I(min)   I(max)
-2.5V     229mA      189.2mA    274.9mA
-500mV    6.781mA    5.893mA    8.159mA
3V        -3.823mA   -8.066mA   -3.224mA
3.125V    -7.744mA   -33.19mA   -4.014mA
3.25V     -17.37mA   -144.9mA   -8.874mA
3.375V    -59.99mA   -288.4mA   -20.83mA
3.5V      -206mA     -432mA     -39.75mA
3.625V    -367.3mA   -575.6mA   -125.5mA
3.75V     -528.8mA   -719.2mA   -307mA
3.875V    -690.5mA   -862.9mA   -489.8mA
4V        -852.3mA   -1.007A    -672.7mA
5V        -2.157A    -2.168A    -2.149A
[Ramp]
| variable   typ   min   max
dV/dt_r 0.1965/0.2126e-9   0.1898/0.2473e-9   0.2057/0.2158e-9
dV/dt_f 0.1873/0.3380e-9   0.1843/0.3290e-9   0.1894/0.3548e-9
R_load = 50
[Rising waveform]
R_fixture= 50
V_fixture= 0.908343
V_fixture_min= 0.852650
V_fixture_max= 0.951521
|Time   V(typ)   V(min)   V(max)
0s        755.3mV    704.2mV    796.4mV
1.16ns    755.2mV    704.2mV    801.3mV
1.3ns     755.8mV    704.2mV    766.3mV
1.46ns    754mV      704.2mV    964.4mV
1.57ns    738.4mV    704.4mV    1.035V
1.79ns    959.9mV    702.5mV    1.082V
1.9ns     1.013V     690.9mV    1.09V
2.16ns    1.052V     892.3mV    1.099V
2.34ns    1.057V     974.1mV    1.103V
4ns       1.063V     1.006V     1.108V
[Falling waveform]
R_fixture= 50
V_fixture= 0.908343
V_fixture_min= 0.852650
V_fixture_max= 0.951521
|Time   V(typ)   V(min)   V(max)
0s        1.063V     1.006V     1.107V
1.21ns    1.063V     1.006V     1.111V
1.3ns     1.063V     1.006V     1.072V
1.38ns    1.065V     1.006V     971mV
1.48ns    1.057V     1.006V     914mV
1.75ns    863.8mV    1.011V     845.8mV
1.92ns    818.2mV    950.2mV    824mV
2.11ns    789.9mV    805.5mV    813.5mV
2.34ns    773.1mV    750.4mV    803.1mV
4ns       755.4mV    704.4mV    796.4mV
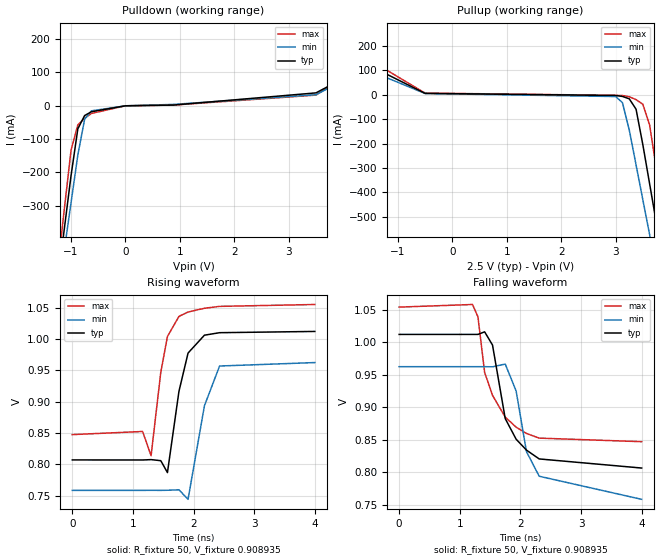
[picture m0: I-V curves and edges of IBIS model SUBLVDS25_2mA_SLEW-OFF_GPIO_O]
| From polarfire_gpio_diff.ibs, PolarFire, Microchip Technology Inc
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|   Model SUBLVDS25_2mA_SLEW-OFF_GPIO_O
[Model]   SUBLVDS25_2mA_SLEW-OFF_GPIO_O
Model_type   Output
Polarity   Non-Inverting
Enable   Active-High
Vmeas =   0.9
Cref =   5p
Rref =   100
|   typ   min   max
C_comp_pullup   2.605e-12   2.605e-12   2.76e-12
C_comp_pulldown  2.605e-12   2.605e-12   2.76e-12
[Temperature Range]  25C   100C   -40C
[Voltage Range]  2.5   2.375   2.625
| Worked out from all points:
|   slope of the pulldown table from 0 to 0.375 V, typ, clamps not added: 201 ohm
|   slope of the pullup table from 0 to 0.375 V, typ, clamps not added: 218 ohm
|   rising waveform, R_fixture 50, V_fixture 0.908935: 20-80 % time 210ps typ, 219ps min, 205ps max; typ from 0.807 V to 1.01 V
|   falling waveform, R_fixture 50, V_fixture 0.908935: 20-80 % time 356ps typ, 330ps min, 391ps max; typ from 1.01 V to 0.807 V
[Pulldown]
|Voltage   I(typ)   I(min)   I(max)
-2.5V     -2.163A    -2.026A    -2.344A
-1.25V    -533.1mA   -578.7mA   -495.6mA
-1.125V   -371.4mA   -434.9mA   -312.5mA
-1V       -209.9mA   -291.1mA   -133.4mA
-875mV    -68.95mA   -147.4mA   -57.28mA
-750mV    -29.31mA   -39.96mA   -37.28mA
-625mV    -17.86mA   -15.22mA   -23.02mA
0V        -45.59uA   -39.04uA   -55.83uA
875mV     2.083mA    4.082mA    2.079mA
3.5V      38.72mA    33.15mA    32.06mA
4.125V    92.98mA    86.71mA    98.81mA
5V        211.9mA    190.1mA    234.6mA
[Pullup]
|Voltage   I(typ)   I(min)   I(max)
-2.5V     228.7mA    189mA      273.9mA
-500mV    5.869mA    5.185mA    7.014mA
3V        -2.791mA   -7.058mA   -2.178mA
3.125V    -6.724mA   -32.24mA   -2.972mA
3.25V     -16.36mA   -144.1mA   -7.846mA
3.375V    -59.06mA   -287.5mA   -19.81mA
3.5V      -205.1mA   -431.2mA   -38.73mA
3.625V    -366.4mA   -574.7mA   -124.7mA
3.75V     -528mA     -718.3mA   -306.1mA
3.875V    -689.6mA   -862mA     -488.9mA
4V        -851.4mA   -1.006A    -671.8mA
5V        -2.156A    -2.167A    -2.148A
[Ramp]
| variable   typ   min   max
dV/dt_r 0.1363/0.2198e-9   0.1341/0.2378e-9   0.1448/0.2048e-9
dV/dt_f 0.1258/0.3544e-9   0.1250/0.3319e-9   0.1271/0.3892e-9
R_load = 50
[Rising waveform]
R_fixture= 50
V_fixture= 0.908935
V_fixture_min= 0.859516
V_fixture_max= 0.950603
|Time   V(typ)   V(min)   V(max)
0s        806.9mV    758.3mV    847.3mV
1.16ns    806.8mV    758.3mV    852.3mV
1.3ns     807.4mV    758.4mV    813.6mV
1.46ns    805.7mV    758.3mV    946.7mV
1.57ns    786.7mV    758.5mV    1.004V
1.76ns    916.5mV    759.2mV    1.036V
1.91ns    977.5mV    744mV      1.043V
2.18ns    1.006V     893.3mV    1.049V
2.43ns    1.01V      956.8mV    1.052V
4ns       1.012V     962.3mV    1.055V
[Falling waveform]
R_fixture= 50
V_fixture= 0.908935
V_fixture_min= 0.859516
V_fixture_max= 0.950603
|Time   V(typ)   V(min)   V(max)
0s        1.012V     962.4mV    1.054V
1.21ns    1.012V     962.4mV    1.058V
1.3ns     1.012V     962.4mV    1.039V
1.41ns    1.016V     962.4mV    953.6mV
1.54ns    995.7mV    962.2mV    918.4mV
1.75ns    882.6mV    966.4mV    884.9mV
1.93ns    850.9mV    925mV      869.4mV
2.1ns     834.2mV    831.9mV    859.8mV
2.31ns    820.6mV    794mV      852.6mV
4ns       806.6mV    758.5mV    847.1mV
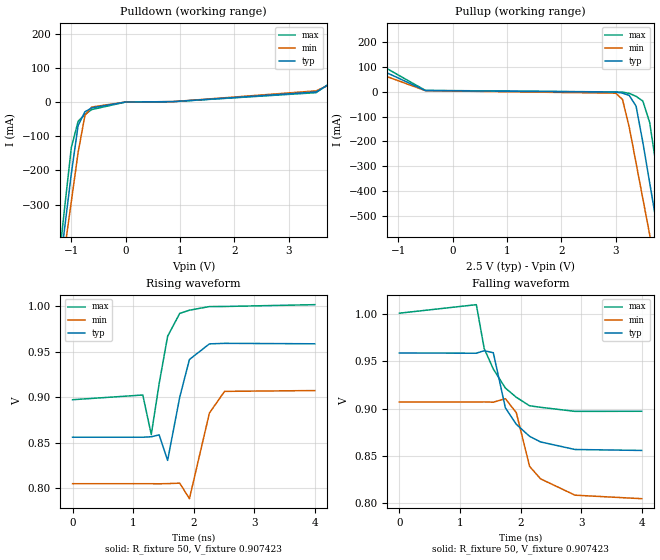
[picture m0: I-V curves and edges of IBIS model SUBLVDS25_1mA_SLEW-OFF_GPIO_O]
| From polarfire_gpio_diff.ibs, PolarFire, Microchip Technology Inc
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|   Model SUBLVDS25_1mA_SLEW-OFF_GPIO_O
[Model]   SUBLVDS25_1mA_SLEW-OFF_GPIO_O
Model_type   Output
Polarity   Non-Inverting
Enable   Active-High
Vmeas =   0.9
Cref =   5p
Rref =   100
|   typ   min   max
C_comp_pullup   2.605e-12   2.605e-12   2.76e-12
C_comp_pulldown  2.605e-12   2.605e-12   2.76e-12
[Temperature Range]  25C   100C   -40C
[Voltage Range]  2.5   2.375   2.625
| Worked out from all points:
|   slope of the pulldown table from 0 to 0.375 V, typ, clamps not added: 414 ohm
|   slope of the pullup table from 0 to 0.375 V, typ, clamps not added: 404 ohm
|   rising waveform, R_fixture 50, V_fixture 0.907423: 20-80 % time 200ps typ, 221ps min, 215ps max; typ from 0.856 V to 0.959 V
|   falling waveform, R_fixture 50, V_fixture 0.907423: 20-80 % time 420ps typ, 376ps min, 443ps max; typ from 0.959 V to 0.856 V
[Pulldown]
|Voltage   I(typ)   I(min)   I(max)
-2.5V     -2.163A    -2.026A    -2.344A
-1.25V    -532.9mA   -578.4mA   -495.3mA
-1.125V   -371.1mA   -434.6mA   -312.2mA
-1V       -209.6mA   -290.8mA   -132.9mA
-875mV    -68.38mA   -147.2mA   -56.4mA
-750mV    -28.63mA   -39.47mA   -36.42mA
-625mV    -17.22mA   -14.7mA    -22.2mA
0V        -43.3uA    -36.9uA    -53.15uA
875mV     1.025mA    1.08mA     1.015mA
3.5V      29.27mA    32.47mA    27.23mA
4.25V     98.24mA    86.75mA    108mA
5V        188.4mA    160.2mA    215.3mA
[Pullup]
|Voltage   I(typ)   I(min)   I(max)
-2.5V     206.3mA    163.9mA    252.8mA
-500mV    4.398mA    4.043mA    5.169mA
3V        -1.763mA   -6.046mA   -1.136mA
3.125V    -5.707mA   -31.28mA   -1.936mA
3.25V     -15.36mA   -143.2mA   -6.823mA
3.375V    -58.14mA   -286.6mA   -18.81mA
3.5V      -204.2mA   -430.3mA   -37.73mA
3.625V    -365.6mA   -573.8mA   -123.8mA
3.75V     -527.1mA   -717.4mA   -305.2mA
3.875V    -688.8mA   -861.1mA   -488mA
4V        -850.6mA   -1.005A    -670.9mA
5V        -2.155A    -2.166A    -2.147A
[Ramp]
| variable   typ   min   max
dV/dt_r 77.6451e-3/0.6484e-9   74.7053e-3/0.2527e-9   85.6853e-3/0.2092e-9
dV/dt_f 64.3223e-3/0.4124e-9   63.5630e-3/0.3695e-9   67.9167e-3/0.4277e-9
R_load = 50
[Rising waveform]
R_fixture= 50
V_fixture= 0.907423
V_fixture_min= 0.855621
V_fixture_max= 0.949514
|Time   V(typ)   V(min)   V(max)
0s        856mV      804.8mV    897.3mV
1.16ns    856mV      804.8mV    902.5mV
1.3ns     856.5mV    804.8mV    858.9mV
1.43ns    858.6mV    804.7mV    915mV
1.57ns    830.5mV    804.9mV    967.2mV
1.77ns    900.1mV    805.4mV    992.4mV
1.93ns    941.6mV    788.3mV    995.9mV
2.26ns    958.8mV    882.6mV    999.9mV
2.51ns    959.4mV    906.5mV    1V
4ns       958.9mV    907.4mV    1.002V
[Falling waveform]
R_fixture= 50
V_fixture= 0.907423
V_fixture_min= 0.855621
V_fixture_max= 0.949514
|Time   V(typ)   V(min)   V(max)
0s        958.9mV    907.1mV    1.001V
1.27ns    958.7mV    907.1mV    1.01V
1.4ns     961.3mV    907.2mV    963.6mV
1.55ns    959.2mV    906.9mV    942mV
1.75ns    900.9mV    910.6mV    921.8mV
1.93ns    883.5mV    895.8mV    912.1mV
2.15ns    870.8mV    839mV      903.1mV
2.33ns    864.9mV    825.9mV    901.5mV
2.9ns     856.9mV    808.6mV    897.2mV
4ns       855.9mV    804.9mV    897.3mV
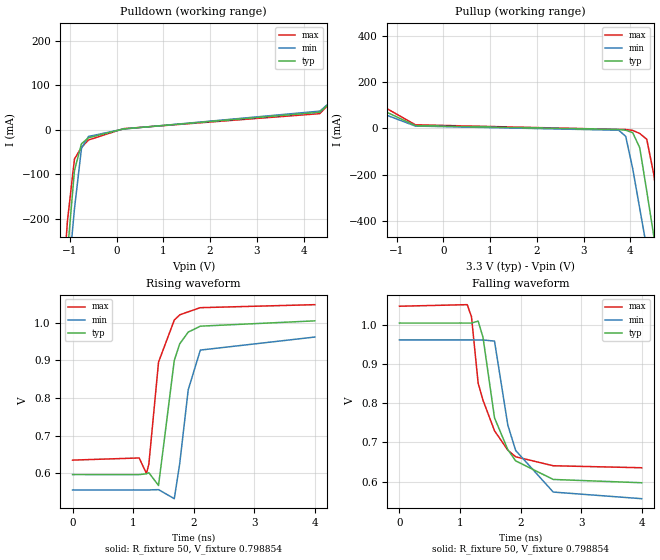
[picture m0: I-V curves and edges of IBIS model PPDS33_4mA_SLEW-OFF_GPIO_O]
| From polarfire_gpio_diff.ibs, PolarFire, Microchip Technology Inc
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|   Model PPDS33_4mA_SLEW-OFF_GPIO_O
[Model]   PPDS33_4mA_SLEW-OFF_GPIO_O
Model_type   Output
Polarity   Non-Inverting
Enable   Active-High
Vmeas =   0.8
Cref =   5p
Rref =   100
|   typ   min   max
C_comp_pullup   2.605e-12   2.605e-12   2.76e-12
C_comp_pulldown  2.605e-12   2.605e-12   2.76e-12
[Temperature Range]  25C   100C   -40C
[Voltage Range]  3.3   3.15   3.45
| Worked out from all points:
|   slope of the pulldown table from 0 to 0.495 V, typ, clamps not added: 125 ohm
|   slope of the pullup table from 0 to 0.495 V, typ, clamps not added: 138 ohm
|   rising waveform, R_fixture 50, V_fixture 0.798854: 20-80 % time 213ps typ, 217ps min, 213ps max; typ from 0.597 V to 1 V
|   falling waveform, R_fixture 50, V_fixture 0.798854: 20-80 % time 388ps typ, 388ps min, 396ps max; typ from 1 V to 0.597 V
[Pulldown]
|Voltage   I(typ)   I(min)   I(max)
-3.3V     -3.224A    -2.966A    -3.554A
-1.2V     -469.2mA   -521.9mA   -423.2mA
-1.05V    -275.2mA   -349.3mA   -203.6mA
-900mV    -90.89mA   -176.8mA   -65.15mA
-750mV    -31.06mA   -41.3mA    -39.32mA
-600mV    -17.76mA   -14.87mA   -22.73mA
150mV     2.168mA    1.81mA     2.613mA
4.35V     39.45mA    41.91mA    36.35mA
4.95V     100mA      96.45mA    102.4mA
5.7V      202.5mA    186mA      218.8mA
6V        248.7mA    228mA      270.2mA
6.6V      352.5mA    319.6mA    382.7mA
[Pullup]
|Voltage   I(typ)   I(min)   I(max)
-3.3V     377.2mA    318.6mA    438.7mA
-1.65V    111.9mA    90.88mA    136.9mA
-600mV    12.3mA     10.49mA    15.93mA
3.75V     -4.395mA   -7.694mA   -4.235mA
3.9V      -7.565mA   -34.14mA   -4.484mA
4.05V     -18.35mA   -174.5mA   -8.385mA
4.2V      -83.5mA    -346.7mA   -21.8mA
4.35V     -271.3mA   -519.1mA   -46.65mA
4.5V      -465.1mA   -691.4mA   -198.1mA
4.65V     -659mA     -863.8mA   -417.5mA
4.8V      -853.2mA   -1.036A    -636.8mA
6.6V      -3.217A    -3.137A    -3.318A
[Ramp]
| variable   typ   min   max
dV/dt_r 0.2629/0.2113e-9   0.2584/0.2166e-9   0.2691/0.2151e-9
dV/dt_f 0.2484/0.3855e-9   0.2471/0.3862e-9   0.2505/0.3934e-9
R_load = 50
[Rising waveform]
R_fixture= 50
V_fixture= 0.798854
V_fixture_min= 0.756448
V_fixture_max= 0.839681
|Time   V(typ)   V(min)   V(max)
0s        596.9mV    556.1mV    635.3mV
1.1ns     596.8mV    556.1mV    641mV
1.22ns    599mV      556.1mV    599.8mV
1.26ns    601.9mV    556.1mV    624.6mV
1.42ns    567.9mV    556.9mV    895.5mV
1.68ns    899.8mV    532.9mV    1.007V
1.77ns    944.1mV    626.3mV    1.021V
1.91ns    975.1mV    821.8mV    1.029V
2.11ns    990.9mV    927.4mV    1.04V
4ns       1.005V     962mV      1.048V
[Falling waveform]
R_fixture= 50
V_fixture= 0.798854
V_fixture_min= 0.756448
V_fixture_max= 0.839681
|Time   V(typ)   V(min)   V(max)
0s        1.005V     962mV      1.048V
1.12ns    1.005V     962mV      1.052V
1.19ns    1.005V     962mV      1.021V
1.3ns     1.01V      961.9mV    851.5mV
1.38ns    968.7mV    961.8mV    807.9mV
1.57ns    763.1mV    959mV      730.1mV
1.79ns    681.6mV    744.4mV    680.3mV
1.92ns    653.1mV    679.5mV    663.5mV
2.54ns    605.6mV    573.4mV    640.6mV
4ns       597.2mV    556.5mV    635.5mV
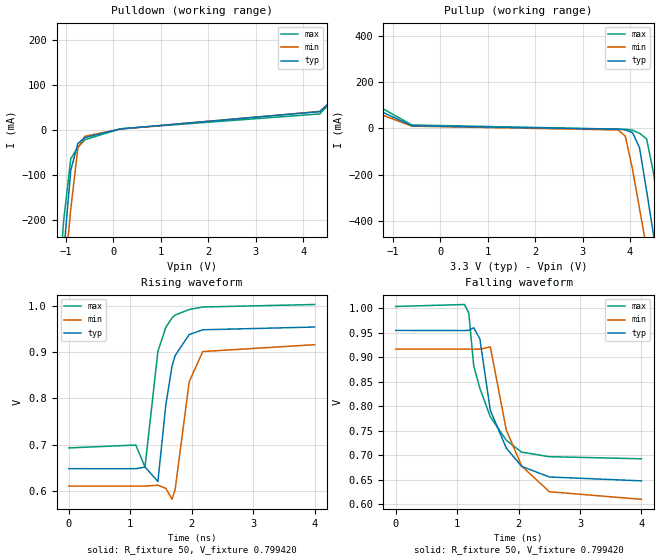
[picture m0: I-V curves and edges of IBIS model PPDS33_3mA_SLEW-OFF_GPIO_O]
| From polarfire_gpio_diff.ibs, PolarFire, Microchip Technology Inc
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|   Model PPDS33_3mA_SLEW-OFF_GPIO_O
[Model]   PPDS33_3mA_SLEW-OFF_GPIO_O
Model_type   Output
Polarity   Non-Inverting
Enable   Active-High
Vmeas =   0.8
Cref =   5p
Rref =   100
|   typ   min   max
C_comp_pullup   2.605e-12   2.605e-12   2.76e-12
C_comp_pulldown  2.605e-12   2.605e-12   2.76e-12
[Temperature Range]  25C   100C   -40C
[Voltage Range]  3.3   3.15   3.45
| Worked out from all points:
|   slope of the pulldown table from 0 to 0.495 V, typ, clamps not added: 168 ohm
|   slope of the pullup table from 0 to 0.495 V, typ, clamps not added: 176 ohm
|   rising waveform, R_fixture 50, V_fixture 0.799420: 20-80 % time 211ps typ, 210ps min, 211ps max; typ from 0.648 V to 0.954 V
|   falling waveform, R_fixture 50, V_fixture 0.799420: 20-80 % time 410ps typ, 411ps min, 416ps max; typ from 0.954 V to 0.648 V
[Pulldown]
|Voltage   I(typ)   I(min)   I(max)
-3.3V     -3.224A    -2.966A    -3.553A
-1.2V     -469mA     -521.7mA   -423mA
-1.05V    -275mA     -349.1mA   -203.3mA
-900mV    -90.52mA   -176.6mA   -64.52mA
-750mV    -30.57mA   -40.94mA   -38.71mA
-600mV    -17.3mA    -14.5mA    -22.17mA
150mV     1.829mA    1.554mA    2.152mA
4.35V     40.36mA    40.83mA    35.27mA
4.95V     98.97mA    95.38mA    101.3mA
5.7V      201.4mA    184.8mA    217.7mA
6V        247.5mA    226.8mA    269.1mA
6.6V      351.2mA    318.3mA    381.4mA
[Pullup]
|Voltage   I(typ)   I(min)   I(max)
-3.3V     376.9mA    318.4mA    438.2mA
-1.65V    110.7mA    90.21mA    135.5mA
-600mV    11.45mA    9.81mA     14.87mA
3.75V     -3.367mA   -6.683mA   -3.195mA
3.9V      -6.549mA   -33.18mA   -3.447mA
4.05V     -17.34mA   -173.6mA   -7.363mA
4.2V      -82.6mA    -345.8mA   -20.8mA
4.35V     -270.5mA   -518.2mA   -45.65mA
4.5V      -464.2mA   -690.5mA   -197.3mA
4.65V     -658.2mA   -862.9mA   -416.6mA
4.8V      -852.3mA   -1.036A    -636mA
6.6V      -3.216A    -3.136A    -3.317A
[Ramp]
| variable   typ   min   max
dV/dt_r 0.2050/0.2111e-9   0.2007/0.2148e-9   0.2119/0.2120e-9
dV/dt_f 0.1872/0.4072e-9   0.1870/0.4086e-9   0.1891/0.4138e-9
R_load = 50
[Rising waveform]
R_fixture= 50
V_fixture= 0.799420
V_fixture_min= 0.761896
V_fixture_max= 0.846877
|Time   V(typ)   V(min)   V(max)
0s        647.9mV    610.3mV    692.8mV
1.09ns    647.8mV    610.3mV    699mV
1.24ns    651.5mV    610.2mV    651.5mV
1.45ns    620.2mV    612.2mV    901.7mV
1.58ns    787.2mV    605.2mV    954mV
1.68ns    869.7mV    581.6mV    973.8mV
1.73ns    892.4mV    602.3mV    980.2mV
1.96ns    938mV      836.3mV    992.2mV
2.18ns    948.3mV    901.2mV    997.6mV
4ns       954.3mV    916.1mV    1.003V
[Falling waveform]
R_fixture= 50
V_fixture= 0.799420
V_fixture_min= 0.761896
V_fixture_max= 0.846877
|Time   V(typ)   V(min)   V(max)
0s        954.2mV    916.2mV    1.003V
1.12ns    954mV      916.2mV    1.007V
1.19ns    954.4mV    916.2mV    989.4mV
1.27ns    959.7mV    916.2mV    882.1mV
1.37ns    937mV      916mV      836.4mV
1.54ns    791.6mV    920.9mV    778.4mV
1.8ns     714.9mV    751.7mV    730.8mV
2.05ns    677.6mV    678.3mV    706.5mV
2.5ns     656mV      626mV      697.3mV
4ns       648.1mV    610.5mV    693mV
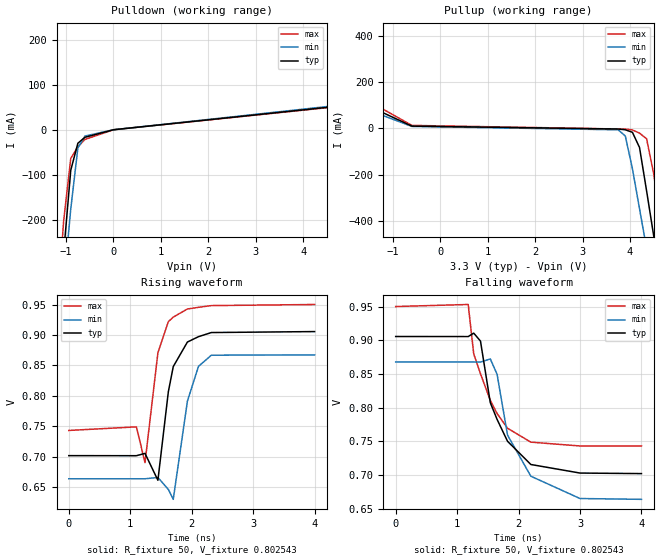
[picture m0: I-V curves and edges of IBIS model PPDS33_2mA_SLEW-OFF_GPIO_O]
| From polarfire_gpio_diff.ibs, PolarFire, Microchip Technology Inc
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|   Model PPDS33_2mA_SLEW-OFF_GPIO_O
[Model]   PPDS33_2mA_SLEW-OFF_GPIO_O
Model_type   Output
Polarity   Non-Inverting
Enable   Active-High
Vmeas =   0.8
Cref =   5p
Rref =   100
|   typ   min   max
C_comp_pullup   2.605e-12   2.605e-12   2.76e-12
C_comp_pulldown  2.605e-12   2.605e-12   2.76e-12
[Temperature Range]  25C   100C   -40C
[Voltage Range]  3.3   3.15   3.45
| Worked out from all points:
|   slope of the pulldown table from 0 to 0.495 V, typ, clamps not added: 256 ohm
|   slope of the pullup table from 0 to 0.495 V, typ, clamps not added: 256 ohm
|   rising waveform, R_fixture 50, V_fixture 0.802543: 20-80 % time 213ps typ, 209ps min, 216ps max; typ from 0.702 V to 0.906 V
|   falling waveform, R_fixture 50, V_fixture 0.802543: 20-80 % time 448ps typ, 444ps min, 459ps max; typ from 0.906 V to 0.702 V
[Pulldown]
|Voltage   I(typ)   I(min)   I(max)
-3.3V     -3.224A    -2.966A    -3.553A
-1.2V     -468.8mA   -521.5mA   -422.7mA
-1.05V    -274.8mA   -348.9mA   -203mA
-900mV    -90.11mA   -176.4mA   -63.78mA
-750mV    -30mA      -40.53mA   -37.99mA
-600mV    -16.77mA   -14.07mA   -21.5mA
0V        -41.41uA   -36.05uA   -50.75uA
4.5V      49.76mA    51.55mA    49.02mA
5.1V      116.8mA    110.4mA    121.1mA
5.7V      200.3mA    183.7mA    216.5mA
6V        246.3mA    225.5mA    267.9mA
6.6V      349.9mA    317mA      380.1mA
[Pullup]
|Voltage   I(typ)   I(min)   I(max)
-3.3V     376.6mA    318.2mA    437.8mA
-1.65V    109.6mA    89.72mA    134.1mA
-600mV    10.25mA    8.851mA    13.37mA
3.75V     -2.332mA   -5.666mA   -2.147mA
3.9V      -5.526mA   -32.22mA   -2.402mA
4.05V     -16.34mA   -172.7mA   -6.332mA
4.2V      -81.69mA   -345mA     -19.79mA
4.35V     -269.6mA   -517.3mA   -44.64mA
4.5V      -463.3mA   -689.6mA   -196.4mA
4.65V     -657.3mA   -862mA     -415.7mA
4.8V      -851.4mA   -1.035A    -635.1mA
6.6V      -3.215A    -3.135A    -3.316A
[Ramp]
| variable   typ   min   max
dV/dt_r 0.1480/0.2178e-9   0.1435/0.2178e-9   0.1563/0.2142e-9
dV/dt_f 0.1254/0.4443e-9   0.1256/0.4425e-9   0.1274/0.4571e-9
R_load = 50
[Rising waveform]
R_fixture= 50
V_fixture= 0.802543
V_fixture_min= 0.765098
V_fixture_max= 0.846243
|Time   V(typ)   V(min)   V(max)
0s        701.8mV    663.8mV    743.2mV
1.1ns     701.7mV    663.8mV    749.1mV
1.24ns    705.5mV    663.8mV    690.4mV
1.45ns    661.3mV    665.9mV    870.8mV
1.62ns    806.9mV    646.2mV    922.1mV
1.7ns     848.2mV    630mV      929.5mV
1.93ns    888.5mV    791.3mV    942.8mV
2.11ns    897.3mV    848.5mV    945.6mV
2.32ns    904.1mV    866.9mV    948.4mV
4ns       905.7mV    867.4mV    950.2mV
[Falling waveform]
R_fixture= 50
V_fixture= 0.802543
V_fixture_min= 0.765098
V_fixture_max= 0.846243
|Time   V(typ)   V(min)   V(max)
0s        905.6mV    867.8mV    950.1mV
1.18ns    905.5mV    867.8mV    953.1mV
1.27ns    910.6mV    867.8mV    879.8mV
1.38ns    898.8mV    867.6mV    850.3mV
1.54ns    807.3mV    872.3mV    810.7mV
1.65ns    782.6mV    849.6mV    791.3mV
1.82ns    750.1mV    759.3mV    769.4mV
2.2ns     715.6mV    698.2mV    748.8mV
3ns       702.9mV    665.1mV    743.1mV
4ns       702.1mV    663.9mV    743.2mV
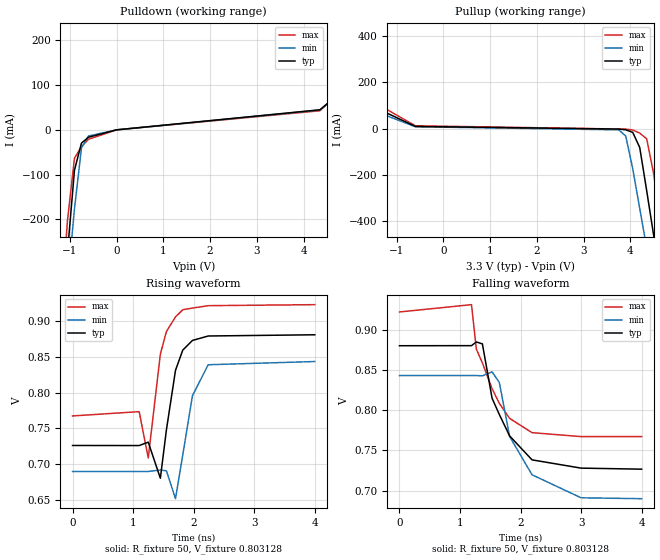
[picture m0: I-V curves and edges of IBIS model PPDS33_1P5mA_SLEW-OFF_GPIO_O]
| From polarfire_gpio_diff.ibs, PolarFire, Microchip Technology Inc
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|   Model PPDS33_1P5mA_SLEW-OFF_GPIO_O
[Model]   PPDS33_1P5mA_SLEW-OFF_GPIO_O
Model_type   Output
Polarity   Non-Inverting
Enable   Active-High
Vmeas =   0.8
Cref =   5p
Rref =   100
|   typ   min   max
C_comp_pullup   2.605e-12   2.605e-12   2.76e-12
C_comp_pulldown  2.605e-12   2.605e-12   2.76e-12
[Temperature Range]  25C   100C   -40C
[Voltage Range]  3.3   3.15   3.45
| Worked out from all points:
|   slope of the pulldown table from 0 to 0.495 V, typ, clamps not added: 340 ohm
|   slope of the pullup table from 0 to 0.495 V, typ, clamps not added: 335 ohm
|   rising waveform, R_fixture 50, V_fixture 0.803128: 20-80 % time 212ps typ, 214ps min, 214ps max; typ from 0.726 V to 0.881 V
|   falling waveform, R_fixture 50, V_fixture 0.803128: 20-80 % time 472ps typ, 476ps min, 484ps max; typ from 0.881 V to 0.727 V
[Pulldown]
|Voltage   I(typ)   I(min)   I(max)
-3.3V     -3.224A    -2.966A    -3.553A
-1.2V     -468.6mA   -521.4mA   -422.6mA
-1.05V    -274.6mA   -348.8mA   -202.9mA
-900mV    -89.88mA   -176.3mA   -63.35mA
-750mV    -29.68mA   -40.29mA   -37.57mA
-600mV    -16.48mA   -13.82mA   -21.1mA
0V        -40.3uA    -35.06uA   -49.34uA
4.35V     44.77mA    44.21mA    42.63mA
4.95V     97.4mA     93.78mA    99.71mA
5.85V     222.3mA    203.6mA    241.3mA
6V        245.7mA    224.9mA    267.3mA
6.6V      349.2mA    316.3mA    379.4mA
[Pullup]
|Voltage   I(typ)   I(min)   I(max)
-3.3V     376.5mA    318.1mA    437.6mA
-1.65V    109.1mA    89.55mA    133.5mA
-600mV    9.45mA     8.229mA    12.37mA
3.75V     -1.821mA   -5.164mA   -1.631mA
3.9V      -5.021mA   -31.74mA   -1.888mA
4.05V     -15.84mA   -172.3mA   -5.824mA
4.2V      -81.25mA   -344.5mA   -19.29mA
4.35V     -269.2mA   -516.9mA   -44.14mA
4.5V      -462.9mA   -689.1mA   -196mA
4.65V     -656.8mA   -861.6mA   -415.3mA
4.8V      -851mA     -1.034A    -634.6mA
6.6V      -3.215A    -3.135A    -3.316A
[Ramp]
| variable   typ   min   max
dV/dt_r 0.1210/0.2130e-9   0.1163/0.6073e-9   0.1287/0.2176e-9
dV/dt_f 95.4105e-3/0.4683e-9   95.0968e-3/0.4687e-9   99.1524e-3/0.4785e-9
R_load = 50
[Rising waveform]
R_fixture= 50
V_fixture= 0.803128
V_fixture_min= 0.766108
V_fixture_max= 0.844613
|Time   V(typ)   V(min)   V(max)
0s        726.2mV    689.9mV    767.4mV
1.1ns     726.1mV    689.9mV    773.4mV
1.25ns    730.8mV    689.9mV    708.8mV
1.45ns    680.5mV    692mV      853.7mV
1.55ns    748mV      690.8mV    885.1mV
1.7ns     831mV      652mV      905.5mV
1.82ns    859.2mV    713mV      915.5mV
1.98ns    872.7mV    795.6mV    917.8mV
2.24ns    878.9mV    838.8mV    921.2mV
4ns       880.6mV    843.3mV    922.6mV
[Falling waveform]
R_fixture= 50
V_fixture= 0.803128
V_fixture_min= 0.766108
V_fixture_max= 0.844613
|Time   V(typ)   V(min)   V(max)
0s        880.6mV    843.4mV    922.7mV
1.19ns    880.7mV    843.4mV    931.8mV
1.27ns    885.3mV    843.4mV    876.4mV
1.37ns    882.9mV    843.1mV    859.2mV
1.53ns    815.1mV    848mV      827mV
1.65ns    794.8mV    834.7mV    808.7mV
1.82ns    768.1mV    767.4mV    790mV
2.19ns    738.3mV    719.7mV    772.2mV
3ns       728mV      691mV      767.3mV
4ns       726.7mV    689.9mV    767.3mV
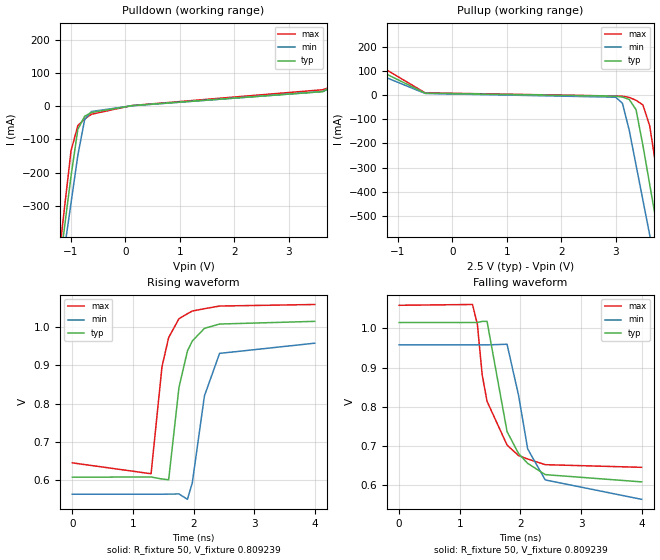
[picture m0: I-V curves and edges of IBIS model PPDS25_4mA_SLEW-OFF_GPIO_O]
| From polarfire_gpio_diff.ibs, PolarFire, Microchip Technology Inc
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|   Model PPDS25_4mA_SLEW-OFF_GPIO_O
[Model]   PPDS25_4mA_SLEW-OFF_GPIO_O
Model_type   Output
Polarity   Non-Inverting
Enable   Active-High
Vmeas =   0.8
Cref =   5p
Rref =   100
|   typ   min   max
C_comp_pullup   2.605e-12   2.605e-12   2.76e-12
C_comp_pulldown  2.605e-12   2.605e-12   2.76e-12
[Temperature Range]  25C   100C   -40C
[Voltage Range]  2.5   2.375   2.625
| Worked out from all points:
|   slope of the pulldown table from 0 to 0.375 V, typ, clamps not added: 101 ohm
|   slope of the pullup table from 0 to 0.375 V, typ, clamps not added: 129 ohm
|   rising waveform, R_fixture 50, V_fixture 0.809239: 20-80 % time 236ps typ, 250ps min, 221ps max; typ from 0.608 V to 1.01 V
|   falling waveform, R_fixture 50, V_fixture 0.809239: 20-80 % time 347ps typ, 342ps min, 351ps max; typ from 1.01 V to 0.609 V
[Pulldown]
|Voltage   I(typ)   I(min)   I(max)
-2.5V     -2.163A    -2.027A    -2.344A
-1.25V    -533.5mA   -579mA     -496.1mA
-1.125V   -371.8mA   -435.2mA   -313mA
-1V       -210.3mA   -291.4mA   -134.2mA
-875mV    -69.77mA   -147.8mA   -58.57mA
-750mV    -30.28mA   -40.61mA   -38.53mA
-625mV    -18.77mA   -15.91mA   -24.2mA
125mV     1.765mA    1.416mA    2.207mA
3.625V    44.16mA    44.14mA    49.78mA
3.75V     55.47mA    53.99mA    56.38mA
4.25V     110.3mA    101.7mA    117.9mA
5V        214.3mA    192.3mA    237mA
[Pullup]
|Voltage   I(typ)   I(min)   I(max)
-2.5V     229.6mA    189.4mA    276.2mA
-500mV    7.419mA    6.385mA    8.962mA
3V        -4.839mA   -9.033mA   -4.258mA
3.125V    -8.74mA    -34.12mA   -5.039mA
3.25V     -18.34mA   -145.8mA   -9.875mA
3.375V    -60.89mA   -289.3mA   -21.8mA
3.5V      -206.8mA   -432.9mA   -40.73mA
3.625V    -368.2mA   -576.5mA   -126.4mA
3.75V     -529.7mA   -720.1mA   -307.8mA
3.875V    -691.4mA   -863.8mA   -490.6mA
4V        -853.2mA   -1.008A    -673.4mA
5V        -2.158A    -2.169A    -2.15A
[Ramp]
| variable   typ   min   max
dV/dt_r 0.2559/0.2374e-9   0.2446/0.2521e-9   0.2655/0.2196e-9
dV/dt_f 0.2474/0.3463e-9   0.2404/0.3434e-9   0.2510/0.3510e-9
R_load = 50
[Rising waveform]
R_fixture= 50
V_fixture= 0.809239
V_fixture_min= 0.755346
V_fixture_max= 0.851368
|Time   V(typ)   V(min)   V(max)
0s        608.3mV    563.8mV    645.7mV
1.3ns     608.8mV    563.8mV    617.3mV
1.48ns    603.6mV    563.8mV    896.7mV
1.59ns    601.5mV    564.2mV    972.8mV
1.76ns    842.6mV    564.5mV    1.022V
1.9ns     937.7mV    550.5mV    1.035V
1.98ns    963.7mV    593.7mV    1.042V
2.18ns    996.7mV    820.4mV    1.048V
2.43ns    1.008V     931.4mV    1.055V
4ns       1.015V     958mV      1.059V
[Falling waveform]
R_fixture= 50
V_fixture= 0.809239
V_fixture_min= 0.755346
V_fixture_max= 0.851368
|Time   V(typ)   V(min)   V(max)
0s        1.015V     958.1mV    1.059V
1.21ns    1.015V     958.1mV    1.061V
1.29ns    1.015V     958.1mV    1.011V
1.37ns    1.018V     958.1mV    881.4mV
1.45ns    1.018V     958mV      814.1mV
1.78ns    736.9mV    959.6mV    702.5mV
1.97ns    680.8mV    829.2mV    675.6mV
2.12ns    655.8mV    692.7mV    666.9mV
2.41ns    627.1mV    613.6mV    652.5mV
4ns       608.6mV    564.1mV    645.7mV
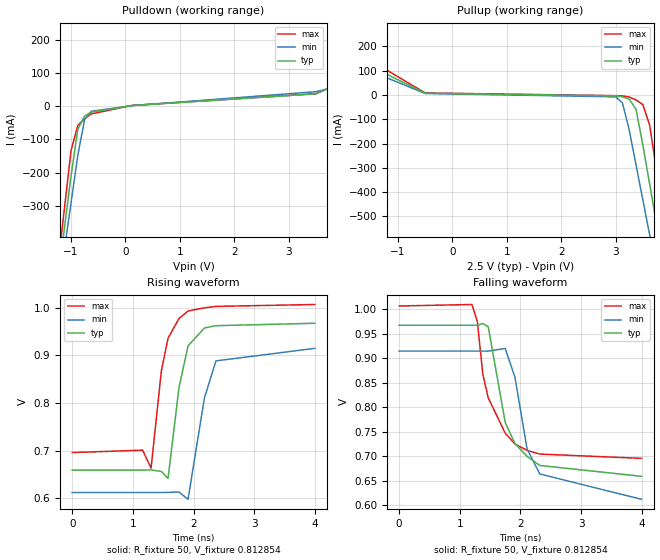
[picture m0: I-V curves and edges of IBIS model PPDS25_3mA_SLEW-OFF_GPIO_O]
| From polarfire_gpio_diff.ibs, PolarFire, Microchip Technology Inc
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|   Model PPDS25_3mA_SLEW-OFF_GPIO_O
[Model]   PPDS25_3mA_SLEW-OFF_GPIO_O
Model_type   Output
Polarity   Non-Inverting
Enable   Active-High
Vmeas =   0.8
Cref =   5p
Rref =   100
|   typ   min   max
C_comp_pullup   2.605e-12   2.605e-12   2.76e-12
C_comp_pulldown  2.605e-12   2.605e-12   2.76e-12
[Temperature Range]  25C   100C   -40C
[Voltage Range]  2.5   2.375   2.625
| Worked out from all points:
|   slope of the pulldown table from 0 to 0.375 V, typ, clamps not added: 131 ohm
|   slope of the pullup table from 0 to 0.375 V, typ, clamps not added: 158 ohm
|   rising waveform, R_fixture 50, V_fixture 0.812854: 20-80 % time 211ps typ, 238ps min, 215ps max; typ from 0.659 V to 0.968 V
|   falling waveform, R_fixture 50, V_fixture 0.812854: 20-80 % time 367ps typ, 349ps min, 377ps max; typ from 0.968 V to 0.659 V
[Pulldown]
|Voltage   I(typ)   I(min)   I(max)
-2.5V     -2.163A    -2.027A    -2.344A
-1.25V    -533.3mA   -578.8mA   -495.9mA
-1.125V   -371.6mA   -435.1mA   -312.8mA
-1V       -210.1mA   -291.2mA   -133.8mA
-875mV    -69.4mA    -147.6mA   -57.98mA
-750mV    -29.85mA   -40.32mA   -37.96mA
-625mV    -18.36mA   -15.6mA    -23.66mA
125mV     1.531mA    1.248mA    1.862mA
3.5V      36.82mA    43.19mA    37.16mA
3.75V     54.47mA    53.05mA    55.32mA
4.125V    94.08mA    87.77mA    99.91mA
5V        213.2mA    191.3mA    235.9mA
[Pullup]
|Voltage   I(typ)   I(min)   I(max)
-2.5V     229.1mA    189.2mA    275mA
-500mV    6.786mA    5.896mA    8.164mA
3V        -3.815mA   -8.05mA    -3.219mA
3.125V    -7.728mA   -33.18mA   -4.005mA
3.25V     -17.34mA   -144.9mA   -8.856mA
3.375V    -59.97mA   -288.4mA   -20.79mA
3.5V      -206mA     -432mA     -39.72mA
3.625V    -367.3mA   -575.6mA   -125.5mA
3.75V     -528.8mA   -719.2mA   -306.9mA
3.875V    -690.5mA   -862.9mA   -489.7mA
4V        -852.3mA   -1.007A    -672.6mA
5V        -2.157A    -2.168A    -2.149A
[Ramp]
| variable   typ   min   max
dV/dt_r 0.1979/0.2167e-9   0.1915/0.2445e-9   0.2063/0.2160e-9
dV/dt_f 0.1882/0.3635e-9   0.1851/0.3501e-9   0.1894/0.3752e-9
R_load = 50
[Rising waveform]
R_fixture= 50
V_fixture= 0.812854
V_fixture_min= 0.761145
V_fixture_max= 0.851022
|Time   V(typ)   V(min)   V(max)
0s        659.3mV    612.2mV    696.1mV
1.16ns    659.2mV    612.2mV    701.1mV
1.3ns     659.7mV    612.3mV    663.5mV
1.47ns    656.5mV    612.2mV    868.2mV
1.58ns    641.6mV    612.5mV    936.3mV
1.76ns    832.4mV    613.2mV    977.4mV
1.91ns    920.1mV    597.9mV    993.3mV
2.18ns    957.7mV    810.8mV    1V
2.37ns    962.5mV    888.6mV    1.003V
4ns       967.6mV    914.9mV    1.007V
[Falling waveform]
R_fixture= 50
V_fixture= 0.812854
V_fixture_min= 0.761145
V_fixture_max= 0.851022
|Time   V(typ)   V(min)   V(max)
0s        967.6mV    915mV      1.007V
1.2ns     967.6mV    915mV      1.01V
1.29ns    967.5mV    915mV      975.5mV
1.38ns    971.2mV    915mV      867.8mV
1.47ns    964.6mV    914.9mV    819.4mV
1.75ns    769.1mV    920.4mV    747.4mV
1.91ns    726.5mV    861.7mV    725.4mV
2.11ns    700.1mV    715.5mV    712.4mV
2.32ns    681.6mV    664.2mV    704.8mV
4ns       659.4mV    612.5mV    696.1mV
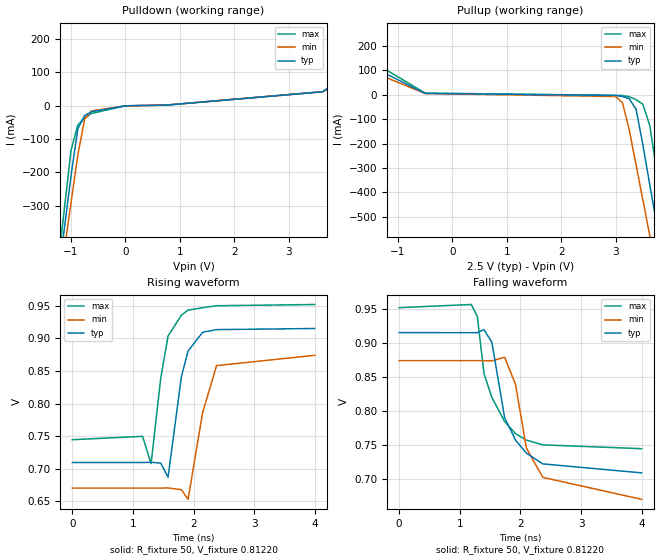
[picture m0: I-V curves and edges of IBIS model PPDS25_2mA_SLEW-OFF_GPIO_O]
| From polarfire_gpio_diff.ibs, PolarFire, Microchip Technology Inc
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|   Model PPDS25_2mA_SLEW-OFF_GPIO_O
[Model]   PPDS25_2mA_SLEW-OFF_GPIO_O
Model_type   Output
Polarity   Non-Inverting
Enable   Active-High
Vmeas =   0.8
Cref =   5p
Rref =   100
|   typ   min   max
C_comp_pullup   2.605e-12   2.605e-12   2.76e-12
C_comp_pulldown  2.605e-12   2.605e-12   2.76e-12
[Temperature Range]  25C   100C   -40C
[Voltage Range]  2.5   2.375   2.625
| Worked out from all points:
|   slope of the pulldown table from 0 to 0.375 V, typ, clamps not added: 198 ohm
|   slope of the pullup table from 0 to 0.375 V, typ, clamps not added: 218 ohm
|   rising waveform, R_fixture 50, V_fixture 0.81220: 20-80 % time 200ps typ, 232ps min, 207ps max; typ from 0.71 V to 0.915 V
|   falling waveform, R_fixture 50, V_fixture 0.81220: 20-80 % time 377ps typ, 358ps min, 398ps max; typ from 0.915 V to 0.709 V
[Pulldown]
|Voltage   I(typ)   I(min)   I(max)
-2.5V     -2.163A    -2.026A    -2.344A
-1.25V    -533.1mA   -578.6mA   -495.6mA
-1.125V   -371.4mA   -434.9mA   -312.5mA
-1V       -209.9mA   -291.1mA   -133.4mA
-875mV    -68.95mA   -147.4mA   -57.28mA
-750mV    -29.32mA   -39.95mA   -37.28mA
-625mV    -17.86mA   -15.22mA   -23.02mA
0V        -41.32uA   -35.57uA   -50.46uA
750mV     2.077mA    2.256mA    2.061mA
3.625V    42.1mA     42.17mA    42.64mA
4.25V     108.2mA    99.7mA     115.8mA
5V        212mA      190.1mA    234.7mA
[Pullup]
|Voltage   I(typ)   I(min)   I(max)
-2.5V     228.8mA    189mA      273.9mA
-500mV    5.874mA    5.189mA    7.02mA
3V        -2.783mA   -7.044mA   -2.172mA
3.125V    -6.708mA   -32.22mA   -2.963mA
3.25V     -16.34mA   -144.1mA   -7.828mA
3.375V    -59.03mA   -287.5mA   -19.78mA
3.5V      -205.1mA   -431.2mA   -38.7mA
3.625V    -366.4mA   -574.7mA   -124.6mA
3.75V     -528mA     -718.3mA   -306.1mA
3.875V    -689.6mA   -862mA     -488.9mA
4V        -851.4mA   -1.006A    -671.7mA
5V        -2.156A    -2.167A    -2.148A
[Ramp]
| variable   typ   min   max
dV/dt_r 0.1380/0.2087e-9   0.1347/0.2500e-9   0.1467/0.2023e-9
dV/dt_f 0.1266/0.3750e-9   0.1250/0.3590e-9   0.1269/0.3919e-9
R_load = 50
[Rising waveform]
R_fixture= 50
V_fixture= 0.81220
V_fixture_min= 0.771210
V_fixture_max= 0.848018
|Time   V(typ)   V(min)   V(max)
0s        709.7mV    670.5mV    744.7mV
1.16ns    709.7mV    670.5mV    749.9mV
1.3ns     710.2mV    670.5mV    708mV
1.46ns    708.7mV    670.5mV    839.5mV
1.58ns    687.2mV    670.8mV    903.7mV
1.8ns     841.3mV    668mV      935.6mV
1.91ns    880.6mV    653.3mV    943.4mV
2.15ns    909.4mV    785.9mV    947.1mV
2.38ns    913.5mV    858.3mV    950.1mV
4ns       915.2mV    874.1mV    952mV
[Falling waveform]
R_fixture= 50
V_fixture= 0.81220
V_fixture_min= 0.771210
V_fixture_max= 0.848018
|Time   V(typ)   V(min)   V(max)
0s        915.3mV    874.1mV    951.9mV
1.19ns    915.2mV    874.1mV    956.5mV
1.29ns    915.2mV    874.1mV    938.9mV
1.4ns     919.7mV    874.1mV    855mV
1.53ns    900.9mV    873.9mV    820.1mV
1.74ns    790.6mV    879.1mV    784.9mV
1.92ns    757.5mV    839.1mV    767mV
2.1ns     738.4mV    745.7mV    757.6mV
2.37ns    722.7mV    702.9mV    750.6mV
4ns       709.5mV    670.7mV    745mV
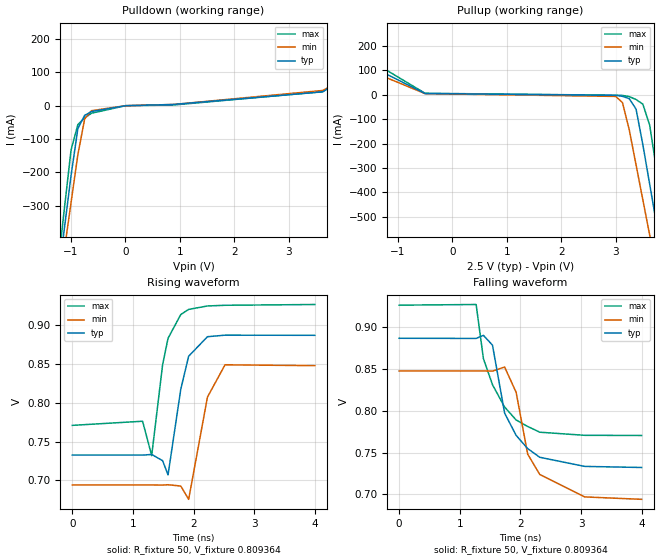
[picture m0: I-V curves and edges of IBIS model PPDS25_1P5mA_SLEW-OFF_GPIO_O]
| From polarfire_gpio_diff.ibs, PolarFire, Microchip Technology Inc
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|   Model PPDS25_1P5mA_SLEW-OFF_GPIO_O
[Model]   PPDS25_1P5mA_SLEW-OFF_GPIO_O
Model_type   Output
Polarity   Non-Inverting
Enable   Active-High
Vmeas =   0.8
Cref =   5p
Rref =   100
|   typ   min   max
C_comp_pullup   2.605e-12   2.605e-12   2.76e-12
C_comp_pulldown  2.605e-12   2.605e-12   2.76e-12
[Temperature Range]  25C   100C   -40C
[Voltage Range]  2.5   2.375   2.625
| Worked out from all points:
|   slope of the pulldown table from 0 to 0.375 V, typ, clamps not added: 267 ohm
|   slope of the pullup table from 0 to 0.375 V, typ, clamps not added: 279 ohm
|   rising waveform, R_fixture 50, V_fixture 0.809364: 20-80 % time 207ps typ, 217ps min, 204ps max; typ from 0.732 V to 0.887 V
|   falling waveform, R_fixture 50, V_fixture 0.809364: 20-80 % time 400ps typ, 365ps min, 432ps max; typ from 0.887 V to 0.732 V
[Pulldown]
|Voltage   I(typ)   I(min)   I(max)
-2.5V     -2.163A    -2.026A    -2.344A
-1.25V    -533mA     -578.5mA   -495.5mA
-1.125V   -371.3mA   -434.8mA   -312.4mA
-1V       -209.7mA   -290.9mA   -133.1mA
-875mV    -68.68mA   -147.3mA   -56.86mA
-750mV    -29mA      -39.74mA   -36.88mA
-625mV    -17.57mA   -14.99mA   -22.64mA
0V        -40.08uA   -34.54uA   -49.17uA
875mV     3.612mA    3.618mA    2.01mA
3.625V    41.55mA    45.66mA    42.09mA
4.25V     107.6mA    99.17mA    115.2mA
5V        211.4mA    189.5mA    234mA
[Pullup]
|Voltage   I(typ)   I(min)   I(max)
-2.5V     228.7mA    189mA      273.6mA
-500mV    5.245mA    4.701mA    6.233mA
3V        -2.274mA   -6.542mA   -1.657mA
3.125V    -6.204mA   -31.74mA   -2.451mA
3.25V     -15.84mA   -143.6mA   -7.323mA
3.375V    -58.57mA   -287.1mA   -19.29mA
3.5V      -204.6mA   -430.7mA   -38.2mA
3.625V    -366mA     -574.3mA   -124.2mA
3.75V     -527.5mA   -717.9mA   -305.6mA
3.875V    -689.2mA   -861.6mA   -488.4mA
4V        -851mA     -1.005A    -671.2mA
5V        -2.155A    -2.167A    -2.147A
[Ramp]
| variable   typ   min   max
dV/dt_r 0.1083/0.2206e-9   0.1059/0.2426e-9   0.1173/0.2132e-9
dV/dt_f 95.6821e-3/0.3939e-9   94.9832e-3/0.3654e-9   96.3375e-3/0.4289e-9
R_load = 50
[Rising waveform]
R_fixture= 50
V_fixture= 0.809364
V_fixture_min= 0.770384
V_fixture_max= 0.848355
|Time   V(typ)   V(min)   V(max)
0s        732.5mV    694mV      770.8mV
1.16ns    732.5mV    694mV      776.1mV
1.31ns    733.3mV    694mV      731.8mV
1.49ns    725.3mV    693.9mV    848.8mV
1.58ns    707mV      694.3mV    883mV
1.79ns    817.4mV    692.6mV    913.6mV
1.92ns    859.9mV    675.5mV    920.2mV
2.23ns    885mV      807.2mV    924.6mV
2.52ns    887mV      848.8mV    925.5mV
4ns       886.8mV    847.7mV    926.5mV
[Falling waveform]
R_fixture= 50
V_fixture= 0.809364
V_fixture_min= 0.770384
V_fixture_max= 0.848355
|Time   V(typ)   V(min)   V(max)
0s        886.9mV    847.8mV    926.5mV
1.27ns    886.7mV    847.8mV    927.3mV
1.39ns    890.4mV    847.8mV    862.5mV
1.54ns    878.6mV    847.6mV    831.3mV
1.74ns    797.3mV    852.5mV    804.6mV
1.93ns    770.7mV    822.2mV    789.1mV
2.12ns    754.9mV    748.3mV    781.4mV
2.32ns    744.5mV    723.9mV    774.5mV
3.06ns    733.6mV    697.1mV    770.8mV
4ns       732.3mV    694.2mV    770.6mV
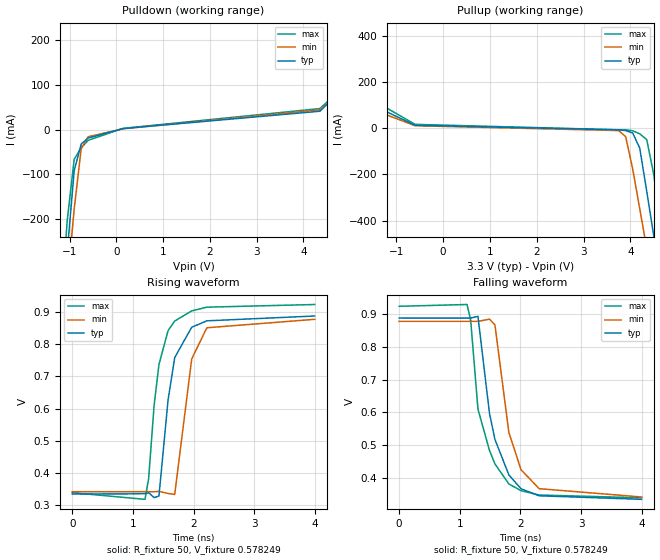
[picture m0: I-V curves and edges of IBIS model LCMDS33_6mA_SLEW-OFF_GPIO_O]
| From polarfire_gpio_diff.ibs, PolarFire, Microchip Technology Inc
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|   Model LCMDS33_6mA_SLEW-OFF_GPIO_O
[Model]   LCMDS33_6mA_SLEW-OFF_GPIO_O
Model_type   Output
Polarity   Non-Inverting
Enable   Active-High
Vmeas =   0.6
Cref =   5p
Rref =   100
|   typ   min   max
C_comp_pullup   2.605e-12   2.605e-12   2.76e-12
C_comp_pulldown  2.605e-12   2.605e-12   2.76e-12
[Temperature Range]  25C   100C   -40C
[Voltage Range]  3.3   3.15   3.45
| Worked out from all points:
|   slope of the pulldown table from 0 to 0.495 V, typ, clamps not added: 77.7 ohm
|   slope of the pullup table from 0 to 0.495 V, typ, clamps not added: 102 ohm
|   rising waveform, R_fixture 50, V_fixture 0.578249: 20-80 % time 220ps typ, 224ps min, 228ps max; typ from 0.334 V to 0.888 V
|   falling waveform, R_fixture 50, V_fixture 0.578249: 20-80 % time 313ps typ, 293ps min, 336ps max; typ from 0.888 V to 0.334 V
[Pulldown]
|Voltage   I(typ)   I(min)   I(max)
-3.3V     -3.224A    -2.967A    -3.554A
-1.2V     -469.5mA   -522.2mA   -423.5mA
-1.05V    -275.5mA   -349.6mA   -203.9mA
-900mV    -91.41mA   -177.2mA   -66.06mA
-750mV    -31.78mA   -42.01mA   -40.2mA
-600mV    -18.42mA   -15.59mA   -23.55mA
150mV     2.619mA    2.249mA    3.241mA
4.35V     41.35mA    44.55mA    47.3mA
4.95V     101.9mA    99.12mA    104.3mA
5.7V      204.6mA    188.8mA    220.8mA
6V        250.9mA    230.9mA    272.4mA
6.6V      355mA      322.9mA    385.2mA
[Pullup]
|Voltage   I(typ)   I(min)   I(max)
-3.3V     378.7mA    319.5mA    441mA
-1.65V    114.2mA    92.55mA    139.9mA
-600mV    13.42mA    11.4mA     17.37mA
3.75V     -6.446mA   -9.704mA   -6.31mA
3.9V      -9.578mA   -36.05mA   -6.551mA
4.05V     -20.33mA   -176.2mA   -10.4mA
4.2V      -85.27mA   -348.5mA   -23.79mA
4.35V     -273.1mA   -520.8mA   -48.61mA
4.5V      -466.8mA   -693.1mA   -199.8mA
4.65V     -660.7mA   -865.5mA   -419.1mA
4.8V      -854.9mA   -1.038A    -638.4mA
6.6V      -3.219A    -3.139A    -3.32A
[Ramp]
| variable   typ   min   max
dV/dt_r 0.3445/0.2211e-9   0.3327/0.2257e-9   0.3648/0.2268e-9
dV/dt_f 0.3369/0.3114e-9   0.3266/0.2924e-9   0.3554/0.3342e-9
R_load = 50
[Rising waveform]
R_fixture= 50
V_fixture= 0.578249
V_fixture_min= 0.569220
V_fixture_max= 0.611558
|Time   V(typ)   V(min)   V(max)
0s        333.9mV    341.2mV    338.1mV
1.2ns     334.8mV    341.2mV    317.5mV
1.26ns    338mV      341.2mV    382.6mV
1.35ns    322.8mV    341.1mV    609.8mV
1.43ns    327.9mV    342.2mV    737.1mV
1.58ns    626.4mV    335.7mV    842.3mV
1.69ns    758.7mV    332.7mV    872.3mV
1.97ns    852.9mV    754.1mV    903.8mV
2.22ns    872.9mV    851.3mV    915.4mV
4ns       887.9mV    877.6mV    923.7mV
[Falling waveform]
R_fixture= 50
V_fixture= 0.578249
V_fixture_min= 0.569220
V_fixture_max= 0.611558
|Time   V(typ)   V(min)   V(max)
0s        887.6mV    877.6mV    923.5mV
1.12ns    887.4mV    877.6mV    929mV
1.18ns    887.8mV    877.6mV    881.1mV
1.3ns     892.8mV    877.5mV    609.6mV
1.49ns    597mV      884.3mV    483.6mV
1.58ns    517.1mV    866.8mV    442.4mV
1.81ns    408.7mV    538.2mV    381.2mV
2.01ns    366.5mV    424.7mV    360.7mV
2.31ns    345mV      366.7mV    347.4mV
4ns       334.2mV    341.3mV    338.8mV
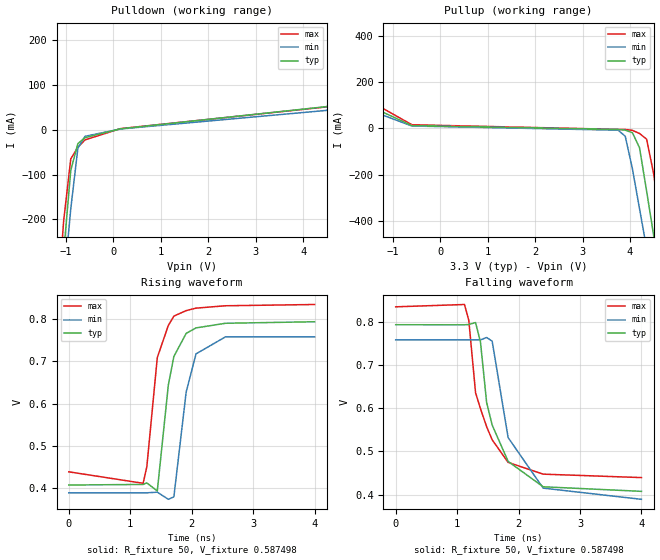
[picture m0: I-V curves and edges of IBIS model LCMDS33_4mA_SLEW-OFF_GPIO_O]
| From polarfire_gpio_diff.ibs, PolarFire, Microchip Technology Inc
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|   Model LCMDS33_4mA_SLEW-OFF_GPIO_O
[Model]   LCMDS33_4mA_SLEW-OFF_GPIO_O
Model_type   Output
Polarity   Non-Inverting
Enable   Active-High
Vmeas =   0.6
Cref =   5p
Rref =   100
|   typ   min   max
C_comp_pullup   2.605e-12   2.605e-12   2.76e-12
C_comp_pulldown  2.605e-12   2.605e-12   2.76e-12
[Temperature Range]  25C   100C   -40C
[Voltage Range]  3.3   3.15   3.45
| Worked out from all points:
|   slope of the pulldown table from 0 to 0.495 V, typ, clamps not added: 114 ohm
|   slope of the pullup table from 0 to 0.495 V, typ, clamps not added: 138 ohm
|   rising waveform, R_fixture 50, V_fixture 0.587498: 20-80 % time 208ps typ, 205ps min, 211ps max; typ from 0.407 V to 0.794 V
|   falling waveform, R_fixture 50, V_fixture 0.587498: 20-80 % time 388ps typ, 382ps min, 387ps max; typ from 0.794 V to 0.407 V
[Pulldown]
|Voltage   I(typ)   I(min)   I(max)
-3.3V     -3.224A    -2.966A    -3.554A
-1.2V     -469.1mA   -521.8mA   -423.1mA
-1.05V    -275.1mA   -349.2mA   -203.5mA
-900mV    -90.76mA   -176.7mA   -64.99mA
-750mV    -30.91mA   -41.11mA   -39.17mA
-600mV    -17.61mA   -14.68mA   -22.6mA
150mV     2.094mA    1.707mA    2.54mA
4.5V      51.62mA    43.2mA     50.97mA
5.1V      118.7mA    112.1mA    123mA
5.7V      202.3mA    185.5mA    218.6mA
6V        248.5mA    227.5mA    270.1mA
6.6V      352.4mA    319.2mA    382.6mA
[Pullup]
|Voltage   I(typ)   I(min)   I(max)
-3.3V     377.9mA    319mA      439.4mA
-1.65V    112mA      90.98mA    137.2mA
-600mV    12.31mA    10.5mA     15.97mA
3.75V     -4.383mA   -7.667mA   -4.224mA
3.9V      -7.534mA   -34.11mA   -4.47mA
4.05V     -18.3mA    -174.5mA   -8.349mA
4.2V      -83.46mA   -346.7mA   -21.75mA
4.35V     -271.3mA   -519.1mA   -46.6mA
4.5V      -465mA     -691.3mA   -198.1mA
4.65V     -659mA     -863.8mA   -417.3mA
4.8V      -853.2mA   -1.036A    -636.6mA
6.6V      -3.217A    -3.137A    -3.318A
[Ramp]
| variable   typ   min   max
dV/dt_r 0.2467/0.2099e-9   0.2350/0.2103e-9   0.2550/0.2130e-9
dV/dt_f 0.2364/0.3859e-9   0.2264/0.3804e-9   0.2419/0.3841e-9
R_load = 50
[Rising waveform]
R_fixture= 50
V_fixture= 0.587498
V_fixture_min= 0.553047
V_fixture_max= 0.627253
|Time   V(typ)   V(min)   V(max)
0s        406.9mV    388.5mV    438.2mV
1.21ns    408.3mV    388.5mV    411mV
1.27ns    411.9mV    388.4mV    450.7mV
1.44ns    392.8mV    390mV      709.1mV
1.62ns    644.3mV    373mV      785.4mV
1.71ns    711.7mV    379mV      807.4mV
1.91ns    766.4mV    627.4mV    820.4mV
2.07ns    779.4mV    717.8mV    826.3mV
2.55ns    790.4mV    758.2mV    831.9mV
4ns       794mV      758.1mV    834.9mV
[Falling waveform]
R_fixture= 50
V_fixture= 0.587498
V_fixture_min= 0.553047
V_fixture_max= 0.627253
|Time   V(typ)   V(min)   V(max)
0s        793.7mV    758.7mV    835.2mV
1.12ns    793.5mV    758.7mV    840.6mV
1.19ns    794.2mV    758.7mV    803.7mV
1.3ns     798.8mV    758.6mV    635.9mV
1.38ns    753.3mV    758.5mV    598.9mV
1.48ns    613.4mV    764.1mV    557.3mV
1.57ns    561.1mV    755.6mV    526.9mV
1.83ns    476.7mV    532mV      474.5mV
2.4ns     417.9mV    414.8mV    447.2mV
4ns       407.3mV    388.8mV    439.2mV
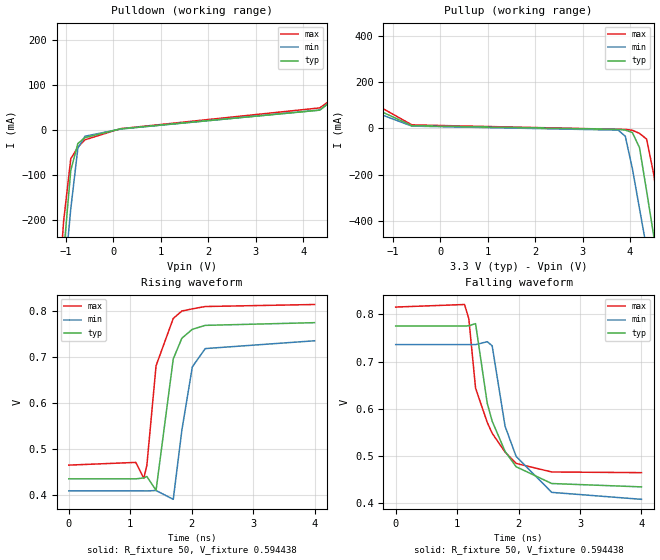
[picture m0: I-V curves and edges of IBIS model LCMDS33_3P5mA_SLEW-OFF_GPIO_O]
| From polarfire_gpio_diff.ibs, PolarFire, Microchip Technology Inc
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|   Model LCMDS33_3P5mA_SLEW-OFF_GPIO_O
[Model]   LCMDS33_3P5mA_SLEW-OFF_GPIO_O
Model_type   Output
Polarity   Non-Inverting
Enable   Active-High
Vmeas =   0.6
Cref =   5p
Rref =   100
|   typ   min   max
C_comp_pullup   2.605e-12   2.605e-12   2.76e-12
C_comp_pulldown  2.605e-12   2.605e-12   2.76e-12
[Temperature Range]  25C   100C   -40C
[Voltage Range]  3.3   3.15   3.45
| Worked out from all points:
|   slope of the pulldown table from 0 to 0.495 V, typ, clamps not added: 127 ohm
|   slope of the pullup table from 0 to 0.495 V, typ, clamps not added: 154 ohm
|   rising waveform, R_fixture 50, V_fixture 0.594438: 20-80 % time 204ps typ, 204ps min, 213ps max; typ from 0.435 V to 0.775 V
|   falling waveform, R_fixture 50, V_fixture 0.594438: 20-80 % time 404ps typ, 403ps min, 402ps max; typ from 0.775 V to 0.435 V
[Pulldown]
|Voltage   I(typ)   I(min)   I(max)
-3.3V     -3.224A    -2.966A    -3.554A
-1.2V     -469mA     -521.7mA   -423mA
-1.05V    -275mA     -349.1mA   -203.4mA
-900mV    -90.59mA   -176.6mA   -64.72mA
-750mV    -30.68mA   -40.95mA   -38.91mA
-600mV    -17.41mA   -14.51mA   -22.36mA
150mV     1.938mA    1.584mA    2.347mA
4.35V     43.65mA    43.91mA    48.68mA
4.8V      81.78mA    80.14mA    82.52mA
5.7V      201.8mA    185mA      218.2mA
6V        247.9mA    227mA      269.6mA
6.6V      351.8mA    318.6mA    382.1mA
[Pullup]
|Voltage   I(typ)   I(min)   I(max)
-3.3V     377.7mA    318.9mA    439.2mA
-1.65V    111.5mA    90.63mA    136.5mA
-600mV    11.93mA    10.19mA    15.49mA
3.75V     -3.874mA   -7.164mA   -3.711mA
3.9V      -7.032mA   -33.63mA   -3.958mA
4.05V     -17.8mA    -174mA     -7.845mA
4.2V      -83.02mA   -346.3mA   -21.25mA
4.35V     -270.9mA   -518.6mA   -46.1mA
4.5V      -464.6mA   -690.9mA   -197.7mA
4.65V     -658.6mA   -863.3mA   -416.9mA
4.8V      -852.7mA   -1.036A    -636.2mA
6.6V      -3.216A    -3.137A    -3.317A
[Ramp]
| variable   typ   min   max
dV/dt_r 0.2201/0.2070e-9   0.2105/0.2115e-9   0.2283/0.2079e-9
dV/dt_f 0.2085/0.4013e-9   0.2006/0.4008e-9   0.2143/0.3996e-9
R_load = 50
[Rising waveform]
R_fixture= 50
V_fixture= 0.594438
V_fixture_min= 0.555667
V_fixture_max= 0.632869
|Time   V(typ)   V(min)   V(max)
0s        434.8mV    408.5mV    464.7mV
1.09ns    434.7mV    408.5mV    470.6mV
1.22ns    436.8mV    408.5mV    435.9mV
1.27ns    439.9mV    408.4mV    463.9mV
1.42ns    409.8mV    409.3mV    681.4mV
1.7ns     696.3mV    390.1mV    784.6mV
1.84ns    741.4mV    540.9mV    800.7mV
2.01ns    760.8mV    678.8mV    805.4mV
2.22ns    769.4mV    718.8mV    810.5mV
4ns       775.3mV    735.8mV    814.9mV
[Falling waveform]
R_fixture= 50
V_fixture= 0.594438
V_fixture_min= 0.555667
V_fixture_max= 0.632869
|Time   V(typ)   V(min)   V(max)
0s        775.2mV    735.9mV    815.2mV
1.12ns    775mV      735.9mV    820.6mV
1.19ns    775.7mV    735.9mV    790.8mV
1.3ns     780.2mV    735.8mV    643.8mV
1.49ns    611.8mV    741.9mV    571.4mV
1.57ns    574.2mV    733.4mV    548.5mV
1.78ns    510.2mV    563.5mV    508.7mV
1.96ns    477.7mV    499.5mV    484.7mV
2.54ns    442.2mV    423.5mV    466.6mV
4ns       435.1mV    408.8mV    465.2mV
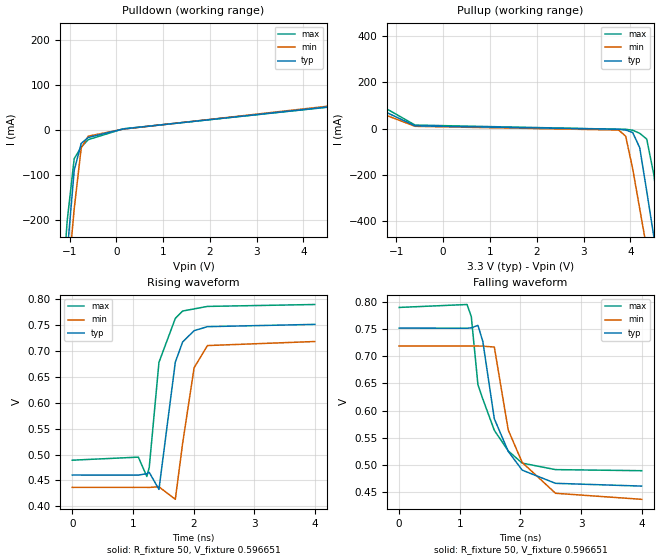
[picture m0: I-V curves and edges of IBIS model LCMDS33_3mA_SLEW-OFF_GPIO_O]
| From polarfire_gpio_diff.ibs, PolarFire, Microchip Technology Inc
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|   Model LCMDS33_3mA_SLEW-OFF_GPIO_O
[Model]   LCMDS33_3mA_SLEW-OFF_GPIO_O
Model_type   Output
Polarity   Non-Inverting
Enable   Active-High
Vmeas =   0.6
Cref =   5p
Rref =   100
|   typ   min   max
C_comp_pullup   2.605e-12   2.605e-12   2.76e-12
C_comp_pulldown  2.605e-12   2.605e-12   2.76e-12
[Temperature Range]  25C   100C   -40C
[Voltage Range]  3.3   3.15   3.45
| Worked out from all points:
|   slope of the pulldown table from 0 to 0.495 V, typ, clamps not added: 177 ohm
|   slope of the pullup table from 0 to 0.495 V, typ, clamps not added: 176 ohm
|   rising waveform, R_fixture 50, V_fixture 0.596651: 20-80 % time 208ps typ, 203ps min, 215ps max; typ from 0.46 V to 0.751 V
|   falling waveform, R_fixture 50, V_fixture 0.596651: 20-80 % time 416ps typ, 422ps min, 418ps max; typ from 0.751 V to 0.461 V
[Pulldown]
|Voltage   I(typ)   I(min)   I(max)
-3.3V     -3.224A    -2.966A    -3.553A
-1.2V     -468.9mA   -521.6mA   -422.9mA
-1.05V    -274.9mA   -349mA     -203.3mA
-900mV    -90.41mA   -176.5mA   -64.4mA
-750mV    -30.43mA   -40.77mA   -38.6mA
-600mV    -17.17mA   -14.33mA   -22.07mA
150mV     1.753mA    1.446mA    2.1mA
4.5V      50.61mA    52.23mA    49.99mA
5.1V      117.7mA    111.1mA    122.1mA
5.7V      201.2mA    184.5mA    217.6mA
6V        247.4mA    226.4mA    269mA
6.6V      351.1mA    318mA      381.4mA
[Pullup]
|Voltage   I(typ)   I(min)   I(max)
-3.3V     377.5mA    318.8mA    439mA
-1.65V    110.9mA    90.3mA     135.7mA
-600mV    11.46mA    9.5mA      14.91mA
3.75V     -3.354mA   -6.654mA   -3.184mA
3.9V      -6.518mA   -33.15mA   -3.432mA
4.05V     -17.29mA   -173.6mA   -7.327mA
4.2V      -82.56mA   -345.8mA   -20.73mA
4.35V     -270.4mA   -518.2mA   -45.59mA
4.5V      -464.2mA   -690.5mA   -197.2mA
4.65V     -658.1mA   -862.9mA   -416.5mA
4.8V      -852.3mA   -1.036A    -635.7mA
6.6V      -3.216A    -3.136A    -3.317A
[Ramp]
| variable   typ   min   max
dV/dt_r 0.1920/0.2118e-9   0.1848/0.2120e-9   0.2001/0.2136e-9
dV/dt_f 0.1784/0.4137e-9   0.1731/0.4186e-9   0.1842/0.4152e-9
R_load = 50
[Rising waveform]
R_fixture= 50
V_fixture= 0.596651
V_fixture_min= 0.564122
V_fixture_max= 0.633370
|Time   V(typ)   V(min)   V(max)
0s        460.4mV    436.6mV    489.1mV
1.09ns    460.3mV    436.6mV    495mV
1.23ns    463.1mV    436.6mV    457.6mV
1.27ns    465.5mV    436.5mV    475.5mV
1.43ns    432.7mV    437.7mV    678.1mV
1.7ns     678.6mV    413.5mV    763mV
1.82ns    717.4mV    521.3mV    777.2mV
2.01ns    739.3mV    667.8mV    781.3mV
2.23ns    747mV      710.5mV    786.1mV
4ns       751.4mV    718.3mV    789.8mV
[Falling waveform]
R_fixture= 50
V_fixture= 0.596651
V_fixture_min= 0.564122
V_fixture_max= 0.633370
|Time   V(typ)   V(min)   V(max)
0s        751.4mV    718.5mV    789.4mV
1.12ns    751.2mV    718.5mV    794.8mV
1.19ns    751.9mV    718.5mV    772.7mV
1.3ns     756.4mV    718.4mV    647.2mV
1.38ns    727mV      718.3mV    621.2mV
1.57ns    584.8mV    716.6mV    563.6mV
1.8ns     524.8mV    564mV      525.7mV
2.03ns    490.4mV    504.5mV    503.3mV
2.58ns    466.2mV    447.9mV    491.4mV
4ns       461.1mV    436.8mV    489.4mV
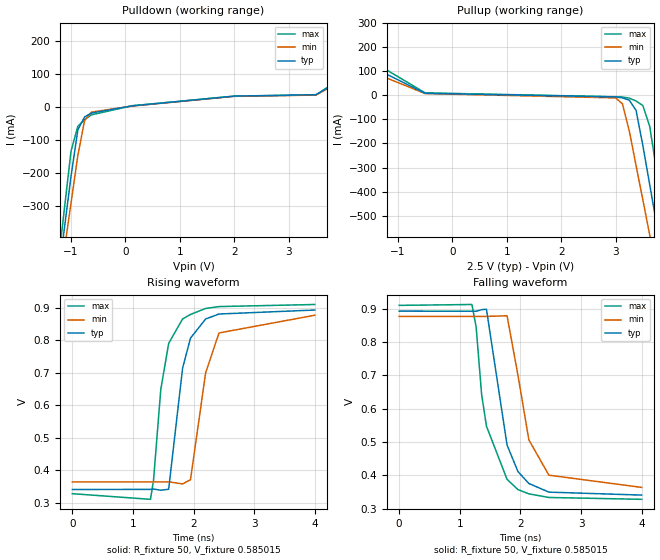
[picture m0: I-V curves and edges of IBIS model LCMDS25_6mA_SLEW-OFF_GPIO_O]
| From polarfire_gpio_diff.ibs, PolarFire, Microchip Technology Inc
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|   Model LCMDS25_6mA_SLEW-OFF_GPIO_O
[Model]   LCMDS25_6mA_SLEW-OFF_GPIO_O
Model_type   Output
Polarity   Non-Inverting
Enable   Active-High
Vmeas =   0.6
Cref =   5p
Rref =   100
|   typ   min   max
C_comp_pullup   2.605e-12   2.605e-12   2.76e-12
C_comp_pulldown  2.605e-12   2.605e-12   2.76e-12
[Temperature Range]  25C   100C   -40C
[Voltage Range]  2.5   2.375   2.625
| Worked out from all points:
|   slope of the pulldown table from 0 to 0.375 V, typ, clamps not added: 71.4 ohm
|   slope of the pullup table from 0 to 0.375 V, typ, clamps not added: 103 ohm
|   rising waveform, R_fixture 50, V_fixture 0.585015: 20-80 % time 245ps typ, 283ps min, 226ps max; typ from 0.34 V to 0.893 V
|   falling waveform, R_fixture 50, V_fixture 0.585015: 20-80 % time 291ps typ, 316ps min, 316ps max; typ from 0.893 V to 0.341 V
[Pulldown]
|Voltage   I(typ)   I(min)   I(max)
-2.5V     -2.164A    -2.027A    -2.345A
-1.25V    -533.9mA   -579.4mA   -496.4mA
-1.125V   -372.1mA   -435.6mA   -313.3mA
-1V       -210.6mA   -291.8mA   -134.7mA
-875mV    -70.44mA   -148.1mA   -59.47mA
-750mV    -31.07mA   -41.32mA   -39.41mA
-625mV    -19.5mA    -16.65mA   -25.02mA
125mV     2.146mA    1.753mA    2.697mA
2V        31.72mA    31.09mA    31.64mA
3.5V      36.1mA     34.94mA    35.28mA
4.125V    97.38mA    91.55mA    103mA
5V        216.7mA    195.3mA    239.2mA
[Pullup]
|Voltage   I(typ)   I(min)   I(max)
-2.5V     231.4mA    190mA      278.9mA
-500mV    8.252mA    7.021mA    10.02mA
3V        -6.861mA   -10.85mA   -6.328mA
3.125V    -10.73mA   -35.85mA   -7.088mA
3.25V     -20.31mA   -147.4mA   -11.88mA
3.375V    -62.71mA   -290.9mA   -23.78mA
3.5V      -208.5mA   -434.5mA   -42.7mA
3.625V    -369.9mA   -578.1mA   -128mA
3.75V     -531.4mA   -721.7mA   -309.4mA
3.875V    -693.1mA   -865.4mA   -492.1mA
4V        -854.9mA   -1.009A    -674.9mA
5V        -2.159A    -2.17A     -2.151A
[Ramp]
| variable   typ   min   max
dV/dt_r 0.3404/0.2472e-9   0.3148/0.2839e-9   0.3610/0.2246e-9
dV/dt_f 0.3362/0.2921e-9   0.3133/0.3173e-9   0.3535/0.3149e-9
R_load = 50
[Rising waveform]
R_fixture= 50
V_fixture= 0.585015
V_fixture_min= 0.585090
V_fixture_max= 0.598333
|Time   V(typ)   V(min)   V(max)
0s        340.5mV    363.7mV    327.6mV
1.29ns    340.8mV    363.7mV    310.2mV
1.34ns    341.9mV    363.7mV    368.2mV
1.46ns    338.2mV    363.7mV    648.5mV
1.59ns    341.1mV    364.1mV    790.4mV
1.82ns    714.4mV    357.7mV    865.7mV
1.95ns    806.6mV    370.5mV    879.5mV
2.2ns     865.6mV    699.9mV    898mV
2.42ns    880.9mV    822.5mV    903.8mV
4ns       893.2mV    877.1mV    910.2mV
[Falling waveform]
R_fixture= 50
V_fixture= 0.585015
V_fixture_min= 0.585090
V_fixture_max= 0.598333
|Time   V(typ)   V(min)   V(max)
0s        892.6mV    876.9mV    910mV
1.2ns     892.5mV    876.9mV    912.6mV
1.27ns    892.4mV    876.9mV    845.3mV
1.36ns    897mV      876.9mV    643.5mV
1.44ns    898.5mV    876.9mV    547.7mV
1.78ns    491mV      878.8mV    388mV
1.96ns    411.3mV    700.2mV    357.3mV
2.14ns    375.6mV    506.4mV    344.6mV
2.47ns    349.7mV    400.6mV    333.7mV
4ns       340.8mV    363.9mV    328.1mV
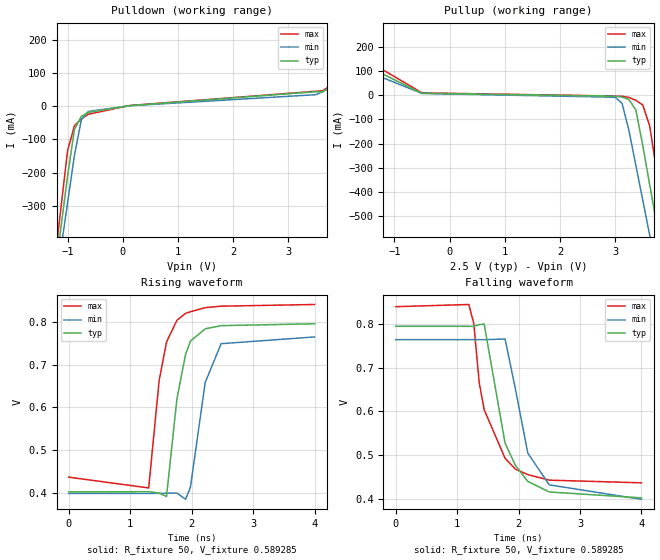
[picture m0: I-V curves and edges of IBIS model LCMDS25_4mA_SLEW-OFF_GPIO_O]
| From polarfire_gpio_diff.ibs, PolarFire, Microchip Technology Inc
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|   Model LCMDS25_4mA_SLEW-OFF_GPIO_O
[Model]   LCMDS25_4mA_SLEW-OFF_GPIO_O
Model_type   Output
Polarity   Non-Inverting
Enable   Active-High
Vmeas =   0.6
Cref =   5p
Rref =   100
|   typ   min   max
C_comp_pullup   2.605e-12   2.605e-12   2.76e-12
C_comp_pulldown  2.605e-12   2.605e-12   2.76e-12
[Temperature Range]  25C   100C   -40C
[Voltage Range]  2.5   2.375   2.625
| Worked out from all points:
|   slope of the pulldown table from 0 to 0.375 V, typ, clamps not added: 101 ohm
|   slope of the pullup table from 0 to 0.375 V, typ, clamps not added: 130 ohm
|   rising waveform, R_fixture 50, V_fixture 0.589285: 20-80 % time 224ps typ, 246ps min, 222ps max; typ from 0.402 V to 0.795 V
|   falling waveform, R_fixture 50, V_fixture 0.589285: 20-80 % time 366ps typ, 355ps min, 365ps max; typ from 0.795 V to 0.401 V
[Pulldown]
|Voltage   I(typ)   I(min)   I(max)
-2.5V     -2.163A    -2.027A    -2.344A
-1.25V    -533.5mA   -578.9mA   -496mA
-1.125V   -371.8mA   -435.2mA   -313mA
-1V       -210.2mA   -291.3mA   -134.1mA
-875mV    -69.72mA   -147.7mA   -58.5mA
-750mV    -30.23mA   -40.5mA    -38.47mA
-625mV    -18.72mA   -15.8mA    -24.14mA
125mV     1.763mA    1.376mA    2.2mA
3.5V      43.77mA    34.84mA    45.17mA
3.625V    44.11mA    43.85mA    46.72mA
4.25V     110.2mA    101.4mA    117.9mA
5V        214.3mA    192mA      237mA
[Pullup]
|Voltage   I(typ)   I(min)   I(max)
-2.5V     229.7mA    189.5mA    276.4mA
-500mV    7.428mA    6.391mA    8.973mA
3V        -4.82mA    -9.006mA   -4.246mA
3.125V    -8.703mA   -34.09mA   -5.018mA
3.25V     -18.3mA    -145.8mA   -9.832mA
3.375V    -60.85mA   -289.2mA   -21.75mA
3.5V      -206.8mA   -432.9mA   -40.67mA
3.625V    -368.1mA   -576.5mA   -126.3mA
3.75V     -529.7mA   -720mA     -307.7mA
3.875V    -691.4mA   -863.7mA   -490.4mA
4V        -853.2mA   -1.008A    -673.2mA
5V        -2.158A    -2.169A    -2.15A
[Ramp]
| variable   typ   min   max
dV/dt_r 0.2475/0.2268e-9   0.2291/0.2521e-9   0.2586/0.2233e-9
dV/dt_f 0.2408/0.3646e-9   0.2248/0.3568e-9   0.2467/0.3632e-9
R_load = 50
[Rising waveform]
R_fixture= 50
V_fixture= 0.589285
V_fixture_min= 0.561204
V_fixture_max= 0.632521
|Time   V(typ)   V(min)   V(max)
0s        401.5mV    398mV      436mV
1.3ns     402mV      398mV      410.8mV
1.47ns    398.8mV    398mV      662.4mV
1.59ns    390.7mV    398.4mV    752.6mV
1.76ns    620.1mV    398.7mV    803.6mV
1.9ns     723.6mV    384.1mV    820mV
1.98ns    754.9mV    412.9mV    823.6mV
2.22ns    783.7mV    658.1mV    833.2mV
2.48ns    791.1mV    748.8mV    836.7mV
4ns       795.4mV    764.6mV    840.6mV
[Falling waveform]
R_fixture= 50
V_fixture= 0.589285
V_fixture_min= 0.561204
V_fixture_max= 0.632521
|Time   V(typ)   V(min)   V(max)
0s        795.4mV    764.7mV    840.4mV
1.19ns    795.3mV    764.7mV    845.4mV
1.27ns    795.2mV    764.7mV    802.5mV
1.36ns    799.2mV    764.7mV    665.4mV
1.44ns    800.4mV    764.6mV    603.9mV
1.78ns    527.2mV    766.3mV    492.5mV
1.95ns    475.9mV    650.3mV    467.3mV
2.15ns    439.4mV    504.3mV    455mV
2.5ns     415.1mV    431.4mV    442.2mV
4ns       401.5mV    398.2mV    436.1mV
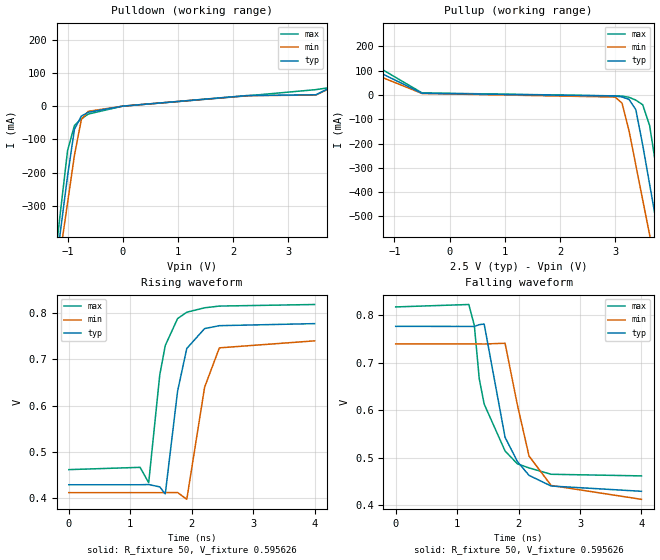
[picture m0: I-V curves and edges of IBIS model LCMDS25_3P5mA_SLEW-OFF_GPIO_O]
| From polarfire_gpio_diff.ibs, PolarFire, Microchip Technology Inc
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|   Model LCMDS25_3P5mA_SLEW-OFF_GPIO_O
[Model]   LCMDS25_3P5mA_SLEW-OFF_GPIO_O
Model_type   Output
Polarity   Non-Inverting
Enable   Active-High
Vmeas =   0.6
Cref =   5p
Rref =   100
|   typ   min   max
C_comp_pullup   2.605e-12   2.605e-12   2.76e-12
C_comp_pulldown  2.605e-12   2.605e-12   2.76e-12
[Temperature Range]  25C   100C   -40C
[Voltage Range]  2.5   2.375   2.625
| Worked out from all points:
|   slope of the pulldown table from 0 to 0.375 V, typ, clamps not added: 115 ohm
|   slope of the pullup table from 0 to 0.375 V, typ, clamps not added: 141 ohm
|   rising waveform, R_fixture 50, V_fixture 0.595626: 20-80 % time 210ps typ, 237ps min, 220ps max; typ from 0.429 V to 0.776 V
|   falling waveform, R_fixture 50, V_fixture 0.595626: 20-80 % time 373ps typ, 371ps min, 379ps max; typ from 0.776 V to 0.43 V
[Pulldown]
|Voltage   I(typ)   I(min)   I(max)
-2.5V     -2.163A    -2.027A    -2.344A
-1.25V    -533.4mA   -578.9mA   -495.9mA
-1.125V   -371.7mA   -435.1mA   -312.8mA
-1V       -210.2mA   -291.3mA   -133.9mA
-875mV    -69.53mA   -147.6mA   -58.22mA
-750mV    -30.01mA   -40.36mA   -38.21mA
-625mV    -18.51mA   -15.65mA   -23.89mA
0V        -35.14uA   -30.22uA   -43.37uA
2.25V     31.86mA    31.52mA    31mA
3.5V      34.24mA    33.38mA    49.66mA
3.75V     54.89mA    53.23mA    55.82mA
5V        213.7mA    191.5mA    236.5mA
[Pullup]
|Voltage   I(typ)   I(min)   I(max)
-2.5V     229.5mA    189.4mA    275.8mA
-500mV    7.143mA    6.171mA    8.614mA
3V        -4.314mA   -8.52mA    -3.734mA
3.125V    -8.203mA   -33.62mA   -4.508mA
3.25V     -17.8mA    -145.4mA   -9.329mA
3.375V    -60.39mA   -288.8mA   -21.24mA
3.5V      -206.4mA   -432.5mA   -40.17mA
3.625V    -367.7mA   -576mA     -125.9mA
3.75V     -529.2mA   -719.6mA   -307.3mA
3.875V    -690.9mA   -863.3mA   -490mA
4V        -852.7mA   -1.007A    -672.8mA
5V        -2.157A    -2.168A    -2.149A
[Ramp]
| variable   typ   min   max
dV/dt_r 0.2203/0.2133e-9   0.2067/0.2449e-9   0.2305/0.2211e-9
dV/dt_f 0.2124/0.3700e-9   0.2007/0.3717e-9   0.2173/0.3771e-9
R_load = 50
[Rising waveform]
R_fixture= 50
V_fixture= 0.595626
V_fixture_min= 0.560112
V_fixture_max= 0.635056
|Time   V(typ)   V(min)   V(max)
0s        429.3mV    412.3mV    461.9mV
1.16ns    429.3mV    412.3mV    466.8mV
1.3ns     429.8mV    412.3mV    433.7mV
1.48ns    424.7mV    412.2mV    665.8mV
1.57ns    409.5mV    412.4mV    729.4mV
1.77ns    630.8mV    412.6mV    787.2mV
1.92ns    722.9mV    397.9mV    801mV
2.21ns    765.7mV    639.3mV    810.5mV
2.45ns    772mV      724.2mV    814.2mV
4ns       776.4mV    739.3mV    817.6mV
[Falling waveform]
R_fixture= 50
V_fixture= 0.595626
V_fixture_min= 0.560112
V_fixture_max= 0.635056
|Time   V(typ)   V(min)   V(max)
0s        776.4mV    739.4mV    817.3mV
1.19ns    776.3mV    739.4mV    822.4mV
1.28ns    776.3mV    739.4mV    778.3mV
1.36ns    780mV      739.4mV    666.2mV
1.44ns    781.3mV    739.3mV    613mV
1.78ns    543.2mV    740.9mV    514.3mV
1.98ns    492.2mV    611.6mV    487.3mV
2.17ns    463mV      503.7mV    478.7mV
2.53ns    440.6mV    441.8mV    465.3mV
4ns       429.5mV    412.6mV    461.9mV
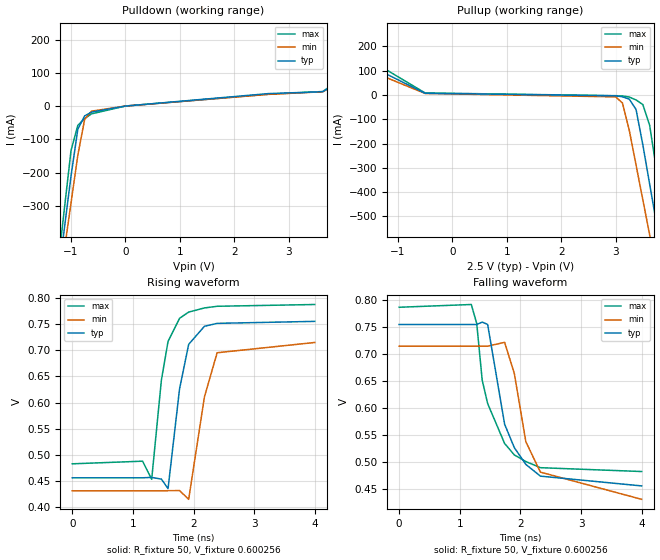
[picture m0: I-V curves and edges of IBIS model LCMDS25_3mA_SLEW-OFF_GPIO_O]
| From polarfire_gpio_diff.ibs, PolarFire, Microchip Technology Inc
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|   Model LCMDS25_3mA_SLEW-OFF_GPIO_O
[Model]   LCMDS25_3mA_SLEW-OFF_GPIO_O
Model_type   Output
Polarity   Non-Inverting
Enable   Active-High
Vmeas =   0.6
Cref =   5p
Rref =   100
|   typ   min   max
C_comp_pullup   2.605e-12   2.605e-12   2.76e-12
C_comp_pulldown  2.605e-12   2.605e-12   2.76e-12
[Temperature Range]  25C   100C   -40C
[Voltage Range]  2.5   2.375   2.625
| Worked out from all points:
|   slope of the pulldown table from 0 to 0.375 V, typ, clamps not added: 133 ohm
|   slope of the pullup table from 0 to 0.375 V, typ, clamps not added: 158 ohm
|   rising waveform, R_fixture 50, V_fixture 0.600256: 20-80 % time 212ps typ, 232ps min, 208ps max; typ from 0.456 V to 0.755 V
|   falling waveform, R_fixture 50, V_fixture 0.600256: 20-80 % time 387ps typ, 383ps min, 387ps max; typ from 0.755 V to 0.457 V
[Pulldown]
|Voltage   I(typ)   I(min)   I(max)
-2.5V     -2.163A    -2.027A    -2.344A
-1.25V    -533.3mA   -578.8mA   -495.8mA
-1.125V   -371.6mA   -435mA     -312.7mA
-1V       -210.1mA   -291.2mA   -133.7mA
-875mV    -69.33mA   -147.6mA   -57.9mA
-750mV    -29.77mA   -40.2mA    -37.9mA
-625mV    -18.3mA    -15.48mA   -23.6mA
0V        -34.19uA   -29.25uA   -41.78uA
2.625V    37.36mA    35.08mA    35.46mA
3.625V    43.07mA    42.92mA    43.67mA
4.25V     109.2mA    100.5mA    116.8mA
5V        213.1mA    191mA      235.9mA
[Pullup]
|Voltage   I(typ)   I(min)   I(max)
-2.5V     229.2mA    189.3mA    275.1mA
-500mV    6.795mA    5.904mA    8.176mA
3V        -3.797mA   -8.018mA   -3.207mA
3.125V    -7.691mA   -33.14mA   -3.984mA
3.25V     -17.29mA   -144.9mA   -8.812mA
3.375V    -59.92mA   -288.4mA   -20.73mA
3.5V      -205.9mA   -432mA     -39.66mA
3.625V    -367.3mA   -575.6mA   -125.5mA
3.75V     -528.8mA   -719.2mA   -306.9mA
3.875V    -690.5mA   -862.9mA   -489.5mA
4V        -852.3mA   -1.007A    -672.3mA
5V        -2.157A    -2.168A    -2.149A
[Ramp]
| variable   typ   min   max
dV/dt_r 0.1921/0.2163e-9   0.1815/0.2417e-9   0.2009/0.2110e-9
dV/dt_f 0.1833/0.3840e-9   0.1743/0.3845e-9   0.1862/0.3848e-9
R_load = 50
[Rising waveform]
R_fixture= 50
V_fixture= 0.600256
V_fixture_min= 0.561027
V_fixture_max= 0.63081
|Time   V(typ)   V(min)   V(max)
0s        456.4mV    431.5mV    483.1mV
1.16ns    456.4mV    431.5mV    488.1mV
1.31ns    457.2mV    431.5mV    453.6mV
1.47ns    453.9mV    431.4mV    642.8mV
1.58ns    435.8mV    431.8mV    716.8mV
1.77ns    626.3mV    432mV      760.9mV
1.92ns    711.1mV    415.3mV    772.7mV
2.18ns    745.6mV    610.7mV    780.6mV
2.39ns    751.2mV    695.1mV    783.8mV
4ns       755mV      714.7mV    787.2mV
[Falling waveform]
R_fixture= 50
V_fixture= 0.600256
V_fixture_min= 0.561027
V_fixture_max= 0.63081
|Time   V(typ)   V(min)   V(max)
0s        755mV      715.1mV    786.9mV
1.19ns    755mV      715.1mV    792mV
1.28ns    755mV      715.1mV    756.8mV
1.37ns    759.5mV    715.1mV    652.2mV
1.46ns    755.1mV    715mV      608.8mV
1.74ns    570.6mV    722mV      535mV
1.9ns     527.3mV    664.4mV    513.9mV
2.09ns    496.4mV    538.3mV    501.7mV
2.33ns    474.7mV    482.1mV    490.3mV
4ns       456.6mV    431.8mV    483.2mV
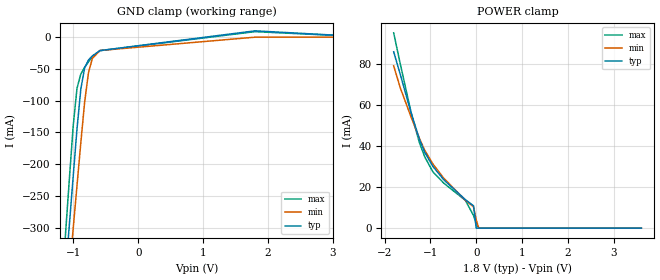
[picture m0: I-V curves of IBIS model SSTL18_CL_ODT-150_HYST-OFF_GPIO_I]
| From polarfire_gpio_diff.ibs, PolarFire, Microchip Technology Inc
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|   Model SSTL18_CL_ODT-150_HYST-OFF_GPIO_I
[Model]   SSTL18_CL_ODT-150_HYST-OFF_GPIO_I
Model_type   Input
Vinl =   0.775
Vinh =   1.025
|   typ   min   max
C_comp_pullup   2.605e-12   2.605e-12   2.76e-12
C_comp_pulldown  2.605e-12   2.605e-12   2.76e-12
[Temperature Range]  25C   100C   -40C
[Voltage Range]  1.8   1.71   1.89
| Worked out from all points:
|   POWER clamp passes 1 mA (typ) near -0.01 V on its own axis
[GND Clamp]
| Voltage   I(typ)   I(min)   I(max)
-1.8V     -1.25A     -1.217A    -1.304A
-1.122V   -372.1mA   -437.5mA   -309.8mA
-1.063V   -295.8mA   -369.5mA   -223.9mA
-1.004V   -219.6mA   -301.6mA   -140.3mA
-945mV    -144.5mA   -233.7mA   -80.46mA
-885.9mV  -81.59mA   -166.1mA   -57.94mA
-826.9mV  -48.24mA   -101.9mA   -47.42mA
-767.8mV  -35.93mA   -55.86mA   -38.77mA
-708.7mV  -29.44mA   -33.6mA    -31.41mA
-590.6mV  -21.08mA   -20.93mA   -21.25mA
1.8V      9.955mA    0A         8.699mA
3.6V      0A         0A         0A
[POWER Clamp]
| Voltage   I(typ)   I(min)   I(max)
-1.8V     85.84mA    79mA       95.05mA
-1.654V   74.66mA    68.16mA    79.73mA
-1.417V   55.88mA    53.91mA    56.03mA
-1.24V    43.38mA    43.76mA    41.7mA
-1.122V   36.89mA    37.89mA    34.67mA
-945mV    30.06mA    31.22mA    27.4mA
-708.7mV  23.58mA    24.35mA    21.92mA
-236.2mV  13.85mA    13.55mA    13.52mA
-59.06mV  10.88mA    10.38mA    6.154mA
0V        0A         3.984mA    2.116mA
56.25mV   0A         0A         0A
3.6V      0A         0A         0A
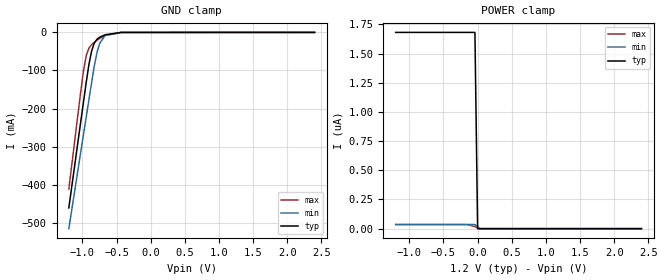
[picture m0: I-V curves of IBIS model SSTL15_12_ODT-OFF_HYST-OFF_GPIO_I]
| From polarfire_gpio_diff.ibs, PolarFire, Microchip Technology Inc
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|   Model SSTL15_12_ODT-OFF_HYST-OFF_GPIO_I
[Model]   SSTL15_12_ODT-OFF_HYST-OFF_GPIO_I
Model_type   Input
Vinl =   0.65
Vinh =   0.85
|   typ   min   max
C_comp_pullup   2.605e-12   2.605e-12   2.76e-12
C_comp_pulldown  2.605e-12   2.605e-12   2.76e-12
[Temperature Range]  25C   100C   -40C
[Voltage Range]  1.2   1.14   1.26
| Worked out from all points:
|   GND clamp passes 1 mA (typ) near -0.53 V on its own axis
[GND Clamp]
| Voltage   I(typ)   I(min)   I(max)
-1.2V     -460.9mA   -515.3mA   -411.5mA
-1.024V   -232.8mA   -312.7mA   -153.3mA
-984.4mV  -181.9mA   -267.4mA   -99.94mA
-945mV    -131.1mA   -222.2mA   -61.15mA
-905.6mV  -84.23mA   -176.9mA   -41.34mA
-866.2mV  -48.93mA   -131.7mA   -32.26mA
-826.9mV  -28.05mA   -88.35mA   -26.02mA
-787.5mV  -17.96mA   -52.99mA   -20.61mA
-748.1mV  -12.65mA   -28.64mA   -15.79mA
-669.4mV  -6.309mA   -8.083mA   -8.082mA
-433.1mV  -82.31uA   -116.2uA   -108.2uA
2.4V      0A         0A         0A
[POWER Clamp]
| Voltage   I(typ)   I(min)   I(max)
-1.2V     1.682uA    35.43nA    35.4nA
-157.5mV  1.682uA    35.43nA    35.4nA
-39.38mV  1.682uA    35.43nA    17.98nA
0V        0A         14.17nA    6.18nA
37.5mV    0A         0A         0A
2.4V      0A         0A         0A
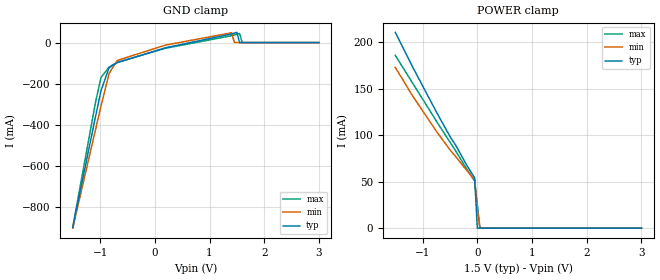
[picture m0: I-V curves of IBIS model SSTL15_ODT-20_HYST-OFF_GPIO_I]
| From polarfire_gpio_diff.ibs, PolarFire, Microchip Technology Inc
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|   Model SSTL15_ODT-20_HYST-OFF_GPIO_I
[Model]   SSTL15_ODT-20_HYST-OFF_GPIO_I
Model_type   Input
Vinl =   0.65
Vinh =   0.85
|   typ   min   max
C_comp_pullup   2.605e-12   2.605e-12   2.76e-12
C_comp_pulldown  2.605e-12   2.605e-12   2.76e-12
[Temperature Range]  25C   100C   -40C
[Voltage Range]  1.5   1.425   1.575
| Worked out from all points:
|   POWER clamp passes 1 mA (typ) near -0.00 V on its own axis
[GND Clamp]
| Voltage   I(typ)   I(min)   I(max)
-1.5V     -900mA     -903.8mA   -899.4mA
-1.083V   -359.6mA   -423.1mA   -289.2mA
-984.4mV  -234.9mA   -309.6mA   -170.5mA
-836.7mV  -122.6mA   -150.9mA   -119.3mA
-689.1mV  -98.26mA   -87.24mA   -96.29mA
187.5mV   -25.73mA   -12.74mA   -28.14mA
1.406V    42.12mA    47.95mA    33.68mA
1.453V    45.82mA    0A         37.02mA
1.5V      49.71mA    0A         40.52mA
1.549V    0A         0A         44.4mA
1.598V    0A         0A         0A
3V        0A         0A         0A
[POWER Clamp]
| Voltage   I(typ)   I(min)   I(max)
-1.5V     210.3mA    172.7mA    185.6mA
-1.181V   173mA      141.9mA    155.7mA
-738.3mV  123.7mA    103.2mA    114.1mA
-492.2mV  97.74mA    83.52mA    91.63mA
-393.7mV  88.97mA    76.75mA    82.76mA
-196.9mV  67.94mA    62.22mA    63.8mA
-49.22mV  53.99mA    52.12mA    50.67mA
0V        0A         20.31mA    25.39mA
46.88mV   0A         0A         0A
3V        0A         0A         0A
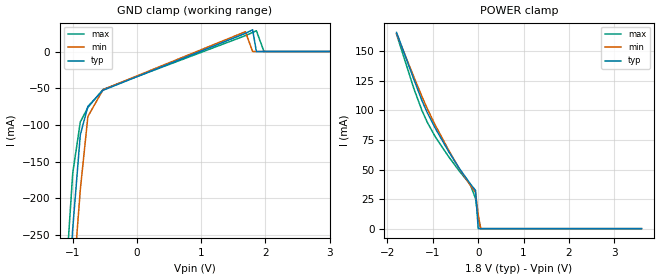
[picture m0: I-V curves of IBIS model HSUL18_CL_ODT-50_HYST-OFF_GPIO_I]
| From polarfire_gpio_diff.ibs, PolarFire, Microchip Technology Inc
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|   Model HSUL18_CL_ODT-50_HYST-OFF_GPIO_I
[Model]   HSUL18_CL_ODT-50_HYST-OFF_GPIO_I
Model_type   Input
Vinl =   0.54
Vinh =   1.26
|   typ   min   max
C_comp_pullup   2.605e-12   2.605e-12   2.76e-12
C_comp_pulldown  2.605e-12   2.605e-12   2.76e-12
[Temperature Range]  25C   100C   -40C
[Voltage Range]  1.8   1.71   1.89
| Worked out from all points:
|   POWER clamp passes 1 mA (typ) near -0.00 V on its own axis
[GND Clamp]
| Voltage   I(typ)   I(min)   I(max)
-1.8V     -1.272A    -1.24A     -1.324A
-1.122V   -393.6mA   -459.4mA   -329.1mA
-1.063V   -317.2mA   -391.4mA   -244.2mA
-1.004V   -241.2mA   -323.4mA   -165.6mA
-885.9mV  -113.4mA   -188.3mA   -95.96mA
-767.8mV  -74.77mA   -88.51mA   -76.15mA
-531.6mV  -52.72mA   -51.99mA   -51.66mA
1.688V    24.74mA    26.97mA    21.65mA
1.8V      29.61mA    0A         25.91mA
1.859V    0A         0A         28.31mA
1.977V    0A         0A         0A
3.6V      0A         0A         0A
[POWER Clamp]
| Voltage   I(typ)   I(min)   I(max)
-1.8V     166mA      164.9mA    164.5mA
-1.417V   126.1mA    128.2mA    118.3mA
-1.24V    108.3mA    111.8mA    99.92mA
-1.122V   98.04mA    101.4mA    89.93mA
-945mV    84.87mA    87.49mA    77.6mA
-649.7mV  65.09mA    66.25mA    60.76mA
-413.4mV  50.78mA    50.52mA    48.58mA
-177.2mV  38.13mA    36.88mA    37.45mA
-59.06mV  32.36mA    30.82mA    25.45mA
0V        0A         11.84mA    8.749mA
56.25mV   0A         0A         0A
3.6V      0A         0A         0A
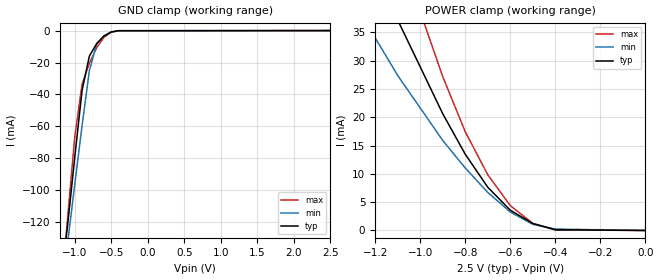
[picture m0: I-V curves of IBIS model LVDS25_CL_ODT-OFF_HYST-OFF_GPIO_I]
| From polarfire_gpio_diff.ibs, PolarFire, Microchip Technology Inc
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|   Model LVDS25_CL_ODT-OFF_HYST-OFF_GPIO_I
[Model]   LVDS25_CL_ODT-OFF_HYST-OFF_GPIO_I
Model_type   Input
Vinl =   1.125
Vinh =   1.375
|   typ   min   max
C_comp_pullup   2.605e-12   2.605e-12   2.76e-12
C_comp_pulldown  2.605e-12   2.605e-12   2.76e-12
[Temperature Range]  25C   100C   -40C
[Voltage Range]  2.5   2.375   2.625
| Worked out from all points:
|   GND clamp passes 1 mA (typ) near -0.51 V on its own axis
|   POWER clamp passes 1 mA (typ) near -0.48 V on its own axis
[GND_clamp]
|Voltage   I(typ)   I(min)   I(max)
-1.9V     -487.4mA   -459mA     -570.2mA
-1.2V     -160.7mA   -172.1mA   -171.3mA
-1.1V     -122.9mA   -133.9mA   -118.5mA
-1V       -79.29mA   -96.34mA   -66.65mA
-900mV    -37.54mA   -59.55mA   -33.66mA
-800mV    -15.98mA   -25.13mA   -20.51mA
-700mV    -8.2mA     -8.287mA   -10.77mA
-600mV    -3.375mA   -3.263mA   -4.222mA
-500mV    -848.9uA   -979.4uA   -924.2uA
-400mV    -80.63uA   -143.5uA   -66.49uA
2.5V      1.001uA    1.272uA    839.9nA
[POWER_clamp]
|Voltage   I(typ)   I(min)   I(max)
-2.5V     229.2mA    175mA      301.9mA
-1.4V     67.48mA    49.17mA    93.58mA
-1.3V     56.73mA    41.29mA    78.11mA
-1.2V     46.63mA    34.02mA    63.56mA
-1.1V     37.17mA    27.38mA    50.13mA
-900mV    20.62mA    15.9mA     27.16mA
-800mV    13.46mA    11.03mA    17.43mA
-700mV    7.632mA    6.713mA    9.832mA
-600mV    3.576mA    3.258mA    4.39mA
-500mV    1.224mA    1.079mA    1.255mA
-400mV    133.2uA    249.4uA    95.04uA
0V        0A         0A         0A
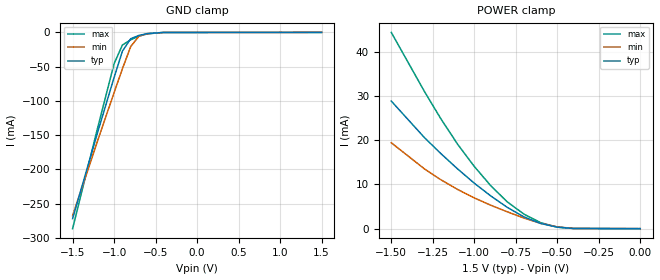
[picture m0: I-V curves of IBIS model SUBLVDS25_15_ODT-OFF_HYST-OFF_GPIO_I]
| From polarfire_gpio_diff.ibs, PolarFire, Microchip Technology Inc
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|   Model SUBLVDS25_15_ODT-OFF_HYST-OFF_GPIO_I
[Model]   SUBLVDS25_15_ODT-OFF_HYST-OFF_GPIO_I
Model_type   Input
Vinl =   0.775
Vinh =   1.025
|   typ   min   max
C_comp_pullup   2.605e-12   2.605e-12   2.76e-12
C_comp_pulldown  2.605e-12   2.605e-12   2.76e-12
[Temperature Range]  25C   100C   -40C
[Voltage Range]  1.5   1.425   1.575
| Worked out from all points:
|   GND clamp passes 1 mA (typ) near -0.54 V on its own axis
|   POWER clamp passes 1 mA (typ) near -0.58 V on its own axis
[GND_clamp]
|Voltage   I(typ)   I(min)   I(max)
-1.5V     -271.7mA   -267.4mA   -286.3mA
-1.2V     -146.4mA   -158.5mA   -140.1mA
-1V       -65.7mA    -87.81mA   -45.64mA
-900mV    -27.42mA   -53.15mA   -18.43mA
-800mV    -9.225mA   -20.63mA   -10.77mA
-700mV    -4.388mA   -5.455mA   -5.496mA
-600mV    -1.737mA   -1.833mA   -2.069mA
-400mV    -40.61uA   -63.73uA   -41.82uA
1.5V      576.4nA    664.1nA    507.4nA
[POWER_clamp]
|Voltage   I(typ)   I(min)   I(max)
-1.5V     28.88mA    19.44mA    44.42mA
-1.3V     20.6mA     13.53mA    31.04mA
-1.2V     16.95mA    11.04mA    24.8mA
-1.1V     13.51mA    8.87mA     19.1mA
-1V       10.29mA    6.966mA    14.09mA
-900mV    7.398mA    5.294mA    9.691mA
-800mV    4.79mA     3.798mA    6.028mA
-700mV    2.654mA    2.393mA    3.274mA
-600mV    1.175mA    1.201mA    1.355mA
-500mV    340uA      399.4uA    339.5uA
-400mV    35.83uA    54.93uA    36.3uA
0V        0A         0A         0A
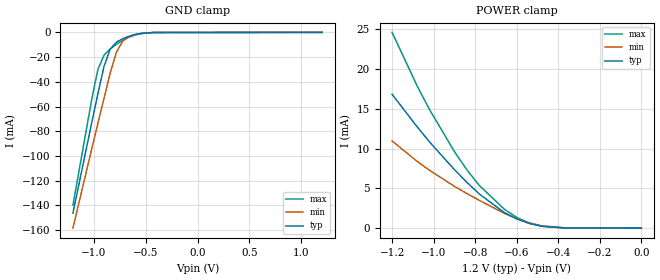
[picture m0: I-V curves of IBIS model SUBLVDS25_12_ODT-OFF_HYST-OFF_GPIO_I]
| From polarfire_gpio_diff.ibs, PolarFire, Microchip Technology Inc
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|   Model SUBLVDS25_12_ODT-OFF_HYST-OFF_GPIO_I
[Model]   SUBLVDS25_12_ODT-OFF_HYST-OFF_GPIO_I
Model_type   Input
Vinl =   0.775
Vinh =   1.025
|   typ   min   max
C_comp_pullup   2.605e-12   2.605e-12   2.76e-12
C_comp_pulldown  2.605e-12   2.605e-12   2.76e-12
[Temperature Range]  25C   100C   -40C
[Voltage Range]  1.2   1.14   1.26
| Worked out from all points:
|   GND clamp passes 1 mA (typ) near -0.55 V on its own axis
|   POWER clamp passes 1 mA (typ) near -0.58 V on its own axis
[GND_clamp]
|Voltage   I(typ)   I(min)   I(max)
-1.2V     -146.3mA   -158.4mA   -139.9mA
-1.02V    -73.6mA    -94.78mA   -54.84mA
-960mV    -49.88mA   -73.86mA   -30.13mA
-900mV    -27.4mA    -53.14mA   -18.39mA
-840mV    -13.44mA   -32.63mA   -13.37mA
-780mV    -7.876mA   -15.87mA   -9.551mA
-720mV    -5.095mA   -6.997mA   -6.39mA
-660mV    -3.139mA   -3.463mA   -3.885mA
-600mV    -1.73mA    -1.826mA   -2.06mA
-540mV    -803.3uA   -885.6uA   -904.6uA
-420mV    -71.33uA   -102.5uA   -74.8uA
1.2V      449.6nA    508.4nA    407.4nA
[POWER_clamp]
|Voltage   I(typ)   I(min)   I(max)
-1.2V     16.81mA    10.95mA    24.59mA
-1.08V    12.75mA    8.4mA      17.89mA
-1.02V    10.84mA    7.269mA    14.91mA
-900mV    7.347mA    5.254mA    9.619mA
-840mV    5.757mA    4.349mA    7.325mA
-780mV    4.286mA    3.486mA    5.366mA
-660mV    1.966mA    1.863mA    2.384mA
-600mV    1.165mA    1.192mA    1.342mA
-540mV    595.8uA    661.4uA    628.8uA
-480mV    238.4uA    289.2uA    234.4uA
-360mV    9.858uA    18.74uA    8.785uA
0V        0A         0A         0A
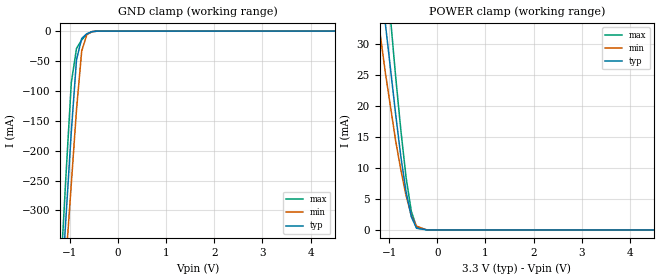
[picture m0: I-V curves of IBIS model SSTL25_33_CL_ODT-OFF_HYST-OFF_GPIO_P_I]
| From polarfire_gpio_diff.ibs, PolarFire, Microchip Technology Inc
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|   Model SSTL25_33_CL_ODT-OFF_HYST-OFF_GPIO_P_I
[Model]   SSTL25_33_CL_ODT-OFF_HYST-OFF_GPIO_P_I
Model_type   Input
Vinl =   1.1
Vinh =   1.4
|   typ   min   max
C_comp_pullup   2.605e-12   2.605e-12   2.76e-12
C_comp_pulldown  2.605e-12   2.605e-12   2.76e-12
[Temperature Range]  25C   100C   -40C
[Voltage Range]  3.3   3.135   3.465
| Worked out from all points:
|   GND clamp passes 1 mA (typ) near -0.55 V on its own axis
|   POWER clamp passes 1 mA (typ) near -0.48 V on its own axis
[GND Clamp]
| Voltage   I(typ)   I(min)   I(max)
-3.3V     -3.213A    -2.957A    -3.541A
-1.299V   -589.3mA   -629.3mA   -557mA
-1.083V   -308.8mA   -380.4mA   -238.7mA
-974.5mV  -168.6mA   -255.9mA   -86.68mA
-866.2mV  -47.95mA   -131.5mA   -29.08mA
-758mV    -12.25mA   -33.2mA    -14.67mA
-649.7mV  -4.29mA    -5.507mA   -5.469mA
-541.4mV  -856.5uA   -891.9uA   -1.147mA
-433.1mV  -54.68uA   -78.42uA   -74.64uA
6.6V      0A         0A         0A
[POWER Clamp]
| Voltage   I(typ)   I(min)   I(max)
-3.3V     269.6mA    218.3mA    322.5mA
-1.408V   58.45mA    45.06mA    74.11mA
-1.299V   49.71mA    38.21mA    63.65mA
-1.191V   41.64mA    31.7mA     53.8mA
-1.083V   33.36mA    25.42mA    43.63mA
-866.2mV  18.58mA    14.32mA    24.63mA
-758mV    11.75mA    9.634mA    16mA
-649.7mV  6.134mA    5.507mA    8.439mA
-541.4mV  2.135mA    2.342mA    3.011mA
-433.1mV  274.1uA    620.8uA    477.7uA
-216.6mV  99.06nA    3.292uA    59.88nA
6.6V      0A         0A         0A
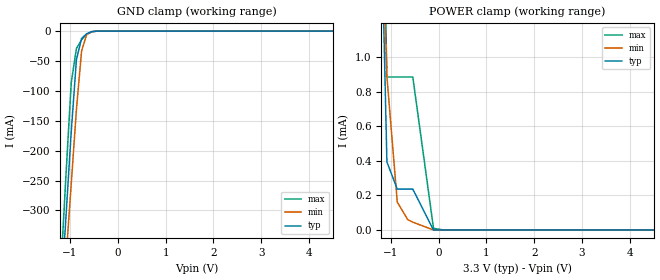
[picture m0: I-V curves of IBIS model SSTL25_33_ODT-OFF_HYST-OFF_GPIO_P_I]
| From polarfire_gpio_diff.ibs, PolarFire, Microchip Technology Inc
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|   Model SSTL25_33_ODT-OFF_HYST-OFF_GPIO_P_I
[Model]   SSTL25_33_ODT-OFF_HYST-OFF_GPIO_P_I
Model_type   Input
Vinl =   1.1
Vinh =   1.4
|   typ   min   max
C_comp_pullup   2.605e-12   2.605e-12   2.76e-12
C_comp_pulldown  2.605e-12   2.605e-12   2.76e-12
[Temperature Range]  25C   100C   -40C
[Voltage Range]  3.3   3.135   3.465
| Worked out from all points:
|   GND clamp passes 1 mA (typ) near -0.55 V on its own axis
|   POWER clamp passes 1 mA (typ) near -1.13 V on its own axis
[GND Clamp]
| Voltage   I(typ)   I(min)   I(max)
-3.3V     -3.213A    -2.957A    -3.541A
-1.299V   -589.3mA   -629.3mA   -557mA
-1.083V   -308.8mA   -380.4mA   -238.7mA
-974.5mV  -168.6mA   -255.9mA   -86.68mA
-866.2mV  -47.95mA   -131.5mA   -29.08mA
-758mV    -12.25mA   -33.2mA    -14.67mA
-649.7mV  -4.29mA    -5.507mA   -5.469mA
-541.4mV  -856.5uA   -891.9uA   -1.147mA
-433.1mV  -54.68uA   -78.42uA   -74.64uA
6.6V      0A         0A         0A
[POWER Clamp]
| Voltage   I(typ)   I(min)   I(max)
-3.3V     115.4mA    80.73mA    157.1mA
-1.191V   1.687mA    1.845mA    2.353mA
-1.083V   393.3uA    886.7uA    884.7uA
-866.2mV  236.1uA    161.1uA    884.7uA
-649.7mV  236.1uA    60.52uA    884.7uA
-541.4mV  236.1uA    45.04uA    884.7uA
-108.3mV  1.95nA     88.87nA    9.589uA
103.1mV   0A         0A         0A
6.6V      0A         0A         0A
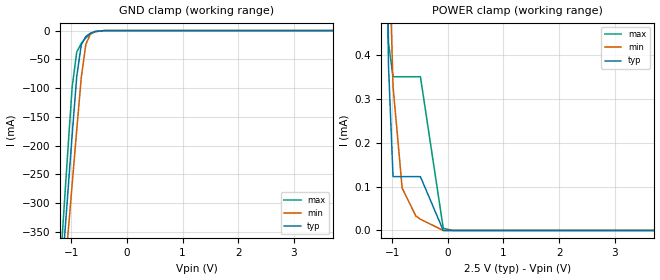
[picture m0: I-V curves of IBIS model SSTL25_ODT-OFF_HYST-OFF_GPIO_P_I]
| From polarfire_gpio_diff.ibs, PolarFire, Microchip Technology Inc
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|   Model SSTL25_ODT-OFF_HYST-OFF_GPIO_P_I
[Model]   SSTL25_ODT-OFF_HYST-OFF_GPIO_P_I
Model_type   Input
Vinl =   1.1
Vinh =   1.4
|   typ   min   max
C_comp_pullup   2.605e-12   2.605e-12   2.76e-12
C_comp_pulldown  2.605e-12   2.605e-12   2.76e-12
[Temperature Range]  25C   100C   -40C
[Voltage Range]  2.5   2.375   2.625
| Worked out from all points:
|   GND clamp passes 1 mA (typ) near -0.54 V on its own axis
|   POWER clamp passes 1 mA (typ) near -1.14 V on its own axis
[GND Clamp]
| Voltage   I(typ)   I(min)   I(max)
-2.5V     -2.154A    -2.019A    -2.333A
-1.23V    -500mA     -550.1mA   -455.7mA
-1.066V   -287.6mA   -361.5mA   -214.6mA
-984.4mV  -181.4mA   -267.2mA   -98.22mA
-902.3mV  -80mA      -172.9mA   -37.38mA
-820.3mV  -24.5mA    -81.44mA   -22.11mA
-738.3mV  -10.19mA   -23.83mA   -12.64mA
-656.2mV  -4.611mA   -6.102mA   -5.883mA
-574.2mV  -1.55mA    -1.632mA   -1.998mA
-410.2mV  -27.4uA    -44.39uA   -33.67uA
5V        0A         0A         0A
[POWER Clamp]
| Voltage   I(typ)   I(min)   I(max)
-2.5V     54.31mA    36.54mA    79.37mA
-1.148V   1.058mA    1.11mA     1.173mA
-1.066V   376.6uA    694.3uA    428.7uA
-984.4mV  122.8uA    328.8uA    350.8uA
-820.3mV  122.8uA    96.7uA     350.8uA
-574.2mV  122.8uA    32.88uA    350.8uA
-492.2mV  122.8uA    25.71uA    350.8uA
-82.03mV  935.3pA    24.07nA    5.104uA
78.12mV   0A         0A         0A
5V        0A         0A         0A
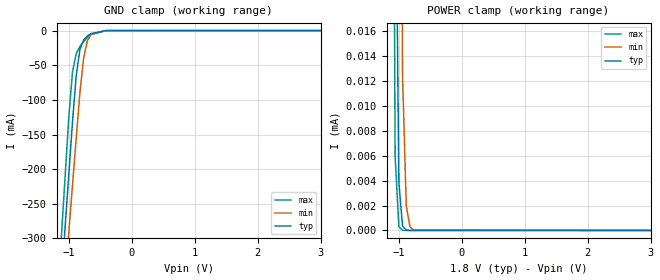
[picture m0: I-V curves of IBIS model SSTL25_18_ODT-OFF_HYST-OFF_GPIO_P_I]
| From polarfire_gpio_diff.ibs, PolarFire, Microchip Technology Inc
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|   Model SSTL25_18_ODT-OFF_HYST-OFF_GPIO_P_I
[Model]   SSTL25_18_ODT-OFF_HYST-OFF_GPIO_P_I
Model_type   Input
Vinl =   1.1
Vinh =   1.4
|   typ   min   max
C_comp_pullup   2.605e-12   2.605e-12   2.76e-12
C_comp_pulldown  2.605e-12   2.605e-12   2.76e-12
[Temperature Range]  25C   100C   -40C
[Voltage Range]  1.8   1.71   1.89
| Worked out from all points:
|   GND clamp passes 1 mA (typ) near -0.55 V on its own axis
[GND Clamp]
| Voltage   I(typ)   I(min)   I(max)
-1.8V     -1.238A    -1.205A    -1.293A
-1.122V   -359.8mA   -425.7mA   -296.5mA
-1.063V   -283.3mA   -357.8mA   -209.8mA
-1.004V   -206.9mA   -289.8mA   -123.9mA
-945mV    -130.4mA   -221.9mA   -58.83mA
-885.9mV  -63.98mA   -154.1mA   -33.04mA
-826.9mV  -26.79mA   -88.02mA   -22.99mA
-767.8mV  -13.47mA   -38.94mA   -15.74mA
-708.7mV  -7.776mA   -14.36mA   -9.878mA
-649.7mV  -4.289mA   -5.506mA   -5.468mA
-413.4mV  -30.28uA   -48.17uA   -37.86uA
3.6V      0A         0A         0A
[POWER Clamp]
| Voltage   I(typ)   I(min)   I(max)
-1.8V     649.5uA    1.043mA    635.3uA
-1.122V   212.8uA    110.4uA    69.31uA
-1.063V   34.52uA    110.4uA    5.908uA
-1.004V   3.863uA    64.08uA    301.7nA
-945mV    344.1nA    12.33uA    13.3nA
-885.9mV  28.92nA    1.971uA    1.2nA
-826.9mV  2.961nA    281.6nA    658.4pA
-767.8mV  808.2pA    39.26nA    599.2pA
3.6V      0A         0A         0A
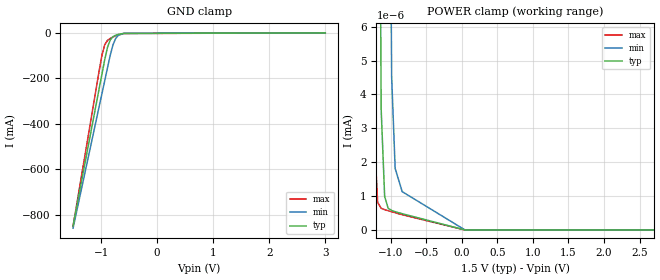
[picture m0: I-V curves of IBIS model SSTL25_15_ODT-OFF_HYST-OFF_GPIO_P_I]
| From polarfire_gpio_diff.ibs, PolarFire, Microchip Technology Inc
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|   Model SSTL25_15_ODT-OFF_HYST-OFF_GPIO_P_I
[Model]   SSTL25_15_ODT-OFF_HYST-OFF_GPIO_P_I
Model_type   Input
Vinl =   1.1
Vinh =   1.4
|   typ   min   max
C_comp_pullup   2.605e-12   2.605e-12   2.76e-12
C_comp_pulldown  2.605e-12   2.605e-12   2.76e-12
[Temperature Range]  25C   100C   -40C
[Voltage Range]  1.5   1.425   1.575
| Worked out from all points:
|   GND clamp passes 1 mA (typ) near -0.55 V on its own axis
[GND Clamp]
| Voltage   I(typ)   I(min)   I(max)
-1.5V     -849.1mA   -859.9mA   -852mA
-1.034V   -245.1mA   -323.8mA   -166.4mA
-984.4mV  -181.4mA   -267.2mA   -98.22mA
-935.2mV  -118mA     -210.6mA   -52.06mA
-885.9mV  -63.98mA   -154.1mA   -33.04mA
-836.7mV  -30.81mA   -98.32mA   -24.37mA
-787.5mV  -16.49mA   -52.6mA    -17.99mA
-738.3mV  -10.19mA   -23.83mA   -12.64mA
-689.1mV  -6.452mA   -10.33mA   -8.24mA
-590.6mV  -2.005mA   -2.157mA   -2.56mA
3V        0A         0A         0A
[POWER Clamp]
| Voltage   I(typ)   I(min)   I(max)
-1.5V     246.9uA    155.6uA    381.6uA
-1.28V    1.469uA    46.77uA    30.19nA
-1.23V    189.5nA    11.47uA    2.761nA
-1.181V   24.12nA    2.481uA    811pA
-1.132V   3.562nA    494.3nA    640.9pA
-1.083V   991.1pA    95.25nA    599.6pA
-1.034V   642.6pA    18.88nA    568.3pA
-984.4mV  574.2pA    4.516nA    538.2pA
-935.2mV  539.7pA    1.816nA    508.6pA
-836.7mV  480.5pA    1.132nA    450.2pA
46.88mV   0A         0A         0A
3V        0A         0A         0A
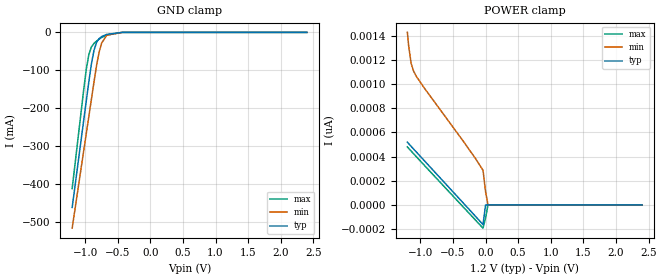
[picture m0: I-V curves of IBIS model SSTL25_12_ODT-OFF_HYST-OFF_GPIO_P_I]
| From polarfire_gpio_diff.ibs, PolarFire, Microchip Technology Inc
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|   Model SSTL25_12_ODT-OFF_HYST-OFF_GPIO_P_I
[Model]   SSTL25_12_ODT-OFF_HYST-OFF_GPIO_P_I
Model_type   Input
Vinl =   1.1
Vinh =   1.4
|   typ   min   max
C_comp_pullup   2.605e-12   2.605e-12   2.76e-12
C_comp_pulldown  2.605e-12   2.605e-12   2.76e-12
[Temperature Range]  25C   100C   -40C
[Voltage Range]  1.2   1.14   1.26
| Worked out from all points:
|   GND clamp passes 1 mA (typ) near -0.55 V on its own axis
[GND Clamp]
| Voltage   I(typ)   I(min)   I(max)
-1.2V     -460.6mA   -515.1mA   -410.9mA
-1.024V   -232.4mA   -312.5mA   -152mA
-984.4mV  -181.4mA   -267.2mA   -98.22mA
-945mV    -130.4mA   -221.9mA   -58.83mA
-905.6mV  -83.47mA   -176.7mA   -38.42mA
-866.2mV  -47.94mA   -131.5mA   -29.07mA
-826.9mV  -26.79mA   -88.02mA   -22.99mA
-787.5mV  -16.49mA   -52.6mA    -17.99mA
-748.1mV  -11.16mA   -28.17mA   -13.63mA
-669.4mV  -5.299mA   -7.508mA   -6.77mA
-433.1mV  -54.61uA   -78.34uA   -74.54uA
2.4V      0A         0A         0A
[POWER Clamp]
| Voltage   I(typ)   I(min)   I(max)
-1.2V     518.8pA    1.426nA    479.3pA
-1.181V   507.5pA    1.319nA    468.3pA
-1.142V   484.2pA    1.169nA    445.1pA
-1.103V   461pA      1.103nA    422pA
-1.063V   437.8pA    1.063nA    399pA
-945mV    368.6pA    969.6pA    330.4pA
-354.4mV  22.93pA    535.7pA    -10.39pA
-157.5mV  -92.47pA   385.8pA    -123.7pA
-39.38mV  -162.4pA   286.2pA    -191.7pA
0V        0A         108.1pA    -106.6pA
37.5mV    0A         0A         0A
2.4V      0A         0A         0A
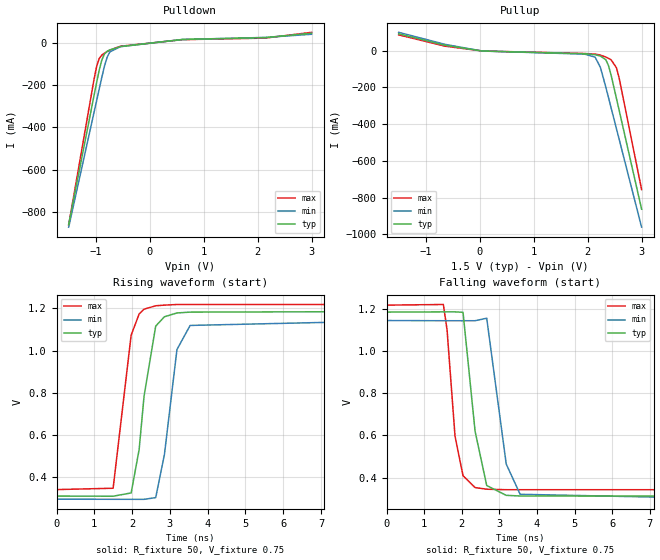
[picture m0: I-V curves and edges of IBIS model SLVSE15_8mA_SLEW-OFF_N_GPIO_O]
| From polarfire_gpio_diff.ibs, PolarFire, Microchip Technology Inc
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|   Model SLVSE15_8mA_SLEW-OFF_N_GPIO_O
[Model]   SLVSE15_8mA_SLEW-OFF_N_GPIO_O
Model_type   Output
Polarity   Inverting
Enable   Active-High
Vmeas =   0.2
Cref =   5p
Rref =   100
|   typ   min   max
C_comp_pullup   2.605e-12   2.605e-12   2.76e-12
C_comp_pulldown  2.605e-12   2.605e-12   2.76e-12
[Temperature Range]  25C   100C   -40C
[Voltage Range]  1.5   1.425   1.575
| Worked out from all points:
|   slope of the pulldown table from 0 to 0.225 V, typ, clamps not added: 34.2 ohm
|   slope of the pullup table from 0 to 0.225 V, typ, clamps not added: 34 ohm
|   rising waveform, R_fixture 50, V_fixture 0.75: 20-80 % time 318ps typ, 341ps min, 304ps max; typ from 0.312 V to 1.19 V
|   falling waveform, R_fixture 50, V_fixture 0.75: 20-80 % time 301ps typ, 349ps min, 242ps max; typ from 1.19 V to 0.312 V
[Pulldown]
| Voltage   I(typ)   I(min)   I(max)
-1.5V     -857.6mA   -869.6mA   -859.7mA
-1.034V   -254.2mA   -333mA     -178.6mA
-984.4mV  -191.2mA   -276.4mA   -114.9mA
-935.2mV  -130.7mA   -219.8mA   -75.07mA
-885.9mV  -81.84mA   -163.6mA   -58.96mA
-836.7mV  -53.8mA    -110.5mA   -49.9mA
-787.5mV  -41.41mA   -68.98mA   -42.17mA
-738.3mV  -34.61mA   -44.12mA   -35.25mA
-541.4mV  -18.7mA    -19.29mA   -17.18mA
609.4mV   14.78mA    14.61mA    13.84mA
2.14V     23.46mA    24.28mA    21.11mA
3V        44.03mA    39.19mA    48.34mA
[Pullup]
| Voltage   I(typ)   I(min)   I(max)
-1.5V     92.43mA    100.2mA    86.37mA
-639.8mV  29.78mA    34.64mA    24.71mA
46.88mV   -1.545mA   -1.684mA   -1.357mA
1.943V    -16.43mA   -18.36mA   -15.21mA
2.14V     -21.65mA   -35.14mA   -17.92mA
2.238V    -29.17mA   -91.86mA   -23.91mA
2.337V    -48.95mA   -197.9mA   -34.44mA
2.386V    -80.32mA   -254.5mA   -41.25mA
2.435V    -132.9mA   -311mA     -49.36mA
2.534V    -259.4mA   -424.2mA   -92.66mA
2.583V    -322.9mA   -480.7mA   -147.5mA
3V        -862.6mA   -960.4mA   -755.7mA
[Ramp]
dV/dt_r   0.523959/0.317622n  0.508564/0.34061n  0.525395/0.304156n
dV/dt_f   0.523956/0.301166n  0.508586/0.349099n  0.525388/0.242305n
R_load = 50
[Rising Waveform]
R_fixture = 50
V_fixture = 0.75
V_fixture_min = 0.7125
V_fixture_max = 0.7875
| Time   V(typ)   V(min)   V(max)
0s        311.9mV    297.1mV    342.6mV
1.498ns   311.2mV    296.7mV    349mV
1.975ns   326.8mV    296.6mV    1.073V
2.186ns   531.7mV    296.5mV    1.173V
2.317ns   785.2mV    296.5mV    1.196V
2.625ns   1.116V     304.7mV    1.212V
2.856ns   1.16V      508.8mV    1.215V
3.187ns   1.178V     1.005V     1.218V
3.536ns   1.182V     1.119V     1.218V
10ns      1.185V     1.145V     1.218V
[Falling Waveform]
R_fixture = 50
V_fixture = 0.75
V_fixture_min = 0.7125
V_fixture_max = 0.7875
| Time   V(typ)   V(min)   V(max)
0s        1.185V     1.145V     1.218V
1.512ns   1.186V     1.144V     1.221V
1.611ns   1.186V     1.144V     1.099V
1.822ns   1.186V     1.144V     596.4mV
2.035ns   1.184V     1.144V     409.3mV
2.356ns   619.5mV    1.144V     352.8mV
2.665ns   362.6mV    1.156V     345.1mV
3.184ns   316mV      464.3mV    342.7mV
3.554ns   313mV      321mV      342.7mV
10ns      311.9mV    297.1mV    342.6mV
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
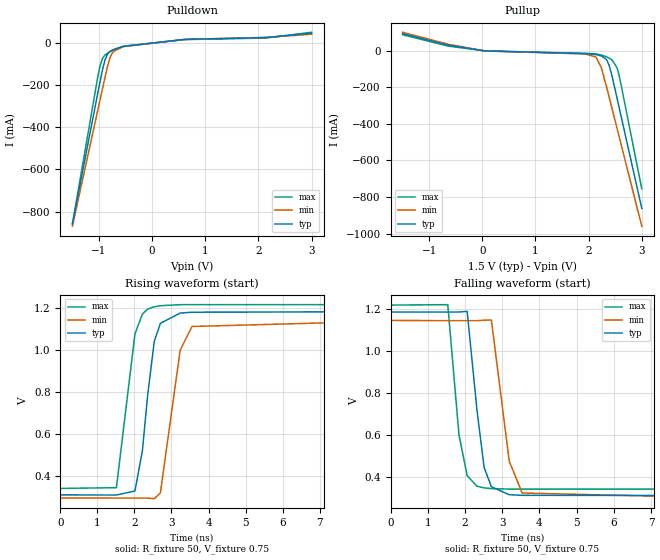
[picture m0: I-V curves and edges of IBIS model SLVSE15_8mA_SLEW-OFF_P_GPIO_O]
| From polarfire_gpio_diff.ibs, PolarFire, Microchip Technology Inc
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|   Model SLVSE15_8mA_SLEW-OFF_P_GPIO_O
[Model]   SLVSE15_8mA_SLEW-OFF_P_GPIO_O
Model_type   Output
Polarity   Non-Inverting
Enable   Active-High
Vmeas =   0.2
Cref =   5p
Rref =   100
|   typ   min   max
C_comp_pullup   2.605e-12   2.605e-12   2.76e-12
C_comp_pulldown  2.605e-12   2.605e-12   2.76e-12
[Temperature Range]  25C   100C   -40C
[Voltage Range]  1.5   1.425   1.575
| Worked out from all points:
|   slope of the pulldown table from 0 to 0.225 V, typ, clamps not added: 34.2 ohm
|   slope of the pullup table from 0 to 0.225 V, typ, clamps not added: 34 ohm
|   rising waveform, R_fixture 50, V_fixture 0.75: 20-80 % time 322ps typ, 347ps min, 308ps max; typ from 0.312 V to 1.19 V
|   falling waveform, R_fixture 50, V_fixture 0.75: 20-80 % time 300ps typ, 339ps min, 244ps max; typ from 1.19 V to 0.312 V
[Pullup]
| Voltage   I(typ)   I(min)   I(max)
-1.5V     92.45mA    100.2mA    86.42mA
-639.8mV  29.78mA    34.63mA    24.7mA
46.88mV   -1.545mA   -1.684mA   -1.357mA
1.943V    -16.43mA   -18.36mA   -15.21mA
2.14V     -21.65mA   -35.14mA   -17.92mA
2.238V    -29.18mA   -91.84mA   -23.91mA
2.337V    -48.94mA   -197.9mA   -34.45mA
2.386V    -80.3mA    -254.4mA   -41.26mA
2.435V    -132.9mA   -311mA     -49.37mA
2.534V    -259.3mA   -424.1mA   -92.63mA
2.583V    -322.9mA   -480.7mA   -147.5mA
3V        -862.5mA   -960.3mA   -755.6mA
[Pulldown]
| Voltage   I(typ)   I(min)   I(max)
-1.5V     -857.5mA   -869.5mA   -859.6mA
-1.034V   -254.2mA   -333mA     -178.5mA
-984.4mV  -191.2mA   -276.4mA   -114.9mA
-935.2mV  -130.6mA   -219.8mA   -75.06mA
-885.9mV  -81.82mA   -163.5mA   -58.97mA
-836.7mV  -53.8mA    -110.4mA   -49.91mA
-787.5mV  -41.42mA   -68.97mA   -42.18mA
-738.3mV  -34.62mA   -44.11mA   -35.26mA
-541.4mV  -18.7mA    -19.29mA   -17.18mA
609.4mV   14.78mA    14.61mA    13.84mA
2.14V     23.45mA    24.27mA    21.1mA
3V        44.04mA    39.2mA     48.39mA
[Ramp]
dV/dt_r   0.523958/0.322109n  0.508586/0.347024n  0.525392/0.308112n
dV/dt_f   0.523957/0.299559n  0.508576/0.33922n  0.525389/0.243508n
R_load = 50
[Rising Waveform]
R_fixture = 50
V_fixture = 0.75
V_fixture_min = 0.7125
V_fixture_max = 0.7875
| Time   V(typ)   V(min)   V(max)
0s        311.9mV    297.1mV    342.6mV
1.512ns   311.2mV    296.8mV    346.3mV
2.013ns   330.4mV    296.7mV    1.079V
2.215ns   523.6mV    296.7mV    1.173V
2.356ns   787mV      296.7mV    1.197V
2.535ns   1.043V     293.8mV    1.208V
2.7ns     1.129V     321.3mV    1.213V
3.234ns   1.178V     1.001V     1.218V
3.554ns   1.182V     1.114V     1.218V
10ns      1.185V     1.145V     1.218V
[Falling Waveform]
R_fixture = 50
V_fixture = 0.75
V_fixture_min = 0.7125
V_fixture_max = 0.7875
| Time   V(typ)   V(min)   V(max)
0s        1.185V     1.145V     1.218V
1.536ns   1.185V     1.144V     1.22V
1.837ns   1.185V     1.144V     600.4mV
2.057ns   1.188V     1.144V     406.9mV
2.317ns   724.4mV    1.144V     356.4mV
2.511ns   446.4mV    1.146V     348.6mV
2.708ns   354mV      1.147V     344.9mV
3.187ns   316mV      476.1mV    342.7mV
3.536ns   313.1mV    324.1mV    342.7mV
10ns      311.9mV    297.1mV    342.6mV
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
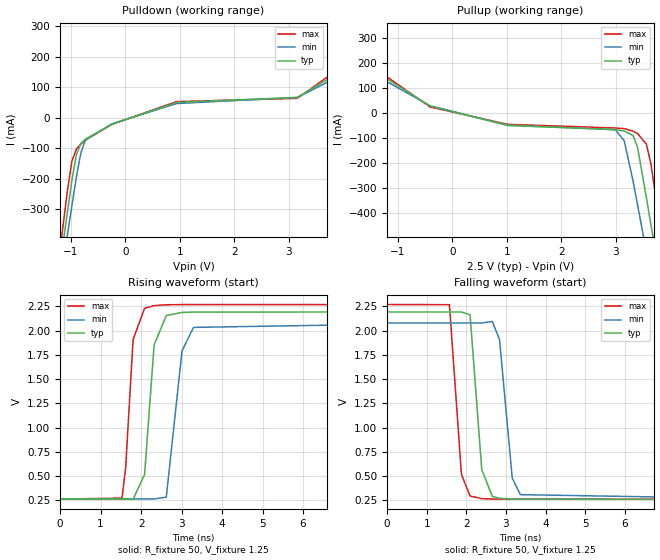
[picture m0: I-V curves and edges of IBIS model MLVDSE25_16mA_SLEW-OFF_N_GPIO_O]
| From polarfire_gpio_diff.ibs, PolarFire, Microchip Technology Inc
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|   Model MLVDSE25_16mA_SLEW-OFF_N_GPIO_O
[Model]   MLVDSE25_16mA_SLEW-OFF_N_GPIO_O
Model_type   Output
Polarity   Inverting
Enable   Active-High
Vmeas =   1.25
Cref =   5p
Rref =   100
|   typ   min   max
C_comp_pullup   2.605e-12   2.605e-12   2.76e-12
C_comp_pulldown  2.605e-12   2.605e-12   2.76e-12
[Temperature Range]  25C   100C   -40C
[Voltage Range]  2.5   2.375   2.625
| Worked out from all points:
|   slope of the pulldown table from 0 to 0.375 V, typ, clamps not added: 14 ohm
|   slope of the pullup table from 0 to 0.375 V, typ, clamps not added: 16.7 ohm
|   rising waveform, R_fixture 50, V_fixture 1.25: 20-80 % time 194ps typ, 225ps min, 163ps max; typ from 0.262 V to 2.19 V
|   falling waveform, R_fixture 50, V_fixture 1.25: 20-80 % time 176ps typ, 215ps min, 161ps max; typ from 2.19 V to 0.262 V
[Pulldown]
| Voltage   I(typ)   I(min)   I(max)
-2.5V     -2.176A    -2.044A    -2.352A
-1.312V   -627.8mA   -667.3mA   -596.9mA
-1.148V   -415.5mA   -478.4mA   -356.6mA
-1.066V   -309.4mA   -383.8mA   -238.8mA
-984.4mV  -205.2mA   -289.2mA   -142.3mA
-902.3mV  -121.7mA   -195.1mA   -102.7mA
-820.3mV  -84.48mA   -115.5mA   -86.92mA
-738.3mV  -70.31mA   -73.7mA    -73.57mA
-246.1mV  -20.77mA   -19.63mA   -21.44mA
937.5mV   50.43mA    46.62mA    53.06mA
3.156V    66.84mA    66.73mA    63.69mA
5V        263.2mA    232.8mA    297.4mA
[Pullup]
| Voltage   I(typ)   I(min)   I(max)
-2.5V     314.9mA    283.8mA    343mA
-410.2mV  29.2mA     29.88mA    25.04mA
1.016V    -48.96mA   -47.26mA   -44.25mA
2.992V    -64.92mA   -66.02mA   -58.94mA
3.156V    -70.95mA   -108.9mA   -61.16mA
3.32V     -89.11mA   -270.8mA   -71.52mA
3.402V    -135.6mA   -365.1mA   -80.66mA
3.566V    -338.4mA   -553.8mA   -124mA
3.648V    -444.4mA   -648.2mA   -202.9mA
3.812V    -656.7mA   -836.9mA   -438.5mA
3.977V    -869.2mA   -1.026A    -678.9mA
5V        -2.206A    -2.216A    -2.19A
[Ramp]
dV/dt_r   1.15846/0.193968n  1.08912/0.225265n  1.20296/0.163454n
dV/dt_f   1.15845/0.175849n  1.08911/0.21485n  1.20296/0.161436n
R_load = 50
[Rising Waveform]
R_fixture = 50
V_fixture = 1.25
V_fixture_min = 1.1875
V_fixture_max = 1.3125
| Time   V(typ)   V(min)   V(max)
0s        261.7mV    264.1mV    263.6mV
1.527ns   261.5mV    264.7mV    273.1mV
1.617ns   261.5mV    264.8mV    577.8mV
1.802ns   260.6mV    264.8mV    1.907V
2.086ns   516.5mV    265mV      2.23V
2.322ns   1.853V     264.7mV    2.258V
2.622ns   2.155V     282.7mV    2.266V
3.012ns   2.187V     1.793V     2.268V
3.295ns   2.191V     2.033V     2.268V
10ns      2.192V     2.079V     2.269V
[Falling Waveform]
R_fixture = 50
V_fixture = 1.25
V_fixture_min = 1.1875
V_fixture_max = 1.3125
| Time   V(typ)   V(min)   V(max)
0s        2.192V     2.079V     2.269V
1.575ns   2.192V     2.079V     2.267V
1.878ns   2.192V     2.079V     519.3mV
2.096ns   2.163V     2.079V     295.7mV
2.391ns   568.2mV    2.078V     269mV
2.657ns   292mV      2.094V     264.9mV
2.839ns   272.7mV    1.908V     264.1mV
3.161ns   263.6mV    480.3mV    264.1mV
3.366ns   262.4mV    309.9mV    264.1mV
10ns      261.7mV    264.1mV    263.6mV
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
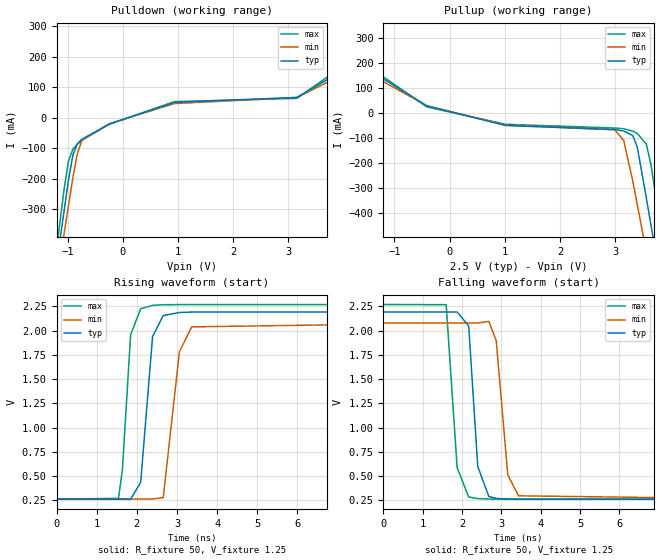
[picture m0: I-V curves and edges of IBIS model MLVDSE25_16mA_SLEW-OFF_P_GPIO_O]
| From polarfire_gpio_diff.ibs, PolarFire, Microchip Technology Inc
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|   Model MLVDSE25_16mA_SLEW-OFF_P_GPIO_O
[Model]   MLVDSE25_16mA_SLEW-OFF_P_GPIO_O
Model_type   Output
Polarity   Non-Inverting
Enable   Active-High
Vmeas =   1.25
Cref =   5p
Rref =   100
|   typ   min   max
C_comp_pullup   2.605e-12   2.605e-12   2.76e-12
C_comp_pulldown  2.605e-12   2.605e-12   2.76e-12
[Temperature Range]  25C   100C   -40C
[Voltage Range]  2.5   2.375   2.625
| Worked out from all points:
|   slope of the pulldown table from 0 to 0.375 V, typ, clamps not added: 14 ohm
|   slope of the pullup table from 0 to 0.375 V, typ, clamps not added: 16.7 ohm
|   rising waveform, R_fixture 50, V_fixture 1.25: 20-80 % time 197ps typ, 233ps min, 165ps max; typ from 0.262 V to 2.19 V
|   falling waveform, R_fixture 50, V_fixture 1.25: 20-80 % time 173ps typ, 212ps min, 162ps max; typ from 2.19 V to 0.262 V
[Pullup]
| Voltage   I(typ)   I(min)   I(max)
-2.5V     314.9mA    283.8mA    343mA
-410.2mV  29.2mA     29.88mA    25.04mA
1.016V    -48.96mA   -47.26mA   -44.25mA
2.992V    -64.92mA   -66.02mA   -58.94mA
3.156V    -70.96mA   -108.8mA   -61.74mA
3.32V     -89.11mA   -270.8mA   -71.53mA
3.402V    -135.6mA   -365.1mA   -80.67mA
3.566V    -338.3mA   -553.8mA   -124mA
3.648V    -444.3mA   -648.1mA   -202.8mA
3.812V    -656.6mA   -836.8mA   -438.4mA
3.977V    -869.1mA   -1.026A    -678.8mA
5V        -2.206A    -2.216A    -2.19A
[Pulldown]
| Voltage   I(typ)   I(min)   I(max)
-2.5V     -2.176A    -2.043A    -2.352A
-1.312V   -627.7mA   -667.3mA   -596.8mA
-1.148V   -415.4mA   -478.3mA   -356.5mA
-1.066V   -309.4mA   -383.8mA   -238.8mA
-984.4mV  -205.2mA   -289.2mA   -142.2mA
-902.3mV  -121.7mA   -195mA     -102.7mA
-820.3mV  -84.48mA   -115.5mA   -86.92mA
-738.3mV  -70.31mA   -73.7mA    -73.57mA
-246.1mV  -20.77mA   -19.63mA   -21.44mA
937.5mV   50.43mA    46.62mA    53.06mA
3.156V    66.83mA    66.72mA    63.69mA
5V        263.2mA    232.8mA    297.4mA
[Ramp]
dV/dt_r   1.15846/0.197184n  1.08911/0.232997n  1.20296/0.165345n
dV/dt_f   1.15845/0.172724n  1.08912/0.211717n  1.20296/0.161967n
R_load = 50
[Rising Waveform]
R_fixture = 50
V_fixture = 1.25
V_fixture_min = 1.1875
V_fixture_max = 1.3125
| Time   V(typ)   V(min)   V(max)
0s        261.7mV    264.1mV    263.6mV
1.543ns   261.5mV    263.5mV    269.2mV
1.64ns    261.5mV    263.5mV    565.1mV
1.845ns   259.9mV    263.4mV    1.956V
2.096ns   436.9mV    263.3mV    2.226V
2.391ns   1.936V     263.1mV    2.26V
2.657ns   2.155V     277.8mV    2.267V
3.061ns   2.187V     1.784V     2.268V
3.366ns   2.191V     2.038V     2.268V
10ns      2.192V     2.079V     2.269V
[Falling Waveform]
R_fixture = 50
V_fixture = 1.25
V_fixture_min = 1.1875
V_fixture_max = 1.3125
| Time   V(typ)   V(min)   V(max)
0s        2.192V     2.079V     2.269V
1.596ns   2.192V     2.079V     2.267V
1.875ns   2.192V     2.079V     588.5mV
2.169ns   2.047V     2.078V     285.4mV
2.399ns   600.4mV    2.078V     269.3mV
2.681ns   291mV      2.095V     264.9mV
2.869ns   271.7mV    1.896V     264.2mV
3.163ns   263.9mV    511.9mV    264.1mV
3.437ns   262.2mV    297.9mV    264.1mV
10ns      261.7mV    264.1mV    263.6mV
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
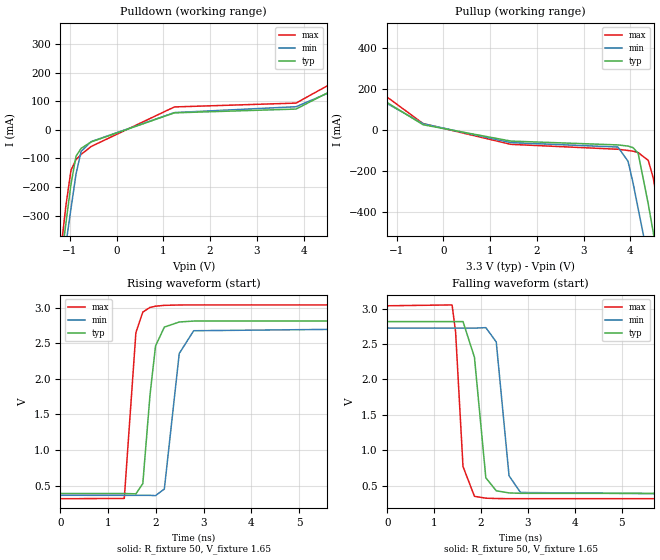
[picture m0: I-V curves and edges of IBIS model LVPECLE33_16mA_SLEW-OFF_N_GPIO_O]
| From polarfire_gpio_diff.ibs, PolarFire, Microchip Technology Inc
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|   Model LVPECLE33_16mA_SLEW-OFF_N_GPIO_O
[Model]   LVPECLE33_16mA_SLEW-OFF_N_GPIO_O
Model_type   Output
Polarity   Inverting
Enable   Active-High
Vmeas =   1.65
Cref =   5p
Rref =   100
|   typ   min   max
C_comp_pullup   2.605e-12   2.605e-12   2.76e-12
C_comp_pulldown  2.605e-12   2.605e-12   2.76e-12
[Temperature Range]  25C   100C   -40C
[Voltage Range]  3.3   3.135   3.465
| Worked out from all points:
|   slope of the pulldown table from 0 to 0.495 V, typ, clamps not added: 16 ohm
|   slope of the pullup table from 0 to 0.495 V, typ, clamps not added: 20.7 ohm
|   rising waveform, R_fixture 50, V_fixture 1.65: 20-80 % time 178ps typ, 202ps min, 136ps max; typ from 0.389 V to 2.82 V
|   falling waveform, R_fixture 50, V_fixture 1.65: 20-80 % time 174ps typ, 178ps min, 131ps max; typ from 2.82 V to 0.389 V
[Pulldown]
| Voltage   I(typ)   I(min)   I(max)
-3.3V     -3.233A    -2.98A     -3.563A
-1.191V   -467.4mA   -525.2mA   -421.1mA
-1.083V   -327.3mA   -400.5mA   -264.9mA
-974.5mV  -190.4mA   -275.6mA   -141.6mA
-866.2mV  -92.33mA   -154.5mA   -104.5mA
-758mV    -65.3mA    -75.74mA   -86.42mA
-541.4mV  -42.48mA   -41.6mA    -58.51mA
1.238V    58.96mA    59.83mA    79.59mA
3.841V    72.17mA    80.37mA    93.04mA
4.708V    145.2mA    140.5mA    171.5mA
6.007V    310.5mA    287.8mA    365.2mA
6.6V      407.6mA    374.5mA    471.6mA
[Pullup]
| Voltage   I(typ)   I(min)   I(max)
-3.3V     427mA      396.9mA    511mA
-433.1mV  24.19mA    29.02mA    29.79mA
1.444V    -55.61mA   -63.1mA    -71.57mA
3.733V    -74.41mA   -84.7mA    -95.52mA
3.95V     -79.96mA   -154.1mA   -101.6mA
4.058V    -87.8mA    -260.9mA   -104.9mA
4.166V    -115mA     -385.2mA   -111.7mA
4.383V    -363.9mA   -634.4mA   -149.9mA
4.491V    -503.9mA   -758.9mA   -237.6mA
4.599V    -644mA     -883.6mA   -386.1mA
4.816V    -924.6mA   -1.133A    -703.2mA
6.6V      -3.278A    -3.233A    -3.372A
[Ramp]
dV/dt_r   1.45721/0.178348n  1.41779/0.202206n  1.63559/0.135712n
dV/dt_f   1.45721/0.173569n  1.41779/0.177509n  1.63559/0.131163n
R_load = 50
[Rising Waveform]
R_fixture = 50
V_fixture = 1.65
V_fixture_min = 1.5675
V_fixture_max = 1.7325
| Time   V(typ)   V(min)   V(max)
0s        388.9mV    363.2mV    315.5mV
1.337ns   388.5mV    362.8mV    318.9mV
1.58ns    383.6mV    362.7mV    2.651V
1.725ns   527.4mV    362.7mV    2.94V
1.875ns   1.769V     362.6mV    3.006V
1.991ns   2.462V     358.4mV    3.023V
2.176ns   2.729V     451.4mV    3.035V
2.488ns   2.801V     2.358V     3.04V
2.79ns    2.814V     2.678V     3.041V
10ns      2.818V     2.726V     3.041V
[Falling Waveform]
R_fixture = 50
V_fixture = 1.65
V_fixture_min = 1.5675
V_fixture_max = 1.7325
| Time   V(typ)   V(min)   V(max)
0s        2.818V     2.726V     3.041V
1.381ns   2.817V     2.726V     3.053V
1.456ns   2.817V     2.726V     2.672V
1.614ns   2.818V     2.726V     769.2mV
1.858ns   2.314V     2.725V     349.1mV
2.101ns   611mV      2.732V     322.8mV
2.323ns   427.4mV    2.53V      317.7mV
2.596ns   397.2mV    639mV      316mV
2.841ns   391.5mV    402.9mV    315.5mV
10ns      389mV      363.2mV    315.5mV
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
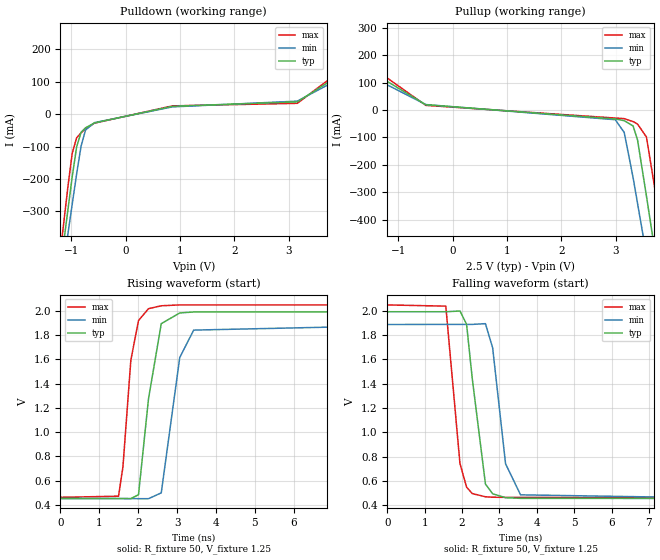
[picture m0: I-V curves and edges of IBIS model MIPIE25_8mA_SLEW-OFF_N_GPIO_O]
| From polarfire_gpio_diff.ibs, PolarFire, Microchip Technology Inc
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|   Model MIPIE25_8mA_SLEW-OFF_N_GPIO_O
[Model]   MIPIE25_8mA_SLEW-OFF_N_GPIO_O
Model_type   Output
Polarity   Inverting
Enable   Active-High
Vmeas =   0.2
Cref =   5p
Rref =   100
|   typ   min   max
C_comp_pullup   2.605e-12   2.605e-12   2.76e-12
C_comp_pulldown  2.605e-12   2.605e-12   2.76e-12
[Temperature Range]  25C   100C   -40C
[Voltage Range]  2.5   2.375   2.625
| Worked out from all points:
|   slope of the pulldown table from 0 to 0.375 V, typ, clamps not added: 27.6 ohm
|   slope of the pullup table from 0 to 0.375 V, typ, clamps not added: 33.1 ohm
|   rising waveform, R_fixture 50, V_fixture 1.25: 20-80 % time 281ps typ, 339ps min, 241ps max; typ from 0.455 V to 1.99 V
|   falling waveform, R_fixture 50, V_fixture 1.25: 20-80 % time 279ps typ, 307ps min, 250ps max; typ from 1.99 V to 0.455 V
[Pulldown]
| Voltage   I(typ)   I(min)   I(max)
-2.5V     -2.166A    -2.031A    -2.343A
-1.23V    -511.5mA   -561.7mA   -467.7mA
-1.148V   -405.4mA   -467.3mA   -347.6mA
-1.066V   -299.4mA   -372.9mA   -228.6mA
-984.4mV  -194.1mA   -278.5mA   -121.3mA
-902.3mV  -100.9mA   -184.2mA   -72.85mA
-820.3mV  -55.78mA   -98.16mA   -57.48mA
-738.3mV  -42.04mA   -48.96mA   -45.5mA
-574.2mV  -27.1mA    -26.06mA   -27.71mA
859.4mV   24.29mA    22.45mA    25.54mA
3.156V    37.94mA    40.13mA    33.42mA
5V        233.3mA    205.1mA    266.2mA
[Pullup]
| Voltage   I(typ)   I(min)   I(max)
-2.5V     259.2mA    222.9mA    299.1mA
-492.2mV  19.08mA    19.75mA    16.79mA
2.992V    -32.89mA   -35.61mA   -29.52mA
3.156V    -38.96mA   -81.66mA   -31.69mA
3.32V     -58.4mA    -246.6mA   -42.27mA
3.402V    -109.4mA   -340.9mA   -51.56mA
3.566V    -314.5mA   -529.5mA   -98.69mA
3.73V     -526.6mA   -718.1mA   -299.3mA
3.812V    -632.7mA   -812.4mA   -419.3mA
3.895V    -738.9mA   -906.8mA   -539.5mA
3.977V    -845.1mA   -1.001A    -659.6mA
5V        -2.181A    -2.19A     -2.171A
[Ramp]
dV/dt_r   0.920739/0.28096n  0.858875/0.339128n  0.948946/0.24148n
dV/dt_f   0.920735/0.278827n  0.858869/0.306702n  0.948944/0.249958n
R_load = 50
[Rising Waveform]
R_fixture = 50
V_fixture = 1.25
V_fixture_min = 1.1875
V_fixture_max = 1.3125
| Time   V(typ)   V(min)   V(max)
0s        455.3mV    453.8mV    464.2mV
1.493ns   455mV      453.3mV    473.6mV
1.607ns   455mV      453.3mV    715.4mV
1.81ns    453.5mV    453.2mV    1.592V
2.007ns   485.6mV    453.1mV    1.918V
2.264ns   1.274V     453mV      2.015V
2.592ns   1.892V     501.1mV    2.039V
3.067ns   1.98V      1.613V     2.046V
3.425ns   1.988V     1.839V     2.046V
10ns      1.99V      1.885V     2.046V
[Falling Waveform]
R_fixture = 50
V_fixture = 1.25
V_fixture_min = 1.1875
V_fixture_max = 1.3125
| Time   V(typ)   V(min)   V(max)
0s        1.99V      1.885V     2.046V
1.565ns   1.99V      1.886V     2.036V
1.944ns   1.996V     1.886V     743.1mV
2.121ns   1.887V     1.886V     548.9mV
2.272ns   1.444V     1.886V     495.9mV
2.626ns   574.2mV    1.892V     469.5mV
2.819ns   493.9mV    1.693V     465.9mV
3.164ns   462.3mV    741.1mV    464.5mV
3.565ns   456.6mV    485.5mV    464.1mV
10ns      455.3mV    453.8mV    464.2mV
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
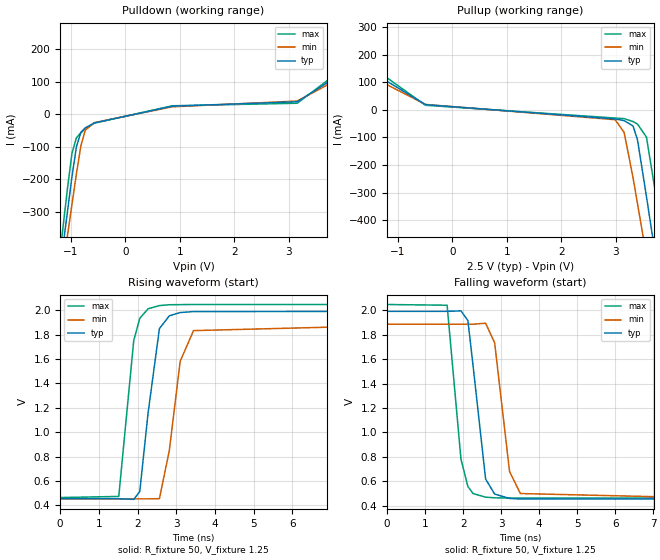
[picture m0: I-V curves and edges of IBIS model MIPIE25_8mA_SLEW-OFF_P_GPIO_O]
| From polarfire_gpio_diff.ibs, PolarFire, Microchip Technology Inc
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|   Model MIPIE25_8mA_SLEW-OFF_P_GPIO_O
[Model]   MIPIE25_8mA_SLEW-OFF_P_GPIO_O
Model_type   Output
Polarity   Non-Inverting
Enable   Active-High
Vmeas =   0.2
Cref =   5p
Rref =   100
|   typ   min   max
C_comp_pullup   2.605e-12   2.605e-12   2.76e-12
C_comp_pulldown  2.605e-12   2.605e-12   2.76e-12
[Temperature Range]  25C   100C   -40C
[Voltage Range]  2.5   2.375   2.625
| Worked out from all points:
|   slope of the pulldown table from 0 to 0.375 V, typ, clamps not added: 27.6 ohm
|   slope of the pullup table from 0 to 0.375 V, typ, clamps not added: 33.1 ohm
|   rising waveform, R_fixture 50, V_fixture 1.25: 20-80 % time 285ps typ, 349ps min, 244ps max; typ from 0.455 V to 1.99 V
|   falling waveform, R_fixture 50, V_fixture 1.25: 20-80 % time 277ps typ, 302ps min, 249ps max; typ from 1.99 V to 0.455 V
[Pullup]
| Voltage   I(typ)   I(min)   I(max)
-2.5V     259.3mA    222.9mA    299.1mA
-492.2mV  19.08mA    19.75mA    16.79mA
2.992V    -32.89mA   -35.61mA   -29.52mA
3.156V    -38.96mA   -81.65mA   -31.69mA
3.32V     -58.4mA    -246.6mA   -42.27mA
3.402V    -109.4mA   -340.8mA   -51.57mA
3.566V    -314.5mA   -529.4mA   -98.67mA
3.73V     -526.5mA   -718mA     -299.2mA
3.812V    -632.6mA   -812.3mA   -419.3mA
3.895V    -738.8mA   -906.7mA   -539.4mA
4.059V    -951.3mA   -1.096A    -779.8mA
5V        -2.181A    -2.19A     -2.17A
[Pulldown]
| Voltage   I(typ)   I(min)   I(max)
-2.5V     -2.165A    -2.031A    -2.343A
-1.23V    -511.4mA   -561.6mA   -467.6mA
-1.148V   -405.4mA   -467.3mA   -347.6mA
-1.066V   -299.4mA   -372.9mA   -228.5mA
-984.4mV  -194mA     -278.4mA   -121.3mA
-902.3mV  -100.9mA   -184.2mA   -72.85mA
-820.3mV  -55.78mA   -98.14mA   -57.49mA
-738.3mV  -42.04mA   -48.96mA   -45.5mA
-574.2mV  -27.1mA    -26.06mA   -27.71mA
859.4mV   24.29mA    22.45mA    25.54mA
3.156V    37.94mA    40.13mA    33.42mA
5V        233.3mA    205.1mA    266.2mA
[Ramp]
dV/dt_r   0.920739/0.285323n  0.858874/0.349468n  0.948946/0.243507n
dV/dt_f   0.920735/0.277447n  0.858868/0.302171n  0.948943/0.248624n
R_load = 50
[Rising Waveform]
R_fixture = 50
V_fixture = 1.25
V_fixture_min = 1.1875
V_fixture_max = 1.3125
| Time   V(typ)   V(min)   V(max)
0s        455.3mV    453.8mV    464.2mV
1.514ns   454.6mV    453.6mV    473.3mV
1.901ns   449.6mV    453.5mV    1.751V
2.057ns   514.2mV    453.5mV    1.933V
2.272ns   1.159V     453.5mV    2.011V
2.564ns   1.848V     455.2mV    2.037V
2.819ns   1.953V     847.9mV    2.044V
3.101ns   1.98V      1.581V     2.045V
3.445ns   1.988V     1.832V     2.046V
10ns      1.99V      1.885V     2.046V
[Falling Waveform]
R_fixture = 50
V_fixture = 1.25
V_fixture_min = 1.1875
V_fixture_max = 1.3125
| Time   V(typ)   V(min)   V(max)
0s        1.99V      1.885V     2.046V
1.58ns    1.99V      1.885V     2.04V
1.944ns   1.994V     1.885V     783.3mV
2.127ns   1.915V     1.885V     558.1mV
2.264ns   1.542V     1.885V     501.2mV
2.592ns   619.9mV    1.893V     471.3mV
2.83ns    496.7mV    1.733V     466.3mV
3.222ns   461.2mV    681.2mV    464.4mV
3.507ns   456.8mV    501.1mV    464.4mV
10ns      455.3mV    453.8mV    464.2mV
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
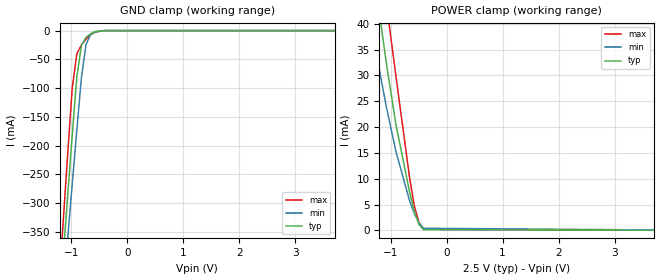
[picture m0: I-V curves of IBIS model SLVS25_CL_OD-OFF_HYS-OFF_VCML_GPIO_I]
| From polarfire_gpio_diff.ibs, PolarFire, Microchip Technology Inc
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|   Model SLVS25_CL_OD-OFF_HYS-OFF_VCML_GPIO_I
[Model]   SLVS25_CL_OD-OFF_HYS-OFF_VCML_GPIO_I
Model_type   Input
Vinl =   0.075
Vinh =   0.325
|   typ   min   max
C_comp_pullup   2.605e-12   2.605e-12   2.76e-12
C_comp_pulldown  2.605e-12   2.605e-12   2.76e-12
[Temperature Range]  25C   100C   -40C
[Voltage Range]  2.5   2.375   2.625
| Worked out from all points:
|   GND clamp passes 1 mA (typ) near -0.52 V on its own axis
|   POWER clamp passes 1 mA (typ) near -0.48 V on its own axis
[GND Clamp]
| Voltage   I(typ)   I(min)   I(max)
-2.5V     -2.154A    -2.019A    -2.334A
-1.312V   -606.5mA   -644.5mA   -576.7mA
-1.148V   -394.1mA   -456mA     -335.8mA
-1.066V   -288mA     -361.7mA   -215.7mA
-984.4mV  -181.9mA   -267.4mA   -99.94mA
-902.3mV  -80.78mA   -173.2mA   -40.34mA
-820.3mV  -25.8mA    -81.78mA   -25.07mA
-738.3mV  -11.65mA   -24.31mA   -14.68mA
-656.2mV  -5.525mA   -6.674mA   -7.068mA
-574.2mV  -1.954mA   -1.999mA   -2.52mA
-410.2mV  -41.8uA    -66.55uA   -50.18uA
5V        0A         0A         0A
[POWER Clamp]
| Voltage   I(typ)   I(min)   I(max)
-2.5V     170mA      132.1mA    211.8mA
-1.477V   65.86mA    48.78mA    86.2mA
-1.312V   51.57mA    38.03mA    68.04mA
-1.23V    44.71mA    32.95mA    59.41mA
-1.148V   38.06mA    28.08mA    51.15mA
-1.066V   31.71mA    23.47mA    43.26mA
-902.3mV  20.41mA    15.22mA    29.75mA
-656.2mV  7.231mA    5.583mA    9.915mA
-574.2mV  3.588mA    3.288mA    4.716mA
-492.2mV  1.145mA    1.483mA    1.487mA
-410.2mV  170.6uA    421.6uA    220.4uA
5V        0A         0A         0A
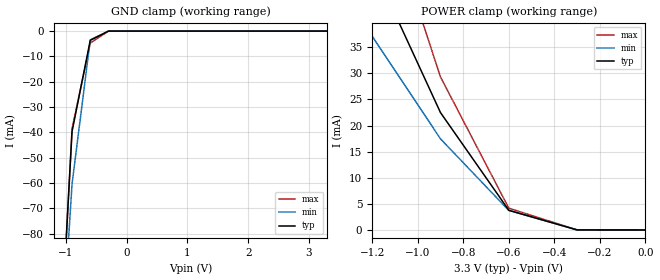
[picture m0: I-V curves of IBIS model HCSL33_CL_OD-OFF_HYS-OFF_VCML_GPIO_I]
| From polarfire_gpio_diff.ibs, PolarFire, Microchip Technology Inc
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|   Model HCSL33_CL_OD-OFF_HYS-OFF_VCML_GPIO_I
[Model]   HCSL33_CL_OD-OFF_HYS-OFF_VCML_GPIO_I
Model_type   Input
Vinl =   0.225
Vinh =   0.475
|   typ   min   max
C_comp_pullup   2.605e-12   2.605e-12   2.76e-12
C_comp_pulldown  2.605e-12   2.605e-12   2.76e-12
[Temperature Range]  25C   100C   -40C
[Voltage Range]  3.3   3.15   3.45
[GND_clamp]
|Voltage   I(typ)   I(min)   I(max)
-1.8V     -463.2mA   -408.7mA   -523.6mA
-1.2V     -171.2mA   -174.2mA   -177.2mA
-900mV    -39.7mA    -60.43mA   -38.53mA
-600mV    -3.657mA   -3.442mA   -4.73mA
-300mV    -2.517uA   -9.735uA   -1.044uA
3.3V      1.341uA    1.798uA    1.108uA
[POWER_clamp]
|Voltage   I(typ)   I(min)   I(max)
-3.3V     410.6mA    333.1mA    508mA
-3V       342.4mA    274.4mA    434mA
-2.7V     283.6mA    221.8mA    365.8mA
-2.4V     228.4mA    175.3mA    298.9mA
-2.1V     176.1mA    133mA      234.8mA
-1.8V     128.3mA    95.36mA    175.2mA
-1.5V     86.43mA    63.24mA    119.9mA
-1.2V     50.84mA    37.1mA     69.35mA
-900mV    22.47mA    17.45mA    29.29mA
-600mV    3.773mA    3.733mA    4.175mA
-300mV    6.226uA    20.37uA    3.158uA
0V        0A         0A         0A
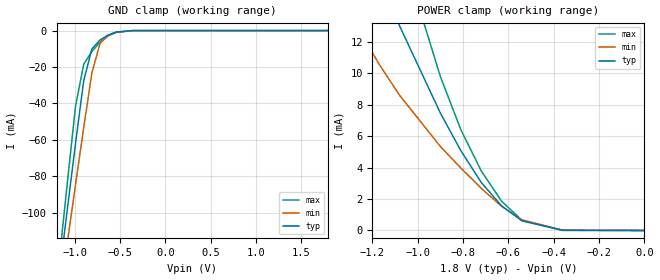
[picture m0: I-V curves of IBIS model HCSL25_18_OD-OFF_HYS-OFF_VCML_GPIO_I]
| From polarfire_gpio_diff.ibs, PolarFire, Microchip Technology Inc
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|   Model HCSL25_18_OD-OFF_HYS-OFF_VCML_GPIO_I
[Model]   HCSL25_18_OD-OFF_HYS-OFF_VCML_GPIO_I
Model_type   Input
Vinl =   0.225
Vinh =   0.475
|   typ   min   max
C_comp_pullup   2.605e-12   2.605e-12   2.76e-12
C_comp_pulldown  2.605e-12   2.605e-12   2.76e-12
[Temperature Range]  25C   100C   -40C
[Voltage Range]  1.8   1.71   1.89
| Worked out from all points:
|   GND clamp passes 1 mA (typ) near -0.55 V on its own axis
|   POWER clamp passes 1 mA (typ) near -0.58 V on its own axis
[GND_clamp]
|Voltage   I(typ)   I(min)   I(max)
-1.8V     -400.9mA   -379.8mA   -437.5mA
-1.17V    -134.2mA   -147.8mA   -125.8mA
-1.08V    -97.7mA    -115.9mA   -83.09mA
-990mV    -61.78mA   -84.35mA   -41.33mA
-900mV    -27.45mA   -53.17mA   -18.47mA
-810mV    -10.06mA   -23.34mA   -11.43mA
-720mV    -5.122mA   -7.016mA   -6.424mA
-630mV    -2.387mA   -2.536mA   -2.907mA
-540mV    -812.6uA   -895.6uA   -914.9uA
-360mV    -11.27uA   -22.35uA   -9.971uA
1.8V      703.8nA    823.4nA    606.9nA
[POWER_clamp]
|Voltage   I(typ)   I(min)   I(max)
-1.8V     43.47mA    30.55mA    65.7mA
-1.44V    26.56mA    17.78mA    40.91mA
-1.26V    19.47mA    12.78mA    28.82mA
-1.17V    16.17mA    10.57mA    23.39mA
-1.08V    13.01mA    8.597mA    18.22mA
-900mV    7.463mA    5.343mA    9.787mA
-810mV    5.079mA    3.976mA    6.415mA
-720mV    3.058mA    2.687mA    3.796mA
-630mV    1.563mA    1.536mA    1.86mA
-540mV    609.2uA    674.8uA    644.4uA
-360mV    10.61uA    19.82uA    9.534uA
0V        0A         0A         0A
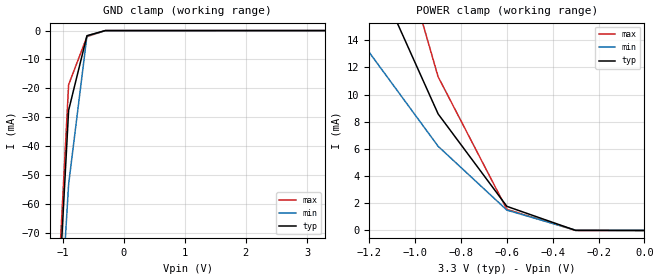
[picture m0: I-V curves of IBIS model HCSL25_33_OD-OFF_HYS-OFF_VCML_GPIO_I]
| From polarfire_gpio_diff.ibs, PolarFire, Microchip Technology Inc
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|   HCSL25_33_OD-OFF_HYS-OFF_VCML_GPIO_I
[Model]   HCSL25_33_OD-OFF_HYS-OFF_VCML_GPIO_I
Model_type  Input
Vinl =   0.225
Vinh =   0.475
|   typ   min   max
C_comp_pullup   2.605e-12   2.605e-12   2.76e-12
C_comp_pulldown  2.605e-12   2.605e-12   2.76e-12
[Temperature Range]  25C   100C   -40C
[Voltage Range]  3.3V   3.15V   3.45V
[GND_clamp]
|Voltage   I(typ)   I(min)   I(max)
-3.3V     -1.138A    -1.018A    -1.313A
-1.2V     -147.1mA   -159mA     -141.3mA
-900mV    -27.64mA   -53.3mA    -18.77mA
-600mV    -1.775mA   -1.87mA    -2.115mA
-300mV    -1.462uA   -4.313uA   -854.3nA
3.3V      1.341uA    1.798uA    1.108uA
[POWER_clamp]
|Voltage   I(typ)   I(min)   I(max)
-3.3V     238mA      182.9mA    319.1mA
-3V       189mA      142.2mA    262.9mA
-2.7V     150.7mA    108.6mA    215.8mA
-2.4V     116.7mA    82.12mA    171.9mA
-2.1V     85.28mA    59.16mA    128.7mA
-1.8V     55.36mA    38.84mA    85.19mA
-1.5V     34.04mA    23.18mA    52.5mA
-1.2V     19.85mA    13.1mA     28.9mA
-900mV    8.583mA    6.201mA    11.32mA
-600mV    1.775mA    1.5mA      1.556mA
-300mV    6.226uA    20.37uA    3.158uA
0V        0A         0A         0A
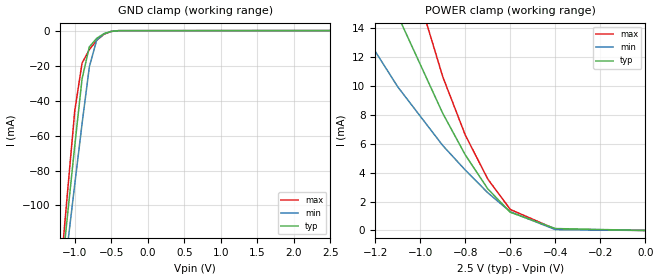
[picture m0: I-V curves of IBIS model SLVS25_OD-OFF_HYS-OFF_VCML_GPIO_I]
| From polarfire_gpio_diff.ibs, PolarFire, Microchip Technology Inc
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|   SLVS25_OD-OFF_HYS-OFF_VCML_GPIO_I
[Model]   SLVS25_OD-OFF_HYS-OFF_VCML_GPIO_I
Model_type  Input
Vinl =   0.075
Vinh =   0.325
|   typ   min   max
C_comp_pullup   2.605e-12   2.605e-12   2.76e-12
C_comp_pulldown  2.605e-12   2.605e-12   2.76e-12
[Temperature Range]  25C   100C   -40C
[Voltage Range]  2.5V   2.375V   2.625V
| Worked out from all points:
|   GND clamp passes 1 mA (typ) near -0.54 V on its own axis
|   POWER clamp passes 1 mA (typ) near -0.57 V on its own axis
[GND_clamp]
|Voltage   I(typ)   I(min)   I(max)
-2.5V     -723.9mA   -659.4mA   -817.8mA
-1.2V     -146.7mA   -158.7mA   -140.6mA
-1.1V     -105.9mA   -123.1mA   -92.83mA
-1V       -65.86mA   -87.91mA   -45.89mA
-900mV    -27.52mA   -53.22mA   -18.58mA
-800mV    -9.29mA    -20.66mA   -10.86mA
-700mV    -4.426mA   -5.484mA   -5.547mA
-600mV    -1.758mA   -1.853mA   -2.095mA
-500mV    -435uA     -508.5uA   -470uA
-400mV    -42.38uA   -66.25uA   -43.62uA
2.5V      1.001uA    1.272uA    839.9nA
[POWER_clamp]
|Voltage   I(typ)   I(min)   I(max)
-2.5V     120.1mA    85.6mA     174.4mA
-1.5V     32mA       21.9mA     49.19mA
-1.4V     27.2mA     18.31mA    41.4mA
-1.3V     22.82mA    15.18mA    34.09mA
-1.2V     18.73mA    12.4mA     27.22mA
-1.1V     14.89mA    9.944mA    20.96mA
-900mV    8.105mA    5.879mA    10.64mA
-800mV    5.232mA    4.182mA    6.605mA
-700mV    2.88mA     2.609mA    3.559mA
-600mV    1.26mA     1.294mA    1.454mA
-400mV    133.1uA    61.02uA    95.02uA
0V        0A         0A         0A
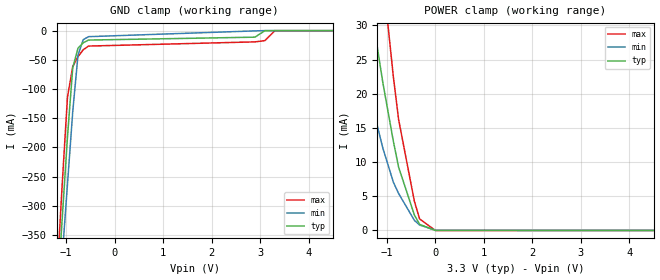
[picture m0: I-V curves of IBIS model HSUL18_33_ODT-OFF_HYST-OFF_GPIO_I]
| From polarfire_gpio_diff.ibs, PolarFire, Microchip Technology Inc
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|   HSUL18_33_ODT-OFF_HYST-OFF_GPIO_I
[Model]   HSUL18_33_ODT-OFF_HYST-OFF_GPIO_I
Model_type  Input
Vinl =   0.54
Vinh =   1.26
|   typ   min   max
C_comp_pullup   2.605e-12   2.605e-12   2.76e-12
C_comp_pulldown  2.605e-12   2.605e-12   2.76e-12
[Temperature Range]   25   100   -40
[Voltage Range]   3.3   3.135   3.465
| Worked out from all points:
|   POWER clamp passes 1 mA (typ) near -0.33 V on its own axis
[GND Clamp]
| Voltage   I(typ)   I(min)   I(max)
-3.3V     -3.241A    -2.973A    -3.586A
-1.191V   -462.5mA   -512.5mA   -422.3mA
-1.083V   -322.3mA   -387.9mA   -263.4mA
-974.5mV  -182.3mA   -263.4mA   -114.1mA
-866.2mV  -64.02mA   -139.1mA   -61.49mA
-758mV    -30.07mA   -42.24mA   -44.6mA
-649.7mV  -20.81mA   -15.47mA   -32.73mA
-541.4mV  -16.11mA   -10.3mA    -26.41mA
2.888V    -11.16mA   -389.5uA   -19.22mA
3.094V    -104.3uA   82.37uA    -17.05mA
3.3V      142uA      0A         -71.42uA
6.6V      0A         0A         0A
[POWER Clamp]
| Voltage   I(typ)   I(min)   I(max)
-3.3V     176.4mA    145.1mA    236mA
-1.949V   72.64mA    47.28mA    106.8mA
-1.732V   57.83mA    36.73mA    88.19mA
-1.408V   37.91mA    22.7mA     61.37mA
-1.191V   26.56mA    15.14mA    44.98mA
-1.083V   21.65mA    12.06mA    37.3mA
-866.2mV  13.05mA    7.068mA    22.5mA
-758mV    9.269mA    5.417mA    16.25mA
-433.1mV  2.269mA    1.484mA    4.274mA
-324.8mV  889.1uA    798.2uA    1.69mA
0V        0A         39.55uA    0A
6.6V      0A         0A         0A
